VERSION 5.8 ;
BUSBITCHARS "[]" ;
DIVIDERCHAR "/" ;
UNITS
    DATABASE MICRONS 1000 ;
END UNITS

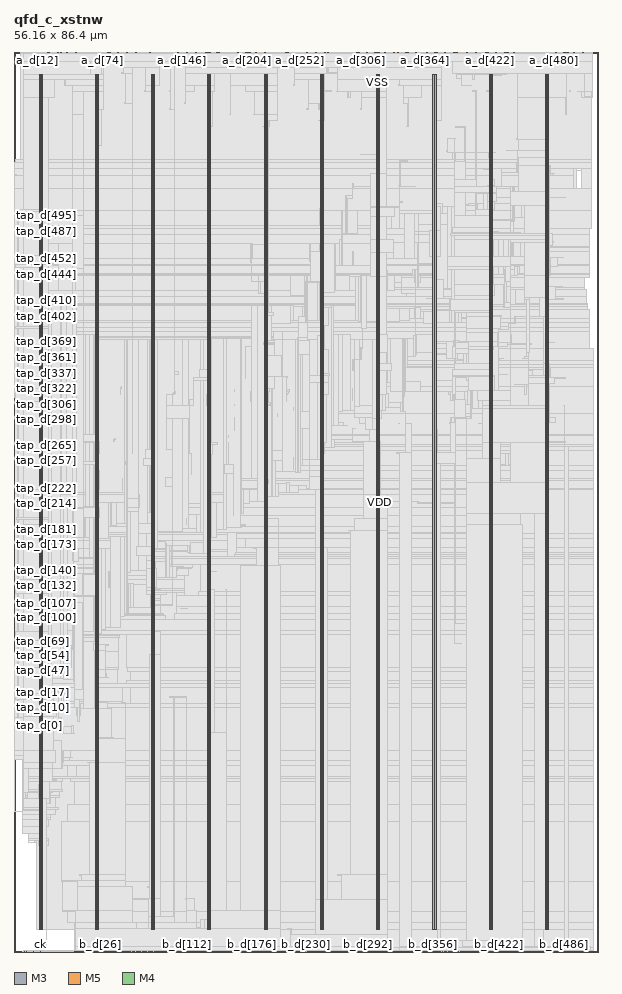
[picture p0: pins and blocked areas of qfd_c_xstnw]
MACRO qfd_c_xstnw
  FOREIGN qfd_c_xstnw 0 0 ;
  CLASS BLOCK ;
  SIZE 56.16 BY 86.4 ;
  PIN a_d[0]
    DIRECTION OUTPUT ;
    USE SIGNAL ;
    PORT
      LAYER M3 ;
        RECT  0.576 86.362 0.594 86.4 ;
    END
  END a_d[0]
  PIN a_d[100]
    DIRECTION OUTPUT ;
    USE SIGNAL ;
    PORT
      LAYER M3 ;
        RECT  11.268 86.362 11.286 86.4 ;
    END
  END a_d[100]
  PIN a_d[101]
    DIRECTION OUTPUT ;
    USE SIGNAL ;
    PORT
      LAYER M5 ;
        RECT  11.376 86.316 11.4 86.4 ;
    END
  END a_d[101]
  PIN a_d[102]
    DIRECTION OUTPUT ;
    USE SIGNAL ;
    PORT
      LAYER M3 ;
        RECT  11.484 86.362 11.502 86.4 ;
    END
  END a_d[102]
  PIN a_d[103]
    DIRECTION OUTPUT ;
    USE SIGNAL ;
    PORT
      LAYER M5 ;
        RECT  11.568 86.316 11.592 86.4 ;
    END
  END a_d[103]
  PIN a_d[104]
    DIRECTION OUTPUT ;
    USE SIGNAL ;
    PORT
      LAYER M3 ;
        RECT  11.7 86.362 11.718 86.4 ;
    END
  END a_d[104]
  PIN a_d[105]
    DIRECTION OUTPUT ;
    USE SIGNAL ;
    PORT
      LAYER M5 ;
        RECT  11.808 86.316 11.832 86.4 ;
    END
  END a_d[105]
  PIN a_d[106]
    DIRECTION OUTPUT ;
    USE SIGNAL ;
    PORT
      LAYER M3 ;
        RECT  11.916 86.362 11.934 86.4 ;
    END
  END a_d[106]
  PIN a_d[107]
    DIRECTION OUTPUT ;
    USE SIGNAL ;
    PORT
      LAYER M5 ;
        RECT  12 86.316 12.024 86.4 ;
    END
  END a_d[107]
  PIN a_d[108]
    DIRECTION OUTPUT ;
    USE SIGNAL ;
    PORT
      LAYER M3 ;
        RECT  12.096 86.362 12.114 86.4 ;
    END
  END a_d[108]
  PIN a_d[109]
    DIRECTION OUTPUT ;
    USE SIGNAL ;
    PORT
      LAYER M5 ;
        RECT  12.24 86.316 12.264 86.4 ;
    END
  END a_d[109]
  PIN a_d[10]
    DIRECTION OUTPUT ;
    USE SIGNAL ;
    PORT
      LAYER M3 ;
        RECT  1.656 86.362 1.674 86.4 ;
    END
  END a_d[10]
  PIN a_d[110]
    DIRECTION OUTPUT ;
    USE SIGNAL ;
    PORT
      LAYER M3 ;
        RECT  12.312 86.362 12.33 86.4 ;
    END
  END a_d[110]
  PIN a_d[111]
    DIRECTION OUTPUT ;
    USE SIGNAL ;
    PORT
      LAYER M5 ;
        RECT  12.432 86.316 12.456 86.4 ;
    END
  END a_d[111]
  PIN a_d[112]
    DIRECTION OUTPUT ;
    USE SIGNAL ;
    PORT
      LAYER M3 ;
        RECT  12.528 86.362 12.546 86.4 ;
    END
  END a_d[112]
  PIN a_d[113]
    DIRECTION OUTPUT ;
    USE SIGNAL ;
    PORT
      LAYER M5 ;
        RECT  12.624 86.316 12.648 86.4 ;
    END
  END a_d[113]
  PIN a_d[114]
    DIRECTION OUTPUT ;
    USE SIGNAL ;
    PORT
      LAYER M3 ;
        RECT  12.744 86.362 12.762 86.4 ;
    END
  END a_d[114]
  PIN a_d[115]
    DIRECTION OUTPUT ;
    USE SIGNAL ;
    PORT
      LAYER M5 ;
        RECT  12.864 86.316 12.888 86.4 ;
    END
  END a_d[115]
  PIN a_d[116]
    DIRECTION OUTPUT ;
    USE SIGNAL ;
    PORT
      LAYER M3 ;
        RECT  12.96 86.362 12.978 86.4 ;
    END
  END a_d[116]
  PIN a_d[117]
    DIRECTION OUTPUT ;
    USE SIGNAL ;
    PORT
      LAYER M5 ;
        RECT  13.056 86.316 13.08 86.4 ;
    END
  END a_d[117]
  PIN a_d[118]
    DIRECTION OUTPUT ;
    USE SIGNAL ;
    PORT
      LAYER M3 ;
        RECT  13.176 86.362 13.194 86.4 ;
    END
  END a_d[118]
  PIN a_d[119]
    DIRECTION OUTPUT ;
    USE SIGNAL ;
    PORT
      LAYER M5 ;
        RECT  13.296 86.316 13.32 86.4 ;
    END
  END a_d[119]
  PIN a_d[11]
    DIRECTION OUTPUT ;
    USE SIGNAL ;
    PORT
      LAYER M5 ;
        RECT  1.776 86.316 1.8 86.4 ;
    END
  END a_d[11]
  PIN a_d[120]
    DIRECTION OUTPUT ;
    USE SIGNAL ;
    PORT
      LAYER M3 ;
        RECT  13.392 86.362 13.41 86.4 ;
    END
  END a_d[120]
  PIN a_d[121]
    DIRECTION OUTPUT ;
    USE SIGNAL ;
    PORT
      LAYER M5 ;
        RECT  13.488 86.316 13.512 86.4 ;
    END
  END a_d[121]
  PIN a_d[122]
    DIRECTION OUTPUT ;
    USE SIGNAL ;
    PORT
      LAYER M3 ;
        RECT  13.608 86.362 13.626 86.4 ;
    END
  END a_d[122]
  PIN a_d[123]
    DIRECTION OUTPUT ;
    USE SIGNAL ;
    PORT
      LAYER M5 ;
        RECT  13.728 86.316 13.752 86.4 ;
    END
  END a_d[123]
  PIN a_d[124]
    DIRECTION OUTPUT ;
    USE SIGNAL ;
    PORT
      LAYER M3 ;
        RECT  13.824 86.362 13.842 86.4 ;
    END
  END a_d[124]
  PIN a_d[125]
    DIRECTION OUTPUT ;
    USE SIGNAL ;
    PORT
      LAYER M5 ;
        RECT  13.92 86.316 13.944 86.4 ;
    END
  END a_d[125]
  PIN a_d[126]
    DIRECTION OUTPUT ;
    USE SIGNAL ;
    PORT
      LAYER M3 ;
        RECT  14.04 86.362 14.058 86.4 ;
    END
  END a_d[126]
  PIN a_d[127]
    DIRECTION OUTPUT ;
    USE SIGNAL ;
    PORT
      LAYER M5 ;
        RECT  14.16 86.316 14.184 86.4 ;
    END
  END a_d[127]
  PIN a_d[128]
    DIRECTION OUTPUT ;
    USE SIGNAL ;
    PORT
      LAYER M3 ;
        RECT  14.256 86.362 14.274 86.4 ;
    END
  END a_d[128]
  PIN a_d[129]
    DIRECTION OUTPUT ;
    USE SIGNAL ;
    PORT
      LAYER M5 ;
        RECT  14.352 86.316 14.376 86.4 ;
    END
  END a_d[129]
  PIN a_d[12]
    DIRECTION OUTPUT ;
    USE SIGNAL ;
    PORT
      LAYER M3 ;
        RECT  1.872 86.362 1.89 86.4 ;
    END
  END a_d[12]
  PIN a_d[130]
    DIRECTION OUTPUT ;
    USE SIGNAL ;
    PORT
      LAYER M3 ;
        RECT  14.472 86.362 14.49 86.4 ;
    END
  END a_d[130]
  PIN a_d[131]
    DIRECTION OUTPUT ;
    USE SIGNAL ;
    PORT
      LAYER M5 ;
        RECT  14.544 86.316 14.568 86.4 ;
    END
  END a_d[131]
  PIN a_d[132]
    DIRECTION OUTPUT ;
    USE SIGNAL ;
    PORT
      LAYER M3 ;
        RECT  14.688 86.362 14.706 86.4 ;
    END
  END a_d[132]
  PIN a_d[133]
    DIRECTION OUTPUT ;
    USE SIGNAL ;
    PORT
      LAYER M5 ;
        RECT  14.784 86.316 14.808 86.4 ;
    END
  END a_d[133]
  PIN a_d[134]
    DIRECTION OUTPUT ;
    USE SIGNAL ;
    PORT
      LAYER M3 ;
        RECT  14.904 86.362 14.922 86.4 ;
    END
  END a_d[134]
  PIN a_d[135]
    DIRECTION OUTPUT ;
    USE SIGNAL ;
    PORT
      LAYER M5 ;
        RECT  14.976 86.316 15 86.4 ;
    END
  END a_d[135]
  PIN a_d[136]
    DIRECTION OUTPUT ;
    USE SIGNAL ;
    PORT
      LAYER M3 ;
        RECT  15.12 86.362 15.138 86.4 ;
    END
  END a_d[136]
  PIN a_d[137]
    DIRECTION OUTPUT ;
    USE SIGNAL ;
    PORT
      LAYER M5 ;
        RECT  15.216 86.316 15.24 86.4 ;
    END
  END a_d[137]
  PIN a_d[138]
    DIRECTION OUTPUT ;
    USE SIGNAL ;
    PORT
      LAYER M3 ;
        RECT  15.3 86.362 15.318 86.4 ;
    END
  END a_d[138]
  PIN a_d[139]
    DIRECTION OUTPUT ;
    USE SIGNAL ;
    PORT
      LAYER M5 ;
        RECT  15.408 86.316 15.432 86.4 ;
    END
  END a_d[139]
  PIN a_d[13]
    DIRECTION OUTPUT ;
    USE SIGNAL ;
    PORT
      LAYER M5 ;
        RECT  1.968 86.316 1.992 86.4 ;
    END
  END a_d[13]
  PIN a_d[140]
    DIRECTION OUTPUT ;
    USE SIGNAL ;
    PORT
      LAYER M3 ;
        RECT  15.516 86.362 15.534 86.4 ;
    END
  END a_d[140]
  PIN a_d[141]
    DIRECTION OUTPUT ;
    USE SIGNAL ;
    PORT
      LAYER M5 ;
        RECT  15.648 86.316 15.672 86.4 ;
    END
  END a_d[141]
  PIN a_d[142]
    DIRECTION OUTPUT ;
    USE SIGNAL ;
    PORT
      LAYER M3 ;
        RECT  15.732 86.362 15.75 86.4 ;
    END
  END a_d[142]
  PIN a_d[143]
    DIRECTION OUTPUT ;
    USE SIGNAL ;
    PORT
      LAYER M5 ;
        RECT  15.84 86.316 15.864 86.4 ;
    END
  END a_d[143]
  PIN a_d[144]
    DIRECTION OUTPUT ;
    USE SIGNAL ;
    PORT
      LAYER M3 ;
        RECT  15.948 86.362 15.966 86.4 ;
    END
  END a_d[144]
  PIN a_d[145]
    DIRECTION OUTPUT ;
    USE SIGNAL ;
    PORT
      LAYER M5 ;
        RECT  16.08 86.316 16.104 86.4 ;
    END
  END a_d[145]
  PIN a_d[146]
    DIRECTION OUTPUT ;
    USE SIGNAL ;
    PORT
      LAYER M3 ;
        RECT  16.164 86.362 16.182 86.4 ;
    END
  END a_d[146]
  PIN a_d[147]
    DIRECTION OUTPUT ;
    USE SIGNAL ;
    PORT
      LAYER M5 ;
        RECT  16.272 86.316 16.296 86.4 ;
    END
  END a_d[147]
  PIN a_d[148]
    DIRECTION OUTPUT ;
    USE SIGNAL ;
    PORT
      LAYER M3 ;
        RECT  16.38 86.362 16.398 86.4 ;
    END
  END a_d[148]
  PIN a_d[149]
    DIRECTION OUTPUT ;
    USE SIGNAL ;
    PORT
      LAYER M5 ;
        RECT  16.464 86.316 16.488 86.4 ;
    END
  END a_d[149]
  PIN a_d[14]
    DIRECTION OUTPUT ;
    USE SIGNAL ;
    PORT
      LAYER M3 ;
        RECT  2.088 86.362 2.106 86.4 ;
    END
  END a_d[14]
  PIN a_d[150]
    DIRECTION OUTPUT ;
    USE SIGNAL ;
    PORT
      LAYER M3 ;
        RECT  16.596 86.362 16.614 86.4 ;
    END
  END a_d[150]
  PIN a_d[151]
    DIRECTION OUTPUT ;
    USE SIGNAL ;
    PORT
      LAYER M5 ;
        RECT  16.704 86.316 16.728 86.4 ;
    END
  END a_d[151]
  PIN a_d[152]
    DIRECTION OUTPUT ;
    USE SIGNAL ;
    PORT
      LAYER M3 ;
        RECT  16.812 86.362 16.83 86.4 ;
    END
  END a_d[152]
  PIN a_d[153]
    DIRECTION OUTPUT ;
    USE SIGNAL ;
    PORT
      LAYER M5 ;
        RECT  16.896 86.316 16.92 86.4 ;
    END
  END a_d[153]
  PIN a_d[154]
    DIRECTION OUTPUT ;
    USE SIGNAL ;
    PORT
      LAYER M3 ;
        RECT  17.028 86.362 17.046 86.4 ;
    END
  END a_d[154]
  PIN a_d[155]
    DIRECTION OUTPUT ;
    USE SIGNAL ;
    PORT
      LAYER M5 ;
        RECT  17.136 86.316 17.16 86.4 ;
    END
  END a_d[155]
  PIN a_d[156]
    DIRECTION OUTPUT ;
    USE SIGNAL ;
    PORT
      LAYER M3 ;
        RECT  17.244 86.362 17.262 86.4 ;
    END
  END a_d[156]
  PIN a_d[157]
    DIRECTION OUTPUT ;
    USE SIGNAL ;
    PORT
      LAYER M5 ;
        RECT  17.328 86.316 17.352 86.4 ;
    END
  END a_d[157]
  PIN a_d[158]
    DIRECTION OUTPUT ;
    USE SIGNAL ;
    PORT
      LAYER M3 ;
        RECT  17.46 86.362 17.478 86.4 ;
    END
  END a_d[158]
  PIN a_d[159]
    DIRECTION OUTPUT ;
    USE SIGNAL ;
    PORT
      LAYER M5 ;
        RECT  17.568 86.316 17.592 86.4 ;
    END
  END a_d[159]
  PIN a_d[15]
    DIRECTION OUTPUT ;
    USE SIGNAL ;
    PORT
      LAYER M5 ;
        RECT  2.16 86.316 2.184 86.4 ;
    END
  END a_d[15]
  PIN a_d[160]
    DIRECTION OUTPUT ;
    USE SIGNAL ;
    PORT
      LAYER M3 ;
        RECT  17.676 86.362 17.694 86.4 ;
    END
  END a_d[160]
  PIN a_d[161]
    DIRECTION OUTPUT ;
    USE SIGNAL ;
    PORT
      LAYER M5 ;
        RECT  17.76 86.316 17.784 86.4 ;
    END
  END a_d[161]
  PIN a_d[162]
    DIRECTION OUTPUT ;
    USE SIGNAL ;
    PORT
      LAYER M3 ;
        RECT  17.892 86.362 17.91 86.4 ;
    END
  END a_d[162]
  PIN a_d[163]
    DIRECTION OUTPUT ;
    USE SIGNAL ;
    PORT
      LAYER M5 ;
        RECT  18 86.316 18.024 86.4 ;
    END
  END a_d[163]
  PIN a_d[164]
    DIRECTION OUTPUT ;
    USE SIGNAL ;
    PORT
      LAYER M3 ;
        RECT  18.108 86.362 18.126 86.4 ;
    END
  END a_d[164]
  PIN a_d[165]
    DIRECTION OUTPUT ;
    USE SIGNAL ;
    PORT
      LAYER M5 ;
        RECT  18.192 86.316 18.216 86.4 ;
    END
  END a_d[165]
  PIN a_d[166]
    DIRECTION OUTPUT ;
    USE SIGNAL ;
    PORT
      LAYER M3 ;
        RECT  18.288 86.362 18.306 86.4 ;
    END
  END a_d[166]
  PIN a_d[167]
    DIRECTION OUTPUT ;
    USE SIGNAL ;
    PORT
      LAYER M5 ;
        RECT  18.432 86.316 18.456 86.4 ;
    END
  END a_d[167]
  PIN a_d[168]
    DIRECTION OUTPUT ;
    USE SIGNAL ;
    PORT
      LAYER M3 ;
        RECT  18.504 86.362 18.522 86.4 ;
    END
  END a_d[168]
  PIN a_d[169]
    DIRECTION OUTPUT ;
    USE SIGNAL ;
    PORT
      LAYER M5 ;
        RECT  18.624 86.316 18.648 86.4 ;
    END
  END a_d[169]
  PIN a_d[16]
    DIRECTION OUTPUT ;
    USE SIGNAL ;
    PORT
      LAYER M3 ;
        RECT  2.304 86.362 2.322 86.4 ;
    END
  END a_d[16]
  PIN a_d[170]
    DIRECTION OUTPUT ;
    USE SIGNAL ;
    PORT
      LAYER M3 ;
        RECT  18.72 86.362 18.738 86.4 ;
    END
  END a_d[170]
  PIN a_d[171]
    DIRECTION OUTPUT ;
    USE SIGNAL ;
    PORT
      LAYER M5 ;
        RECT  18.816 86.316 18.84 86.4 ;
    END
  END a_d[171]
  PIN a_d[172]
    DIRECTION OUTPUT ;
    USE SIGNAL ;
    PORT
      LAYER M3 ;
        RECT  18.936 86.362 18.954 86.4 ;
    END
  END a_d[172]
  PIN a_d[173]
    DIRECTION OUTPUT ;
    USE SIGNAL ;
    PORT
      LAYER M5 ;
        RECT  19.056 86.316 19.08 86.4 ;
    END
  END a_d[173]
  PIN a_d[174]
    DIRECTION OUTPUT ;
    USE SIGNAL ;
    PORT
      LAYER M3 ;
        RECT  19.152 86.362 19.17 86.4 ;
    END
  END a_d[174]
  PIN a_d[175]
    DIRECTION OUTPUT ;
    USE SIGNAL ;
    PORT
      LAYER M5 ;
        RECT  19.248 86.316 19.272 86.4 ;
    END
  END a_d[175]
  PIN a_d[176]
    DIRECTION OUTPUT ;
    USE SIGNAL ;
    PORT
      LAYER M3 ;
        RECT  19.368 86.362 19.386 86.4 ;
    END
  END a_d[176]
  PIN a_d[177]
    DIRECTION OUTPUT ;
    USE SIGNAL ;
    PORT
      LAYER M5 ;
        RECT  19.488 86.316 19.512 86.4 ;
    END
  END a_d[177]
  PIN a_d[178]
    DIRECTION OUTPUT ;
    USE SIGNAL ;
    PORT
      LAYER M3 ;
        RECT  19.584 86.362 19.602 86.4 ;
    END
  END a_d[178]
  PIN a_d[179]
    DIRECTION OUTPUT ;
    USE SIGNAL ;
    PORT
      LAYER M5 ;
        RECT  19.68 86.316 19.704 86.4 ;
    END
  END a_d[179]
  PIN a_d[17]
    DIRECTION OUTPUT ;
    USE SIGNAL ;
    PORT
      LAYER M5 ;
        RECT  2.4 86.316 2.424 86.4 ;
    END
  END a_d[17]
  PIN a_d[180]
    DIRECTION OUTPUT ;
    USE SIGNAL ;
    PORT
      LAYER M3 ;
        RECT  19.8 86.362 19.818 86.4 ;
    END
  END a_d[180]
  PIN a_d[181]
    DIRECTION OUTPUT ;
    USE SIGNAL ;
    PORT
      LAYER M5 ;
        RECT  19.92 86.316 19.944 86.4 ;
    END
  END a_d[181]
  PIN a_d[182]
    DIRECTION OUTPUT ;
    USE SIGNAL ;
    PORT
      LAYER M3 ;
        RECT  20.016 86.362 20.034 86.4 ;
    END
  END a_d[182]
  PIN a_d[183]
    DIRECTION OUTPUT ;
    USE SIGNAL ;
    PORT
      LAYER M5 ;
        RECT  20.112 86.316 20.136 86.4 ;
    END
  END a_d[183]
  PIN a_d[184]
    DIRECTION OUTPUT ;
    USE SIGNAL ;
    PORT
      LAYER M3 ;
        RECT  20.232 86.362 20.25 86.4 ;
    END
  END a_d[184]
  PIN a_d[185]
    DIRECTION OUTPUT ;
    USE SIGNAL ;
    PORT
      LAYER M5 ;
        RECT  20.352 86.316 20.376 86.4 ;
    END
  END a_d[185]
  PIN a_d[186]
    DIRECTION OUTPUT ;
    USE SIGNAL ;
    PORT
      LAYER M3 ;
        RECT  20.448 86.362 20.466 86.4 ;
    END
  END a_d[186]
  PIN a_d[187]
    DIRECTION OUTPUT ;
    USE SIGNAL ;
    PORT
      LAYER M5 ;
        RECT  20.544 86.316 20.568 86.4 ;
    END
  END a_d[187]
  PIN a_d[188]
    DIRECTION OUTPUT ;
    USE SIGNAL ;
    PORT
      LAYER M3 ;
        RECT  20.664 86.362 20.682 86.4 ;
    END
  END a_d[188]
  PIN a_d[189]
    DIRECTION OUTPUT ;
    USE SIGNAL ;
    PORT
      LAYER M5 ;
        RECT  20.736 86.316 20.76 86.4 ;
    END
  END a_d[189]
  PIN a_d[18]
    DIRECTION OUTPUT ;
    USE SIGNAL ;
    PORT
      LAYER M3 ;
        RECT  2.52 86.362 2.538 86.4 ;
    END
  END a_d[18]
  PIN a_d[190]
    DIRECTION OUTPUT ;
    USE SIGNAL ;
    PORT
      LAYER M3 ;
        RECT  20.88 86.362 20.898 86.4 ;
    END
  END a_d[190]
  PIN a_d[191]
    DIRECTION OUTPUT ;
    USE SIGNAL ;
    PORT
      LAYER M5 ;
        RECT  20.976 86.316 21 86.4 ;
    END
  END a_d[191]
  PIN a_d[192]
    DIRECTION OUTPUT ;
    USE SIGNAL ;
    PORT
      LAYER M3 ;
        RECT  21.096 86.362 21.114 86.4 ;
    END
  END a_d[192]
  PIN a_d[193]
    DIRECTION OUTPUT ;
    USE SIGNAL ;
    PORT
      LAYER M5 ;
        RECT  21.168 86.316 21.192 86.4 ;
    END
  END a_d[193]
  PIN a_d[194]
    DIRECTION OUTPUT ;
    USE SIGNAL ;
    PORT
      LAYER M3 ;
        RECT  21.276 86.362 21.294 86.4 ;
    END
  END a_d[194]
  PIN a_d[195]
    DIRECTION OUTPUT ;
    USE SIGNAL ;
    PORT
      LAYER M5 ;
        RECT  21.408 86.316 21.432 86.4 ;
    END
  END a_d[195]
  PIN a_d[196]
    DIRECTION OUTPUT ;
    USE SIGNAL ;
    PORT
      LAYER M3 ;
        RECT  21.492 86.362 21.51 86.4 ;
    END
  END a_d[196]
  PIN a_d[197]
    DIRECTION OUTPUT ;
    USE SIGNAL ;
    PORT
      LAYER M5 ;
        RECT  21.6 86.316 21.624 86.4 ;
    END
  END a_d[197]
  PIN a_d[198]
    DIRECTION OUTPUT ;
    USE SIGNAL ;
    PORT
      LAYER M3 ;
        RECT  21.708 86.362 21.726 86.4 ;
    END
  END a_d[198]
  PIN a_d[199]
    DIRECTION OUTPUT ;
    USE SIGNAL ;
    PORT
      LAYER M5 ;
        RECT  21.84 86.316 21.864 86.4 ;
    END
  END a_d[199]
  PIN a_d[19]
    DIRECTION OUTPUT ;
    USE SIGNAL ;
    PORT
      LAYER M5 ;
        RECT  2.592 86.316 2.616 86.4 ;
    END
  END a_d[19]
  PIN a_d[1]
    DIRECTION OUTPUT ;
    USE SIGNAL ;
    PORT
      LAYER M5 ;
        RECT  0.672 86.316 0.696 86.4 ;
    END
  END a_d[1]
  PIN a_d[200]
    DIRECTION OUTPUT ;
    USE SIGNAL ;
    PORT
      LAYER M3 ;
        RECT  21.924 86.362 21.942 86.4 ;
    END
  END a_d[200]
  PIN a_d[201]
    DIRECTION OUTPUT ;
    USE SIGNAL ;
    PORT
      LAYER M5 ;
        RECT  22.032 86.316 22.056 86.4 ;
    END
  END a_d[201]
  PIN a_d[202]
    DIRECTION OUTPUT ;
    USE SIGNAL ;
    PORT
      LAYER M3 ;
        RECT  22.14 86.362 22.158 86.4 ;
    END
  END a_d[202]
  PIN a_d[203]
    DIRECTION OUTPUT ;
    USE SIGNAL ;
    PORT
      LAYER M5 ;
        RECT  22.272 86.316 22.296 86.4 ;
    END
  END a_d[203]
  PIN a_d[204]
    DIRECTION OUTPUT ;
    USE SIGNAL ;
    PORT
      LAYER M3 ;
        RECT  22.356 86.362 22.374 86.4 ;
    END
  END a_d[204]
  PIN a_d[205]
    DIRECTION OUTPUT ;
    USE SIGNAL ;
    PORT
      LAYER M5 ;
        RECT  22.464 86.316 22.488 86.4 ;
    END
  END a_d[205]
  PIN a_d[206]
    DIRECTION OUTPUT ;
    USE SIGNAL ;
    PORT
      LAYER M3 ;
        RECT  22.572 86.362 22.59 86.4 ;
    END
  END a_d[206]
  PIN a_d[207]
    DIRECTION OUTPUT ;
    USE SIGNAL ;
    PORT
      LAYER M5 ;
        RECT  22.656 86.316 22.68 86.4 ;
    END
  END a_d[207]
  PIN a_d[208]
    DIRECTION OUTPUT ;
    USE SIGNAL ;
    PORT
      LAYER M3 ;
        RECT  22.788 86.362 22.806 86.4 ;
    END
  END a_d[208]
  PIN a_d[209]
    DIRECTION OUTPUT ;
    USE SIGNAL ;
    PORT
      LAYER M5 ;
        RECT  22.896 86.316 22.92 86.4 ;
    END
  END a_d[209]
  PIN a_d[20]
    DIRECTION OUTPUT ;
    USE SIGNAL ;
    PORT
      LAYER M3 ;
        RECT  2.736 86.362 2.754 86.4 ;
    END
  END a_d[20]
  PIN a_d[210]
    DIRECTION OUTPUT ;
    USE SIGNAL ;
    PORT
      LAYER M3 ;
        RECT  23.004 86.362 23.022 86.4 ;
    END
  END a_d[210]
  PIN a_d[211]
    DIRECTION OUTPUT ;
    USE SIGNAL ;
    PORT
      LAYER M5 ;
        RECT  23.088 86.316 23.112 86.4 ;
    END
  END a_d[211]
  PIN a_d[212]
    DIRECTION OUTPUT ;
    USE SIGNAL ;
    PORT
      LAYER M3 ;
        RECT  23.22 86.362 23.238 86.4 ;
    END
  END a_d[212]
  PIN a_d[213]
    DIRECTION OUTPUT ;
    USE SIGNAL ;
    PORT
      LAYER M5 ;
        RECT  23.328 86.316 23.352 86.4 ;
    END
  END a_d[213]
  PIN a_d[214]
    DIRECTION OUTPUT ;
    USE SIGNAL ;
    PORT
      LAYER M3 ;
        RECT  23.436 86.362 23.454 86.4 ;
    END
  END a_d[214]
  PIN a_d[215]
    DIRECTION OUTPUT ;
    USE SIGNAL ;
    PORT
      LAYER M5 ;
        RECT  23.52 86.316 23.544 86.4 ;
    END
  END a_d[215]
  PIN a_d[216]
    DIRECTION OUTPUT ;
    USE SIGNAL ;
    PORT
      LAYER M3 ;
        RECT  23.652 86.362 23.67 86.4 ;
    END
  END a_d[216]
  PIN a_d[217]
    DIRECTION OUTPUT ;
    USE SIGNAL ;
    PORT
      LAYER M5 ;
        RECT  23.76 86.316 23.784 86.4 ;
    END
  END a_d[217]
  PIN a_d[218]
    DIRECTION OUTPUT ;
    USE SIGNAL ;
    PORT
      LAYER M3 ;
        RECT  23.868 86.362 23.886 86.4 ;
    END
  END a_d[218]
  PIN a_d[219]
    DIRECTION OUTPUT ;
    USE SIGNAL ;
    PORT
      LAYER M5 ;
        RECT  23.952 86.316 23.976 86.4 ;
    END
  END a_d[219]
  PIN a_d[21]
    DIRECTION OUTPUT ;
    USE SIGNAL ;
    PORT
      LAYER M5 ;
        RECT  2.832 86.316 2.856 86.4 ;
    END
  END a_d[21]
  PIN a_d[220]
    DIRECTION OUTPUT ;
    USE SIGNAL ;
    PORT
      LAYER M3 ;
        RECT  24.084 86.362 24.102 86.4 ;
    END
  END a_d[220]
  PIN a_d[221]
    DIRECTION OUTPUT ;
    USE SIGNAL ;
    PORT
      LAYER M5 ;
        RECT  24.192 86.316 24.216 86.4 ;
    END
  END a_d[221]
  PIN a_d[222]
    DIRECTION OUTPUT ;
    USE SIGNAL ;
    PORT
      LAYER M3 ;
        RECT  24.3 86.362 24.318 86.4 ;
    END
  END a_d[222]
  PIN a_d[223]
    DIRECTION OUTPUT ;
    USE SIGNAL ;
    PORT
      LAYER M5 ;
        RECT  24.384 86.316 24.408 86.4 ;
    END
  END a_d[223]
  PIN a_d[224]
    DIRECTION OUTPUT ;
    USE SIGNAL ;
    PORT
      LAYER M3 ;
        RECT  24.48 86.362 24.498 86.4 ;
    END
  END a_d[224]
  PIN a_d[225]
    DIRECTION OUTPUT ;
    USE SIGNAL ;
    PORT
      LAYER M5 ;
        RECT  24.576 86.316 24.6 86.4 ;
    END
  END a_d[225]
  PIN a_d[226]
    DIRECTION OUTPUT ;
    USE SIGNAL ;
    PORT
      LAYER M3 ;
        RECT  24.696 86.362 24.714 86.4 ;
    END
  END a_d[226]
  PIN a_d[227]
    DIRECTION OUTPUT ;
    USE SIGNAL ;
    PORT
      LAYER M5 ;
        RECT  24.816 86.316 24.84 86.4 ;
    END
  END a_d[227]
  PIN a_d[228]
    DIRECTION OUTPUT ;
    USE SIGNAL ;
    PORT
      LAYER M3 ;
        RECT  24.912 86.362 24.93 86.4 ;
    END
  END a_d[228]
  PIN a_d[229]
    DIRECTION OUTPUT ;
    USE SIGNAL ;
    PORT
      LAYER M5 ;
        RECT  25.008 86.316 25.032 86.4 ;
    END
  END a_d[229]
  PIN a_d[22]
    DIRECTION OUTPUT ;
    USE SIGNAL ;
    PORT
      LAYER M3 ;
        RECT  2.916 86.362 2.934 86.4 ;
    END
  END a_d[22]
  PIN a_d[230]
    DIRECTION OUTPUT ;
    USE SIGNAL ;
    PORT
      LAYER M3 ;
        RECT  25.128 86.362 25.146 86.4 ;
    END
  END a_d[230]
  PIN a_d[231]
    DIRECTION OUTPUT ;
    USE SIGNAL ;
    PORT
      LAYER M5 ;
        RECT  25.248 86.316 25.272 86.4 ;
    END
  END a_d[231]
  PIN a_d[232]
    DIRECTION OUTPUT ;
    USE SIGNAL ;
    PORT
      LAYER M3 ;
        RECT  25.344 86.362 25.362 86.4 ;
    END
  END a_d[232]
  PIN a_d[233]
    DIRECTION OUTPUT ;
    USE SIGNAL ;
    PORT
      LAYER M5 ;
        RECT  25.44 86.316 25.464 86.4 ;
    END
  END a_d[233]
  PIN a_d[234]
    DIRECTION OUTPUT ;
    USE SIGNAL ;
    PORT
      LAYER M3 ;
        RECT  25.56 86.362 25.578 86.4 ;
    END
  END a_d[234]
  PIN a_d[235]
    DIRECTION OUTPUT ;
    USE SIGNAL ;
    PORT
      LAYER M5 ;
        RECT  25.68 86.316 25.704 86.4 ;
    END
  END a_d[235]
  PIN a_d[236]
    DIRECTION OUTPUT ;
    USE SIGNAL ;
    PORT
      LAYER M3 ;
        RECT  25.776 86.362 25.794 86.4 ;
    END
  END a_d[236]
  PIN a_d[237]
    DIRECTION OUTPUT ;
    USE SIGNAL ;
    PORT
      LAYER M5 ;
        RECT  25.872 86.316 25.896 86.4 ;
    END
  END a_d[237]
  PIN a_d[238]
    DIRECTION OUTPUT ;
    USE SIGNAL ;
    PORT
      LAYER M3 ;
        RECT  25.992 86.362 26.01 86.4 ;
    END
  END a_d[238]
  PIN a_d[239]
    DIRECTION OUTPUT ;
    USE SIGNAL ;
    PORT
      LAYER M5 ;
        RECT  26.112 86.316 26.136 86.4 ;
    END
  END a_d[239]
  PIN a_d[23]
    DIRECTION OUTPUT ;
    USE SIGNAL ;
    PORT
      LAYER M5 ;
        RECT  3.024 86.316 3.048 86.4 ;
    END
  END a_d[23]
  PIN a_d[240]
    DIRECTION OUTPUT ;
    USE SIGNAL ;
    PORT
      LAYER M3 ;
        RECT  26.208 86.362 26.226 86.4 ;
    END
  END a_d[240]
  PIN a_d[241]
    DIRECTION OUTPUT ;
    USE SIGNAL ;
    PORT
      LAYER M5 ;
        RECT  26.304 86.316 26.328 86.4 ;
    END
  END a_d[241]
  PIN a_d[242]
    DIRECTION OUTPUT ;
    USE SIGNAL ;
    PORT
      LAYER M3 ;
        RECT  26.424 86.362 26.442 86.4 ;
    END
  END a_d[242]
  PIN a_d[243]
    DIRECTION OUTPUT ;
    USE SIGNAL ;
    PORT
      LAYER M5 ;
        RECT  26.544 86.316 26.568 86.4 ;
    END
  END a_d[243]
  PIN a_d[244]
    DIRECTION OUTPUT ;
    USE SIGNAL ;
    PORT
      LAYER M3 ;
        RECT  26.64 86.362 26.658 86.4 ;
    END
  END a_d[244]
  PIN a_d[245]
    DIRECTION OUTPUT ;
    USE SIGNAL ;
    PORT
      LAYER M5 ;
        RECT  26.736 86.316 26.76 86.4 ;
    END
  END a_d[245]
  PIN a_d[246]
    DIRECTION OUTPUT ;
    USE SIGNAL ;
    PORT
      LAYER M3 ;
        RECT  26.856 86.362 26.874 86.4 ;
    END
  END a_d[246]
  PIN a_d[247]
    DIRECTION OUTPUT ;
    USE SIGNAL ;
    PORT
      LAYER M5 ;
        RECT  26.928 86.316 26.952 86.4 ;
    END
  END a_d[247]
  PIN a_d[248]
    DIRECTION OUTPUT ;
    USE SIGNAL ;
    PORT
      LAYER M3 ;
        RECT  27.072 86.362 27.09 86.4 ;
    END
  END a_d[248]
  PIN a_d[249]
    DIRECTION OUTPUT ;
    USE SIGNAL ;
    PORT
      LAYER M5 ;
        RECT  27.168 86.316 27.192 86.4 ;
    END
  END a_d[249]
  PIN a_d[24]
    DIRECTION OUTPUT ;
    USE SIGNAL ;
    PORT
      LAYER M3 ;
        RECT  3.132 86.362 3.15 86.4 ;
    END
  END a_d[24]
  PIN a_d[250]
    DIRECTION OUTPUT ;
    USE SIGNAL ;
    PORT
      LAYER M3 ;
        RECT  27.288 86.362 27.306 86.4 ;
    END
  END a_d[250]
  PIN a_d[251]
    DIRECTION OUTPUT ;
    USE SIGNAL ;
    PORT
      LAYER M5 ;
        RECT  27.36 86.316 27.384 86.4 ;
    END
  END a_d[251]
  PIN a_d[252]
    DIRECTION OUTPUT ;
    USE SIGNAL ;
    PORT
      LAYER M3 ;
        RECT  27.468 86.362 27.486 86.4 ;
    END
  END a_d[252]
  PIN a_d[253]
    DIRECTION OUTPUT ;
    USE SIGNAL ;
    PORT
      LAYER M5 ;
        RECT  27.6 86.316 27.624 86.4 ;
    END
  END a_d[253]
  PIN a_d[254]
    DIRECTION OUTPUT ;
    USE SIGNAL ;
    PORT
      LAYER M3 ;
        RECT  27.684 86.362 27.702 86.4 ;
    END
  END a_d[254]
  PIN a_d[255]
    DIRECTION OUTPUT ;
    USE SIGNAL ;
    PORT
      LAYER M5 ;
        RECT  27.792 86.316 27.816 86.4 ;
    END
  END a_d[255]
  PIN a_d[256]
    DIRECTION OUTPUT ;
    USE SIGNAL ;
    PORT
      LAYER M3 ;
        RECT  27.9 86.362 27.918 86.4 ;
    END
  END a_d[256]
  PIN a_d[257]
    DIRECTION OUTPUT ;
    USE SIGNAL ;
    PORT
      LAYER M5 ;
        RECT  28.032 86.316 28.056 86.4 ;
    END
  END a_d[257]
  PIN a_d[258]
    DIRECTION OUTPUT ;
    USE SIGNAL ;
    PORT
      LAYER M3 ;
        RECT  28.116 86.362 28.134 86.4 ;
    END
  END a_d[258]
  PIN a_d[259]
    DIRECTION OUTPUT ;
    USE SIGNAL ;
    PORT
      LAYER M5 ;
        RECT  28.224 86.316 28.248 86.4 ;
    END
  END a_d[259]
  PIN a_d[25]
    DIRECTION OUTPUT ;
    USE SIGNAL ;
    PORT
      LAYER M5 ;
        RECT  3.264 86.316 3.288 86.4 ;
    END
  END a_d[25]
  PIN a_d[260]
    DIRECTION OUTPUT ;
    USE SIGNAL ;
    PORT
      LAYER M3 ;
        RECT  28.332 86.362 28.35 86.4 ;
    END
  END a_d[260]
  PIN a_d[261]
    DIRECTION OUTPUT ;
    USE SIGNAL ;
    PORT
      LAYER M5 ;
        RECT  28.464 86.316 28.488 86.4 ;
    END
  END a_d[261]
  PIN a_d[262]
    DIRECTION OUTPUT ;
    USE SIGNAL ;
    PORT
      LAYER M3 ;
        RECT  28.548 86.362 28.566 86.4 ;
    END
  END a_d[262]
  PIN a_d[263]
    DIRECTION OUTPUT ;
    USE SIGNAL ;
    PORT
      LAYER M5 ;
        RECT  28.656 86.316 28.68 86.4 ;
    END
  END a_d[263]
  PIN a_d[264]
    DIRECTION OUTPUT ;
    USE SIGNAL ;
    PORT
      LAYER M3 ;
        RECT  28.764 86.362 28.782 86.4 ;
    END
  END a_d[264]
  PIN a_d[265]
    DIRECTION OUTPUT ;
    USE SIGNAL ;
    PORT
      LAYER M5 ;
        RECT  28.848 86.316 28.872 86.4 ;
    END
  END a_d[265]
  PIN a_d[266]
    DIRECTION OUTPUT ;
    USE SIGNAL ;
    PORT
      LAYER M3 ;
        RECT  28.98 86.362 28.998 86.4 ;
    END
  END a_d[266]
  PIN a_d[267]
    DIRECTION OUTPUT ;
    USE SIGNAL ;
    PORT
      LAYER M5 ;
        RECT  29.088 86.316 29.112 86.4 ;
    END
  END a_d[267]
  PIN a_d[268]
    DIRECTION OUTPUT ;
    USE SIGNAL ;
    PORT
      LAYER M3 ;
        RECT  29.196 86.362 29.214 86.4 ;
    END
  END a_d[268]
  PIN a_d[269]
    DIRECTION OUTPUT ;
    USE SIGNAL ;
    PORT
      LAYER M5 ;
        RECT  29.28 86.316 29.304 86.4 ;
    END
  END a_d[269]
  PIN a_d[26]
    DIRECTION OUTPUT ;
    USE SIGNAL ;
    PORT
      LAYER M3 ;
        RECT  3.348 86.362 3.366 86.4 ;
    END
  END a_d[26]
  PIN a_d[270]
    DIRECTION OUTPUT ;
    USE SIGNAL ;
    PORT
      LAYER M3 ;
        RECT  29.412 86.362 29.43 86.4 ;
    END
  END a_d[270]
  PIN a_d[271]
    DIRECTION OUTPUT ;
    USE SIGNAL ;
    PORT
      LAYER M5 ;
        RECT  29.52 86.316 29.544 86.4 ;
    END
  END a_d[271]
  PIN a_d[272]
    DIRECTION OUTPUT ;
    USE SIGNAL ;
    PORT
      LAYER M3 ;
        RECT  29.628 86.362 29.646 86.4 ;
    END
  END a_d[272]
  PIN a_d[273]
    DIRECTION OUTPUT ;
    USE SIGNAL ;
    PORT
      LAYER M5 ;
        RECT  29.712 86.316 29.736 86.4 ;
    END
  END a_d[273]
  PIN a_d[274]
    DIRECTION OUTPUT ;
    USE SIGNAL ;
    PORT
      LAYER M3 ;
        RECT  29.844 86.362 29.862 86.4 ;
    END
  END a_d[274]
  PIN a_d[275]
    DIRECTION OUTPUT ;
    USE SIGNAL ;
    PORT
      LAYER M5 ;
        RECT  29.952 86.316 29.976 86.4 ;
    END
  END a_d[275]
  PIN a_d[276]
    DIRECTION OUTPUT ;
    USE SIGNAL ;
    PORT
      LAYER M3 ;
        RECT  30.06 86.362 30.078 86.4 ;
    END
  END a_d[276]
  PIN a_d[277]
    DIRECTION OUTPUT ;
    USE SIGNAL ;
    PORT
      LAYER M5 ;
        RECT  30.144 86.316 30.168 86.4 ;
    END
  END a_d[277]
  PIN a_d[278]
    DIRECTION OUTPUT ;
    USE SIGNAL ;
    PORT
      LAYER M3 ;
        RECT  30.276 86.362 30.294 86.4 ;
    END
  END a_d[278]
  PIN a_d[279]
    DIRECTION OUTPUT ;
    USE SIGNAL ;
    PORT
      LAYER M5 ;
        RECT  30.384 86.316 30.408 86.4 ;
    END
  END a_d[279]
  PIN a_d[27]
    DIRECTION OUTPUT ;
    USE SIGNAL ;
    PORT
      LAYER M5 ;
        RECT  3.456 86.316 3.48 86.4 ;
    END
  END a_d[27]
  PIN a_d[280]
    DIRECTION OUTPUT ;
    USE SIGNAL ;
    PORT
      LAYER M3 ;
        RECT  30.456 86.362 30.474 86.4 ;
    END
  END a_d[280]
  PIN a_d[281]
    DIRECTION OUTPUT ;
    USE SIGNAL ;
    PORT
      LAYER M5 ;
        RECT  30.576 86.316 30.6 86.4 ;
    END
  END a_d[281]
  PIN a_d[282]
    DIRECTION OUTPUT ;
    USE SIGNAL ;
    PORT
      LAYER M3 ;
        RECT  30.672 86.362 30.69 86.4 ;
    END
  END a_d[282]
  PIN a_d[283]
    DIRECTION OUTPUT ;
    USE SIGNAL ;
    PORT
      LAYER M5 ;
        RECT  30.768 86.316 30.792 86.4 ;
    END
  END a_d[283]
  PIN a_d[284]
    DIRECTION OUTPUT ;
    USE SIGNAL ;
    PORT
      LAYER M3 ;
        RECT  30.888 86.362 30.906 86.4 ;
    END
  END a_d[284]
  PIN a_d[285]
    DIRECTION OUTPUT ;
    USE SIGNAL ;
    PORT
      LAYER M5 ;
        RECT  31.008 86.316 31.032 86.4 ;
    END
  END a_d[285]
  PIN a_d[286]
    DIRECTION OUTPUT ;
    USE SIGNAL ;
    PORT
      LAYER M3 ;
        RECT  31.104 86.362 31.122 86.4 ;
    END
  END a_d[286]
  PIN a_d[287]
    DIRECTION OUTPUT ;
    USE SIGNAL ;
    PORT
      LAYER M5 ;
        RECT  31.2 86.316 31.224 86.4 ;
    END
  END a_d[287]
  PIN a_d[288]
    DIRECTION OUTPUT ;
    USE SIGNAL ;
    PORT
      LAYER M3 ;
        RECT  31.32 86.362 31.338 86.4 ;
    END
  END a_d[288]
  PIN a_d[289]
    DIRECTION OUTPUT ;
    USE SIGNAL ;
    PORT
      LAYER M5 ;
        RECT  31.44 86.316 31.464 86.4 ;
    END
  END a_d[289]
  PIN a_d[28]
    DIRECTION OUTPUT ;
    USE SIGNAL ;
    PORT
      LAYER M3 ;
        RECT  3.564 86.362 3.582 86.4 ;
    END
  END a_d[28]
  PIN a_d[290]
    DIRECTION OUTPUT ;
    USE SIGNAL ;
    PORT
      LAYER M3 ;
        RECT  31.536 86.362 31.554 86.4 ;
    END
  END a_d[290]
  PIN a_d[291]
    DIRECTION OUTPUT ;
    USE SIGNAL ;
    PORT
      LAYER M5 ;
        RECT  31.632 86.316 31.656 86.4 ;
    END
  END a_d[291]
  PIN a_d[292]
    DIRECTION OUTPUT ;
    USE SIGNAL ;
    PORT
      LAYER M3 ;
        RECT  31.752 86.362 31.77 86.4 ;
    END
  END a_d[292]
  PIN a_d[293]
    DIRECTION OUTPUT ;
    USE SIGNAL ;
    PORT
      LAYER M5 ;
        RECT  31.872 86.316 31.896 86.4 ;
    END
  END a_d[293]
  PIN a_d[294]
    DIRECTION OUTPUT ;
    USE SIGNAL ;
    PORT
      LAYER M3 ;
        RECT  31.968 86.362 31.986 86.4 ;
    END
  END a_d[294]
  PIN a_d[295]
    DIRECTION OUTPUT ;
    USE SIGNAL ;
    PORT
      LAYER M5 ;
        RECT  32.064 86.316 32.088 86.4 ;
    END
  END a_d[295]
  PIN a_d[296]
    DIRECTION OUTPUT ;
    USE SIGNAL ;
    PORT
      LAYER M3 ;
        RECT  32.184 86.362 32.202 86.4 ;
    END
  END a_d[296]
  PIN a_d[297]
    DIRECTION OUTPUT ;
    USE SIGNAL ;
    PORT
      LAYER M5 ;
        RECT  32.304 86.316 32.328 86.4 ;
    END
  END a_d[297]
  PIN a_d[298]
    DIRECTION OUTPUT ;
    USE SIGNAL ;
    PORT
      LAYER M3 ;
        RECT  32.4 86.362 32.418 86.4 ;
    END
  END a_d[298]
  PIN a_d[299]
    DIRECTION OUTPUT ;
    USE SIGNAL ;
    PORT
      LAYER M5 ;
        RECT  32.496 86.316 32.52 86.4 ;
    END
  END a_d[299]
  PIN a_d[29]
    DIRECTION OUTPUT ;
    USE SIGNAL ;
    PORT
      LAYER M5 ;
        RECT  3.696 86.316 3.72 86.4 ;
    END
  END a_d[29]
  PIN a_d[2]
    DIRECTION OUTPUT ;
    USE SIGNAL ;
    PORT
      LAYER M3 ;
        RECT  0.792 86.362 0.81 86.4 ;
    END
  END a_d[2]
  PIN a_d[300]
    DIRECTION OUTPUT ;
    USE SIGNAL ;
    PORT
      LAYER M3 ;
        RECT  32.616 86.362 32.634 86.4 ;
    END
  END a_d[300]
  PIN a_d[301]
    DIRECTION OUTPUT ;
    USE SIGNAL ;
    PORT
      LAYER M5 ;
        RECT  32.688 86.316 32.712 86.4 ;
    END
  END a_d[301]
  PIN a_d[302]
    DIRECTION OUTPUT ;
    USE SIGNAL ;
    PORT
      LAYER M3 ;
        RECT  32.832 86.362 32.85 86.4 ;
    END
  END a_d[302]
  PIN a_d[303]
    DIRECTION OUTPUT ;
    USE SIGNAL ;
    PORT
      LAYER M5 ;
        RECT  32.928 86.316 32.952 86.4 ;
    END
  END a_d[303]
  PIN a_d[304]
    DIRECTION OUTPUT ;
    USE SIGNAL ;
    PORT
      LAYER M3 ;
        RECT  33.048 86.362 33.066 86.4 ;
    END
  END a_d[304]
  PIN a_d[305]
    DIRECTION OUTPUT ;
    USE SIGNAL ;
    PORT
      LAYER M5 ;
        RECT  33.12 86.316 33.144 86.4 ;
    END
  END a_d[305]
  PIN a_d[306]
    DIRECTION OUTPUT ;
    USE SIGNAL ;
    PORT
      LAYER M3 ;
        RECT  33.264 86.362 33.282 86.4 ;
    END
  END a_d[306]
  PIN a_d[307]
    DIRECTION OUTPUT ;
    USE SIGNAL ;
    PORT
      LAYER M5 ;
        RECT  33.36 86.316 33.384 86.4 ;
    END
  END a_d[307]
  PIN a_d[308]
    DIRECTION OUTPUT ;
    USE SIGNAL ;
    PORT
      LAYER M3 ;
        RECT  33.48 86.362 33.498 86.4 ;
    END
  END a_d[308]
  PIN a_d[309]
    DIRECTION OUTPUT ;
    USE SIGNAL ;
    PORT
      LAYER M5 ;
        RECT  33.552 86.316 33.576 86.4 ;
    END
  END a_d[309]
  PIN a_d[30]
    DIRECTION OUTPUT ;
    USE SIGNAL ;
    PORT
      LAYER M3 ;
        RECT  3.78 86.362 3.798 86.4 ;
    END
  END a_d[30]
  PIN a_d[310]
    DIRECTION OUTPUT ;
    USE SIGNAL ;
    PORT
      LAYER M3 ;
        RECT  33.66 86.362 33.678 86.4 ;
    END
  END a_d[310]
  PIN a_d[311]
    DIRECTION OUTPUT ;
    USE SIGNAL ;
    PORT
      LAYER M5 ;
        RECT  33.792 86.316 33.816 86.4 ;
    END
  END a_d[311]
  PIN a_d[312]
    DIRECTION OUTPUT ;
    USE SIGNAL ;
    PORT
      LAYER M3 ;
        RECT  33.876 86.362 33.894 86.4 ;
    END
  END a_d[312]
  PIN a_d[313]
    DIRECTION OUTPUT ;
    USE SIGNAL ;
    PORT
      LAYER M5 ;
        RECT  33.984 86.316 34.008 86.4 ;
    END
  END a_d[313]
  PIN a_d[314]
    DIRECTION OUTPUT ;
    USE SIGNAL ;
    PORT
      LAYER M3 ;
        RECT  34.092 86.362 34.11 86.4 ;
    END
  END a_d[314]
  PIN a_d[315]
    DIRECTION OUTPUT ;
    USE SIGNAL ;
    PORT
      LAYER M5 ;
        RECT  34.224 86.316 34.248 86.4 ;
    END
  END a_d[315]
  PIN a_d[316]
    DIRECTION OUTPUT ;
    USE SIGNAL ;
    PORT
      LAYER M3 ;
        RECT  34.308 86.362 34.326 86.4 ;
    END
  END a_d[316]
  PIN a_d[317]
    DIRECTION OUTPUT ;
    USE SIGNAL ;
    PORT
      LAYER M5 ;
        RECT  34.416 86.316 34.44 86.4 ;
    END
  END a_d[317]
  PIN a_d[318]
    DIRECTION OUTPUT ;
    USE SIGNAL ;
    PORT
      LAYER M3 ;
        RECT  34.524 86.362 34.542 86.4 ;
    END
  END a_d[318]
  PIN a_d[319]
    DIRECTION OUTPUT ;
    USE SIGNAL ;
    PORT
      LAYER M5 ;
        RECT  34.656 86.316 34.68 86.4 ;
    END
  END a_d[319]
  PIN a_d[31]
    DIRECTION OUTPUT ;
    USE SIGNAL ;
    PORT
      LAYER M5 ;
        RECT  3.888 86.316 3.912 86.4 ;
    END
  END a_d[31]
  PIN a_d[320]
    DIRECTION OUTPUT ;
    USE SIGNAL ;
    PORT
      LAYER M3 ;
        RECT  34.74 86.362 34.758 86.4 ;
    END
  END a_d[320]
  PIN a_d[321]
    DIRECTION OUTPUT ;
    USE SIGNAL ;
    PORT
      LAYER M5 ;
        RECT  34.848 86.316 34.872 86.4 ;
    END
  END a_d[321]
  PIN a_d[322]
    DIRECTION OUTPUT ;
    USE SIGNAL ;
    PORT
      LAYER M3 ;
        RECT  34.956 86.362 34.974 86.4 ;
    END
  END a_d[322]
  PIN a_d[323]
    DIRECTION OUTPUT ;
    USE SIGNAL ;
    PORT
      LAYER M5 ;
        RECT  35.04 86.316 35.064 86.4 ;
    END
  END a_d[323]
  PIN a_d[324]
    DIRECTION OUTPUT ;
    USE SIGNAL ;
    PORT
      LAYER M3 ;
        RECT  35.172 86.362 35.19 86.4 ;
    END
  END a_d[324]
  PIN a_d[325]
    DIRECTION OUTPUT ;
    USE SIGNAL ;
    PORT
      LAYER M5 ;
        RECT  35.28 86.316 35.304 86.4 ;
    END
  END a_d[325]
  PIN a_d[326]
    DIRECTION OUTPUT ;
    USE SIGNAL ;
    PORT
      LAYER M3 ;
        RECT  35.388 86.362 35.406 86.4 ;
    END
  END a_d[326]
  PIN a_d[327]
    DIRECTION OUTPUT ;
    USE SIGNAL ;
    PORT
      LAYER M5 ;
        RECT  35.472 86.316 35.496 86.4 ;
    END
  END a_d[327]
  PIN a_d[328]
    DIRECTION OUTPUT ;
    USE SIGNAL ;
    PORT
      LAYER M3 ;
        RECT  35.604 86.362 35.622 86.4 ;
    END
  END a_d[328]
  PIN a_d[329]
    DIRECTION OUTPUT ;
    USE SIGNAL ;
    PORT
      LAYER M5 ;
        RECT  35.712 86.316 35.736 86.4 ;
    END
  END a_d[329]
  PIN a_d[32]
    DIRECTION OUTPUT ;
    USE SIGNAL ;
    PORT
      LAYER M3 ;
        RECT  3.996 86.362 4.014 86.4 ;
    END
  END a_d[32]
  PIN a_d[330]
    DIRECTION OUTPUT ;
    USE SIGNAL ;
    PORT
      LAYER M3 ;
        RECT  35.82 86.362 35.838 86.4 ;
    END
  END a_d[330]
  PIN a_d[331]
    DIRECTION OUTPUT ;
    USE SIGNAL ;
    PORT
      LAYER M5 ;
        RECT  35.904 86.316 35.928 86.4 ;
    END
  END a_d[331]
  PIN a_d[332]
    DIRECTION OUTPUT ;
    USE SIGNAL ;
    PORT
      LAYER M3 ;
        RECT  36.036 86.362 36.054 86.4 ;
    END
  END a_d[332]
  PIN a_d[333]
    DIRECTION OUTPUT ;
    USE SIGNAL ;
    PORT
      LAYER M5 ;
        RECT  36.144 86.316 36.168 86.4 ;
    END
  END a_d[333]
  PIN a_d[334]
    DIRECTION OUTPUT ;
    USE SIGNAL ;
    PORT
      LAYER M3 ;
        RECT  36.252 86.362 36.27 86.4 ;
    END
  END a_d[334]
  PIN a_d[335]
    DIRECTION OUTPUT ;
    USE SIGNAL ;
    PORT
      LAYER M5 ;
        RECT  36.336 86.316 36.36 86.4 ;
    END
  END a_d[335]
  PIN a_d[336]
    DIRECTION OUTPUT ;
    USE SIGNAL ;
    PORT
      LAYER M3 ;
        RECT  36.468 86.362 36.486 86.4 ;
    END
  END a_d[336]
  PIN a_d[337]
    DIRECTION OUTPUT ;
    USE SIGNAL ;
    PORT
      LAYER M5 ;
        RECT  36.576 86.316 36.6 86.4 ;
    END
  END a_d[337]
  PIN a_d[338]
    DIRECTION OUTPUT ;
    USE SIGNAL ;
    PORT
      LAYER M3 ;
        RECT  36.648 86.362 36.666 86.4 ;
    END
  END a_d[338]
  PIN a_d[339]
    DIRECTION OUTPUT ;
    USE SIGNAL ;
    PORT
      LAYER M5 ;
        RECT  36.768 86.316 36.792 86.4 ;
    END
  END a_d[339]
  PIN a_d[33]
    DIRECTION OUTPUT ;
    USE SIGNAL ;
    PORT
      LAYER M5 ;
        RECT  4.128 86.316 4.152 86.4 ;
    END
  END a_d[33]
  PIN a_d[340]
    DIRECTION OUTPUT ;
    USE SIGNAL ;
    PORT
      LAYER M3 ;
        RECT  36.864 86.362 36.882 86.4 ;
    END
  END a_d[340]
  PIN a_d[341]
    DIRECTION OUTPUT ;
    USE SIGNAL ;
    PORT
      LAYER M5 ;
        RECT  36.96 86.316 36.984 86.4 ;
    END
  END a_d[341]
  PIN a_d[342]
    DIRECTION OUTPUT ;
    USE SIGNAL ;
    PORT
      LAYER M3 ;
        RECT  37.08 86.362 37.098 86.4 ;
    END
  END a_d[342]
  PIN a_d[343]
    DIRECTION OUTPUT ;
    USE SIGNAL ;
    PORT
      LAYER M5 ;
        RECT  37.2 86.316 37.224 86.4 ;
    END
  END a_d[343]
  PIN a_d[344]
    DIRECTION OUTPUT ;
    USE SIGNAL ;
    PORT
      LAYER M3 ;
        RECT  37.296 86.362 37.314 86.4 ;
    END
  END a_d[344]
  PIN a_d[345]
    DIRECTION OUTPUT ;
    USE SIGNAL ;
    PORT
      LAYER M5 ;
        RECT  37.392 86.316 37.416 86.4 ;
    END
  END a_d[345]
  PIN a_d[346]
    DIRECTION OUTPUT ;
    USE SIGNAL ;
    PORT
      LAYER M3 ;
        RECT  37.512 86.362 37.53 86.4 ;
    END
  END a_d[346]
  PIN a_d[347]
    DIRECTION OUTPUT ;
    USE SIGNAL ;
    PORT
      LAYER M5 ;
        RECT  37.632 86.316 37.656 86.4 ;
    END
  END a_d[347]
  PIN a_d[348]
    DIRECTION OUTPUT ;
    USE SIGNAL ;
    PORT
      LAYER M3 ;
        RECT  37.728 86.362 37.746 86.4 ;
    END
  END a_d[348]
  PIN a_d[349]
    DIRECTION OUTPUT ;
    USE SIGNAL ;
    PORT
      LAYER M5 ;
        RECT  37.824 86.316 37.848 86.4 ;
    END
  END a_d[349]
  PIN a_d[34]
    DIRECTION OUTPUT ;
    USE SIGNAL ;
    PORT
      LAYER M3 ;
        RECT  4.212 86.362 4.23 86.4 ;
    END
  END a_d[34]
  PIN a_d[350]
    DIRECTION OUTPUT ;
    USE SIGNAL ;
    PORT
      LAYER M3 ;
        RECT  37.944 86.362 37.962 86.4 ;
    END
  END a_d[350]
  PIN a_d[351]
    DIRECTION OUTPUT ;
    USE SIGNAL ;
    PORT
      LAYER M5 ;
        RECT  38.064 86.316 38.088 86.4 ;
    END
  END a_d[351]
  PIN a_d[352]
    DIRECTION OUTPUT ;
    USE SIGNAL ;
    PORT
      LAYER M3 ;
        RECT  38.16 86.362 38.178 86.4 ;
    END
  END a_d[352]
  PIN a_d[353]
    DIRECTION OUTPUT ;
    USE SIGNAL ;
    PORT
      LAYER M5 ;
        RECT  38.256 86.316 38.28 86.4 ;
    END
  END a_d[353]
  PIN a_d[354]
    DIRECTION OUTPUT ;
    USE SIGNAL ;
    PORT
      LAYER M3 ;
        RECT  38.376 86.362 38.394 86.4 ;
    END
  END a_d[354]
  PIN a_d[355]
    DIRECTION OUTPUT ;
    USE SIGNAL ;
    PORT
      LAYER M5 ;
        RECT  38.496 86.316 38.52 86.4 ;
    END
  END a_d[355]
  PIN a_d[356]
    DIRECTION OUTPUT ;
    USE SIGNAL ;
    PORT
      LAYER M3 ;
        RECT  38.592 86.362 38.61 86.4 ;
    END
  END a_d[356]
  PIN a_d[357]
    DIRECTION OUTPUT ;
    USE SIGNAL ;
    PORT
      LAYER M5 ;
        RECT  38.688 86.316 38.712 86.4 ;
    END
  END a_d[357]
  PIN a_d[358]
    DIRECTION OUTPUT ;
    USE SIGNAL ;
    PORT
      LAYER M3 ;
        RECT  38.808 86.362 38.826 86.4 ;
    END
  END a_d[358]
  PIN a_d[359]
    DIRECTION OUTPUT ;
    USE SIGNAL ;
    PORT
      LAYER M5 ;
        RECT  38.88 86.316 38.904 86.4 ;
    END
  END a_d[359]
  PIN a_d[35]
    DIRECTION OUTPUT ;
    USE SIGNAL ;
    PORT
      LAYER M5 ;
        RECT  4.32 86.316 4.344 86.4 ;
    END
  END a_d[35]
  PIN a_d[360]
    DIRECTION OUTPUT ;
    USE SIGNAL ;
    PORT
      LAYER M3 ;
        RECT  39.024 86.362 39.042 86.4 ;
    END
  END a_d[360]
  PIN a_d[361]
    DIRECTION OUTPUT ;
    USE SIGNAL ;
    PORT
      LAYER M5 ;
        RECT  39.12 86.316 39.144 86.4 ;
    END
  END a_d[361]
  PIN a_d[362]
    DIRECTION OUTPUT ;
    USE SIGNAL ;
    PORT
      LAYER M3 ;
        RECT  39.24 86.362 39.258 86.4 ;
    END
  END a_d[362]
  PIN a_d[363]
    DIRECTION OUTPUT ;
    USE SIGNAL ;
    PORT
      LAYER M5 ;
        RECT  39.312 86.316 39.336 86.4 ;
    END
  END a_d[363]
  PIN a_d[364]
    DIRECTION OUTPUT ;
    USE SIGNAL ;
    PORT
      LAYER M3 ;
        RECT  39.456 86.362 39.474 86.4 ;
    END
  END a_d[364]
  PIN a_d[365]
    DIRECTION OUTPUT ;
    USE SIGNAL ;
    PORT
      LAYER M5 ;
        RECT  39.552 86.316 39.576 86.4 ;
    END
  END a_d[365]
  PIN a_d[366]
    DIRECTION OUTPUT ;
    USE SIGNAL ;
    PORT
      LAYER M3 ;
        RECT  39.636 86.362 39.654 86.4 ;
    END
  END a_d[366]
  PIN a_d[367]
    DIRECTION OUTPUT ;
    USE SIGNAL ;
    PORT
      LAYER M5 ;
        RECT  39.744 86.316 39.768 86.4 ;
    END
  END a_d[367]
  PIN a_d[368]
    DIRECTION OUTPUT ;
    USE SIGNAL ;
    PORT
      LAYER M3 ;
        RECT  39.852 86.362 39.87 86.4 ;
    END
  END a_d[368]
  PIN a_d[369]
    DIRECTION OUTPUT ;
    USE SIGNAL ;
    PORT
      LAYER M5 ;
        RECT  39.984 86.316 40.008 86.4 ;
    END
  END a_d[369]
  PIN a_d[36]
    DIRECTION OUTPUT ;
    USE SIGNAL ;
    PORT
      LAYER M3 ;
        RECT  4.428 86.362 4.446 86.4 ;
    END
  END a_d[36]
  PIN a_d[370]
    DIRECTION OUTPUT ;
    USE SIGNAL ;
    PORT
      LAYER M3 ;
        RECT  40.068 86.362 40.086 86.4 ;
    END
  END a_d[370]
  PIN a_d[371]
    DIRECTION OUTPUT ;
    USE SIGNAL ;
    PORT
      LAYER M5 ;
        RECT  40.176 86.316 40.2 86.4 ;
    END
  END a_d[371]
  PIN a_d[372]
    DIRECTION OUTPUT ;
    USE SIGNAL ;
    PORT
      LAYER M3 ;
        RECT  40.284 86.362 40.302 86.4 ;
    END
  END a_d[372]
  PIN a_d[373]
    DIRECTION OUTPUT ;
    USE SIGNAL ;
    PORT
      LAYER M5 ;
        RECT  40.416 86.316 40.44 86.4 ;
    END
  END a_d[373]
  PIN a_d[374]
    DIRECTION OUTPUT ;
    USE SIGNAL ;
    PORT
      LAYER M3 ;
        RECT  40.5 86.362 40.518 86.4 ;
    END
  END a_d[374]
  PIN a_d[375]
    DIRECTION OUTPUT ;
    USE SIGNAL ;
    PORT
      LAYER M5 ;
        RECT  40.608 86.316 40.632 86.4 ;
    END
  END a_d[375]
  PIN a_d[376]
    DIRECTION OUTPUT ;
    USE SIGNAL ;
    PORT
      LAYER M3 ;
        RECT  40.716 86.362 40.734 86.4 ;
    END
  END a_d[376]
  PIN a_d[377]
    DIRECTION OUTPUT ;
    USE SIGNAL ;
    PORT
      LAYER M5 ;
        RECT  40.848 86.316 40.872 86.4 ;
    END
  END a_d[377]
  PIN a_d[378]
    DIRECTION OUTPUT ;
    USE SIGNAL ;
    PORT
      LAYER M3 ;
        RECT  40.932 86.362 40.95 86.4 ;
    END
  END a_d[378]
  PIN a_d[379]
    DIRECTION OUTPUT ;
    USE SIGNAL ;
    PORT
      LAYER M5 ;
        RECT  41.04 86.316 41.064 86.4 ;
    END
  END a_d[379]
  PIN a_d[37]
    DIRECTION OUTPUT ;
    USE SIGNAL ;
    PORT
      LAYER M5 ;
        RECT  4.512 86.316 4.536 86.4 ;
    END
  END a_d[37]
  PIN a_d[380]
    DIRECTION OUTPUT ;
    USE SIGNAL ;
    PORT
      LAYER M3 ;
        RECT  41.148 86.362 41.166 86.4 ;
    END
  END a_d[380]
  PIN a_d[381]
    DIRECTION OUTPUT ;
    USE SIGNAL ;
    PORT
      LAYER M5 ;
        RECT  41.232 86.316 41.256 86.4 ;
    END
  END a_d[381]
  PIN a_d[382]
    DIRECTION OUTPUT ;
    USE SIGNAL ;
    PORT
      LAYER M3 ;
        RECT  41.364 86.362 41.382 86.4 ;
    END
  END a_d[382]
  PIN a_d[383]
    DIRECTION OUTPUT ;
    USE SIGNAL ;
    PORT
      LAYER M5 ;
        RECT  41.472 86.316 41.496 86.4 ;
    END
  END a_d[383]
  PIN a_d[384]
    DIRECTION OUTPUT ;
    USE SIGNAL ;
    PORT
      LAYER M3 ;
        RECT  41.58 86.362 41.598 86.4 ;
    END
  END a_d[384]
  PIN a_d[385]
    DIRECTION OUTPUT ;
    USE SIGNAL ;
    PORT
      LAYER M5 ;
        RECT  41.664 86.316 41.688 86.4 ;
    END
  END a_d[385]
  PIN a_d[386]
    DIRECTION OUTPUT ;
    USE SIGNAL ;
    PORT
      LAYER M3 ;
        RECT  41.796 86.362 41.814 86.4 ;
    END
  END a_d[386]
  PIN a_d[387]
    DIRECTION OUTPUT ;
    USE SIGNAL ;
    PORT
      LAYER M5 ;
        RECT  41.904 86.316 41.928 86.4 ;
    END
  END a_d[387]
  PIN a_d[388]
    DIRECTION OUTPUT ;
    USE SIGNAL ;
    PORT
      LAYER M3 ;
        RECT  42.012 86.362 42.03 86.4 ;
    END
  END a_d[388]
  PIN a_d[389]
    DIRECTION OUTPUT ;
    USE SIGNAL ;
    PORT
      LAYER M5 ;
        RECT  42.096 86.316 42.12 86.4 ;
    END
  END a_d[389]
  PIN a_d[38]
    DIRECTION OUTPUT ;
    USE SIGNAL ;
    PORT
      LAYER M3 ;
        RECT  4.644 86.362 4.662 86.4 ;
    END
  END a_d[38]
  PIN a_d[390]
    DIRECTION OUTPUT ;
    USE SIGNAL ;
    PORT
      LAYER M3 ;
        RECT  42.228 86.362 42.246 86.4 ;
    END
  END a_d[390]
  PIN a_d[391]
    DIRECTION OUTPUT ;
    USE SIGNAL ;
    PORT
      LAYER M5 ;
        RECT  42.336 86.316 42.36 86.4 ;
    END
  END a_d[391]
  PIN a_d[392]
    DIRECTION OUTPUT ;
    USE SIGNAL ;
    PORT
      LAYER M3 ;
        RECT  42.444 86.362 42.462 86.4 ;
    END
  END a_d[392]
  PIN a_d[393]
    DIRECTION OUTPUT ;
    USE SIGNAL ;
    PORT
      LAYER M5 ;
        RECT  42.528 86.316 42.552 86.4 ;
    END
  END a_d[393]
  PIN a_d[394]
    DIRECTION OUTPUT ;
    USE SIGNAL ;
    PORT
      LAYER M3 ;
        RECT  42.66 86.362 42.678 86.4 ;
    END
  END a_d[394]
  PIN a_d[395]
    DIRECTION OUTPUT ;
    USE SIGNAL ;
    PORT
      LAYER M5 ;
        RECT  42.768 86.316 42.792 86.4 ;
    END
  END a_d[395]
  PIN a_d[396]
    DIRECTION OUTPUT ;
    USE SIGNAL ;
    PORT
      LAYER M3 ;
        RECT  42.84 86.362 42.858 86.4 ;
    END
  END a_d[396]
  PIN a_d[397]
    DIRECTION OUTPUT ;
    USE SIGNAL ;
    PORT
      LAYER M5 ;
        RECT  42.96 86.316 42.984 86.4 ;
    END
  END a_d[397]
  PIN a_d[398]
    DIRECTION OUTPUT ;
    USE SIGNAL ;
    PORT
      LAYER M3 ;
        RECT  43.056 86.362 43.074 86.4 ;
    END
  END a_d[398]
  PIN a_d[399]
    DIRECTION OUTPUT ;
    USE SIGNAL ;
    PORT
      LAYER M5 ;
        RECT  43.152 86.316 43.176 86.4 ;
    END
  END a_d[399]
  PIN a_d[39]
    DIRECTION OUTPUT ;
    USE SIGNAL ;
    PORT
      LAYER M5 ;
        RECT  4.752 86.316 4.776 86.4 ;
    END
  END a_d[39]
  PIN a_d[3]
    DIRECTION OUTPUT ;
    USE SIGNAL ;
    PORT
      LAYER M5 ;
        RECT  0.912 86.316 0.936 86.4 ;
    END
  END a_d[3]
  PIN a_d[400]
    DIRECTION OUTPUT ;
    USE SIGNAL ;
    PORT
      LAYER M3 ;
        RECT  43.272 86.362 43.29 86.4 ;
    END
  END a_d[400]
  PIN a_d[401]
    DIRECTION OUTPUT ;
    USE SIGNAL ;
    PORT
      LAYER M5 ;
        RECT  43.392 86.316 43.416 86.4 ;
    END
  END a_d[401]
  PIN a_d[402]
    DIRECTION OUTPUT ;
    USE SIGNAL ;
    PORT
      LAYER M3 ;
        RECT  43.488 86.362 43.506 86.4 ;
    END
  END a_d[402]
  PIN a_d[403]
    DIRECTION OUTPUT ;
    USE SIGNAL ;
    PORT
      LAYER M5 ;
        RECT  43.584 86.316 43.608 86.4 ;
    END
  END a_d[403]
  PIN a_d[404]
    DIRECTION OUTPUT ;
    USE SIGNAL ;
    PORT
      LAYER M3 ;
        RECT  43.704 86.362 43.722 86.4 ;
    END
  END a_d[404]
  PIN a_d[405]
    DIRECTION OUTPUT ;
    USE SIGNAL ;
    PORT
      LAYER M5 ;
        RECT  43.824 86.316 43.848 86.4 ;
    END
  END a_d[405]
  PIN a_d[406]
    DIRECTION OUTPUT ;
    USE SIGNAL ;
    PORT
      LAYER M3 ;
        RECT  43.92 86.362 43.938 86.4 ;
    END
  END a_d[406]
  PIN a_d[407]
    DIRECTION OUTPUT ;
    USE SIGNAL ;
    PORT
      LAYER M5 ;
        RECT  44.016 86.316 44.04 86.4 ;
    END
  END a_d[407]
  PIN a_d[408]
    DIRECTION OUTPUT ;
    USE SIGNAL ;
    PORT
      LAYER M3 ;
        RECT  44.136 86.362 44.154 86.4 ;
    END
  END a_d[408]
  PIN a_d[409]
    DIRECTION OUTPUT ;
    USE SIGNAL ;
    PORT
      LAYER M5 ;
        RECT  44.256 86.316 44.28 86.4 ;
    END
  END a_d[409]
  PIN a_d[40]
    DIRECTION OUTPUT ;
    USE SIGNAL ;
    PORT
      LAYER M3 ;
        RECT  4.86 86.362 4.878 86.4 ;
    END
  END a_d[40]
  PIN a_d[410]
    DIRECTION OUTPUT ;
    USE SIGNAL ;
    PORT
      LAYER M3 ;
        RECT  44.352 86.362 44.37 86.4 ;
    END
  END a_d[410]
  PIN a_d[411]
    DIRECTION OUTPUT ;
    USE SIGNAL ;
    PORT
      LAYER M5 ;
        RECT  44.448 86.316 44.472 86.4 ;
    END
  END a_d[411]
  PIN a_d[412]
    DIRECTION OUTPUT ;
    USE SIGNAL ;
    PORT
      LAYER M3 ;
        RECT  44.568 86.362 44.586 86.4 ;
    END
  END a_d[412]
  PIN a_d[413]
    DIRECTION OUTPUT ;
    USE SIGNAL ;
    PORT
      LAYER M5 ;
        RECT  44.688 86.316 44.712 86.4 ;
    END
  END a_d[413]
  PIN a_d[414]
    DIRECTION OUTPUT ;
    USE SIGNAL ;
    PORT
      LAYER M3 ;
        RECT  44.784 86.362 44.802 86.4 ;
    END
  END a_d[414]
  PIN a_d[415]
    DIRECTION OUTPUT ;
    USE SIGNAL ;
    PORT
      LAYER M5 ;
        RECT  44.88 86.316 44.904 86.4 ;
    END
  END a_d[415]
  PIN a_d[416]
    DIRECTION OUTPUT ;
    USE SIGNAL ;
    PORT
      LAYER M3 ;
        RECT  45 86.362 45.018 86.4 ;
    END
  END a_d[416]
  PIN a_d[417]
    DIRECTION OUTPUT ;
    USE SIGNAL ;
    PORT
      LAYER M5 ;
        RECT  45.072 86.316 45.096 86.4 ;
    END
  END a_d[417]
  PIN a_d[418]
    DIRECTION OUTPUT ;
    USE SIGNAL ;
    PORT
      LAYER M3 ;
        RECT  45.216 86.362 45.234 86.4 ;
    END
  END a_d[418]
  PIN a_d[419]
    DIRECTION OUTPUT ;
    USE SIGNAL ;
    PORT
      LAYER M5 ;
        RECT  45.312 86.316 45.336 86.4 ;
    END
  END a_d[419]
  PIN a_d[41]
    DIRECTION OUTPUT ;
    USE SIGNAL ;
    PORT
      LAYER M5 ;
        RECT  4.944 86.316 4.968 86.4 ;
    END
  END a_d[41]
  PIN a_d[420]
    DIRECTION OUTPUT ;
    USE SIGNAL ;
    PORT
      LAYER M3 ;
        RECT  45.432 86.362 45.45 86.4 ;
    END
  END a_d[420]
  PIN a_d[421]
    DIRECTION OUTPUT ;
    USE SIGNAL ;
    PORT
      LAYER M5 ;
        RECT  45.504 86.316 45.528 86.4 ;
    END
  END a_d[421]
  PIN a_d[422]
    DIRECTION OUTPUT ;
    USE SIGNAL ;
    PORT
      LAYER M3 ;
        RECT  45.648 86.362 45.666 86.4 ;
    END
  END a_d[422]
  PIN a_d[423]
    DIRECTION OUTPUT ;
    USE SIGNAL ;
    PORT
      LAYER M5 ;
        RECT  45.744 86.316 45.768 86.4 ;
    END
  END a_d[423]
  PIN a_d[424]
    DIRECTION OUTPUT ;
    USE SIGNAL ;
    PORT
      LAYER M3 ;
        RECT  45.828 86.362 45.846 86.4 ;
    END
  END a_d[424]
  PIN a_d[425]
    DIRECTION OUTPUT ;
    USE SIGNAL ;
    PORT
      LAYER M5 ;
        RECT  45.936 86.316 45.96 86.4 ;
    END
  END a_d[425]
  PIN a_d[426]
    DIRECTION OUTPUT ;
    USE SIGNAL ;
    PORT
      LAYER M3 ;
        RECT  46.044 86.362 46.062 86.4 ;
    END
  END a_d[426]
  PIN a_d[427]
    DIRECTION OUTPUT ;
    USE SIGNAL ;
    PORT
      LAYER M5 ;
        RECT  46.176 86.316 46.2 86.4 ;
    END
  END a_d[427]
  PIN a_d[428]
    DIRECTION OUTPUT ;
    USE SIGNAL ;
    PORT
      LAYER M3 ;
        RECT  46.26 86.362 46.278 86.4 ;
    END
  END a_d[428]
  PIN a_d[429]
    DIRECTION OUTPUT ;
    USE SIGNAL ;
    PORT
      LAYER M5 ;
        RECT  46.368 86.316 46.392 86.4 ;
    END
  END a_d[429]
  PIN a_d[42]
    DIRECTION OUTPUT ;
    USE SIGNAL ;
    PORT
      LAYER M3 ;
        RECT  5.076 86.362 5.094 86.4 ;
    END
  END a_d[42]
  PIN a_d[430]
    DIRECTION OUTPUT ;
    USE SIGNAL ;
    PORT
      LAYER M3 ;
        RECT  46.476 86.362 46.494 86.4 ;
    END
  END a_d[430]
  PIN a_d[431]
    DIRECTION OUTPUT ;
    USE SIGNAL ;
    PORT
      LAYER M5 ;
        RECT  46.608 86.316 46.632 86.4 ;
    END
  END a_d[431]
  PIN a_d[432]
    DIRECTION OUTPUT ;
    USE SIGNAL ;
    PORT
      LAYER M3 ;
        RECT  46.692 86.362 46.71 86.4 ;
    END
  END a_d[432]
  PIN a_d[433]
    DIRECTION OUTPUT ;
    USE SIGNAL ;
    PORT
      LAYER M5 ;
        RECT  46.8 86.316 46.824 86.4 ;
    END
  END a_d[433]
  PIN a_d[434]
    DIRECTION OUTPUT ;
    USE SIGNAL ;
    PORT
      LAYER M3 ;
        RECT  46.908 86.362 46.926 86.4 ;
    END
  END a_d[434]
  PIN a_d[435]
    DIRECTION OUTPUT ;
    USE SIGNAL ;
    PORT
      LAYER M5 ;
        RECT  46.992 86.316 47.016 86.4 ;
    END
  END a_d[435]
  PIN a_d[436]
    DIRECTION OUTPUT ;
    USE SIGNAL ;
    PORT
      LAYER M3 ;
        RECT  47.124 86.362 47.142 86.4 ;
    END
  END a_d[436]
  PIN a_d[437]
    DIRECTION OUTPUT ;
    USE SIGNAL ;
    PORT
      LAYER M5 ;
        RECT  47.232 86.316 47.256 86.4 ;
    END
  END a_d[437]
  PIN a_d[438]
    DIRECTION OUTPUT ;
    USE SIGNAL ;
    PORT
      LAYER M3 ;
        RECT  47.34 86.362 47.358 86.4 ;
    END
  END a_d[438]
  PIN a_d[439]
    DIRECTION OUTPUT ;
    USE SIGNAL ;
    PORT
      LAYER M5 ;
        RECT  47.424 86.316 47.448 86.4 ;
    END
  END a_d[439]
  PIN a_d[43]
    DIRECTION OUTPUT ;
    USE SIGNAL ;
    PORT
      LAYER M5 ;
        RECT  5.184 86.316 5.208 86.4 ;
    END
  END a_d[43]
  PIN a_d[440]
    DIRECTION OUTPUT ;
    USE SIGNAL ;
    PORT
      LAYER M3 ;
        RECT  47.556 86.362 47.574 86.4 ;
    END
  END a_d[440]
  PIN a_d[441]
    DIRECTION OUTPUT ;
    USE SIGNAL ;
    PORT
      LAYER M5 ;
        RECT  47.664 86.316 47.688 86.4 ;
    END
  END a_d[441]
  PIN a_d[442]
    DIRECTION OUTPUT ;
    USE SIGNAL ;
    PORT
      LAYER M3 ;
        RECT  47.772 86.362 47.79 86.4 ;
    END
  END a_d[442]
  PIN a_d[443]
    DIRECTION OUTPUT ;
    USE SIGNAL ;
    PORT
      LAYER M5 ;
        RECT  47.856 86.316 47.88 86.4 ;
    END
  END a_d[443]
  PIN a_d[444]
    DIRECTION OUTPUT ;
    USE SIGNAL ;
    PORT
      LAYER M3 ;
        RECT  47.988 86.362 48.006 86.4 ;
    END
  END a_d[444]
  PIN a_d[445]
    DIRECTION OUTPUT ;
    USE SIGNAL ;
    PORT
      LAYER M5 ;
        RECT  48.096 86.316 48.12 86.4 ;
    END
  END a_d[445]
  PIN a_d[446]
    DIRECTION OUTPUT ;
    USE SIGNAL ;
    PORT
      LAYER M3 ;
        RECT  48.204 86.362 48.222 86.4 ;
    END
  END a_d[446]
  PIN a_d[447]
    DIRECTION OUTPUT ;
    USE SIGNAL ;
    PORT
      LAYER M5 ;
        RECT  48.288 86.316 48.312 86.4 ;
    END
  END a_d[447]
  PIN a_d[448]
    DIRECTION OUTPUT ;
    USE SIGNAL ;
    PORT
      LAYER M3 ;
        RECT  48.42 86.362 48.438 86.4 ;
    END
  END a_d[448]
  PIN a_d[449]
    DIRECTION OUTPUT ;
    USE SIGNAL ;
    PORT
      LAYER M5 ;
        RECT  48.528 86.316 48.552 86.4 ;
    END
  END a_d[449]
  PIN a_d[44]
    DIRECTION OUTPUT ;
    USE SIGNAL ;
    PORT
      LAYER M3 ;
        RECT  5.292 86.362 5.31 86.4 ;
    END
  END a_d[44]
  PIN a_d[450]
    DIRECTION OUTPUT ;
    USE SIGNAL ;
    PORT
      LAYER M3 ;
        RECT  48.636 86.362 48.654 86.4 ;
    END
  END a_d[450]
  PIN a_d[451]
    DIRECTION OUTPUT ;
    USE SIGNAL ;
    PORT
      LAYER M5 ;
        RECT  48.72 86.316 48.744 86.4 ;
    END
  END a_d[451]
  PIN a_d[452]
    DIRECTION OUTPUT ;
    USE SIGNAL ;
    PORT
      LAYER M3 ;
        RECT  48.816 86.362 48.834 86.4 ;
    END
  END a_d[452]
  PIN a_d[453]
    DIRECTION OUTPUT ;
    USE SIGNAL ;
    PORT
      LAYER M5 ;
        RECT  48.96 86.316 48.984 86.4 ;
    END
  END a_d[453]
  PIN a_d[454]
    DIRECTION OUTPUT ;
    USE SIGNAL ;
    PORT
      LAYER M3 ;
        RECT  49.032 86.362 49.05 86.4 ;
    END
  END a_d[454]
  PIN a_d[455]
    DIRECTION OUTPUT ;
    USE SIGNAL ;
    PORT
      LAYER M5 ;
        RECT  49.152 86.316 49.176 86.4 ;
    END
  END a_d[455]
  PIN a_d[456]
    DIRECTION OUTPUT ;
    USE SIGNAL ;
    PORT
      LAYER M3 ;
        RECT  49.248 86.362 49.266 86.4 ;
    END
  END a_d[456]
  PIN a_d[457]
    DIRECTION OUTPUT ;
    USE SIGNAL ;
    PORT
      LAYER M5 ;
        RECT  49.344 86.316 49.368 86.4 ;
    END
  END a_d[457]
  PIN a_d[458]
    DIRECTION OUTPUT ;
    USE SIGNAL ;
    PORT
      LAYER M3 ;
        RECT  49.464 86.362 49.482 86.4 ;
    END
  END a_d[458]
  PIN a_d[459]
    DIRECTION OUTPUT ;
    USE SIGNAL ;
    PORT
      LAYER M5 ;
        RECT  49.584 86.316 49.608 86.4 ;
    END
  END a_d[459]
  PIN a_d[45]
    DIRECTION OUTPUT ;
    USE SIGNAL ;
    PORT
      LAYER M5 ;
        RECT  5.376 86.316 5.4 86.4 ;
    END
  END a_d[45]
  PIN a_d[460]
    DIRECTION OUTPUT ;
    USE SIGNAL ;
    PORT
      LAYER M3 ;
        RECT  49.68 86.362 49.698 86.4 ;
    END
  END a_d[460]
  PIN a_d[461]
    DIRECTION OUTPUT ;
    USE SIGNAL ;
    PORT
      LAYER M5 ;
        RECT  49.776 86.316 49.8 86.4 ;
    END
  END a_d[461]
  PIN a_d[462]
    DIRECTION OUTPUT ;
    USE SIGNAL ;
    PORT
      LAYER M3 ;
        RECT  49.896 86.362 49.914 86.4 ;
    END
  END a_d[462]
  PIN a_d[463]
    DIRECTION OUTPUT ;
    USE SIGNAL ;
    PORT
      LAYER M5 ;
        RECT  50.016 86.316 50.04 86.4 ;
    END
  END a_d[463]
  PIN a_d[464]
    DIRECTION OUTPUT ;
    USE SIGNAL ;
    PORT
      LAYER M3 ;
        RECT  50.112 86.362 50.13 86.4 ;
    END
  END a_d[464]
  PIN a_d[465]
    DIRECTION OUTPUT ;
    USE SIGNAL ;
    PORT
      LAYER M5 ;
        RECT  50.208 86.316 50.232 86.4 ;
    END
  END a_d[465]
  PIN a_d[466]
    DIRECTION OUTPUT ;
    USE SIGNAL ;
    PORT
      LAYER M3 ;
        RECT  50.328 86.362 50.346 86.4 ;
    END
  END a_d[466]
  PIN a_d[467]
    DIRECTION OUTPUT ;
    USE SIGNAL ;
    PORT
      LAYER M5 ;
        RECT  50.448 86.316 50.472 86.4 ;
    END
  END a_d[467]
  PIN a_d[468]
    DIRECTION OUTPUT ;
    USE SIGNAL ;
    PORT
      LAYER M3 ;
        RECT  50.544 86.362 50.562 86.4 ;
    END
  END a_d[468]
  PIN a_d[469]
    DIRECTION OUTPUT ;
    USE SIGNAL ;
    PORT
      LAYER M5 ;
        RECT  50.64 86.316 50.664 86.4 ;
    END
  END a_d[469]
  PIN a_d[46]
    DIRECTION OUTPUT ;
    USE SIGNAL ;
    PORT
      LAYER M3 ;
        RECT  5.508 86.362 5.526 86.4 ;
    END
  END a_d[46]
  PIN a_d[470]
    DIRECTION OUTPUT ;
    USE SIGNAL ;
    PORT
      LAYER M3 ;
        RECT  50.76 86.362 50.778 86.4 ;
    END
  END a_d[470]
  PIN a_d[471]
    DIRECTION OUTPUT ;
    USE SIGNAL ;
    PORT
      LAYER M5 ;
        RECT  50.88 86.316 50.904 86.4 ;
    END
  END a_d[471]
  PIN a_d[472]
    DIRECTION OUTPUT ;
    USE SIGNAL ;
    PORT
      LAYER M3 ;
        RECT  50.976 86.362 50.994 86.4 ;
    END
  END a_d[472]
  PIN a_d[473]
    DIRECTION OUTPUT ;
    USE SIGNAL ;
    PORT
      LAYER M5 ;
        RECT  51.072 86.316 51.096 86.4 ;
    END
  END a_d[473]
  PIN a_d[474]
    DIRECTION OUTPUT ;
    USE SIGNAL ;
    PORT
      LAYER M3 ;
        RECT  51.192 86.362 51.21 86.4 ;
    END
  END a_d[474]
  PIN a_d[475]
    DIRECTION OUTPUT ;
    USE SIGNAL ;
    PORT
      LAYER M5 ;
        RECT  51.264 86.316 51.288 86.4 ;
    END
  END a_d[475]
  PIN a_d[476]
    DIRECTION OUTPUT ;
    USE SIGNAL ;
    PORT
      LAYER M3 ;
        RECT  51.408 86.362 51.426 86.4 ;
    END
  END a_d[476]
  PIN a_d[477]
    DIRECTION OUTPUT ;
    USE SIGNAL ;
    PORT
      LAYER M5 ;
        RECT  51.504 86.316 51.528 86.4 ;
    END
  END a_d[477]
  PIN a_d[478]
    DIRECTION OUTPUT ;
    USE SIGNAL ;
    PORT
      LAYER M3 ;
        RECT  51.624 86.362 51.642 86.4 ;
    END
  END a_d[478]
  PIN a_d[479]
    DIRECTION OUTPUT ;
    USE SIGNAL ;
    PORT
      LAYER M5 ;
        RECT  51.696 86.316 51.72 86.4 ;
    END
  END a_d[479]
  PIN a_d[47]
    DIRECTION OUTPUT ;
    USE SIGNAL ;
    PORT
      LAYER M5 ;
        RECT  5.616 86.316 5.64 86.4 ;
    END
  END a_d[47]
  PIN a_d[480]
    DIRECTION OUTPUT ;
    USE SIGNAL ;
    PORT
      LAYER M3 ;
        RECT  51.84 86.362 51.858 86.4 ;
    END
  END a_d[480]
  PIN a_d[481]
    DIRECTION OUTPUT ;
    USE SIGNAL ;
    PORT
      LAYER M5 ;
        RECT  51.936 86.316 51.96 86.4 ;
    END
  END a_d[481]
  PIN a_d[482]
    DIRECTION OUTPUT ;
    USE SIGNAL ;
    PORT
      LAYER M3 ;
        RECT  52.02 86.362 52.038 86.4 ;
    END
  END a_d[482]
  PIN a_d[483]
    DIRECTION OUTPUT ;
    USE SIGNAL ;
    PORT
      LAYER M5 ;
        RECT  52.128 86.316 52.152 86.4 ;
    END
  END a_d[483]
  PIN a_d[484]
    DIRECTION OUTPUT ;
    USE SIGNAL ;
    PORT
      LAYER M3 ;
        RECT  52.236 86.362 52.254 86.4 ;
    END
  END a_d[484]
  PIN a_d[485]
    DIRECTION OUTPUT ;
    USE SIGNAL ;
    PORT
      LAYER M5 ;
        RECT  52.368 86.316 52.392 86.4 ;
    END
  END a_d[485]
  PIN a_d[486]
    DIRECTION OUTPUT ;
    USE SIGNAL ;
    PORT
      LAYER M3 ;
        RECT  52.452 86.362 52.47 86.4 ;
    END
  END a_d[486]
  PIN a_d[487]
    DIRECTION OUTPUT ;
    USE SIGNAL ;
    PORT
      LAYER M5 ;
        RECT  52.56 86.316 52.584 86.4 ;
    END
  END a_d[487]
  PIN a_d[488]
    DIRECTION OUTPUT ;
    USE SIGNAL ;
    PORT
      LAYER M3 ;
        RECT  52.668 86.362 52.686 86.4 ;
    END
  END a_d[488]
  PIN a_d[489]
    DIRECTION OUTPUT ;
    USE SIGNAL ;
    PORT
      LAYER M5 ;
        RECT  52.8 86.316 52.824 86.4 ;
    END
  END a_d[489]
  PIN a_d[48]
    DIRECTION OUTPUT ;
    USE SIGNAL ;
    PORT
      LAYER M3 ;
        RECT  5.724 86.362 5.742 86.4 ;
    END
  END a_d[48]
  PIN a_d[490]
    DIRECTION OUTPUT ;
    USE SIGNAL ;
    PORT
      LAYER M3 ;
        RECT  52.884 86.362 52.902 86.4 ;
    END
  END a_d[490]
  PIN a_d[491]
    DIRECTION OUTPUT ;
    USE SIGNAL ;
    PORT
      LAYER M5 ;
        RECT  52.992 86.316 53.016 86.4 ;
    END
  END a_d[491]
  PIN a_d[492]
    DIRECTION OUTPUT ;
    USE SIGNAL ;
    PORT
      LAYER M3 ;
        RECT  53.1 86.362 53.118 86.4 ;
    END
  END a_d[492]
  PIN a_d[493]
    DIRECTION OUTPUT ;
    USE SIGNAL ;
    PORT
      LAYER M5 ;
        RECT  53.184 86.316 53.208 86.4 ;
    END
  END a_d[493]
  PIN a_d[494]
    DIRECTION OUTPUT ;
    USE SIGNAL ;
    PORT
      LAYER M3 ;
        RECT  53.316 86.362 53.334 86.4 ;
    END
  END a_d[494]
  PIN a_d[495]
    DIRECTION OUTPUT ;
    USE SIGNAL ;
    PORT
      LAYER M5 ;
        RECT  53.424 86.316 53.448 86.4 ;
    END
  END a_d[495]
  PIN a_d[496]
    DIRECTION OUTPUT ;
    USE SIGNAL ;
    PORT
      LAYER M3 ;
        RECT  53.532 86.362 53.55 86.4 ;
    END
  END a_d[496]
  PIN a_d[497]
    DIRECTION OUTPUT ;
    USE SIGNAL ;
    PORT
      LAYER M5 ;
        RECT  53.616 86.316 53.64 86.4 ;
    END
  END a_d[497]
  PIN a_d[498]
    DIRECTION OUTPUT ;
    USE SIGNAL ;
    PORT
      LAYER M3 ;
        RECT  53.748 86.362 53.766 86.4 ;
    END
  END a_d[498]
  PIN a_d[499]
    DIRECTION OUTPUT ;
    USE SIGNAL ;
    PORT
      LAYER M5 ;
        RECT  53.856 86.316 53.88 86.4 ;
    END
  END a_d[499]
  PIN a_d[49]
    DIRECTION OUTPUT ;
    USE SIGNAL ;
    PORT
      LAYER M5 ;
        RECT  5.808 86.316 5.832 86.4 ;
    END
  END a_d[49]
  PIN a_d[4]
    DIRECTION OUTPUT ;
    USE SIGNAL ;
    PORT
      LAYER M3 ;
        RECT  1.008 86.362 1.026 86.4 ;
    END
  END a_d[4]
  PIN a_d[500]
    DIRECTION OUTPUT ;
    USE SIGNAL ;
    PORT
      LAYER M3 ;
        RECT  53.964 86.362 53.982 86.4 ;
    END
  END a_d[500]
  PIN a_d[501]
    DIRECTION OUTPUT ;
    USE SIGNAL ;
    PORT
      LAYER M5 ;
        RECT  54.048 86.316 54.072 86.4 ;
    END
  END a_d[501]
  PIN a_d[502]
    DIRECTION OUTPUT ;
    USE SIGNAL ;
    PORT
      LAYER M3 ;
        RECT  54.18 86.362 54.198 86.4 ;
    END
  END a_d[502]
  PIN a_d[503]
    DIRECTION OUTPUT ;
    USE SIGNAL ;
    PORT
      LAYER M5 ;
        RECT  54.288 86.316 54.312 86.4 ;
    END
  END a_d[503]
  PIN a_d[504]
    DIRECTION OUTPUT ;
    USE SIGNAL ;
    PORT
      LAYER M3 ;
        RECT  54.396 86.362 54.414 86.4 ;
    END
  END a_d[504]
  PIN a_d[505]
    DIRECTION OUTPUT ;
    USE SIGNAL ;
    PORT
      LAYER M5 ;
        RECT  54.48 86.316 54.504 86.4 ;
    END
  END a_d[505]
  PIN a_d[506]
    DIRECTION OUTPUT ;
    USE SIGNAL ;
    PORT
      LAYER M3 ;
        RECT  54.612 86.362 54.63 86.4 ;
    END
  END a_d[506]
  PIN a_d[507]
    DIRECTION OUTPUT ;
    USE SIGNAL ;
    PORT
      LAYER M5 ;
        RECT  54.72 86.316 54.744 86.4 ;
    END
  END a_d[507]
  PIN a_d[508]
    DIRECTION OUTPUT ;
    USE SIGNAL ;
    PORT
      LAYER M3 ;
        RECT  54.828 86.362 54.846 86.4 ;
    END
  END a_d[508]
  PIN a_d[509]
    DIRECTION OUTPUT ;
    USE SIGNAL ;
    PORT
      LAYER M5 ;
        RECT  54.912 86.316 54.936 86.4 ;
    END
  END a_d[509]
  PIN a_d[50]
    DIRECTION OUTPUT ;
    USE SIGNAL ;
    PORT
      LAYER M3 ;
        RECT  5.94 86.362 5.958 86.4 ;
    END
  END a_d[50]
  PIN a_d[510]
    DIRECTION OUTPUT ;
    USE SIGNAL ;
    PORT
      LAYER M3 ;
        RECT  55.008 86.362 55.026 86.4 ;
    END
  END a_d[510]
  PIN a_d[511]
    DIRECTION OUTPUT ;
    USE SIGNAL ;
    PORT
      LAYER M5 ;
        RECT  55.152 86.316 55.176 86.4 ;
    END
  END a_d[511]
  PIN a_d[512]
    DIRECTION OUTPUT ;
    USE SIGNAL ;
    PORT
      LAYER M3 ;
        RECT  55.224 86.362 55.242 86.4 ;
    END
  END a_d[512]
  PIN a_d[513]
    DIRECTION OUTPUT ;
    USE SIGNAL ;
    PORT
      LAYER M5 ;
        RECT  55.344 86.316 55.368 86.4 ;
    END
  END a_d[513]
  PIN a_d[514]
    DIRECTION OUTPUT ;
    USE SIGNAL ;
    PORT
      LAYER M3 ;
        RECT  55.44 86.362 55.458 86.4 ;
    END
  END a_d[514]
  PIN a_d[515]
    DIRECTION OUTPUT ;
    USE SIGNAL ;
    PORT
      LAYER M5 ;
        RECT  55.536 86.316 55.56 86.4 ;
    END
  END a_d[515]
  PIN a_d[51]
    DIRECTION OUTPUT ;
    USE SIGNAL ;
    PORT
      LAYER M5 ;
        RECT  6.048 86.316 6.072 86.4 ;
    END
  END a_d[51]
  PIN a_d[52]
    DIRECTION OUTPUT ;
    USE SIGNAL ;
    PORT
      LAYER M3 ;
        RECT  6.12 86.362 6.138 86.4 ;
    END
  END a_d[52]
  PIN a_d[53]
    DIRECTION OUTPUT ;
    USE SIGNAL ;
    PORT
      LAYER M5 ;
        RECT  6.24 86.316 6.264 86.4 ;
    END
  END a_d[53]
  PIN a_d[54]
    DIRECTION OUTPUT ;
    USE SIGNAL ;
    PORT
      LAYER M3 ;
        RECT  6.336 86.362 6.354 86.4 ;
    END
  END a_d[54]
  PIN a_d[55]
    DIRECTION OUTPUT ;
    USE SIGNAL ;
    PORT
      LAYER M5 ;
        RECT  6.432 86.316 6.456 86.4 ;
    END
  END a_d[55]
  PIN a_d[56]
    DIRECTION OUTPUT ;
    USE SIGNAL ;
    PORT
      LAYER M3 ;
        RECT  6.552 86.362 6.57 86.4 ;
    END
  END a_d[56]
  PIN a_d[57]
    DIRECTION OUTPUT ;
    USE SIGNAL ;
    PORT
      LAYER M5 ;
        RECT  6.672 86.316 6.696 86.4 ;
    END
  END a_d[57]
  PIN a_d[58]
    DIRECTION OUTPUT ;
    USE SIGNAL ;
    PORT
      LAYER M3 ;
        RECT  6.768 86.362 6.786 86.4 ;
    END
  END a_d[58]
  PIN a_d[59]
    DIRECTION OUTPUT ;
    USE SIGNAL ;
    PORT
      LAYER M5 ;
        RECT  6.864 86.316 6.888 86.4 ;
    END
  END a_d[59]
  PIN a_d[5]
    DIRECTION OUTPUT ;
    USE SIGNAL ;
    PORT
      LAYER M5 ;
        RECT  1.104 86.316 1.128 86.4 ;
    END
  END a_d[5]
  PIN a_d[60]
    DIRECTION OUTPUT ;
    USE SIGNAL ;
    PORT
      LAYER M3 ;
        RECT  6.984 86.362 7.002 86.4 ;
    END
  END a_d[60]
  PIN a_d[61]
    DIRECTION OUTPUT ;
    USE SIGNAL ;
    PORT
      LAYER M5 ;
        RECT  7.104 86.316 7.128 86.4 ;
    END
  END a_d[61]
  PIN a_d[62]
    DIRECTION OUTPUT ;
    USE SIGNAL ;
    PORT
      LAYER M3 ;
        RECT  7.2 86.362 7.218 86.4 ;
    END
  END a_d[62]
  PIN a_d[63]
    DIRECTION OUTPUT ;
    USE SIGNAL ;
    PORT
      LAYER M5 ;
        RECT  7.296 86.316 7.32 86.4 ;
    END
  END a_d[63]
  PIN a_d[64]
    DIRECTION OUTPUT ;
    USE SIGNAL ;
    PORT
      LAYER M3 ;
        RECT  7.416 86.362 7.434 86.4 ;
    END
  END a_d[64]
  PIN a_d[65]
    DIRECTION OUTPUT ;
    USE SIGNAL ;
    PORT
      LAYER M5 ;
        RECT  7.536 86.316 7.56 86.4 ;
    END
  END a_d[65]
  PIN a_d[66]
    DIRECTION OUTPUT ;
    USE SIGNAL ;
    PORT
      LAYER M3 ;
        RECT  7.632 86.362 7.65 86.4 ;
    END
  END a_d[66]
  PIN a_d[67]
    DIRECTION OUTPUT ;
    USE SIGNAL ;
    PORT
      LAYER M5 ;
        RECT  7.728 86.316 7.752 86.4 ;
    END
  END a_d[67]
  PIN a_d[68]
    DIRECTION OUTPUT ;
    USE SIGNAL ;
    PORT
      LAYER M3 ;
        RECT  7.848 86.362 7.866 86.4 ;
    END
  END a_d[68]
  PIN a_d[69]
    DIRECTION OUTPUT ;
    USE SIGNAL ;
    PORT
      LAYER M5 ;
        RECT  7.968 86.316 7.992 86.4 ;
    END
  END a_d[69]
  PIN a_d[6]
    DIRECTION OUTPUT ;
    USE SIGNAL ;
    PORT
      LAYER M3 ;
        RECT  1.224 86.362 1.242 86.4 ;
    END
  END a_d[6]
  PIN a_d[70]
    DIRECTION OUTPUT ;
    USE SIGNAL ;
    PORT
      LAYER M3 ;
        RECT  8.064 86.362 8.082 86.4 ;
    END
  END a_d[70]
  PIN a_d[71]
    DIRECTION OUTPUT ;
    USE SIGNAL ;
    PORT
      LAYER M5 ;
        RECT  8.16 86.316 8.184 86.4 ;
    END
  END a_d[71]
  PIN a_d[72]
    DIRECTION OUTPUT ;
    USE SIGNAL ;
    PORT
      LAYER M3 ;
        RECT  8.28 86.362 8.298 86.4 ;
    END
  END a_d[72]
  PIN a_d[73]
    DIRECTION OUTPUT ;
    USE SIGNAL ;
    PORT
      LAYER M5 ;
        RECT  8.352 86.316 8.376 86.4 ;
    END
  END a_d[73]
  PIN a_d[74]
    DIRECTION OUTPUT ;
    USE SIGNAL ;
    PORT
      LAYER M3 ;
        RECT  8.496 86.362 8.514 86.4 ;
    END
  END a_d[74]
  PIN a_d[75]
    DIRECTION OUTPUT ;
    USE SIGNAL ;
    PORT
      LAYER M5 ;
        RECT  8.592 86.316 8.616 86.4 ;
    END
  END a_d[75]
  PIN a_d[76]
    DIRECTION OUTPUT ;
    USE SIGNAL ;
    PORT
      LAYER M3 ;
        RECT  8.712 86.362 8.73 86.4 ;
    END
  END a_d[76]
  PIN a_d[77]
    DIRECTION OUTPUT ;
    USE SIGNAL ;
    PORT
      LAYER M5 ;
        RECT  8.784 86.316 8.808 86.4 ;
    END
  END a_d[77]
  PIN a_d[78]
    DIRECTION OUTPUT ;
    USE SIGNAL ;
    PORT
      LAYER M3 ;
        RECT  8.928 86.362 8.946 86.4 ;
    END
  END a_d[78]
  PIN a_d[79]
    DIRECTION OUTPUT ;
    USE SIGNAL ;
    PORT
      LAYER M5 ;
        RECT  9.024 86.316 9.048 86.4 ;
    END
  END a_d[79]
  PIN a_d[7]
    DIRECTION OUTPUT ;
    USE SIGNAL ;
    PORT
      LAYER M5 ;
        RECT  1.344 86.316 1.368 86.4 ;
    END
  END a_d[7]
  PIN a_d[80]
    DIRECTION OUTPUT ;
    USE SIGNAL ;
    PORT
      LAYER M3 ;
        RECT  9.108 86.362 9.126 86.4 ;
    END
  END a_d[80]
  PIN a_d[81]
    DIRECTION OUTPUT ;
    USE SIGNAL ;
    PORT
      LAYER M5 ;
        RECT  9.216 86.316 9.24 86.4 ;
    END
  END a_d[81]
  PIN a_d[82]
    DIRECTION OUTPUT ;
    USE SIGNAL ;
    PORT
      LAYER M3 ;
        RECT  9.324 86.362 9.342 86.4 ;
    END
  END a_d[82]
  PIN a_d[83]
    DIRECTION OUTPUT ;
    USE SIGNAL ;
    PORT
      LAYER M5 ;
        RECT  9.456 86.316 9.48 86.4 ;
    END
  END a_d[83]
  PIN a_d[84]
    DIRECTION OUTPUT ;
    USE SIGNAL ;
    PORT
      LAYER M3 ;
        RECT  9.54 86.362 9.558 86.4 ;
    END
  END a_d[84]
  PIN a_d[85]
    DIRECTION OUTPUT ;
    USE SIGNAL ;
    PORT
      LAYER M5 ;
        RECT  9.648 86.316 9.672 86.4 ;
    END
  END a_d[85]
  PIN a_d[86]
    DIRECTION OUTPUT ;
    USE SIGNAL ;
    PORT
      LAYER M3 ;
        RECT  9.756 86.362 9.774 86.4 ;
    END
  END a_d[86]
  PIN a_d[87]
    DIRECTION OUTPUT ;
    USE SIGNAL ;
    PORT
      LAYER M5 ;
        RECT  9.888 86.316 9.912 86.4 ;
    END
  END a_d[87]
  PIN a_d[88]
    DIRECTION OUTPUT ;
    USE SIGNAL ;
    PORT
      LAYER M3 ;
        RECT  9.972 86.362 9.99 86.4 ;
    END
  END a_d[88]
  PIN a_d[89]
    DIRECTION OUTPUT ;
    USE SIGNAL ;
    PORT
      LAYER M5 ;
        RECT  10.08 86.316 10.104 86.4 ;
    END
  END a_d[89]
  PIN a_d[8]
    DIRECTION OUTPUT ;
    USE SIGNAL ;
    PORT
      LAYER M3 ;
        RECT  1.44 86.362 1.458 86.4 ;
    END
  END a_d[8]
  PIN a_d[90]
    DIRECTION OUTPUT ;
    USE SIGNAL ;
    PORT
      LAYER M3 ;
        RECT  10.188 86.362 10.206 86.4 ;
    END
  END a_d[90]
  PIN a_d[91]
    DIRECTION OUTPUT ;
    USE SIGNAL ;
    PORT
      LAYER M5 ;
        RECT  10.272 86.316 10.296 86.4 ;
    END
  END a_d[91]
  PIN a_d[92]
    DIRECTION OUTPUT ;
    USE SIGNAL ;
    PORT
      LAYER M3 ;
        RECT  10.404 86.362 10.422 86.4 ;
    END
  END a_d[92]
  PIN a_d[93]
    DIRECTION OUTPUT ;
    USE SIGNAL ;
    PORT
      LAYER M5 ;
        RECT  10.512 86.316 10.536 86.4 ;
    END
  END a_d[93]
  PIN a_d[94]
    DIRECTION OUTPUT ;
    USE SIGNAL ;
    PORT
      LAYER M3 ;
        RECT  10.62 86.362 10.638 86.4 ;
    END
  END a_d[94]
  PIN a_d[95]
    DIRECTION OUTPUT ;
    USE SIGNAL ;
    PORT
      LAYER M5 ;
        RECT  10.704 86.316 10.728 86.4 ;
    END
  END a_d[95]
  PIN a_d[96]
    DIRECTION OUTPUT ;
    USE SIGNAL ;
    PORT
      LAYER M3 ;
        RECT  10.836 86.362 10.854 86.4 ;
    END
  END a_d[96]
  PIN a_d[97]
    DIRECTION OUTPUT ;
    USE SIGNAL ;
    PORT
      LAYER M5 ;
        RECT  10.944 86.316 10.968 86.4 ;
    END
  END a_d[97]
  PIN a_d[98]
    DIRECTION OUTPUT ;
    USE SIGNAL ;
    PORT
      LAYER M3 ;
        RECT  11.052 86.362 11.07 86.4 ;
    END
  END a_d[98]
  PIN a_d[99]
    DIRECTION OUTPUT ;
    USE SIGNAL ;
    PORT
      LAYER M5 ;
        RECT  11.136 86.316 11.16 86.4 ;
    END
  END a_d[99]
  PIN a_d[9]
    DIRECTION OUTPUT ;
    USE SIGNAL ;
    PORT
      LAYER M5 ;
        RECT  1.536 86.316 1.56 86.4 ;
    END
  END a_d[9]
  PIN b_d[0]
    DIRECTION INPUT ;
    USE SIGNAL ;
    PORT
      LAYER M3 ;
        RECT  5.796 0 5.814 0.038 ;
    END
  END b_d[0]
  PIN b_d[100]
    DIRECTION INPUT ;
    USE SIGNAL ;
    PORT
      LAYER M3 ;
        RECT  15.48 0 15.498 0.038 ;
    END
  END b_d[100]
  PIN b_d[101]
    DIRECTION INPUT ;
    USE SIGNAL ;
    PORT
      LAYER M5 ;
        RECT  15.552 0 15.576 0.084 ;
    END
  END b_d[101]
  PIN b_d[102]
    DIRECTION INPUT ;
    USE SIGNAL ;
    PORT
      LAYER M3 ;
        RECT  15.66 0 15.678 0.038 ;
    END
  END b_d[102]
  PIN b_d[103]
    DIRECTION INPUT ;
    USE SIGNAL ;
    PORT
      LAYER M5 ;
        RECT  15.744 0 15.768 0.084 ;
    END
  END b_d[103]
  PIN b_d[104]
    DIRECTION INPUT ;
    USE SIGNAL ;
    PORT
      LAYER M3 ;
        RECT  15.84 0 15.858 0.038 ;
    END
  END b_d[104]
  PIN b_d[105]
    DIRECTION INPUT ;
    USE SIGNAL ;
    PORT
      LAYER M5 ;
        RECT  15.936 0 15.96 0.084 ;
    END
  END b_d[105]
  PIN b_d[106]
    DIRECTION INPUT ;
    USE SIGNAL ;
    PORT
      LAYER M3 ;
        RECT  16.056 0 16.074 0.038 ;
    END
  END b_d[106]
  PIN b_d[107]
    DIRECTION INPUT ;
    USE SIGNAL ;
    PORT
      LAYER M5 ;
        RECT  16.128 0 16.152 0.084 ;
    END
  END b_d[107]
  PIN b_d[108]
    DIRECTION INPUT ;
    USE SIGNAL ;
    PORT
      LAYER M3 ;
        RECT  16.236 0 16.254 0.038 ;
    END
  END b_d[108]
  PIN b_d[109]
    DIRECTION INPUT ;
    USE SIGNAL ;
    PORT
      LAYER M5 ;
        RECT  16.32 0 16.344 0.084 ;
    END
  END b_d[109]
  PIN b_d[10]
    DIRECTION INPUT ;
    USE SIGNAL ;
    PORT
      LAYER M3 ;
        RECT  6.768 0 6.786 0.038 ;
    END
  END b_d[10]
  PIN b_d[110]
    DIRECTION INPUT ;
    USE SIGNAL ;
    PORT
      LAYER M3 ;
        RECT  16.416 0 16.434 0.038 ;
    END
  END b_d[110]
  PIN b_d[111]
    DIRECTION INPUT ;
    USE SIGNAL ;
    PORT
      LAYER M5 ;
        RECT  16.512 0 16.536 0.084 ;
    END
  END b_d[111]
  PIN b_d[112]
    DIRECTION INPUT ;
    USE SIGNAL ;
    PORT
      LAYER M3 ;
        RECT  16.632 0 16.65 0.038 ;
    END
  END b_d[112]
  PIN b_d[113]
    DIRECTION INPUT ;
    USE SIGNAL ;
    PORT
      LAYER M5 ;
        RECT  16.704 0 16.728 0.084 ;
    END
  END b_d[113]
  PIN b_d[114]
    DIRECTION INPUT ;
    USE SIGNAL ;
    PORT
      LAYER M3 ;
        RECT  16.812 0 16.83 0.038 ;
    END
  END b_d[114]
  PIN b_d[115]
    DIRECTION INPUT ;
    USE SIGNAL ;
    PORT
      LAYER M5 ;
        RECT  16.896 0 16.92 0.084 ;
    END
  END b_d[115]
  PIN b_d[116]
    DIRECTION INPUT ;
    USE SIGNAL ;
    PORT
      LAYER M3 ;
        RECT  16.992 0 17.01 0.038 ;
    END
  END b_d[116]
  PIN b_d[117]
    DIRECTION INPUT ;
    USE SIGNAL ;
    PORT
      LAYER M5 ;
        RECT  17.088 0 17.112 0.084 ;
    END
  END b_d[117]
  PIN b_d[118]
    DIRECTION INPUT ;
    USE SIGNAL ;
    PORT
      LAYER M3 ;
        RECT  17.208 0 17.226 0.038 ;
    END
  END b_d[118]
  PIN b_d[119]
    DIRECTION INPUT ;
    USE SIGNAL ;
    PORT
      LAYER M5 ;
        RECT  17.28 0 17.304 0.084 ;
    END
  END b_d[119]
  PIN b_d[11]
    DIRECTION INPUT ;
    USE SIGNAL ;
    PORT
      LAYER M5 ;
        RECT  6.864 0 6.888 0.084 ;
    END
  END b_d[11]
  PIN b_d[120]
    DIRECTION INPUT ;
    USE SIGNAL ;
    PORT
      LAYER M3 ;
        RECT  17.388 0 17.406 0.038 ;
    END
  END b_d[120]
  PIN b_d[121]
    DIRECTION INPUT ;
    USE SIGNAL ;
    PORT
      LAYER M5 ;
        RECT  17.472 0 17.496 0.084 ;
    END
  END b_d[121]
  PIN b_d[122]
    DIRECTION INPUT ;
    USE SIGNAL ;
    PORT
      LAYER M3 ;
        RECT  17.604 0 17.622 0.038 ;
    END
  END b_d[122]
  PIN b_d[123]
    DIRECTION INPUT ;
    USE SIGNAL ;
    PORT
      LAYER M5 ;
        RECT  17.664 0 17.688 0.084 ;
    END
  END b_d[123]
  PIN b_d[124]
    DIRECTION INPUT ;
    USE SIGNAL ;
    PORT
      LAYER M3 ;
        RECT  17.784 0 17.802 0.038 ;
    END
  END b_d[124]
  PIN b_d[125]
    DIRECTION INPUT ;
    USE SIGNAL ;
    PORT
      LAYER M5 ;
        RECT  17.856 0 17.88 0.084 ;
    END
  END b_d[125]
  PIN b_d[126]
    DIRECTION INPUT ;
    USE SIGNAL ;
    PORT
      LAYER M3 ;
        RECT  17.964 0 17.982 0.038 ;
    END
  END b_d[126]
  PIN b_d[127]
    DIRECTION INPUT ;
    USE SIGNAL ;
    PORT
      LAYER M5 ;
        RECT  18.048 0 18.072 0.084 ;
    END
  END b_d[127]
  PIN b_d[128]
    DIRECTION INPUT ;
    USE SIGNAL ;
    PORT
      LAYER M3 ;
        RECT  18.18 0 18.198 0.038 ;
    END
  END b_d[128]
  PIN b_d[129]
    DIRECTION INPUT ;
    USE SIGNAL ;
    PORT
      LAYER M5 ;
        RECT  18.24 0 18.264 0.084 ;
    END
  END b_d[129]
  PIN b_d[12]
    DIRECTION INPUT ;
    USE SIGNAL ;
    PORT
      LAYER M3 ;
        RECT  6.948 0 6.966 0.038 ;
    END
  END b_d[12]
  PIN b_d[130]
    DIRECTION INPUT ;
    USE SIGNAL ;
    PORT
      LAYER M3 ;
        RECT  18.36 0 18.378 0.038 ;
    END
  END b_d[130]
  PIN b_d[131]
    DIRECTION INPUT ;
    USE SIGNAL ;
    PORT
      LAYER M5 ;
        RECT  18.432 0 18.456 0.084 ;
    END
  END b_d[131]
  PIN b_d[132]
    DIRECTION INPUT ;
    USE SIGNAL ;
    PORT
      LAYER M3 ;
        RECT  18.54 0 18.558 0.038 ;
    END
  END b_d[132]
  PIN b_d[133]
    DIRECTION INPUT ;
    USE SIGNAL ;
    PORT
      LAYER M5 ;
        RECT  18.672 0 18.696 0.084 ;
    END
  END b_d[133]
  PIN b_d[134]
    DIRECTION INPUT ;
    USE SIGNAL ;
    PORT
      LAYER M3 ;
        RECT  18.756 0 18.774 0.038 ;
    END
  END b_d[134]
  PIN b_d[135]
    DIRECTION INPUT ;
    USE SIGNAL ;
    PORT
      LAYER M5 ;
        RECT  18.864 0 18.888 0.084 ;
    END
  END b_d[135]
  PIN b_d[136]
    DIRECTION INPUT ;
    USE SIGNAL ;
    PORT
      LAYER M3 ;
        RECT  18.936 0 18.954 0.038 ;
    END
  END b_d[136]
  PIN b_d[137]
    DIRECTION INPUT ;
    USE SIGNAL ;
    PORT
      LAYER M5 ;
        RECT  19.056 0 19.08 0.084 ;
    END
  END b_d[137]
  PIN b_d[138]
    DIRECTION INPUT ;
    USE SIGNAL ;
    PORT
      LAYER M3 ;
        RECT  19.152 0 19.17 0.038 ;
    END
  END b_d[138]
  PIN b_d[139]
    DIRECTION INPUT ;
    USE SIGNAL ;
    PORT
      LAYER M5 ;
        RECT  19.248 0 19.272 0.084 ;
    END
  END b_d[139]
  PIN b_d[13]
    DIRECTION INPUT ;
    USE SIGNAL ;
    PORT
      LAYER M5 ;
        RECT  7.056 0 7.08 0.084 ;
    END
  END b_d[13]
  PIN b_d[140]
    DIRECTION INPUT ;
    USE SIGNAL ;
    PORT
      LAYER M3 ;
        RECT  19.332 0 19.35 0.038 ;
    END
  END b_d[140]
  PIN b_d[141]
    DIRECTION INPUT ;
    USE SIGNAL ;
    PORT
      LAYER M5 ;
        RECT  19.44 0 19.464 0.084 ;
    END
  END b_d[141]
  PIN b_d[142]
    DIRECTION INPUT ;
    USE SIGNAL ;
    PORT
      LAYER M3 ;
        RECT  19.512 0 19.53 0.038 ;
    END
  END b_d[142]
  PIN b_d[143]
    DIRECTION INPUT ;
    USE SIGNAL ;
    PORT
      LAYER M5 ;
        RECT  19.632 0 19.656 0.084 ;
    END
  END b_d[143]
  PIN b_d[144]
    DIRECTION INPUT ;
    USE SIGNAL ;
    PORT
      LAYER M3 ;
        RECT  19.728 0 19.746 0.038 ;
    END
  END b_d[144]
  PIN b_d[145]
    DIRECTION INPUT ;
    USE SIGNAL ;
    PORT
      LAYER M5 ;
        RECT  19.824 0 19.848 0.084 ;
    END
  END b_d[145]
  PIN b_d[146]
    DIRECTION INPUT ;
    USE SIGNAL ;
    PORT
      LAYER M3 ;
        RECT  19.908 0 19.926 0.038 ;
    END
  END b_d[146]
  PIN b_d[147]
    DIRECTION INPUT ;
    USE SIGNAL ;
    PORT
      LAYER M5 ;
        RECT  20.016 0 20.04 0.084 ;
    END
  END b_d[147]
  PIN b_d[148]
    DIRECTION INPUT ;
    USE SIGNAL ;
    PORT
      LAYER M3 ;
        RECT  20.088 0 20.106 0.038 ;
    END
  END b_d[148]
  PIN b_d[149]
    DIRECTION INPUT ;
    USE SIGNAL ;
    PORT
      LAYER M5 ;
        RECT  20.208 0 20.232 0.084 ;
    END
  END b_d[149]
  PIN b_d[14]
    DIRECTION INPUT ;
    USE SIGNAL ;
    PORT
      LAYER M3 ;
        RECT  7.164 0 7.182 0.038 ;
    END
  END b_d[14]
  PIN b_d[150]
    DIRECTION INPUT ;
    USE SIGNAL ;
    PORT
      LAYER M3 ;
        RECT  20.304 0 20.322 0.038 ;
    END
  END b_d[150]
  PIN b_d[151]
    DIRECTION INPUT ;
    USE SIGNAL ;
    PORT
      LAYER M5 ;
        RECT  20.4 0 20.424 0.084 ;
    END
  END b_d[151]
  PIN b_d[152]
    DIRECTION INPUT ;
    USE SIGNAL ;
    PORT
      LAYER M3 ;
        RECT  20.484 0 20.502 0.038 ;
    END
  END b_d[152]
  PIN b_d[153]
    DIRECTION INPUT ;
    USE SIGNAL ;
    PORT
      LAYER M5 ;
        RECT  20.592 0 20.616 0.084 ;
    END
  END b_d[153]
  PIN b_d[154]
    DIRECTION INPUT ;
    USE SIGNAL ;
    PORT
      LAYER M3 ;
        RECT  20.664 0 20.682 0.038 ;
    END
  END b_d[154]
  PIN b_d[155]
    DIRECTION INPUT ;
    USE SIGNAL ;
    PORT
      LAYER M5 ;
        RECT  20.784 0 20.808 0.084 ;
    END
  END b_d[155]
  PIN b_d[156]
    DIRECTION INPUT ;
    USE SIGNAL ;
    PORT
      LAYER M3 ;
        RECT  20.88 0 20.898 0.038 ;
    END
  END b_d[156]
  PIN b_d[157]
    DIRECTION INPUT ;
    USE SIGNAL ;
    PORT
      LAYER M5 ;
        RECT  20.976 0 21 0.084 ;
    END
  END b_d[157]
  PIN b_d[158]
    DIRECTION INPUT ;
    USE SIGNAL ;
    PORT
      LAYER M3 ;
        RECT  21.06 0 21.078 0.038 ;
    END
  END b_d[158]
  PIN b_d[159]
    DIRECTION INPUT ;
    USE SIGNAL ;
    PORT
      LAYER M5 ;
        RECT  21.168 0 21.192 0.084 ;
    END
  END b_d[159]
  PIN b_d[15]
    DIRECTION INPUT ;
    USE SIGNAL ;
    PORT
      LAYER M5 ;
        RECT  7.248 0 7.272 0.084 ;
    END
  END b_d[15]
  PIN b_d[160]
    DIRECTION INPUT ;
    USE SIGNAL ;
    PORT
      LAYER M3 ;
        RECT  21.276 0 21.294 0.038 ;
    END
  END b_d[160]
  PIN b_d[161]
    DIRECTION INPUT ;
    USE SIGNAL ;
    PORT
      LAYER M5 ;
        RECT  21.36 0 21.384 0.084 ;
    END
  END b_d[161]
  PIN b_d[162]
    DIRECTION INPUT ;
    USE SIGNAL ;
    PORT
      LAYER M3 ;
        RECT  21.456 0 21.474 0.038 ;
    END
  END b_d[162]
  PIN b_d[163]
    DIRECTION INPUT ;
    USE SIGNAL ;
    PORT
      LAYER M5 ;
        RECT  21.552 0 21.576 0.084 ;
    END
  END b_d[163]
  PIN b_d[164]
    DIRECTION INPUT ;
    USE SIGNAL ;
    PORT
      LAYER M3 ;
        RECT  21.636 0 21.654 0.038 ;
    END
  END b_d[164]
  PIN b_d[165]
    DIRECTION INPUT ;
    USE SIGNAL ;
    PORT
      LAYER M5 ;
        RECT  21.744 0 21.768 0.084 ;
    END
  END b_d[165]
  PIN b_d[166]
    DIRECTION INPUT ;
    USE SIGNAL ;
    PORT
      LAYER M3 ;
        RECT  21.852 0 21.87 0.038 ;
    END
  END b_d[166]
  PIN b_d[167]
    DIRECTION INPUT ;
    USE SIGNAL ;
    PORT
      LAYER M5 ;
        RECT  21.936 0 21.96 0.084 ;
    END
  END b_d[167]
  PIN b_d[168]
    DIRECTION INPUT ;
    USE SIGNAL ;
    PORT
      LAYER M3 ;
        RECT  22.032 0 22.05 0.038 ;
    END
  END b_d[168]
  PIN b_d[169]
    DIRECTION INPUT ;
    USE SIGNAL ;
    PORT
      LAYER M5 ;
        RECT  22.128 0 22.152 0.084 ;
    END
  END b_d[169]
  PIN b_d[16]
    DIRECTION INPUT ;
    USE SIGNAL ;
    PORT
      LAYER M3 ;
        RECT  7.344 0 7.362 0.038 ;
    END
  END b_d[16]
  PIN b_d[170]
    DIRECTION INPUT ;
    USE SIGNAL ;
    PORT
      LAYER M3 ;
        RECT  22.212 0 22.23 0.038 ;
    END
  END b_d[170]
  PIN b_d[171]
    DIRECTION INPUT ;
    USE SIGNAL ;
    PORT
      LAYER M5 ;
        RECT  22.32 0 22.344 0.084 ;
    END
  END b_d[171]
  PIN b_d[172]
    DIRECTION INPUT ;
    USE SIGNAL ;
    PORT
      LAYER M3 ;
        RECT  22.428 0 22.446 0.038 ;
    END
  END b_d[172]
  PIN b_d[173]
    DIRECTION INPUT ;
    USE SIGNAL ;
    PORT
      LAYER M5 ;
        RECT  22.512 0 22.536 0.084 ;
    END
  END b_d[173]
  PIN b_d[174]
    DIRECTION INPUT ;
    USE SIGNAL ;
    PORT
      LAYER M3 ;
        RECT  22.608 0 22.626 0.038 ;
    END
  END b_d[174]
  PIN b_d[175]
    DIRECTION INPUT ;
    USE SIGNAL ;
    PORT
      LAYER M5 ;
        RECT  22.704 0 22.728 0.084 ;
    END
  END b_d[175]
  PIN b_d[176]
    DIRECTION INPUT ;
    USE SIGNAL ;
    PORT
      LAYER M3 ;
        RECT  22.824 0 22.842 0.038 ;
    END
  END b_d[176]
  PIN b_d[177]
    DIRECTION INPUT ;
    USE SIGNAL ;
    PORT
      LAYER M5 ;
        RECT  22.896 0 22.92 0.084 ;
    END
  END b_d[177]
  PIN b_d[178]
    DIRECTION INPUT ;
    USE SIGNAL ;
    PORT
      LAYER M3 ;
        RECT  23.004 0 23.022 0.038 ;
    END
  END b_d[178]
  PIN b_d[179]
    DIRECTION INPUT ;
    USE SIGNAL ;
    PORT
      LAYER M5 ;
        RECT  23.088 0 23.112 0.084 ;
    END
  END b_d[179]
  PIN b_d[17]
    DIRECTION INPUT ;
    USE SIGNAL ;
    PORT
      LAYER M5 ;
        RECT  7.44 0 7.464 0.084 ;
    END
  END b_d[17]
  PIN b_d[180]
    DIRECTION INPUT ;
    USE SIGNAL ;
    PORT
      LAYER M3 ;
        RECT  23.184 0 23.202 0.038 ;
    END
  END b_d[180]
  PIN b_d[181]
    DIRECTION INPUT ;
    USE SIGNAL ;
    PORT
      LAYER M5 ;
        RECT  23.28 0 23.304 0.084 ;
    END
  END b_d[181]
  PIN b_d[182]
    DIRECTION INPUT ;
    USE SIGNAL ;
    PORT
      LAYER M3 ;
        RECT  23.4 0 23.418 0.038 ;
    END
  END b_d[182]
  PIN b_d[183]
    DIRECTION INPUT ;
    USE SIGNAL ;
    PORT
      LAYER M5 ;
        RECT  23.472 0 23.496 0.084 ;
    END
  END b_d[183]
  PIN b_d[184]
    DIRECTION INPUT ;
    USE SIGNAL ;
    PORT
      LAYER M3 ;
        RECT  23.58 0 23.598 0.038 ;
    END
  END b_d[184]
  PIN b_d[185]
    DIRECTION INPUT ;
    USE SIGNAL ;
    PORT
      LAYER M5 ;
        RECT  23.664 0 23.688 0.084 ;
    END
  END b_d[185]
  PIN b_d[186]
    DIRECTION INPUT ;
    USE SIGNAL ;
    PORT
      LAYER M3 ;
        RECT  23.76 0 23.778 0.038 ;
    END
  END b_d[186]
  PIN b_d[187]
    DIRECTION INPUT ;
    USE SIGNAL ;
    PORT
      LAYER M5 ;
        RECT  23.856 0 23.88 0.084 ;
    END
  END b_d[187]
  PIN b_d[188]
    DIRECTION INPUT ;
    USE SIGNAL ;
    PORT
      LAYER M3 ;
        RECT  23.976 0 23.994 0.038 ;
    END
  END b_d[188]
  PIN b_d[189]
    DIRECTION INPUT ;
    USE SIGNAL ;
    PORT
      LAYER M5 ;
        RECT  24.048 0 24.072 0.084 ;
    END
  END b_d[189]
  PIN b_d[18]
    DIRECTION INPUT ;
    USE SIGNAL ;
    PORT
      LAYER M3 ;
        RECT  7.524 0 7.542 0.038 ;
    END
  END b_d[18]
  PIN b_d[190]
    DIRECTION INPUT ;
    USE SIGNAL ;
    PORT
      LAYER M3 ;
        RECT  24.156 0 24.174 0.038 ;
    END
  END b_d[190]
  PIN b_d[191]
    DIRECTION INPUT ;
    USE SIGNAL ;
    PORT
      LAYER M5 ;
        RECT  24.24 0 24.264 0.084 ;
    END
  END b_d[191]
  PIN b_d[192]
    DIRECTION INPUT ;
    USE SIGNAL ;
    PORT
      LAYER M3 ;
        RECT  24.336 0 24.354 0.038 ;
    END
  END b_d[192]
  PIN b_d[193]
    DIRECTION INPUT ;
    USE SIGNAL ;
    PORT
      LAYER M5 ;
        RECT  24.432 0 24.456 0.084 ;
    END
  END b_d[193]
  PIN b_d[194]
    DIRECTION INPUT ;
    USE SIGNAL ;
    PORT
      LAYER M3 ;
        RECT  24.552 0 24.57 0.038 ;
    END
  END b_d[194]
  PIN b_d[195]
    DIRECTION INPUT ;
    USE SIGNAL ;
    PORT
      LAYER M5 ;
        RECT  24.624 0 24.648 0.084 ;
    END
  END b_d[195]
  PIN b_d[196]
    DIRECTION INPUT ;
    USE SIGNAL ;
    PORT
      LAYER M3 ;
        RECT  24.732 0 24.75 0.038 ;
    END
  END b_d[196]
  PIN b_d[197]
    DIRECTION INPUT ;
    USE SIGNAL ;
    PORT
      LAYER M5 ;
        RECT  24.816 0 24.84 0.084 ;
    END
  END b_d[197]
  PIN b_d[198]
    DIRECTION INPUT ;
    USE SIGNAL ;
    PORT
      LAYER M3 ;
        RECT  24.948 0 24.966 0.038 ;
    END
  END b_d[198]
  PIN b_d[199]
    DIRECTION INPUT ;
    USE SIGNAL ;
    PORT
      LAYER M5 ;
        RECT  25.008 0 25.032 0.084 ;
    END
  END b_d[199]
  PIN b_d[19]
    DIRECTION INPUT ;
    USE SIGNAL ;
    PORT
      LAYER M5 ;
        RECT  7.632 0 7.656 0.084 ;
    END
  END b_d[19]
  PIN b_d[1]
    DIRECTION INPUT ;
    USE SIGNAL ;
    PORT
      LAYER M5 ;
        RECT  5.904 0 5.928 0.084 ;
    END
  END b_d[1]
  PIN b_d[200]
    DIRECTION INPUT ;
    USE SIGNAL ;
    PORT
      LAYER M3 ;
        RECT  25.128 0 25.146 0.038 ;
    END
  END b_d[200]
  PIN b_d[201]
    DIRECTION INPUT ;
    USE SIGNAL ;
    PORT
      LAYER M5 ;
        RECT  25.2 0 25.224 0.084 ;
    END
  END b_d[201]
  PIN b_d[202]
    DIRECTION INPUT ;
    USE SIGNAL ;
    PORT
      LAYER M3 ;
        RECT  25.308 0 25.326 0.038 ;
    END
  END b_d[202]
  PIN b_d[203]
    DIRECTION INPUT ;
    USE SIGNAL ;
    PORT
      LAYER M5 ;
        RECT  25.392 0 25.416 0.084 ;
    END
  END b_d[203]
  PIN b_d[204]
    DIRECTION INPUT ;
    USE SIGNAL ;
    PORT
      LAYER M3 ;
        RECT  25.524 0 25.542 0.038 ;
    END
  END b_d[204]
  PIN b_d[205]
    DIRECTION INPUT ;
    USE SIGNAL ;
    PORT
      LAYER M5 ;
        RECT  25.584 0 25.608 0.084 ;
    END
  END b_d[205]
  PIN b_d[206]
    DIRECTION INPUT ;
    USE SIGNAL ;
    PORT
      LAYER M3 ;
        RECT  25.704 0 25.722 0.038 ;
    END
  END b_d[206]
  PIN b_d[207]
    DIRECTION INPUT ;
    USE SIGNAL ;
    PORT
      LAYER M5 ;
        RECT  25.776 0 25.8 0.084 ;
    END
  END b_d[207]
  PIN b_d[208]
    DIRECTION INPUT ;
    USE SIGNAL ;
    PORT
      LAYER M3 ;
        RECT  25.884 0 25.902 0.038 ;
    END
  END b_d[208]
  PIN b_d[209]
    DIRECTION INPUT ;
    USE SIGNAL ;
    PORT
      LAYER M5 ;
        RECT  26.016 0 26.04 0.084 ;
    END
  END b_d[209]
  PIN b_d[20]
    DIRECTION INPUT ;
    USE SIGNAL ;
    PORT
      LAYER M3 ;
        RECT  7.74 0 7.758 0.038 ;
    END
  END b_d[20]
  PIN b_d[210]
    DIRECTION INPUT ;
    USE SIGNAL ;
    PORT
      LAYER M3 ;
        RECT  26.1 0 26.118 0.038 ;
    END
  END b_d[210]
  PIN b_d[211]
    DIRECTION INPUT ;
    USE SIGNAL ;
    PORT
      LAYER M5 ;
        RECT  26.208 0 26.232 0.084 ;
    END
  END b_d[211]
  PIN b_d[212]
    DIRECTION INPUT ;
    USE SIGNAL ;
    PORT
      LAYER M3 ;
        RECT  26.28 0 26.298 0.038 ;
    END
  END b_d[212]
  PIN b_d[213]
    DIRECTION INPUT ;
    USE SIGNAL ;
    PORT
      LAYER M5 ;
        RECT  26.4 0 26.424 0.084 ;
    END
  END b_d[213]
  PIN b_d[214]
    DIRECTION INPUT ;
    USE SIGNAL ;
    PORT
      LAYER M3 ;
        RECT  26.496 0 26.514 0.038 ;
    END
  END b_d[214]
  PIN b_d[215]
    DIRECTION INPUT ;
    USE SIGNAL ;
    PORT
      LAYER M5 ;
        RECT  26.592 0 26.616 0.084 ;
    END
  END b_d[215]
  PIN b_d[216]
    DIRECTION INPUT ;
    USE SIGNAL ;
    PORT
      LAYER M3 ;
        RECT  26.676 0 26.694 0.038 ;
    END
  END b_d[216]
  PIN b_d[217]
    DIRECTION INPUT ;
    USE SIGNAL ;
    PORT
      LAYER M5 ;
        RECT  26.784 0 26.808 0.084 ;
    END
  END b_d[217]
  PIN b_d[218]
    DIRECTION INPUT ;
    USE SIGNAL ;
    PORT
      LAYER M3 ;
        RECT  26.856 0 26.874 0.038 ;
    END
  END b_d[218]
  PIN b_d[219]
    DIRECTION INPUT ;
    USE SIGNAL ;
    PORT
      LAYER M5 ;
        RECT  26.976 0 27 0.084 ;
    END
  END b_d[219]
  PIN b_d[21]
    DIRECTION INPUT ;
    USE SIGNAL ;
    PORT
      LAYER M5 ;
        RECT  7.824 0 7.848 0.084 ;
    END
  END b_d[21]
  PIN b_d[220]
    DIRECTION INPUT ;
    USE SIGNAL ;
    PORT
      LAYER M3 ;
        RECT  27.072 0 27.09 0.038 ;
    END
  END b_d[220]
  PIN b_d[221]
    DIRECTION INPUT ;
    USE SIGNAL ;
    PORT
      LAYER M5 ;
        RECT  27.168 0 27.192 0.084 ;
    END
  END b_d[221]
  PIN b_d[222]
    DIRECTION INPUT ;
    USE SIGNAL ;
    PORT
      LAYER M3 ;
        RECT  27.252 0 27.27 0.038 ;
    END
  END b_d[222]
  PIN b_d[223]
    DIRECTION INPUT ;
    USE SIGNAL ;
    PORT
      LAYER M5 ;
        RECT  27.36 0 27.384 0.084 ;
    END
  END b_d[223]
  PIN b_d[224]
    DIRECTION INPUT ;
    USE SIGNAL ;
    PORT
      LAYER M3 ;
        RECT  27.432 0 27.45 0.038 ;
    END
  END b_d[224]
  PIN b_d[225]
    DIRECTION INPUT ;
    USE SIGNAL ;
    PORT
      LAYER M5 ;
        RECT  27.552 0 27.576 0.084 ;
    END
  END b_d[225]
  PIN b_d[226]
    DIRECTION INPUT ;
    USE SIGNAL ;
    PORT
      LAYER M3 ;
        RECT  27.648 0 27.666 0.038 ;
    END
  END b_d[226]
  PIN b_d[227]
    DIRECTION INPUT ;
    USE SIGNAL ;
    PORT
      LAYER M5 ;
        RECT  27.744 0 27.768 0.084 ;
    END
  END b_d[227]
  PIN b_d[228]
    DIRECTION INPUT ;
    USE SIGNAL ;
    PORT
      LAYER M3 ;
        RECT  27.828 0 27.846 0.038 ;
    END
  END b_d[228]
  PIN b_d[229]
    DIRECTION INPUT ;
    USE SIGNAL ;
    PORT
      LAYER M5 ;
        RECT  27.936 0 27.96 0.084 ;
    END
  END b_d[229]
  PIN b_d[22]
    DIRECTION INPUT ;
    USE SIGNAL ;
    PORT
      LAYER M3 ;
        RECT  7.92 0 7.938 0.038 ;
    END
  END b_d[22]
  PIN b_d[230]
    DIRECTION INPUT ;
    USE SIGNAL ;
    PORT
      LAYER M3 ;
        RECT  28.008 0 28.026 0.038 ;
    END
  END b_d[230]
  PIN b_d[231]
    DIRECTION INPUT ;
    USE SIGNAL ;
    PORT
      LAYER M5 ;
        RECT  28.128 0 28.152 0.084 ;
    END
  END b_d[231]
  PIN b_d[232]
    DIRECTION INPUT ;
    USE SIGNAL ;
    PORT
      LAYER M3 ;
        RECT  28.224 0 28.242 0.038 ;
    END
  END b_d[232]
  PIN b_d[233]
    DIRECTION INPUT ;
    USE SIGNAL ;
    PORT
      LAYER M5 ;
        RECT  28.32 0 28.344 0.084 ;
    END
  END b_d[233]
  PIN b_d[234]
    DIRECTION INPUT ;
    USE SIGNAL ;
    PORT
      LAYER M3 ;
        RECT  28.404 0 28.422 0.038 ;
    END
  END b_d[234]
  PIN b_d[235]
    DIRECTION INPUT ;
    USE SIGNAL ;
    PORT
      LAYER M5 ;
        RECT  28.512 0 28.536 0.084 ;
    END
  END b_d[235]
  PIN b_d[236]
    DIRECTION INPUT ;
    USE SIGNAL ;
    PORT
      LAYER M3 ;
        RECT  28.62 0 28.638 0.038 ;
    END
  END b_d[236]
  PIN b_d[237]
    DIRECTION INPUT ;
    USE SIGNAL ;
    PORT
      LAYER M5 ;
        RECT  28.704 0 28.728 0.084 ;
    END
  END b_d[237]
  PIN b_d[238]
    DIRECTION INPUT ;
    USE SIGNAL ;
    PORT
      LAYER M3 ;
        RECT  28.8 0 28.818 0.038 ;
    END
  END b_d[238]
  PIN b_d[239]
    DIRECTION INPUT ;
    USE SIGNAL ;
    PORT
      LAYER M5 ;
        RECT  28.896 0 28.92 0.084 ;
    END
  END b_d[239]
  PIN b_d[23]
    DIRECTION INPUT ;
    USE SIGNAL ;
    PORT
      LAYER M5 ;
        RECT  8.016 0 8.04 0.084 ;
    END
  END b_d[23]
  PIN b_d[240]
    DIRECTION INPUT ;
    USE SIGNAL ;
    PORT
      LAYER M3 ;
        RECT  28.98 0 28.998 0.038 ;
    END
  END b_d[240]
  PIN b_d[241]
    DIRECTION INPUT ;
    USE SIGNAL ;
    PORT
      LAYER M5 ;
        RECT  29.088 0 29.112 0.084 ;
    END
  END b_d[241]
  PIN b_d[242]
    DIRECTION INPUT ;
    USE SIGNAL ;
    PORT
      LAYER M3 ;
        RECT  29.196 0 29.214 0.038 ;
    END
  END b_d[242]
  PIN b_d[243]
    DIRECTION INPUT ;
    USE SIGNAL ;
    PORT
      LAYER M5 ;
        RECT  29.28 0 29.304 0.084 ;
    END
  END b_d[243]
  PIN b_d[244]
    DIRECTION INPUT ;
    USE SIGNAL ;
    PORT
      LAYER M3 ;
        RECT  29.376 0 29.394 0.038 ;
    END
  END b_d[244]
  PIN b_d[245]
    DIRECTION INPUT ;
    USE SIGNAL ;
    PORT
      LAYER M5 ;
        RECT  29.472 0 29.496 0.084 ;
    END
  END b_d[245]
  PIN b_d[246]
    DIRECTION INPUT ;
    USE SIGNAL ;
    PORT
      LAYER M3 ;
        RECT  29.556 0 29.574 0.038 ;
    END
  END b_d[246]
  PIN b_d[247]
    DIRECTION INPUT ;
    USE SIGNAL ;
    PORT
      LAYER M5 ;
        RECT  29.664 0 29.688 0.084 ;
    END
  END b_d[247]
  PIN b_d[248]
    DIRECTION INPUT ;
    USE SIGNAL ;
    PORT
      LAYER M3 ;
        RECT  29.772 0 29.79 0.038 ;
    END
  END b_d[248]
  PIN b_d[249]
    DIRECTION INPUT ;
    USE SIGNAL ;
    PORT
      LAYER M5 ;
        RECT  29.856 0 29.88 0.084 ;
    END
  END b_d[249]
  PIN b_d[24]
    DIRECTION INPUT ;
    USE SIGNAL ;
    PORT
      LAYER M3 ;
        RECT  8.136 0 8.154 0.038 ;
    END
  END b_d[24]
  PIN b_d[250]
    DIRECTION INPUT ;
    USE SIGNAL ;
    PORT
      LAYER M3 ;
        RECT  29.952 0 29.97 0.038 ;
    END
  END b_d[250]
  PIN b_d[251]
    DIRECTION INPUT ;
    USE SIGNAL ;
    PORT
      LAYER M5 ;
        RECT  30.048 0 30.072 0.084 ;
    END
  END b_d[251]
  PIN b_d[252]
    DIRECTION INPUT ;
    USE SIGNAL ;
    PORT
      LAYER M3 ;
        RECT  30.168 0 30.186 0.038 ;
    END
  END b_d[252]
  PIN b_d[253]
    DIRECTION INPUT ;
    USE SIGNAL ;
    PORT
      LAYER M5 ;
        RECT  30.24 0 30.264 0.084 ;
    END
  END b_d[253]
  PIN b_d[254]
    DIRECTION INPUT ;
    USE SIGNAL ;
    PORT
      LAYER M3 ;
        RECT  30.348 0 30.366 0.038 ;
    END
  END b_d[254]
  PIN b_d[255]
    DIRECTION INPUT ;
    USE SIGNAL ;
    PORT
      LAYER M5 ;
        RECT  30.432 0 30.456 0.084 ;
    END
  END b_d[255]
  PIN b_d[256]
    DIRECTION INPUT ;
    USE SIGNAL ;
    PORT
      LAYER M3 ;
        RECT  30.528 0 30.546 0.038 ;
    END
  END b_d[256]
  PIN b_d[257]
    DIRECTION INPUT ;
    USE SIGNAL ;
    PORT
      LAYER M5 ;
        RECT  30.624 0 30.648 0.084 ;
    END
  END b_d[257]
  PIN b_d[258]
    DIRECTION INPUT ;
    USE SIGNAL ;
    PORT
      LAYER M3 ;
        RECT  30.744 0 30.762 0.038 ;
    END
  END b_d[258]
  PIN b_d[259]
    DIRECTION INPUT ;
    USE SIGNAL ;
    PORT
      LAYER M5 ;
        RECT  30.816 0 30.84 0.084 ;
    END
  END b_d[259]
  PIN b_d[25]
    DIRECTION INPUT ;
    USE SIGNAL ;
    PORT
      LAYER M5 ;
        RECT  8.208 0 8.232 0.084 ;
    END
  END b_d[25]
  PIN b_d[260]
    DIRECTION INPUT ;
    USE SIGNAL ;
    PORT
      LAYER M3 ;
        RECT  30.924 0 30.942 0.038 ;
    END
  END b_d[260]
  PIN b_d[261]
    DIRECTION INPUT ;
    USE SIGNAL ;
    PORT
      LAYER M5 ;
        RECT  31.008 0 31.032 0.084 ;
    END
  END b_d[261]
  PIN b_d[262]
    DIRECTION INPUT ;
    USE SIGNAL ;
    PORT
      LAYER M3 ;
        RECT  31.104 0 31.122 0.038 ;
    END
  END b_d[262]
  PIN b_d[263]
    DIRECTION INPUT ;
    USE SIGNAL ;
    PORT
      LAYER M5 ;
        RECT  31.2 0 31.224 0.084 ;
    END
  END b_d[263]
  PIN b_d[264]
    DIRECTION INPUT ;
    USE SIGNAL ;
    PORT
      LAYER M3 ;
        RECT  31.32 0 31.338 0.038 ;
    END
  END b_d[264]
  PIN b_d[265]
    DIRECTION INPUT ;
    USE SIGNAL ;
    PORT
      LAYER M5 ;
        RECT  31.392 0 31.416 0.084 ;
    END
  END b_d[265]
  PIN b_d[266]
    DIRECTION INPUT ;
    USE SIGNAL ;
    PORT
      LAYER M3 ;
        RECT  31.5 0 31.518 0.038 ;
    END
  END b_d[266]
  PIN b_d[267]
    DIRECTION INPUT ;
    USE SIGNAL ;
    PORT
      LAYER M5 ;
        RECT  31.584 0 31.608 0.084 ;
    END
  END b_d[267]
  PIN b_d[268]
    DIRECTION INPUT ;
    USE SIGNAL ;
    PORT
      LAYER M3 ;
        RECT  31.68 0 31.698 0.038 ;
    END
  END b_d[268]
  PIN b_d[269]
    DIRECTION INPUT ;
    USE SIGNAL ;
    PORT
      LAYER M5 ;
        RECT  31.776 0 31.8 0.084 ;
    END
  END b_d[269]
  PIN b_d[26]
    DIRECTION INPUT ;
    USE SIGNAL ;
    PORT
      LAYER M3 ;
        RECT  8.316 0 8.334 0.038 ;
    END
  END b_d[26]
  PIN b_d[270]
    DIRECTION INPUT ;
    USE SIGNAL ;
    PORT
      LAYER M3 ;
        RECT  31.896 0 31.914 0.038 ;
    END
  END b_d[270]
  PIN b_d[271]
    DIRECTION INPUT ;
    USE SIGNAL ;
    PORT
      LAYER M5 ;
        RECT  31.968 0 31.992 0.084 ;
    END
  END b_d[271]
  PIN b_d[272]
    DIRECTION INPUT ;
    USE SIGNAL ;
    PORT
      LAYER M3 ;
        RECT  32.076 0 32.094 0.038 ;
    END
  END b_d[272]
  PIN b_d[273]
    DIRECTION INPUT ;
    USE SIGNAL ;
    PORT
      LAYER M5 ;
        RECT  32.16 0 32.184 0.084 ;
    END
  END b_d[273]
  PIN b_d[274]
    DIRECTION INPUT ;
    USE SIGNAL ;
    PORT
      LAYER M3 ;
        RECT  32.292 0 32.31 0.038 ;
    END
  END b_d[274]
  PIN b_d[275]
    DIRECTION INPUT ;
    USE SIGNAL ;
    PORT
      LAYER M5 ;
        RECT  32.352 0 32.376 0.084 ;
    END
  END b_d[275]
  PIN b_d[276]
    DIRECTION INPUT ;
    USE SIGNAL ;
    PORT
      LAYER M3 ;
        RECT  32.472 0 32.49 0.038 ;
    END
  END b_d[276]
  PIN b_d[277]
    DIRECTION INPUT ;
    USE SIGNAL ;
    PORT
      LAYER M5 ;
        RECT  32.544 0 32.568 0.084 ;
    END
  END b_d[277]
  PIN b_d[278]
    DIRECTION INPUT ;
    USE SIGNAL ;
    PORT
      LAYER M3 ;
        RECT  32.652 0 32.67 0.038 ;
    END
  END b_d[278]
  PIN b_d[279]
    DIRECTION INPUT ;
    USE SIGNAL ;
    PORT
      LAYER M5 ;
        RECT  32.736 0 32.76 0.084 ;
    END
  END b_d[279]
  PIN b_d[27]
    DIRECTION INPUT ;
    USE SIGNAL ;
    PORT
      LAYER M5 ;
        RECT  8.4 0 8.424 0.084 ;
    END
  END b_d[27]
  PIN b_d[280]
    DIRECTION INPUT ;
    USE SIGNAL ;
    PORT
      LAYER M3 ;
        RECT  32.868 0 32.886 0.038 ;
    END
  END b_d[280]
  PIN b_d[281]
    DIRECTION INPUT ;
    USE SIGNAL ;
    PORT
      LAYER M5 ;
        RECT  32.928 0 32.952 0.084 ;
    END
  END b_d[281]
  PIN b_d[282]
    DIRECTION INPUT ;
    USE SIGNAL ;
    PORT
      LAYER M3 ;
        RECT  33.048 0 33.066 0.038 ;
    END
  END b_d[282]
  PIN b_d[283]
    DIRECTION INPUT ;
    USE SIGNAL ;
    PORT
      LAYER M5 ;
        RECT  33.12 0 33.144 0.084 ;
    END
  END b_d[283]
  PIN b_d[284]
    DIRECTION INPUT ;
    USE SIGNAL ;
    PORT
      LAYER M3 ;
        RECT  33.228 0 33.246 0.038 ;
    END
  END b_d[284]
  PIN b_d[285]
    DIRECTION INPUT ;
    USE SIGNAL ;
    PORT
      LAYER M5 ;
        RECT  33.312 0 33.336 0.084 ;
    END
  END b_d[285]
  PIN b_d[286]
    DIRECTION INPUT ;
    USE SIGNAL ;
    PORT
      LAYER M3 ;
        RECT  33.444 0 33.462 0.038 ;
    END
  END b_d[286]
  PIN b_d[287]
    DIRECTION INPUT ;
    USE SIGNAL ;
    PORT
      LAYER M5 ;
        RECT  33.552 0 33.576 0.084 ;
    END
  END b_d[287]
  PIN b_d[288]
    DIRECTION INPUT ;
    USE SIGNAL ;
    PORT
      LAYER M3 ;
        RECT  33.624 0 33.642 0.038 ;
    END
  END b_d[288]
  PIN b_d[289]
    DIRECTION INPUT ;
    USE SIGNAL ;
    PORT
      LAYER M5 ;
        RECT  33.744 0 33.768 0.084 ;
    END
  END b_d[289]
  PIN b_d[28]
    DIRECTION INPUT ;
    USE SIGNAL ;
    PORT
      LAYER M3 ;
        RECT  8.496 0 8.514 0.038 ;
    END
  END b_d[28]
  PIN b_d[290]
    DIRECTION INPUT ;
    USE SIGNAL ;
    PORT
      LAYER M3 ;
        RECT  33.804 0 33.822 0.038 ;
    END
  END b_d[290]
  PIN b_d[291]
    DIRECTION INPUT ;
    USE SIGNAL ;
    PORT
      LAYER M5 ;
        RECT  33.936 0 33.96 0.084 ;
    END
  END b_d[291]
  PIN b_d[292]
    DIRECTION INPUT ;
    USE SIGNAL ;
    PORT
      LAYER M3 ;
        RECT  34.02 0 34.038 0.038 ;
    END
  END b_d[292]
  PIN b_d[293]
    DIRECTION INPUT ;
    USE SIGNAL ;
    PORT
      LAYER M5 ;
        RECT  34.128 0 34.152 0.084 ;
    END
  END b_d[293]
  PIN b_d[294]
    DIRECTION INPUT ;
    USE SIGNAL ;
    PORT
      LAYER M3 ;
        RECT  34.2 0 34.218 0.038 ;
    END
  END b_d[294]
  PIN b_d[295]
    DIRECTION INPUT ;
    USE SIGNAL ;
    PORT
      LAYER M5 ;
        RECT  34.32 0 34.344 0.084 ;
    END
  END b_d[295]
  PIN b_d[296]
    DIRECTION INPUT ;
    USE SIGNAL ;
    PORT
      LAYER M3 ;
        RECT  34.416 0 34.434 0.038 ;
    END
  END b_d[296]
  PIN b_d[297]
    DIRECTION INPUT ;
    USE SIGNAL ;
    PORT
      LAYER M5 ;
        RECT  34.512 0 34.536 0.084 ;
    END
  END b_d[297]
  PIN b_d[298]
    DIRECTION INPUT ;
    USE SIGNAL ;
    PORT
      LAYER M3 ;
        RECT  34.596 0 34.614 0.038 ;
    END
  END b_d[298]
  PIN b_d[299]
    DIRECTION INPUT ;
    USE SIGNAL ;
    PORT
      LAYER M5 ;
        RECT  34.704 0 34.728 0.084 ;
    END
  END b_d[299]
  PIN b_d[29]
    DIRECTION INPUT ;
    USE SIGNAL ;
    PORT
      LAYER M5 ;
        RECT  8.592 0 8.616 0.084 ;
    END
  END b_d[29]
  PIN b_d[2]
    DIRECTION INPUT ;
    USE SIGNAL ;
    PORT
      LAYER M3 ;
        RECT  5.976 0 5.994 0.038 ;
    END
  END b_d[2]
  PIN b_d[300]
    DIRECTION INPUT ;
    USE SIGNAL ;
    PORT
      LAYER M3 ;
        RECT  34.776 0 34.794 0.038 ;
    END
  END b_d[300]
  PIN b_d[301]
    DIRECTION INPUT ;
    USE SIGNAL ;
    PORT
      LAYER M5 ;
        RECT  34.896 0 34.92 0.084 ;
    END
  END b_d[301]
  PIN b_d[302]
    DIRECTION INPUT ;
    USE SIGNAL ;
    PORT
      LAYER M3 ;
        RECT  34.992 0 35.01 0.038 ;
    END
  END b_d[302]
  PIN b_d[303]
    DIRECTION INPUT ;
    USE SIGNAL ;
    PORT
      LAYER M5 ;
        RECT  35.088 0 35.112 0.084 ;
    END
  END b_d[303]
  PIN b_d[304]
    DIRECTION INPUT ;
    USE SIGNAL ;
    PORT
      LAYER M3 ;
        RECT  35.172 0 35.19 0.038 ;
    END
  END b_d[304]
  PIN b_d[305]
    DIRECTION INPUT ;
    USE SIGNAL ;
    PORT
      LAYER M5 ;
        RECT  35.28 0 35.304 0.084 ;
    END
  END b_d[305]
  PIN b_d[306]
    DIRECTION INPUT ;
    USE SIGNAL ;
    PORT
      LAYER M3 ;
        RECT  35.352 0 35.37 0.038 ;
    END
  END b_d[306]
  PIN b_d[307]
    DIRECTION INPUT ;
    USE SIGNAL ;
    PORT
      LAYER M5 ;
        RECT  35.472 0 35.496 0.084 ;
    END
  END b_d[307]
  PIN b_d[308]
    DIRECTION INPUT ;
    USE SIGNAL ;
    PORT
      LAYER M3 ;
        RECT  35.568 0 35.586 0.038 ;
    END
  END b_d[308]
  PIN b_d[309]
    DIRECTION INPUT ;
    USE SIGNAL ;
    PORT
      LAYER M5 ;
        RECT  35.664 0 35.688 0.084 ;
    END
  END b_d[309]
  PIN b_d[30]
    DIRECTION INPUT ;
    USE SIGNAL ;
    PORT
      LAYER M3 ;
        RECT  8.712 0 8.73 0.038 ;
    END
  END b_d[30]
  PIN b_d[310]
    DIRECTION INPUT ;
    USE SIGNAL ;
    PORT
      LAYER M3 ;
        RECT  35.748 0 35.766 0.038 ;
    END
  END b_d[310]
  PIN b_d[311]
    DIRECTION INPUT ;
    USE SIGNAL ;
    PORT
      LAYER M5 ;
        RECT  35.856 0 35.88 0.084 ;
    END
  END b_d[311]
  PIN b_d[312]
    DIRECTION INPUT ;
    USE SIGNAL ;
    PORT
      LAYER M3 ;
        RECT  35.964 0 35.982 0.038 ;
    END
  END b_d[312]
  PIN b_d[313]
    DIRECTION INPUT ;
    USE SIGNAL ;
    PORT
      LAYER M5 ;
        RECT  36.048 0 36.072 0.084 ;
    END
  END b_d[313]
  PIN b_d[314]
    DIRECTION INPUT ;
    USE SIGNAL ;
    PORT
      LAYER M3 ;
        RECT  36.144 0 36.162 0.038 ;
    END
  END b_d[314]
  PIN b_d[315]
    DIRECTION INPUT ;
    USE SIGNAL ;
    PORT
      LAYER M5 ;
        RECT  36.24 0 36.264 0.084 ;
    END
  END b_d[315]
  PIN b_d[316]
    DIRECTION INPUT ;
    USE SIGNAL ;
    PORT
      LAYER M3 ;
        RECT  36.324 0 36.342 0.038 ;
    END
  END b_d[316]
  PIN b_d[317]
    DIRECTION INPUT ;
    USE SIGNAL ;
    PORT
      LAYER M5 ;
        RECT  36.432 0 36.456 0.084 ;
    END
  END b_d[317]
  PIN b_d[318]
    DIRECTION INPUT ;
    USE SIGNAL ;
    PORT
      LAYER M3 ;
        RECT  36.54 0 36.558 0.038 ;
    END
  END b_d[318]
  PIN b_d[319]
    DIRECTION INPUT ;
    USE SIGNAL ;
    PORT
      LAYER M5 ;
        RECT  36.624 0 36.648 0.084 ;
    END
  END b_d[319]
  PIN b_d[31]
    DIRECTION INPUT ;
    USE SIGNAL ;
    PORT
      LAYER M5 ;
        RECT  8.784 0 8.808 0.084 ;
    END
  END b_d[31]
  PIN b_d[320]
    DIRECTION INPUT ;
    USE SIGNAL ;
    PORT
      LAYER M3 ;
        RECT  36.72 0 36.738 0.038 ;
    END
  END b_d[320]
  PIN b_d[321]
    DIRECTION INPUT ;
    USE SIGNAL ;
    PORT
      LAYER M5 ;
        RECT  36.816 0 36.84 0.084 ;
    END
  END b_d[321]
  PIN b_d[322]
    DIRECTION INPUT ;
    USE SIGNAL ;
    PORT
      LAYER M3 ;
        RECT  36.9 0 36.918 0.038 ;
    END
  END b_d[322]
  PIN b_d[323]
    DIRECTION INPUT ;
    USE SIGNAL ;
    PORT
      LAYER M5 ;
        RECT  37.008 0 37.032 0.084 ;
    END
  END b_d[323]
  PIN b_d[324]
    DIRECTION INPUT ;
    USE SIGNAL ;
    PORT
      LAYER M3 ;
        RECT  37.116 0 37.134 0.038 ;
    END
  END b_d[324]
  PIN b_d[325]
    DIRECTION INPUT ;
    USE SIGNAL ;
    PORT
      LAYER M5 ;
        RECT  37.2 0 37.224 0.084 ;
    END
  END b_d[325]
  PIN b_d[326]
    DIRECTION INPUT ;
    USE SIGNAL ;
    PORT
      LAYER M3 ;
        RECT  37.296 0 37.314 0.038 ;
    END
  END b_d[326]
  PIN b_d[327]
    DIRECTION INPUT ;
    USE SIGNAL ;
    PORT
      LAYER M5 ;
        RECT  37.392 0 37.416 0.084 ;
    END
  END b_d[327]
  PIN b_d[328]
    DIRECTION INPUT ;
    USE SIGNAL ;
    PORT
      LAYER M3 ;
        RECT  37.476 0 37.494 0.038 ;
    END
  END b_d[328]
  PIN b_d[329]
    DIRECTION INPUT ;
    USE SIGNAL ;
    PORT
      LAYER M5 ;
        RECT  37.584 0 37.608 0.084 ;
    END
  END b_d[329]
  PIN b_d[32]
    DIRECTION INPUT ;
    USE SIGNAL ;
    PORT
      LAYER M3 ;
        RECT  8.892 0 8.91 0.038 ;
    END
  END b_d[32]
  PIN b_d[330]
    DIRECTION INPUT ;
    USE SIGNAL ;
    PORT
      LAYER M3 ;
        RECT  37.692 0 37.71 0.038 ;
    END
  END b_d[330]
  PIN b_d[331]
    DIRECTION INPUT ;
    USE SIGNAL ;
    PORT
      LAYER M5 ;
        RECT  37.776 0 37.8 0.084 ;
    END
  END b_d[331]
  PIN b_d[332]
    DIRECTION INPUT ;
    USE SIGNAL ;
    PORT
      LAYER M3 ;
        RECT  37.872 0 37.89 0.038 ;
    END
  END b_d[332]
  PIN b_d[333]
    DIRECTION INPUT ;
    USE SIGNAL ;
    PORT
      LAYER M5 ;
        RECT  37.968 0 37.992 0.084 ;
    END
  END b_d[333]
  PIN b_d[334]
    DIRECTION INPUT ;
    USE SIGNAL ;
    PORT
      LAYER M3 ;
        RECT  38.088 0 38.106 0.038 ;
    END
  END b_d[334]
  PIN b_d[335]
    DIRECTION INPUT ;
    USE SIGNAL ;
    PORT
      LAYER M5 ;
        RECT  38.16 0 38.184 0.084 ;
    END
  END b_d[335]
  PIN b_d[336]
    DIRECTION INPUT ;
    USE SIGNAL ;
    PORT
      LAYER M3 ;
        RECT  38.268 0 38.286 0.038 ;
    END
  END b_d[336]
  PIN b_d[337]
    DIRECTION INPUT ;
    USE SIGNAL ;
    PORT
      LAYER M5 ;
        RECT  38.352 0 38.376 0.084 ;
    END
  END b_d[337]
  PIN b_d[338]
    DIRECTION INPUT ;
    USE SIGNAL ;
    PORT
      LAYER M3 ;
        RECT  38.448 0 38.466 0.038 ;
    END
  END b_d[338]
  PIN b_d[339]
    DIRECTION INPUT ;
    USE SIGNAL ;
    PORT
      LAYER M5 ;
        RECT  38.544 0 38.568 0.084 ;
    END
  END b_d[339]
  PIN b_d[33]
    DIRECTION INPUT ;
    USE SIGNAL ;
    PORT
      LAYER M5 ;
        RECT  8.976 0 9 0.084 ;
    END
  END b_d[33]
  PIN b_d[340]
    DIRECTION INPUT ;
    USE SIGNAL ;
    PORT
      LAYER M3 ;
        RECT  38.664 0 38.682 0.038 ;
    END
  END b_d[340]
  PIN b_d[341]
    DIRECTION INPUT ;
    USE SIGNAL ;
    PORT
      LAYER M5 ;
        RECT  38.736 0 38.76 0.084 ;
    END
  END b_d[341]
  PIN b_d[342]
    DIRECTION INPUT ;
    USE SIGNAL ;
    PORT
      LAYER M3 ;
        RECT  38.844 0 38.862 0.038 ;
    END
  END b_d[342]
  PIN b_d[343]
    DIRECTION INPUT ;
    USE SIGNAL ;
    PORT
      LAYER M5 ;
        RECT  38.928 0 38.952 0.084 ;
    END
  END b_d[343]
  PIN b_d[344]
    DIRECTION INPUT ;
    USE SIGNAL ;
    PORT
      LAYER M3 ;
        RECT  39.024 0 39.042 0.038 ;
    END
  END b_d[344]
  PIN b_d[345]
    DIRECTION INPUT ;
    USE SIGNAL ;
    PORT
      LAYER M5 ;
        RECT  39.12 0 39.144 0.084 ;
    END
  END b_d[345]
  PIN b_d[346]
    DIRECTION INPUT ;
    USE SIGNAL ;
    PORT
      LAYER M3 ;
        RECT  39.24 0 39.258 0.038 ;
    END
  END b_d[346]
  PIN b_d[347]
    DIRECTION INPUT ;
    USE SIGNAL ;
    PORT
      LAYER M5 ;
        RECT  39.312 0 39.336 0.084 ;
    END
  END b_d[347]
  PIN b_d[348]
    DIRECTION INPUT ;
    USE SIGNAL ;
    PORT
      LAYER M3 ;
        RECT  39.42 0 39.438 0.038 ;
    END
  END b_d[348]
  PIN b_d[349]
    DIRECTION INPUT ;
    USE SIGNAL ;
    PORT
      LAYER M5 ;
        RECT  39.504 0 39.528 0.084 ;
    END
  END b_d[349]
  PIN b_d[34]
    DIRECTION INPUT ;
    USE SIGNAL ;
    PORT
      LAYER M3 ;
        RECT  9.072 0 9.09 0.038 ;
    END
  END b_d[34]
  PIN b_d[350]
    DIRECTION INPUT ;
    USE SIGNAL ;
    PORT
      LAYER M3 ;
        RECT  39.636 0 39.654 0.038 ;
    END
  END b_d[350]
  PIN b_d[351]
    DIRECTION INPUT ;
    USE SIGNAL ;
    PORT
      LAYER M5 ;
        RECT  39.696 0 39.72 0.084 ;
    END
  END b_d[351]
  PIN b_d[352]
    DIRECTION INPUT ;
    USE SIGNAL ;
    PORT
      LAYER M3 ;
        RECT  39.816 0 39.834 0.038 ;
    END
  END b_d[352]
  PIN b_d[353]
    DIRECTION INPUT ;
    USE SIGNAL ;
    PORT
      LAYER M5 ;
        RECT  39.888 0 39.912 0.084 ;
    END
  END b_d[353]
  PIN b_d[354]
    DIRECTION INPUT ;
    USE SIGNAL ;
    PORT
      LAYER M3 ;
        RECT  39.996 0 40.014 0.038 ;
    END
  END b_d[354]
  PIN b_d[355]
    DIRECTION INPUT ;
    USE SIGNAL ;
    PORT
      LAYER M5 ;
        RECT  40.08 0 40.104 0.084 ;
    END
  END b_d[355]
  PIN b_d[356]
    DIRECTION INPUT ;
    USE SIGNAL ;
    PORT
      LAYER M3 ;
        RECT  40.212 0 40.23 0.038 ;
    END
  END b_d[356]
  PIN b_d[357]
    DIRECTION INPUT ;
    USE SIGNAL ;
    PORT
      LAYER M5 ;
        RECT  40.272 0 40.296 0.084 ;
    END
  END b_d[357]
  PIN b_d[358]
    DIRECTION INPUT ;
    USE SIGNAL ;
    PORT
      LAYER M3 ;
        RECT  40.392 0 40.41 0.038 ;
    END
  END b_d[358]
  PIN b_d[359]
    DIRECTION INPUT ;
    USE SIGNAL ;
    PORT
      LAYER M5 ;
        RECT  40.464 0 40.488 0.084 ;
    END
  END b_d[359]
  PIN b_d[35]
    DIRECTION INPUT ;
    USE SIGNAL ;
    PORT
      LAYER M5 ;
        RECT  9.168 0 9.192 0.084 ;
    END
  END b_d[35]
  PIN b_d[360]
    DIRECTION INPUT ;
    USE SIGNAL ;
    PORT
      LAYER M3 ;
        RECT  40.572 0 40.59 0.038 ;
    END
  END b_d[360]
  PIN b_d[361]
    DIRECTION INPUT ;
    USE SIGNAL ;
    PORT
      LAYER M5 ;
        RECT  40.656 0 40.68 0.084 ;
    END
  END b_d[361]
  PIN b_d[362]
    DIRECTION INPUT ;
    USE SIGNAL ;
    PORT
      LAYER M3 ;
        RECT  40.788 0 40.806 0.038 ;
    END
  END b_d[362]
  PIN b_d[363]
    DIRECTION INPUT ;
    USE SIGNAL ;
    PORT
      LAYER M5 ;
        RECT  40.896 0 40.92 0.084 ;
    END
  END b_d[363]
  PIN b_d[364]
    DIRECTION INPUT ;
    USE SIGNAL ;
    PORT
      LAYER M3 ;
        RECT  40.968 0 40.986 0.038 ;
    END
  END b_d[364]
  PIN b_d[365]
    DIRECTION INPUT ;
    USE SIGNAL ;
    PORT
      LAYER M5 ;
        RECT  41.088 0 41.112 0.084 ;
    END
  END b_d[365]
  PIN b_d[366]
    DIRECTION INPUT ;
    USE SIGNAL ;
    PORT
      LAYER M3 ;
        RECT  41.148 0 41.166 0.038 ;
    END
  END b_d[366]
  PIN b_d[367]
    DIRECTION INPUT ;
    USE SIGNAL ;
    PORT
      LAYER M5 ;
        RECT  41.28 0 41.304 0.084 ;
    END
  END b_d[367]
  PIN b_d[368]
    DIRECTION INPUT ;
    USE SIGNAL ;
    PORT
      LAYER M3 ;
        RECT  41.364 0 41.382 0.038 ;
    END
  END b_d[368]
  PIN b_d[369]
    DIRECTION INPUT ;
    USE SIGNAL ;
    PORT
      LAYER M5 ;
        RECT  41.472 0 41.496 0.084 ;
    END
  END b_d[369]
  PIN b_d[36]
    DIRECTION INPUT ;
    USE SIGNAL ;
    PORT
      LAYER M3 ;
        RECT  9.288 0 9.306 0.038 ;
    END
  END b_d[36]
  PIN b_d[370]
    DIRECTION INPUT ;
    USE SIGNAL ;
    PORT
      LAYER M3 ;
        RECT  41.544 0 41.562 0.038 ;
    END
  END b_d[370]
  PIN b_d[371]
    DIRECTION INPUT ;
    USE SIGNAL ;
    PORT
      LAYER M5 ;
        RECT  41.664 0 41.688 0.084 ;
    END
  END b_d[371]
  PIN b_d[372]
    DIRECTION INPUT ;
    USE SIGNAL ;
    PORT
      LAYER M3 ;
        RECT  41.76 0 41.778 0.038 ;
    END
  END b_d[372]
  PIN b_d[373]
    DIRECTION INPUT ;
    USE SIGNAL ;
    PORT
      LAYER M5 ;
        RECT  41.856 0 41.88 0.084 ;
    END
  END b_d[373]
  PIN b_d[374]
    DIRECTION INPUT ;
    USE SIGNAL ;
    PORT
      LAYER M3 ;
        RECT  41.94 0 41.958 0.038 ;
    END
  END b_d[374]
  PIN b_d[375]
    DIRECTION INPUT ;
    USE SIGNAL ;
    PORT
      LAYER M5 ;
        RECT  42.048 0 42.072 0.084 ;
    END
  END b_d[375]
  PIN b_d[376]
    DIRECTION INPUT ;
    USE SIGNAL ;
    PORT
      LAYER M3 ;
        RECT  42.12 0 42.138 0.038 ;
    END
  END b_d[376]
  PIN b_d[377]
    DIRECTION INPUT ;
    USE SIGNAL ;
    PORT
      LAYER M5 ;
        RECT  42.24 0 42.264 0.084 ;
    END
  END b_d[377]
  PIN b_d[378]
    DIRECTION INPUT ;
    USE SIGNAL ;
    PORT
      LAYER M3 ;
        RECT  42.336 0 42.354 0.038 ;
    END
  END b_d[378]
  PIN b_d[379]
    DIRECTION INPUT ;
    USE SIGNAL ;
    PORT
      LAYER M5 ;
        RECT  42.432 0 42.456 0.084 ;
    END
  END b_d[379]
  PIN b_d[37]
    DIRECTION INPUT ;
    USE SIGNAL ;
    PORT
      LAYER M5 ;
        RECT  9.36 0 9.384 0.084 ;
    END
  END b_d[37]
  PIN b_d[380]
    DIRECTION INPUT ;
    USE SIGNAL ;
    PORT
      LAYER M3 ;
        RECT  42.516 0 42.534 0.038 ;
    END
  END b_d[380]
  PIN b_d[381]
    DIRECTION INPUT ;
    USE SIGNAL ;
    PORT
      LAYER M5 ;
        RECT  42.624 0 42.648 0.084 ;
    END
  END b_d[381]
  PIN b_d[382]
    DIRECTION INPUT ;
    USE SIGNAL ;
    PORT
      LAYER M3 ;
        RECT  42.696 0 42.714 0.038 ;
    END
  END b_d[382]
  PIN b_d[383]
    DIRECTION INPUT ;
    USE SIGNAL ;
    PORT
      LAYER M5 ;
        RECT  42.816 0 42.84 0.084 ;
    END
  END b_d[383]
  PIN b_d[384]
    DIRECTION INPUT ;
    USE SIGNAL ;
    PORT
      LAYER M3 ;
        RECT  42.912 0 42.93 0.038 ;
    END
  END b_d[384]
  PIN b_d[385]
    DIRECTION INPUT ;
    USE SIGNAL ;
    PORT
      LAYER M5 ;
        RECT  43.008 0 43.032 0.084 ;
    END
  END b_d[385]
  PIN b_d[386]
    DIRECTION INPUT ;
    USE SIGNAL ;
    PORT
      LAYER M3 ;
        RECT  43.092 0 43.11 0.038 ;
    END
  END b_d[386]
  PIN b_d[387]
    DIRECTION INPUT ;
    USE SIGNAL ;
    PORT
      LAYER M5 ;
        RECT  43.2 0 43.224 0.084 ;
    END
  END b_d[387]
  PIN b_d[388]
    DIRECTION INPUT ;
    USE SIGNAL ;
    PORT
      LAYER M3 ;
        RECT  43.308 0 43.326 0.038 ;
    END
  END b_d[388]
  PIN b_d[389]
    DIRECTION INPUT ;
    USE SIGNAL ;
    PORT
      LAYER M5 ;
        RECT  43.392 0 43.416 0.084 ;
    END
  END b_d[389]
  PIN b_d[38]
    DIRECTION INPUT ;
    USE SIGNAL ;
    PORT
      LAYER M3 ;
        RECT  9.468 0 9.486 0.038 ;
    END
  END b_d[38]
  PIN b_d[390]
    DIRECTION INPUT ;
    USE SIGNAL ;
    PORT
      LAYER M3 ;
        RECT  43.488 0 43.506 0.038 ;
    END
  END b_d[390]
  PIN b_d[391]
    DIRECTION INPUT ;
    USE SIGNAL ;
    PORT
      LAYER M5 ;
        RECT  43.584 0 43.608 0.084 ;
    END
  END b_d[391]
  PIN b_d[392]
    DIRECTION INPUT ;
    USE SIGNAL ;
    PORT
      LAYER M3 ;
        RECT  43.668 0 43.686 0.038 ;
    END
  END b_d[392]
  PIN b_d[393]
    DIRECTION INPUT ;
    USE SIGNAL ;
    PORT
      LAYER M5 ;
        RECT  43.776 0 43.8 0.084 ;
    END
  END b_d[393]
  PIN b_d[394]
    DIRECTION INPUT ;
    USE SIGNAL ;
    PORT
      LAYER M3 ;
        RECT  43.884 0 43.902 0.038 ;
    END
  END b_d[394]
  PIN b_d[395]
    DIRECTION INPUT ;
    USE SIGNAL ;
    PORT
      LAYER M5 ;
        RECT  43.968 0 43.992 0.084 ;
    END
  END b_d[395]
  PIN b_d[396]
    DIRECTION INPUT ;
    USE SIGNAL ;
    PORT
      LAYER M3 ;
        RECT  44.064 0 44.082 0.038 ;
    END
  END b_d[396]
  PIN b_d[397]
    DIRECTION INPUT ;
    USE SIGNAL ;
    PORT
      LAYER M5 ;
        RECT  44.16 0 44.184 0.084 ;
    END
  END b_d[397]
  PIN b_d[398]
    DIRECTION INPUT ;
    USE SIGNAL ;
    PORT
      LAYER M3 ;
        RECT  44.244 0 44.262 0.038 ;
    END
  END b_d[398]
  PIN b_d[399]
    DIRECTION INPUT ;
    USE SIGNAL ;
    PORT
      LAYER M5 ;
        RECT  44.352 0 44.376 0.084 ;
    END
  END b_d[399]
  PIN b_d[39]
    DIRECTION INPUT ;
    USE SIGNAL ;
    PORT
      LAYER M5 ;
        RECT  9.552 0 9.576 0.084 ;
    END
  END b_d[39]
  PIN b_d[3]
    DIRECTION INPUT ;
    USE SIGNAL ;
    PORT
      LAYER M5 ;
        RECT  6.096 0 6.12 0.084 ;
    END
  END b_d[3]
  PIN b_d[400]
    DIRECTION INPUT ;
    USE SIGNAL ;
    PORT
      LAYER M3 ;
        RECT  44.46 0 44.478 0.038 ;
    END
  END b_d[400]
  PIN b_d[401]
    DIRECTION INPUT ;
    USE SIGNAL ;
    PORT
      LAYER M5 ;
        RECT  44.544 0 44.568 0.084 ;
    END
  END b_d[401]
  PIN b_d[402]
    DIRECTION INPUT ;
    USE SIGNAL ;
    PORT
      LAYER M3 ;
        RECT  44.64 0 44.658 0.038 ;
    END
  END b_d[402]
  PIN b_d[403]
    DIRECTION INPUT ;
    USE SIGNAL ;
    PORT
      LAYER M5 ;
        RECT  44.736 0 44.76 0.084 ;
    END
  END b_d[403]
  PIN b_d[404]
    DIRECTION INPUT ;
    USE SIGNAL ;
    PORT
      LAYER M3 ;
        RECT  44.82 0 44.838 0.038 ;
    END
  END b_d[404]
  PIN b_d[405]
    DIRECTION INPUT ;
    USE SIGNAL ;
    PORT
      LAYER M5 ;
        RECT  44.928 0 44.952 0.084 ;
    END
  END b_d[405]
  PIN b_d[406]
    DIRECTION INPUT ;
    USE SIGNAL ;
    PORT
      LAYER M3 ;
        RECT  45.036 0 45.054 0.038 ;
    END
  END b_d[406]
  PIN b_d[407]
    DIRECTION INPUT ;
    USE SIGNAL ;
    PORT
      LAYER M5 ;
        RECT  45.12 0 45.144 0.084 ;
    END
  END b_d[407]
  PIN b_d[408]
    DIRECTION INPUT ;
    USE SIGNAL ;
    PORT
      LAYER M3 ;
        RECT  45.216 0 45.234 0.038 ;
    END
  END b_d[408]
  PIN b_d[409]
    DIRECTION INPUT ;
    USE SIGNAL ;
    PORT
      LAYER M5 ;
        RECT  45.312 0 45.336 0.084 ;
    END
  END b_d[409]
  PIN b_d[40]
    DIRECTION INPUT ;
    USE SIGNAL ;
    PORT
      LAYER M3 ;
        RECT  9.648 0 9.666 0.038 ;
    END
  END b_d[40]
  PIN b_d[410]
    DIRECTION INPUT ;
    USE SIGNAL ;
    PORT
      LAYER M3 ;
        RECT  45.432 0 45.45 0.038 ;
    END
  END b_d[410]
  PIN b_d[411]
    DIRECTION INPUT ;
    USE SIGNAL ;
    PORT
      LAYER M5 ;
        RECT  45.504 0 45.528 0.084 ;
    END
  END b_d[411]
  PIN b_d[412]
    DIRECTION INPUT ;
    USE SIGNAL ;
    PORT
      LAYER M3 ;
        RECT  45.612 0 45.63 0.038 ;
    END
  END b_d[412]
  PIN b_d[413]
    DIRECTION INPUT ;
    USE SIGNAL ;
    PORT
      LAYER M5 ;
        RECT  45.696 0 45.72 0.084 ;
    END
  END b_d[413]
  PIN b_d[414]
    DIRECTION INPUT ;
    USE SIGNAL ;
    PORT
      LAYER M3 ;
        RECT  45.792 0 45.81 0.038 ;
    END
  END b_d[414]
  PIN b_d[415]
    DIRECTION INPUT ;
    USE SIGNAL ;
    PORT
      LAYER M5 ;
        RECT  45.888 0 45.912 0.084 ;
    END
  END b_d[415]
  PIN b_d[416]
    DIRECTION INPUT ;
    USE SIGNAL ;
    PORT
      LAYER M3 ;
        RECT  46.008 0 46.026 0.038 ;
    END
  END b_d[416]
  PIN b_d[417]
    DIRECTION INPUT ;
    USE SIGNAL ;
    PORT
      LAYER M5 ;
        RECT  46.08 0 46.104 0.084 ;
    END
  END b_d[417]
  PIN b_d[418]
    DIRECTION INPUT ;
    USE SIGNAL ;
    PORT
      LAYER M3 ;
        RECT  46.188 0 46.206 0.038 ;
    END
  END b_d[418]
  PIN b_d[419]
    DIRECTION INPUT ;
    USE SIGNAL ;
    PORT
      LAYER M5 ;
        RECT  46.272 0 46.296 0.084 ;
    END
  END b_d[419]
  PIN b_d[41]
    DIRECTION INPUT ;
    USE SIGNAL ;
    PORT
      LAYER M5 ;
        RECT  9.744 0 9.768 0.084 ;
    END
  END b_d[41]
  PIN b_d[420]
    DIRECTION INPUT ;
    USE SIGNAL ;
    PORT
      LAYER M3 ;
        RECT  46.368 0 46.386 0.038 ;
    END
  END b_d[420]
  PIN b_d[421]
    DIRECTION INPUT ;
    USE SIGNAL ;
    PORT
      LAYER M5 ;
        RECT  46.464 0 46.488 0.084 ;
    END
  END b_d[421]
  PIN b_d[422]
    DIRECTION INPUT ;
    USE SIGNAL ;
    PORT
      LAYER M3 ;
        RECT  46.584 0 46.602 0.038 ;
    END
  END b_d[422]
  PIN b_d[423]
    DIRECTION INPUT ;
    USE SIGNAL ;
    PORT
      LAYER M5 ;
        RECT  46.656 0 46.68 0.084 ;
    END
  END b_d[423]
  PIN b_d[424]
    DIRECTION INPUT ;
    USE SIGNAL ;
    PORT
      LAYER M3 ;
        RECT  46.764 0 46.782 0.038 ;
    END
  END b_d[424]
  PIN b_d[425]
    DIRECTION INPUT ;
    USE SIGNAL ;
    PORT
      LAYER M5 ;
        RECT  46.848 0 46.872 0.084 ;
    END
  END b_d[425]
  PIN b_d[426]
    DIRECTION INPUT ;
    USE SIGNAL ;
    PORT
      LAYER M3 ;
        RECT  46.98 0 46.998 0.038 ;
    END
  END b_d[426]
  PIN b_d[427]
    DIRECTION INPUT ;
    USE SIGNAL ;
    PORT
      LAYER M5 ;
        RECT  47.04 0 47.064 0.084 ;
    END
  END b_d[427]
  PIN b_d[428]
    DIRECTION INPUT ;
    USE SIGNAL ;
    PORT
      LAYER M3 ;
        RECT  47.16 0 47.178 0.038 ;
    END
  END b_d[428]
  PIN b_d[429]
    DIRECTION INPUT ;
    USE SIGNAL ;
    PORT
      LAYER M5 ;
        RECT  47.232 0 47.256 0.084 ;
    END
  END b_d[429]
  PIN b_d[42]
    DIRECTION INPUT ;
    USE SIGNAL ;
    PORT
      LAYER M3 ;
        RECT  9.864 0 9.882 0.038 ;
    END
  END b_d[42]
  PIN b_d[430]
    DIRECTION INPUT ;
    USE SIGNAL ;
    PORT
      LAYER M3 ;
        RECT  47.34 0 47.358 0.038 ;
    END
  END b_d[430]
  PIN b_d[431]
    DIRECTION INPUT ;
    USE SIGNAL ;
    PORT
      LAYER M5 ;
        RECT  47.424 0 47.448 0.084 ;
    END
  END b_d[431]
  PIN b_d[432]
    DIRECTION INPUT ;
    USE SIGNAL ;
    PORT
      LAYER M3 ;
        RECT  47.556 0 47.574 0.038 ;
    END
  END b_d[432]
  PIN b_d[433]
    DIRECTION INPUT ;
    USE SIGNAL ;
    PORT
      LAYER M5 ;
        RECT  47.616 0 47.64 0.084 ;
    END
  END b_d[433]
  PIN b_d[434]
    DIRECTION INPUT ;
    USE SIGNAL ;
    PORT
      LAYER M3 ;
        RECT  47.736 0 47.754 0.038 ;
    END
  END b_d[434]
  PIN b_d[435]
    DIRECTION INPUT ;
    USE SIGNAL ;
    PORT
      LAYER M5 ;
        RECT  47.808 0 47.832 0.084 ;
    END
  END b_d[435]
  PIN b_d[436]
    DIRECTION INPUT ;
    USE SIGNAL ;
    PORT
      LAYER M3 ;
        RECT  47.916 0 47.934 0.038 ;
    END
  END b_d[436]
  PIN b_d[437]
    DIRECTION INPUT ;
    USE SIGNAL ;
    PORT
      LAYER M5 ;
        RECT  48 0 48.024 0.084 ;
    END
  END b_d[437]
  PIN b_d[438]
    DIRECTION INPUT ;
    USE SIGNAL ;
    PORT
      LAYER M3 ;
        RECT  48.132 0 48.15 0.038 ;
    END
  END b_d[438]
  PIN b_d[439]
    DIRECTION INPUT ;
    USE SIGNAL ;
    PORT
      LAYER M5 ;
        RECT  48.24 0 48.264 0.084 ;
    END
  END b_d[439]
  PIN b_d[43]
    DIRECTION INPUT ;
    USE SIGNAL ;
    PORT
      LAYER M5 ;
        RECT  9.936 0 9.96 0.084 ;
    END
  END b_d[43]
  PIN b_d[440]
    DIRECTION INPUT ;
    USE SIGNAL ;
    PORT
      LAYER M3 ;
        RECT  48.312 0 48.33 0.038 ;
    END
  END b_d[440]
  PIN b_d[441]
    DIRECTION INPUT ;
    USE SIGNAL ;
    PORT
      LAYER M5 ;
        RECT  48.432 0 48.456 0.084 ;
    END
  END b_d[441]
  PIN b_d[442]
    DIRECTION INPUT ;
    USE SIGNAL ;
    PORT
      LAYER M3 ;
        RECT  48.492 0 48.51 0.038 ;
    END
  END b_d[442]
  PIN b_d[443]
    DIRECTION INPUT ;
    USE SIGNAL ;
    PORT
      LAYER M5 ;
        RECT  48.624 0 48.648 0.084 ;
    END
  END b_d[443]
  PIN b_d[444]
    DIRECTION INPUT ;
    USE SIGNAL ;
    PORT
      LAYER M3 ;
        RECT  48.708 0 48.726 0.038 ;
    END
  END b_d[444]
  PIN b_d[445]
    DIRECTION INPUT ;
    USE SIGNAL ;
    PORT
      LAYER M5 ;
        RECT  48.816 0 48.84 0.084 ;
    END
  END b_d[445]
  PIN b_d[446]
    DIRECTION INPUT ;
    USE SIGNAL ;
    PORT
      LAYER M3 ;
        RECT  48.888 0 48.906 0.038 ;
    END
  END b_d[446]
  PIN b_d[447]
    DIRECTION INPUT ;
    USE SIGNAL ;
    PORT
      LAYER M5 ;
        RECT  49.008 0 49.032 0.084 ;
    END
  END b_d[447]
  PIN b_d[448]
    DIRECTION INPUT ;
    USE SIGNAL ;
    PORT
      LAYER M3 ;
        RECT  49.104 0 49.122 0.038 ;
    END
  END b_d[448]
  PIN b_d[449]
    DIRECTION INPUT ;
    USE SIGNAL ;
    PORT
      LAYER M5 ;
        RECT  49.2 0 49.224 0.084 ;
    END
  END b_d[449]
  PIN b_d[44]
    DIRECTION INPUT ;
    USE SIGNAL ;
    PORT
      LAYER M3 ;
        RECT  10.044 0 10.062 0.038 ;
    END
  END b_d[44]
  PIN b_d[450]
    DIRECTION INPUT ;
    USE SIGNAL ;
    PORT
      LAYER M3 ;
        RECT  49.284 0 49.302 0.038 ;
    END
  END b_d[450]
  PIN b_d[451]
    DIRECTION INPUT ;
    USE SIGNAL ;
    PORT
      LAYER M5 ;
        RECT  49.392 0 49.416 0.084 ;
    END
  END b_d[451]
  PIN b_d[452]
    DIRECTION INPUT ;
    USE SIGNAL ;
    PORT
      LAYER M3 ;
        RECT  49.464 0 49.482 0.038 ;
    END
  END b_d[452]
  PIN b_d[453]
    DIRECTION INPUT ;
    USE SIGNAL ;
    PORT
      LAYER M5 ;
        RECT  49.584 0 49.608 0.084 ;
    END
  END b_d[453]
  PIN b_d[454]
    DIRECTION INPUT ;
    USE SIGNAL ;
    PORT
      LAYER M3 ;
        RECT  49.68 0 49.698 0.038 ;
    END
  END b_d[454]
  PIN b_d[455]
    DIRECTION INPUT ;
    USE SIGNAL ;
    PORT
      LAYER M5 ;
        RECT  49.776 0 49.8 0.084 ;
    END
  END b_d[455]
  PIN b_d[456]
    DIRECTION INPUT ;
    USE SIGNAL ;
    PORT
      LAYER M3 ;
        RECT  49.86 0 49.878 0.038 ;
    END
  END b_d[456]
  PIN b_d[457]
    DIRECTION INPUT ;
    USE SIGNAL ;
    PORT
      LAYER M5 ;
        RECT  49.968 0 49.992 0.084 ;
    END
  END b_d[457]
  PIN b_d[458]
    DIRECTION INPUT ;
    USE SIGNAL ;
    PORT
      LAYER M3 ;
        RECT  50.04 0 50.058 0.038 ;
    END
  END b_d[458]
  PIN b_d[459]
    DIRECTION INPUT ;
    USE SIGNAL ;
    PORT
      LAYER M5 ;
        RECT  50.16 0 50.184 0.084 ;
    END
  END b_d[459]
  PIN b_d[45]
    DIRECTION INPUT ;
    USE SIGNAL ;
    PORT
      LAYER M5 ;
        RECT  10.128 0 10.152 0.084 ;
    END
  END b_d[45]
  PIN b_d[460]
    DIRECTION INPUT ;
    USE SIGNAL ;
    PORT
      LAYER M3 ;
        RECT  50.256 0 50.274 0.038 ;
    END
  END b_d[460]
  PIN b_d[461]
    DIRECTION INPUT ;
    USE SIGNAL ;
    PORT
      LAYER M5 ;
        RECT  50.352 0 50.376 0.084 ;
    END
  END b_d[461]
  PIN b_d[462]
    DIRECTION INPUT ;
    USE SIGNAL ;
    PORT
      LAYER M3 ;
        RECT  50.436 0 50.454 0.038 ;
    END
  END b_d[462]
  PIN b_d[463]
    DIRECTION INPUT ;
    USE SIGNAL ;
    PORT
      LAYER M5 ;
        RECT  50.544 0 50.568 0.084 ;
    END
  END b_d[463]
  PIN b_d[464]
    DIRECTION INPUT ;
    USE SIGNAL ;
    PORT
      LAYER M3 ;
        RECT  50.652 0 50.67 0.038 ;
    END
  END b_d[464]
  PIN b_d[465]
    DIRECTION INPUT ;
    USE SIGNAL ;
    PORT
      LAYER M5 ;
        RECT  50.736 0 50.76 0.084 ;
    END
  END b_d[465]
  PIN b_d[466]
    DIRECTION INPUT ;
    USE SIGNAL ;
    PORT
      LAYER M3 ;
        RECT  50.832 0 50.85 0.038 ;
    END
  END b_d[466]
  PIN b_d[467]
    DIRECTION INPUT ;
    USE SIGNAL ;
    PORT
      LAYER M5 ;
        RECT  50.928 0 50.952 0.084 ;
    END
  END b_d[467]
  PIN b_d[468]
    DIRECTION INPUT ;
    USE SIGNAL ;
    PORT
      LAYER M3 ;
        RECT  51.012 0 51.03 0.038 ;
    END
  END b_d[468]
  PIN b_d[469]
    DIRECTION INPUT ;
    USE SIGNAL ;
    PORT
      LAYER M5 ;
        RECT  51.12 0 51.144 0.084 ;
    END
  END b_d[469]
  PIN b_d[46]
    DIRECTION INPUT ;
    USE SIGNAL ;
    PORT
      LAYER M3 ;
        RECT  10.26 0 10.278 0.038 ;
    END
  END b_d[46]
  PIN b_d[470]
    DIRECTION INPUT ;
    USE SIGNAL ;
    PORT
      LAYER M3 ;
        RECT  51.228 0 51.246 0.038 ;
    END
  END b_d[470]
  PIN b_d[471]
    DIRECTION INPUT ;
    USE SIGNAL ;
    PORT
      LAYER M5 ;
        RECT  51.312 0 51.336 0.084 ;
    END
  END b_d[471]
  PIN b_d[472]
    DIRECTION INPUT ;
    USE SIGNAL ;
    PORT
      LAYER M3 ;
        RECT  51.408 0 51.426 0.038 ;
    END
  END b_d[472]
  PIN b_d[473]
    DIRECTION INPUT ;
    USE SIGNAL ;
    PORT
      LAYER M5 ;
        RECT  51.504 0 51.528 0.084 ;
    END
  END b_d[473]
  PIN b_d[474]
    DIRECTION INPUT ;
    USE SIGNAL ;
    PORT
      LAYER M3 ;
        RECT  51.588 0 51.606 0.038 ;
    END
  END b_d[474]
  PIN b_d[475]
    DIRECTION INPUT ;
    USE SIGNAL ;
    PORT
      LAYER M5 ;
        RECT  51.696 0 51.72 0.084 ;
    END
  END b_d[475]
  PIN b_d[476]
    DIRECTION INPUT ;
    USE SIGNAL ;
    PORT
      LAYER M3 ;
        RECT  51.804 0 51.822 0.038 ;
    END
  END b_d[476]
  PIN b_d[477]
    DIRECTION INPUT ;
    USE SIGNAL ;
    PORT
      LAYER M5 ;
        RECT  51.888 0 51.912 0.084 ;
    END
  END b_d[477]
  PIN b_d[478]
    DIRECTION INPUT ;
    USE SIGNAL ;
    PORT
      LAYER M3 ;
        RECT  51.984 0 52.002 0.038 ;
    END
  END b_d[478]
  PIN b_d[479]
    DIRECTION INPUT ;
    USE SIGNAL ;
    PORT
      LAYER M5 ;
        RECT  52.08 0 52.104 0.084 ;
    END
  END b_d[479]
  PIN b_d[47]
    DIRECTION INPUT ;
    USE SIGNAL ;
    PORT
      LAYER M5 ;
        RECT  10.32 0 10.344 0.084 ;
    END
  END b_d[47]
  PIN b_d[480]
    DIRECTION INPUT ;
    USE SIGNAL ;
    PORT
      LAYER M3 ;
        RECT  52.164 0 52.182 0.038 ;
    END
  END b_d[480]
  PIN b_d[481]
    DIRECTION INPUT ;
    USE SIGNAL ;
    PORT
      LAYER M5 ;
        RECT  52.272 0 52.296 0.084 ;
    END
  END b_d[481]
  PIN b_d[482]
    DIRECTION INPUT ;
    USE SIGNAL ;
    PORT
      LAYER M3 ;
        RECT  52.38 0 52.398 0.038 ;
    END
  END b_d[482]
  PIN b_d[483]
    DIRECTION INPUT ;
    USE SIGNAL ;
    PORT
      LAYER M5 ;
        RECT  52.464 0 52.488 0.084 ;
    END
  END b_d[483]
  PIN b_d[484]
    DIRECTION INPUT ;
    USE SIGNAL ;
    PORT
      LAYER M3 ;
        RECT  52.56 0 52.578 0.038 ;
    END
  END b_d[484]
  PIN b_d[485]
    DIRECTION INPUT ;
    USE SIGNAL ;
    PORT
      LAYER M5 ;
        RECT  52.656 0 52.68 0.084 ;
    END
  END b_d[485]
  PIN b_d[486]
    DIRECTION INPUT ;
    USE SIGNAL ;
    PORT
      LAYER M3 ;
        RECT  52.776 0 52.794 0.038 ;
    END
  END b_d[486]
  PIN b_d[487]
    DIRECTION INPUT ;
    USE SIGNAL ;
    PORT
      LAYER M5 ;
        RECT  52.848 0 52.872 0.084 ;
    END
  END b_d[487]
  PIN b_d[488]
    DIRECTION INPUT ;
    USE SIGNAL ;
    PORT
      LAYER M3 ;
        RECT  52.956 0 52.974 0.038 ;
    END
  END b_d[488]
  PIN b_d[489]
    DIRECTION INPUT ;
    USE SIGNAL ;
    PORT
      LAYER M5 ;
        RECT  53.04 0 53.064 0.084 ;
    END
  END b_d[489]
  PIN b_d[48]
    DIRECTION INPUT ;
    USE SIGNAL ;
    PORT
      LAYER M3 ;
        RECT  10.44 0 10.458 0.038 ;
    END
  END b_d[48]
  PIN b_d[490]
    DIRECTION INPUT ;
    USE SIGNAL ;
    PORT
      LAYER M3 ;
        RECT  53.136 0 53.154 0.038 ;
    END
  END b_d[490]
  PIN b_d[491]
    DIRECTION INPUT ;
    USE SIGNAL ;
    PORT
      LAYER M5 ;
        RECT  53.232 0 53.256 0.084 ;
    END
  END b_d[491]
  PIN b_d[492]
    DIRECTION INPUT ;
    USE SIGNAL ;
    PORT
      LAYER M3 ;
        RECT  53.352 0 53.37 0.038 ;
    END
  END b_d[492]
  PIN b_d[493]
    DIRECTION INPUT ;
    USE SIGNAL ;
    PORT
      LAYER M5 ;
        RECT  53.424 0 53.448 0.084 ;
    END
  END b_d[493]
  PIN b_d[494]
    DIRECTION INPUT ;
    USE SIGNAL ;
    PORT
      LAYER M3 ;
        RECT  53.532 0 53.55 0.038 ;
    END
  END b_d[494]
  PIN b_d[495]
    DIRECTION INPUT ;
    USE SIGNAL ;
    PORT
      LAYER M5 ;
        RECT  53.616 0 53.64 0.084 ;
    END
  END b_d[495]
  PIN b_d[496]
    DIRECTION INPUT ;
    USE SIGNAL ;
    PORT
      LAYER M3 ;
        RECT  53.712 0 53.73 0.038 ;
    END
  END b_d[496]
  PIN b_d[497]
    DIRECTION INPUT ;
    USE SIGNAL ;
    PORT
      LAYER M5 ;
        RECT  53.808 0 53.832 0.084 ;
    END
  END b_d[497]
  PIN b_d[498]
    DIRECTION INPUT ;
    USE SIGNAL ;
    PORT
      LAYER M3 ;
        RECT  53.928 0 53.946 0.038 ;
    END
  END b_d[498]
  PIN b_d[499]
    DIRECTION INPUT ;
    USE SIGNAL ;
    PORT
      LAYER M5 ;
        RECT  54 0 54.024 0.084 ;
    END
  END b_d[499]
  PIN b_d[49]
    DIRECTION INPUT ;
    USE SIGNAL ;
    PORT
      LAYER M5 ;
        RECT  10.512 0 10.536 0.084 ;
    END
  END b_d[49]
  PIN b_d[4]
    DIRECTION INPUT ;
    USE SIGNAL ;
    PORT
      LAYER M3 ;
        RECT  6.192 0 6.21 0.038 ;
    END
  END b_d[4]
  PIN b_d[500]
    DIRECTION INPUT ;
    USE SIGNAL ;
    PORT
      LAYER M3 ;
        RECT  54.108 0 54.126 0.038 ;
    END
  END b_d[500]
  PIN b_d[501]
    DIRECTION INPUT ;
    USE SIGNAL ;
    PORT
      LAYER M5 ;
        RECT  54.192 0 54.216 0.084 ;
    END
  END b_d[501]
  PIN b_d[502]
    DIRECTION INPUT ;
    USE SIGNAL ;
    PORT
      LAYER M3 ;
        RECT  54.324 0 54.342 0.038 ;
    END
  END b_d[502]
  PIN b_d[503]
    DIRECTION INPUT ;
    USE SIGNAL ;
    PORT
      LAYER M5 ;
        RECT  54.384 0 54.408 0.084 ;
    END
  END b_d[503]
  PIN b_d[504]
    DIRECTION INPUT ;
    USE SIGNAL ;
    PORT
      LAYER M3 ;
        RECT  54.504 0 54.522 0.038 ;
    END
  END b_d[504]
  PIN b_d[505]
    DIRECTION INPUT ;
    USE SIGNAL ;
    PORT
      LAYER M5 ;
        RECT  54.576 0 54.6 0.084 ;
    END
  END b_d[505]
  PIN b_d[506]
    DIRECTION INPUT ;
    USE SIGNAL ;
    PORT
      LAYER M3 ;
        RECT  54.684 0 54.702 0.038 ;
    END
  END b_d[506]
  PIN b_d[507]
    DIRECTION INPUT ;
    USE SIGNAL ;
    PORT
      LAYER M5 ;
        RECT  54.768 0 54.792 0.084 ;
    END
  END b_d[507]
  PIN b_d[508]
    DIRECTION INPUT ;
    USE SIGNAL ;
    PORT
      LAYER M3 ;
        RECT  54.9 0 54.918 0.038 ;
    END
  END b_d[508]
  PIN b_d[509]
    DIRECTION INPUT ;
    USE SIGNAL ;
    PORT
      LAYER M5 ;
        RECT  54.96 0 54.984 0.084 ;
    END
  END b_d[509]
  PIN b_d[50]
    DIRECTION INPUT ;
    USE SIGNAL ;
    PORT
      LAYER M3 ;
        RECT  10.62 0 10.638 0.038 ;
    END
  END b_d[50]
  PIN b_d[510]
    DIRECTION INPUT ;
    USE SIGNAL ;
    PORT
      LAYER M3 ;
        RECT  55.08 0 55.098 0.038 ;
    END
  END b_d[510]
  PIN b_d[511]
    DIRECTION INPUT ;
    USE SIGNAL ;
    PORT
      LAYER M5 ;
        RECT  55.152 0 55.176 0.084 ;
    END
  END b_d[511]
  PIN b_d[512]
    DIRECTION INPUT ;
    USE SIGNAL ;
    PORT
      LAYER M3 ;
        RECT  55.26 0 55.278 0.038 ;
    END
  END b_d[512]
  PIN b_d[513]
    DIRECTION INPUT ;
    USE SIGNAL ;
    PORT
      LAYER M5 ;
        RECT  55.344 0 55.368 0.084 ;
    END
  END b_d[513]
  PIN b_d[514]
    DIRECTION INPUT ;
    USE SIGNAL ;
    PORT
      LAYER M3 ;
        RECT  55.476 0 55.494 0.038 ;
    END
  END b_d[514]
  PIN b_d[515]
    DIRECTION INPUT ;
    USE SIGNAL ;
    PORT
      LAYER M5 ;
        RECT  55.584 0 55.608 0.084 ;
    END
  END b_d[515]
  PIN b_d[51]
    DIRECTION INPUT ;
    USE SIGNAL ;
    PORT
      LAYER M5 ;
        RECT  10.704 0 10.728 0.084 ;
    END
  END b_d[51]
  PIN b_d[52]
    DIRECTION INPUT ;
    USE SIGNAL ;
    PORT
      LAYER M3 ;
        RECT  10.836 0 10.854 0.038 ;
    END
  END b_d[52]
  PIN b_d[53]
    DIRECTION INPUT ;
    USE SIGNAL ;
    PORT
      LAYER M5 ;
        RECT  10.896 0 10.92 0.084 ;
    END
  END b_d[53]
  PIN b_d[54]
    DIRECTION INPUT ;
    USE SIGNAL ;
    PORT
      LAYER M3 ;
        RECT  11.016 0 11.034 0.038 ;
    END
  END b_d[54]
  PIN b_d[55]
    DIRECTION INPUT ;
    USE SIGNAL ;
    PORT
      LAYER M5 ;
        RECT  11.088 0 11.112 0.084 ;
    END
  END b_d[55]
  PIN b_d[56]
    DIRECTION INPUT ;
    USE SIGNAL ;
    PORT
      LAYER M3 ;
        RECT  11.196 0 11.214 0.038 ;
    END
  END b_d[56]
  PIN b_d[57]
    DIRECTION INPUT ;
    USE SIGNAL ;
    PORT
      LAYER M5 ;
        RECT  11.328 0 11.352 0.084 ;
    END
  END b_d[57]
  PIN b_d[58]
    DIRECTION INPUT ;
    USE SIGNAL ;
    PORT
      LAYER M3 ;
        RECT  11.412 0 11.43 0.038 ;
    END
  END b_d[58]
  PIN b_d[59]
    DIRECTION INPUT ;
    USE SIGNAL ;
    PORT
      LAYER M5 ;
        RECT  11.52 0 11.544 0.084 ;
    END
  END b_d[59]
  PIN b_d[5]
    DIRECTION INPUT ;
    USE SIGNAL ;
    PORT
      LAYER M5 ;
        RECT  6.288 0 6.312 0.084 ;
    END
  END b_d[5]
  PIN b_d[60]
    DIRECTION INPUT ;
    USE SIGNAL ;
    PORT
      LAYER M3 ;
        RECT  11.592 0 11.61 0.038 ;
    END
  END b_d[60]
  PIN b_d[61]
    DIRECTION INPUT ;
    USE SIGNAL ;
    PORT
      LAYER M5 ;
        RECT  11.712 0 11.736 0.084 ;
    END
  END b_d[61]
  PIN b_d[62]
    DIRECTION INPUT ;
    USE SIGNAL ;
    PORT
      LAYER M3 ;
        RECT  11.808 0 11.826 0.038 ;
    END
  END b_d[62]
  PIN b_d[63]
    DIRECTION INPUT ;
    USE SIGNAL ;
    PORT
      LAYER M5 ;
        RECT  11.904 0 11.928 0.084 ;
    END
  END b_d[63]
  PIN b_d[64]
    DIRECTION INPUT ;
    USE SIGNAL ;
    PORT
      LAYER M3 ;
        RECT  11.988 0 12.006 0.038 ;
    END
  END b_d[64]
  PIN b_d[65]
    DIRECTION INPUT ;
    USE SIGNAL ;
    PORT
      LAYER M5 ;
        RECT  12.096 0 12.12 0.084 ;
    END
  END b_d[65]
  PIN b_d[66]
    DIRECTION INPUT ;
    USE SIGNAL ;
    PORT
      LAYER M3 ;
        RECT  12.168 0 12.186 0.038 ;
    END
  END b_d[66]
  PIN b_d[67]
    DIRECTION INPUT ;
    USE SIGNAL ;
    PORT
      LAYER M5 ;
        RECT  12.288 0 12.312 0.084 ;
    END
  END b_d[67]
  PIN b_d[68]
    DIRECTION INPUT ;
    USE SIGNAL ;
    PORT
      LAYER M3 ;
        RECT  12.384 0 12.402 0.038 ;
    END
  END b_d[68]
  PIN b_d[69]
    DIRECTION INPUT ;
    USE SIGNAL ;
    PORT
      LAYER M5 ;
        RECT  12.48 0 12.504 0.084 ;
    END
  END b_d[69]
  PIN b_d[6]
    DIRECTION INPUT ;
    USE SIGNAL ;
    PORT
      LAYER M3 ;
        RECT  6.372 0 6.39 0.038 ;
    END
  END b_d[6]
  PIN b_d[70]
    DIRECTION INPUT ;
    USE SIGNAL ;
    PORT
      LAYER M3 ;
        RECT  12.564 0 12.582 0.038 ;
    END
  END b_d[70]
  PIN b_d[71]
    DIRECTION INPUT ;
    USE SIGNAL ;
    PORT
      LAYER M5 ;
        RECT  12.672 0 12.696 0.084 ;
    END
  END b_d[71]
  PIN b_d[72]
    DIRECTION INPUT ;
    USE SIGNAL ;
    PORT
      LAYER M3 ;
        RECT  12.744 0 12.762 0.038 ;
    END
  END b_d[72]
  PIN b_d[73]
    DIRECTION INPUT ;
    USE SIGNAL ;
    PORT
      LAYER M5 ;
        RECT  12.864 0 12.888 0.084 ;
    END
  END b_d[73]
  PIN b_d[74]
    DIRECTION INPUT ;
    USE SIGNAL ;
    PORT
      LAYER M3 ;
        RECT  12.96 0 12.978 0.038 ;
    END
  END b_d[74]
  PIN b_d[75]
    DIRECTION INPUT ;
    USE SIGNAL ;
    PORT
      LAYER M5 ;
        RECT  13.056 0 13.08 0.084 ;
    END
  END b_d[75]
  PIN b_d[76]
    DIRECTION INPUT ;
    USE SIGNAL ;
    PORT
      LAYER M3 ;
        RECT  13.14 0 13.158 0.038 ;
    END
  END b_d[76]
  PIN b_d[77]
    DIRECTION INPUT ;
    USE SIGNAL ;
    PORT
      LAYER M5 ;
        RECT  13.248 0 13.272 0.084 ;
    END
  END b_d[77]
  PIN b_d[78]
    DIRECTION INPUT ;
    USE SIGNAL ;
    PORT
      LAYER M3 ;
        RECT  13.32 0 13.338 0.038 ;
    END
  END b_d[78]
  PIN b_d[79]
    DIRECTION INPUT ;
    USE SIGNAL ;
    PORT
      LAYER M5 ;
        RECT  13.44 0 13.464 0.084 ;
    END
  END b_d[79]
  PIN b_d[7]
    DIRECTION INPUT ;
    USE SIGNAL ;
    PORT
      LAYER M5 ;
        RECT  6.48 0 6.504 0.084 ;
    END
  END b_d[7]
  PIN b_d[80]
    DIRECTION INPUT ;
    USE SIGNAL ;
    PORT
      LAYER M3 ;
        RECT  13.536 0 13.554 0.038 ;
    END
  END b_d[80]
  PIN b_d[81]
    DIRECTION INPUT ;
    USE SIGNAL ;
    PORT
      LAYER M5 ;
        RECT  13.632 0 13.656 0.084 ;
    END
  END b_d[81]
  PIN b_d[82]
    DIRECTION INPUT ;
    USE SIGNAL ;
    PORT
      LAYER M3 ;
        RECT  13.716 0 13.734 0.038 ;
    END
  END b_d[82]
  PIN b_d[83]
    DIRECTION INPUT ;
    USE SIGNAL ;
    PORT
      LAYER M5 ;
        RECT  13.824 0 13.848 0.084 ;
    END
  END b_d[83]
  PIN b_d[84]
    DIRECTION INPUT ;
    USE SIGNAL ;
    PORT
      LAYER M3 ;
        RECT  13.932 0 13.95 0.038 ;
    END
  END b_d[84]
  PIN b_d[85]
    DIRECTION INPUT ;
    USE SIGNAL ;
    PORT
      LAYER M5 ;
        RECT  14.016 0 14.04 0.084 ;
    END
  END b_d[85]
  PIN b_d[86]
    DIRECTION INPUT ;
    USE SIGNAL ;
    PORT
      LAYER M3 ;
        RECT  14.112 0 14.13 0.038 ;
    END
  END b_d[86]
  PIN b_d[87]
    DIRECTION INPUT ;
    USE SIGNAL ;
    PORT
      LAYER M5 ;
        RECT  14.208 0 14.232 0.084 ;
    END
  END b_d[87]
  PIN b_d[88]
    DIRECTION INPUT ;
    USE SIGNAL ;
    PORT
      LAYER M3 ;
        RECT  14.292 0 14.31 0.038 ;
    END
  END b_d[88]
  PIN b_d[89]
    DIRECTION INPUT ;
    USE SIGNAL ;
    PORT
      LAYER M5 ;
        RECT  14.4 0 14.424 0.084 ;
    END
  END b_d[89]
  PIN b_d[8]
    DIRECTION INPUT ;
    USE SIGNAL ;
    PORT
      LAYER M3 ;
        RECT  6.588 0 6.606 0.038 ;
    END
  END b_d[8]
  PIN b_d[90]
    DIRECTION INPUT ;
    USE SIGNAL ;
    PORT
      LAYER M3 ;
        RECT  14.508 0 14.526 0.038 ;
    END
  END b_d[90]
  PIN b_d[91]
    DIRECTION INPUT ;
    USE SIGNAL ;
    PORT
      LAYER M5 ;
        RECT  14.592 0 14.616 0.084 ;
    END
  END b_d[91]
  PIN b_d[92]
    DIRECTION INPUT ;
    USE SIGNAL ;
    PORT
      LAYER M3 ;
        RECT  14.688 0 14.706 0.038 ;
    END
  END b_d[92]
  PIN b_d[93]
    DIRECTION INPUT ;
    USE SIGNAL ;
    PORT
      LAYER M5 ;
        RECT  14.784 0 14.808 0.084 ;
    END
  END b_d[93]
  PIN b_d[94]
    DIRECTION INPUT ;
    USE SIGNAL ;
    PORT
      LAYER M3 ;
        RECT  14.868 0 14.886 0.038 ;
    END
  END b_d[94]
  PIN b_d[95]
    DIRECTION INPUT ;
    USE SIGNAL ;
    PORT
      LAYER M5 ;
        RECT  14.976 0 15 0.084 ;
    END
  END b_d[95]
  PIN b_d[96]
    DIRECTION INPUT ;
    USE SIGNAL ;
    PORT
      LAYER M3 ;
        RECT  15.084 0 15.102 0.038 ;
    END
  END b_d[96]
  PIN b_d[97]
    DIRECTION INPUT ;
    USE SIGNAL ;
    PORT
      LAYER M5 ;
        RECT  15.168 0 15.192 0.084 ;
    END
  END b_d[97]
  PIN b_d[98]
    DIRECTION INPUT ;
    USE SIGNAL ;
    PORT
      LAYER M3 ;
        RECT  15.264 0 15.282 0.038 ;
    END
  END b_d[98]
  PIN b_d[99]
    DIRECTION INPUT ;
    USE SIGNAL ;
    PORT
      LAYER M5 ;
        RECT  15.36 0 15.384 0.084 ;
    END
  END b_d[99]
  PIN b_d[9]
    DIRECTION INPUT ;
    USE SIGNAL ;
    PORT
      LAYER M5 ;
        RECT  6.672 0 6.696 0.084 ;
    END
  END b_d[9]
  PIN ck
    DIRECTION INPUT ;
    USE SIGNAL ;
    PORT
      LAYER M3 ;
        RECT  2.556 0 2.574 0.038 ;
    END
  END ck
  PIN rst_n
    DIRECTION INPUT ;
    USE SIGNAL ;
    PORT
      LAYER M3 ;
        RECT  1.872 0 1.89 0.038 ;
    END
  END rst_n
  PIN sidx[0]
    DIRECTION INPUT ;
    USE SIGNAL ;
    PORT
      LAYER M3 ;
        RECT  0.684 0 0.702 0.038 ;
    END
  END sidx[0]
  PIN sidx[1]
    DIRECTION INPUT ;
    USE SIGNAL ;
    PORT
      LAYER M5 ;
        RECT  0.96 0 0.984 0.084 ;
    END
  END sidx[1]
  PIN sidx[2]
    DIRECTION INPUT ;
    USE SIGNAL ;
    PORT
      LAYER M3 ;
        RECT  1.224 0 1.242 0.038 ;
    END
  END sidx[2]
  PIN tap_d[0]
    DIRECTION OUTPUT ;
    USE SIGNAL ;
    PORT
      LAYER M4 ;
        RECT  0 22.512 0.084 22.536 ;
    END
  END tap_d[0]
  PIN tap_d[100]
    DIRECTION OUTPUT ;
    USE SIGNAL ;
    PORT
      LAYER M4 ;
        RECT  0 32.064 0.084 32.088 ;
    END
  END tap_d[100]
  PIN tap_d[101]
    DIRECTION OUTPUT ;
    USE SIGNAL ;
    PORT
      LAYER M4 ;
        RECT  0 32.16 0.084 32.184 ;
    END
  END tap_d[101]
  PIN tap_d[102]
    DIRECTION OUTPUT ;
    USE SIGNAL ;
    PORT
      LAYER M4 ;
        RECT  0 32.256 0.084 32.28 ;
    END
  END tap_d[102]
  PIN tap_d[103]
    DIRECTION OUTPUT ;
    USE SIGNAL ;
    PORT
      LAYER M4 ;
        RECT  0 32.352 0.084 32.376 ;
    END
  END tap_d[103]
  PIN tap_d[104]
    DIRECTION OUTPUT ;
    USE SIGNAL ;
    PORT
      LAYER M4 ;
        RECT  0 32.448 0.084 32.472 ;
    END
  END tap_d[104]
  PIN tap_d[105]
    DIRECTION OUTPUT ;
    USE SIGNAL ;
    PORT
      LAYER M4 ;
        RECT  0 32.544 0.084 32.568 ;
    END
  END tap_d[105]
  PIN tap_d[106]
    DIRECTION OUTPUT ;
    USE SIGNAL ;
    PORT
      LAYER M4 ;
        RECT  0 32.64 0.084 32.664 ;
    END
  END tap_d[106]
  PIN tap_d[107]
    DIRECTION OUTPUT ;
    USE SIGNAL ;
    PORT
      LAYER M4 ;
        RECT  0 32.736 0.084 32.76 ;
    END
  END tap_d[107]
  PIN tap_d[108]
    DIRECTION OUTPUT ;
    USE SIGNAL ;
    PORT
      LAYER M4 ;
        RECT  0 32.832 0.084 32.856 ;
    END
  END tap_d[108]
  PIN tap_d[109]
    DIRECTION OUTPUT ;
    USE SIGNAL ;
    PORT
      LAYER M4 ;
        RECT  0 32.928 0.084 32.952 ;
    END
  END tap_d[109]
  PIN tap_d[10]
    DIRECTION OUTPUT ;
    USE SIGNAL ;
    PORT
      LAYER M4 ;
        RECT  0 23.472 0.084 23.496 ;
    END
  END tap_d[10]
  PIN tap_d[110]
    DIRECTION OUTPUT ;
    USE SIGNAL ;
    PORT
      LAYER M4 ;
        RECT  0 33.024 0.084 33.048 ;
    END
  END tap_d[110]
  PIN tap_d[111]
    DIRECTION OUTPUT ;
    USE SIGNAL ;
    PORT
      LAYER M4 ;
        RECT  0 33.12 0.084 33.144 ;
    END
  END tap_d[111]
  PIN tap_d[112]
    DIRECTION OUTPUT ;
    USE SIGNAL ;
    PORT
      LAYER M4 ;
        RECT  0 33.216 0.084 33.24 ;
    END
  END tap_d[112]
  PIN tap_d[113]
    DIRECTION OUTPUT ;
    USE SIGNAL ;
    PORT
      LAYER M4 ;
        RECT  0 33.312 0.084 33.336 ;
    END
  END tap_d[113]
  PIN tap_d[114]
    DIRECTION OUTPUT ;
    USE SIGNAL ;
    PORT
      LAYER M4 ;
        RECT  0 33.408 0.084 33.432 ;
    END
  END tap_d[114]
  PIN tap_d[115]
    DIRECTION OUTPUT ;
    USE SIGNAL ;
    PORT
      LAYER M4 ;
        RECT  0 33.504 0.084 33.528 ;
    END
  END tap_d[115]
  PIN tap_d[116]
    DIRECTION OUTPUT ;
    USE SIGNAL ;
    PORT
      LAYER M4 ;
        RECT  0 33.6 0.084 33.624 ;
    END
  END tap_d[116]
  PIN tap_d[117]
    DIRECTION OUTPUT ;
    USE SIGNAL ;
    PORT
      LAYER M4 ;
        RECT  0 33.696 0.084 33.72 ;
    END
  END tap_d[117]
  PIN tap_d[118]
    DIRECTION OUTPUT ;
    USE SIGNAL ;
    PORT
      LAYER M4 ;
        RECT  0 33.792 0.084 33.816 ;
    END
  END tap_d[118]
  PIN tap_d[119]
    DIRECTION OUTPUT ;
    USE SIGNAL ;
    PORT
      LAYER M4 ;
        RECT  0 33.888 0.084 33.912 ;
    END
  END tap_d[119]
  PIN tap_d[11]
    DIRECTION OUTPUT ;
    USE SIGNAL ;
    PORT
      LAYER M4 ;
        RECT  0 23.568 0.084 23.592 ;
    END
  END tap_d[11]
  PIN tap_d[120]
    DIRECTION OUTPUT ;
    USE SIGNAL ;
    PORT
      LAYER M4 ;
        RECT  0 33.984 0.084 34.008 ;
    END
  END tap_d[120]
  PIN tap_d[121]
    DIRECTION OUTPUT ;
    USE SIGNAL ;
    PORT
      LAYER M4 ;
        RECT  0 34.08 0.084 34.104 ;
    END
  END tap_d[121]
  PIN tap_d[122]
    DIRECTION OUTPUT ;
    USE SIGNAL ;
    PORT
      LAYER M4 ;
        RECT  0 34.176 0.084 34.2 ;
    END
  END tap_d[122]
  PIN tap_d[123]
    DIRECTION OUTPUT ;
    USE SIGNAL ;
    PORT
      LAYER M4 ;
        RECT  0 34.272 0.084 34.296 ;
    END
  END tap_d[123]
  PIN tap_d[124]
    DIRECTION OUTPUT ;
    USE SIGNAL ;
    PORT
      LAYER M4 ;
        RECT  0 34.368 0.084 34.392 ;
    END
  END tap_d[124]
  PIN tap_d[125]
    DIRECTION OUTPUT ;
    USE SIGNAL ;
    PORT
      LAYER M4 ;
        RECT  0 34.464 0.084 34.488 ;
    END
  END tap_d[125]
  PIN tap_d[126]
    DIRECTION OUTPUT ;
    USE SIGNAL ;
    PORT
      LAYER M4 ;
        RECT  0 34.56 0.084 34.584 ;
    END
  END tap_d[126]
  PIN tap_d[127]
    DIRECTION OUTPUT ;
    USE SIGNAL ;
    PORT
      LAYER M4 ;
        RECT  0 34.656 0.084 34.68 ;
    END
  END tap_d[127]
  PIN tap_d[128]
    DIRECTION OUTPUT ;
    USE SIGNAL ;
    PORT
      LAYER M4 ;
        RECT  0 34.752 0.084 34.776 ;
    END
  END tap_d[128]
  PIN tap_d[129]
    DIRECTION OUTPUT ;
    USE SIGNAL ;
    PORT
      LAYER M4 ;
        RECT  0 34.848 0.084 34.872 ;
    END
  END tap_d[129]
  PIN tap_d[12]
    DIRECTION OUTPUT ;
    USE SIGNAL ;
    PORT
      LAYER M4 ;
        RECT  0 23.664 0.084 23.688 ;
    END
  END tap_d[12]
  PIN tap_d[130]
    DIRECTION OUTPUT ;
    USE SIGNAL ;
    PORT
      LAYER M4 ;
        RECT  0 34.944 0.084 34.968 ;
    END
  END tap_d[130]
  PIN tap_d[131]
    DIRECTION OUTPUT ;
    USE SIGNAL ;
    PORT
      LAYER M4 ;
        RECT  0 35.04 0.084 35.064 ;
    END
  END tap_d[131]
  PIN tap_d[132]
    DIRECTION OUTPUT ;
    USE SIGNAL ;
    PORT
      LAYER M4 ;
        RECT  0 35.136 0.084 35.16 ;
    END
  END tap_d[132]
  PIN tap_d[133]
    DIRECTION OUTPUT ;
    USE SIGNAL ;
    PORT
      LAYER M4 ;
        RECT  0 35.232 0.084 35.256 ;
    END
  END tap_d[133]
  PIN tap_d[134]
    DIRECTION OUTPUT ;
    USE SIGNAL ;
    PORT
      LAYER M4 ;
        RECT  0 35.328 0.084 35.352 ;
    END
  END tap_d[134]
  PIN tap_d[135]
    DIRECTION OUTPUT ;
    USE SIGNAL ;
    PORT
      LAYER M4 ;
        RECT  0 35.424 0.084 35.448 ;
    END
  END tap_d[135]
  PIN tap_d[136]
    DIRECTION OUTPUT ;
    USE SIGNAL ;
    PORT
      LAYER M4 ;
        RECT  0 35.52 0.084 35.544 ;
    END
  END tap_d[136]
  PIN tap_d[137]
    DIRECTION OUTPUT ;
    USE SIGNAL ;
    PORT
      LAYER M4 ;
        RECT  0 35.616 0.084 35.64 ;
    END
  END tap_d[137]
  PIN tap_d[138]
    DIRECTION OUTPUT ;
    USE SIGNAL ;
    PORT
      LAYER M4 ;
        RECT  0 35.712 0.084 35.736 ;
    END
  END tap_d[138]
  PIN tap_d[139]
    DIRECTION OUTPUT ;
    USE SIGNAL ;
    PORT
      LAYER M4 ;
        RECT  0 35.808 0.084 35.832 ;
    END
  END tap_d[139]
  PIN tap_d[13]
    DIRECTION OUTPUT ;
    USE SIGNAL ;
    PORT
      LAYER M4 ;
        RECT  0 23.76 0.084 23.784 ;
    END
  END tap_d[13]
  PIN tap_d[140]
    DIRECTION OUTPUT ;
    USE SIGNAL ;
    PORT
      LAYER M4 ;
        RECT  0 35.904 0.084 35.928 ;
    END
  END tap_d[140]
  PIN tap_d[141]
    DIRECTION OUTPUT ;
    USE SIGNAL ;
    PORT
      LAYER M4 ;
        RECT  0 36 0.084 36.024 ;
    END
  END tap_d[141]
  PIN tap_d[142]
    DIRECTION OUTPUT ;
    USE SIGNAL ;
    PORT
      LAYER M4 ;
        RECT  0 36.096 0.084 36.12 ;
    END
  END tap_d[142]
  PIN tap_d[143]
    DIRECTION OUTPUT ;
    USE SIGNAL ;
    PORT
      LAYER M4 ;
        RECT  0 36.192 0.084 36.216 ;
    END
  END tap_d[143]
  PIN tap_d[144]
    DIRECTION OUTPUT ;
    USE SIGNAL ;
    PORT
      LAYER M4 ;
        RECT  0 36.288 0.084 36.312 ;
    END
  END tap_d[144]
  PIN tap_d[145]
    DIRECTION OUTPUT ;
    USE SIGNAL ;
    PORT
      LAYER M4 ;
        RECT  0 36.384 0.084 36.408 ;
    END
  END tap_d[145]
  PIN tap_d[146]
    DIRECTION OUTPUT ;
    USE SIGNAL ;
    PORT
      LAYER M4 ;
        RECT  0 36.48 0.084 36.504 ;
    END
  END tap_d[146]
  PIN tap_d[147]
    DIRECTION OUTPUT ;
    USE SIGNAL ;
    PORT
      LAYER M4 ;
        RECT  0 36.576 0.084 36.6 ;
    END
  END tap_d[147]
  PIN tap_d[148]
    DIRECTION OUTPUT ;
    USE SIGNAL ;
    PORT
      LAYER M4 ;
        RECT  0 36.672 0.084 36.696 ;
    END
  END tap_d[148]
  PIN tap_d[149]
    DIRECTION OUTPUT ;
    USE SIGNAL ;
    PORT
      LAYER M4 ;
        RECT  0 36.768 0.084 36.792 ;
    END
  END tap_d[149]
  PIN tap_d[14]
    DIRECTION OUTPUT ;
    USE SIGNAL ;
    PORT
      LAYER M4 ;
        RECT  0 23.856 0.084 23.88 ;
    END
  END tap_d[14]
  PIN tap_d[150]
    DIRECTION OUTPUT ;
    USE SIGNAL ;
    PORT
      LAYER M4 ;
        RECT  0 36.864 0.084 36.888 ;
    END
  END tap_d[150]
  PIN tap_d[151]
    DIRECTION OUTPUT ;
    USE SIGNAL ;
    PORT
      LAYER M4 ;
        RECT  0 36.96 0.084 36.984 ;
    END
  END tap_d[151]
  PIN tap_d[152]
    DIRECTION OUTPUT ;
    USE SIGNAL ;
    PORT
      LAYER M4 ;
        RECT  0 37.056 0.084 37.08 ;
    END
  END tap_d[152]
  PIN tap_d[153]
    DIRECTION OUTPUT ;
    USE SIGNAL ;
    PORT
      LAYER M4 ;
        RECT  0 37.152 0.084 37.176 ;
    END
  END tap_d[153]
  PIN tap_d[154]
    DIRECTION OUTPUT ;
    USE SIGNAL ;
    PORT
      LAYER M4 ;
        RECT  0 37.248 0.084 37.272 ;
    END
  END tap_d[154]
  PIN tap_d[155]
    DIRECTION OUTPUT ;
    USE SIGNAL ;
    PORT
      LAYER M4 ;
        RECT  0 37.344 0.084 37.368 ;
    END
  END tap_d[155]
  PIN tap_d[156]
    DIRECTION OUTPUT ;
    USE SIGNAL ;
    PORT
      LAYER M4 ;
        RECT  0 37.44 0.084 37.464 ;
    END
  END tap_d[156]
  PIN tap_d[157]
    DIRECTION OUTPUT ;
    USE SIGNAL ;
    PORT
      LAYER M4 ;
        RECT  0 37.536 0.084 37.56 ;
    END
  END tap_d[157]
  PIN tap_d[158]
    DIRECTION OUTPUT ;
    USE SIGNAL ;
    PORT
      LAYER M4 ;
        RECT  0 37.632 0.084 37.656 ;
    END
  END tap_d[158]
  PIN tap_d[159]
    DIRECTION OUTPUT ;
    USE SIGNAL ;
    PORT
      LAYER M4 ;
        RECT  0 37.728 0.084 37.752 ;
    END
  END tap_d[159]
  PIN tap_d[15]
    DIRECTION OUTPUT ;
    USE SIGNAL ;
    PORT
      LAYER M4 ;
        RECT  0 23.952 0.084 23.976 ;
    END
  END tap_d[15]
  PIN tap_d[160]
    DIRECTION OUTPUT ;
    USE SIGNAL ;
    PORT
      LAYER M4 ;
        RECT  0 37.824 0.084 37.848 ;
    END
  END tap_d[160]
  PIN tap_d[161]
    DIRECTION OUTPUT ;
    USE SIGNAL ;
    PORT
      LAYER M4 ;
        RECT  0 37.92 0.084 37.944 ;
    END
  END tap_d[161]
  PIN tap_d[162]
    DIRECTION OUTPUT ;
    USE SIGNAL ;
    PORT
      LAYER M4 ;
        RECT  0 38.016 0.084 38.04 ;
    END
  END tap_d[162]
  PIN tap_d[163]
    DIRECTION OUTPUT ;
    USE SIGNAL ;
    PORT
      LAYER M4 ;
        RECT  0 38.112 0.084 38.136 ;
    END
  END tap_d[163]
  PIN tap_d[164]
    DIRECTION OUTPUT ;
    USE SIGNAL ;
    PORT
      LAYER M4 ;
        RECT  0 38.208 0.084 38.232 ;
    END
  END tap_d[164]
  PIN tap_d[165]
    DIRECTION OUTPUT ;
    USE SIGNAL ;
    PORT
      LAYER M4 ;
        RECT  0 38.304 0.084 38.328 ;
    END
  END tap_d[165]
  PIN tap_d[166]
    DIRECTION OUTPUT ;
    USE SIGNAL ;
    PORT
      LAYER M4 ;
        RECT  0 38.4 0.084 38.424 ;
    END
  END tap_d[166]
  PIN tap_d[167]
    DIRECTION OUTPUT ;
    USE SIGNAL ;
    PORT
      LAYER M4 ;
        RECT  0 38.496 0.084 38.52 ;
    END
  END tap_d[167]
  PIN tap_d[168]
    DIRECTION OUTPUT ;
    USE SIGNAL ;
    PORT
      LAYER M4 ;
        RECT  0 38.592 0.084 38.616 ;
    END
  END tap_d[168]
  PIN tap_d[169]
    DIRECTION OUTPUT ;
    USE SIGNAL ;
    PORT
      LAYER M4 ;
        RECT  0 38.688 0.084 38.712 ;
    END
  END tap_d[169]
  PIN tap_d[16]
    DIRECTION OUTPUT ;
    USE SIGNAL ;
    PORT
      LAYER M4 ;
        RECT  0 24.048 0.084 24.072 ;
    END
  END tap_d[16]
  PIN tap_d[170]
    DIRECTION OUTPUT ;
    USE SIGNAL ;
    PORT
      LAYER M4 ;
        RECT  0 38.784 0.084 38.808 ;
    END
  END tap_d[170]
  PIN tap_d[171]
    DIRECTION OUTPUT ;
    USE SIGNAL ;
    PORT
      LAYER M4 ;
        RECT  0 38.88 0.084 38.904 ;
    END
  END tap_d[171]
  PIN tap_d[172]
    DIRECTION OUTPUT ;
    USE SIGNAL ;
    PORT
      LAYER M4 ;
        RECT  0 38.976 0.084 39 ;
    END
  END tap_d[172]
  PIN tap_d[173]
    DIRECTION OUTPUT ;
    USE SIGNAL ;
    PORT
      LAYER M4 ;
        RECT  0 39.072 0.084 39.096 ;
    END
  END tap_d[173]
  PIN tap_d[174]
    DIRECTION OUTPUT ;
    USE SIGNAL ;
    PORT
      LAYER M4 ;
        RECT  0 39.168 0.084 39.192 ;
    END
  END tap_d[174]
  PIN tap_d[175]
    DIRECTION OUTPUT ;
    USE SIGNAL ;
    PORT
      LAYER M4 ;
        RECT  0 39.264 0.084 39.288 ;
    END
  END tap_d[175]
  PIN tap_d[176]
    DIRECTION OUTPUT ;
    USE SIGNAL ;
    PORT
      LAYER M4 ;
        RECT  0 39.36 0.084 39.384 ;
    END
  END tap_d[176]
  PIN tap_d[177]
    DIRECTION OUTPUT ;
    USE SIGNAL ;
    PORT
      LAYER M4 ;
        RECT  0 39.456 0.084 39.48 ;
    END
  END tap_d[177]
  PIN tap_d[178]
    DIRECTION OUTPUT ;
    USE SIGNAL ;
    PORT
      LAYER M4 ;
        RECT  0 39.552 0.084 39.576 ;
    END
  END tap_d[178]
  PIN tap_d[179]
    DIRECTION OUTPUT ;
    USE SIGNAL ;
    PORT
      LAYER M4 ;
        RECT  0 39.648 0.084 39.672 ;
    END
  END tap_d[179]
  PIN tap_d[17]
    DIRECTION OUTPUT ;
    USE SIGNAL ;
    PORT
      LAYER M4 ;
        RECT  0 24.144 0.084 24.168 ;
    END
  END tap_d[17]
  PIN tap_d[180]
    DIRECTION OUTPUT ;
    USE SIGNAL ;
    PORT
      LAYER M4 ;
        RECT  0 39.744 0.084 39.768 ;
    END
  END tap_d[180]
  PIN tap_d[181]
    DIRECTION OUTPUT ;
    USE SIGNAL ;
    PORT
      LAYER M4 ;
        RECT  0 39.84 0.084 39.864 ;
    END
  END tap_d[181]
  PIN tap_d[182]
    DIRECTION OUTPUT ;
    USE SIGNAL ;
    PORT
      LAYER M4 ;
        RECT  0 39.936 0.084 39.96 ;
    END
  END tap_d[182]
  PIN tap_d[183]
    DIRECTION OUTPUT ;
    USE SIGNAL ;
    PORT
      LAYER M4 ;
        RECT  0 40.032 0.084 40.056 ;
    END
  END tap_d[183]
  PIN tap_d[184]
    DIRECTION OUTPUT ;
    USE SIGNAL ;
    PORT
      LAYER M4 ;
        RECT  0 40.128 0.084 40.152 ;
    END
  END tap_d[184]
  PIN tap_d[185]
    DIRECTION OUTPUT ;
    USE SIGNAL ;
    PORT
      LAYER M4 ;
        RECT  0 40.224 0.084 40.248 ;
    END
  END tap_d[185]
  PIN tap_d[186]
    DIRECTION OUTPUT ;
    USE SIGNAL ;
    PORT
      LAYER M4 ;
        RECT  0 40.32 0.084 40.344 ;
    END
  END tap_d[186]
  PIN tap_d[187]
    DIRECTION OUTPUT ;
    USE SIGNAL ;
    PORT
      LAYER M4 ;
        RECT  0 40.416 0.084 40.44 ;
    END
  END tap_d[187]
  PIN tap_d[188]
    DIRECTION OUTPUT ;
    USE SIGNAL ;
    PORT
      LAYER M4 ;
        RECT  0 40.512 0.084 40.536 ;
    END
  END tap_d[188]
  PIN tap_d[189]
    DIRECTION OUTPUT ;
    USE SIGNAL ;
    PORT
      LAYER M4 ;
        RECT  0 40.608 0.084 40.632 ;
    END
  END tap_d[189]
  PIN tap_d[18]
    DIRECTION OUTPUT ;
    USE SIGNAL ;
    PORT
      LAYER M4 ;
        RECT  0 24.24 0.084 24.264 ;
    END
  END tap_d[18]
  PIN tap_d[190]
    DIRECTION OUTPUT ;
    USE SIGNAL ;
    PORT
      LAYER M4 ;
        RECT  0 40.704 0.084 40.728 ;
    END
  END tap_d[190]
  PIN tap_d[191]
    DIRECTION OUTPUT ;
    USE SIGNAL ;
    PORT
      LAYER M4 ;
        RECT  0 40.8 0.084 40.824 ;
    END
  END tap_d[191]
  PIN tap_d[192]
    DIRECTION OUTPUT ;
    USE SIGNAL ;
    PORT
      LAYER M4 ;
        RECT  0 40.896 0.084 40.92 ;
    END
  END tap_d[192]
  PIN tap_d[193]
    DIRECTION OUTPUT ;
    USE SIGNAL ;
    PORT
      LAYER M4 ;
        RECT  0 40.992 0.084 41.016 ;
    END
  END tap_d[193]
  PIN tap_d[194]
    DIRECTION OUTPUT ;
    USE SIGNAL ;
    PORT
      LAYER M4 ;
        RECT  0 41.088 0.084 41.112 ;
    END
  END tap_d[194]
  PIN tap_d[195]
    DIRECTION OUTPUT ;
    USE SIGNAL ;
    PORT
      LAYER M4 ;
        RECT  0 41.184 0.084 41.208 ;
    END
  END tap_d[195]
  PIN tap_d[196]
    DIRECTION OUTPUT ;
    USE SIGNAL ;
    PORT
      LAYER M4 ;
        RECT  0 41.28 0.084 41.304 ;
    END
  END tap_d[196]
  PIN tap_d[197]
    DIRECTION OUTPUT ;
    USE SIGNAL ;
    PORT
      LAYER M4 ;
        RECT  0 41.376 0.084 41.4 ;
    END
  END tap_d[197]
  PIN tap_d[198]
    DIRECTION OUTPUT ;
    USE SIGNAL ;
    PORT
      LAYER M4 ;
        RECT  0 41.472 0.084 41.496 ;
    END
  END tap_d[198]
  PIN tap_d[199]
    DIRECTION OUTPUT ;
    USE SIGNAL ;
    PORT
      LAYER M4 ;
        RECT  0 41.568 0.084 41.592 ;
    END
  END tap_d[199]
  PIN tap_d[19]
    DIRECTION OUTPUT ;
    USE SIGNAL ;
    PORT
      LAYER M4 ;
        RECT  0 24.336 0.084 24.36 ;
    END
  END tap_d[19]
  PIN tap_d[1]
    DIRECTION OUTPUT ;
    USE SIGNAL ;
    PORT
      LAYER M4 ;
        RECT  0 22.608 0.084 22.632 ;
    END
  END tap_d[1]
  PIN tap_d[200]
    DIRECTION OUTPUT ;
    USE SIGNAL ;
    PORT
      LAYER M4 ;
        RECT  0 41.664 0.084 41.688 ;
    END
  END tap_d[200]
  PIN tap_d[201]
    DIRECTION OUTPUT ;
    USE SIGNAL ;
    PORT
      LAYER M4 ;
        RECT  0 41.76 0.084 41.784 ;
    END
  END tap_d[201]
  PIN tap_d[202]
    DIRECTION OUTPUT ;
    USE SIGNAL ;
    PORT
      LAYER M4 ;
        RECT  0 41.856 0.084 41.88 ;
    END
  END tap_d[202]
  PIN tap_d[203]
    DIRECTION OUTPUT ;
    USE SIGNAL ;
    PORT
      LAYER M4 ;
        RECT  0 41.952 0.084 41.976 ;
    END
  END tap_d[203]
  PIN tap_d[204]
    DIRECTION OUTPUT ;
    USE SIGNAL ;
    PORT
      LAYER M4 ;
        RECT  0 42.048 0.084 42.072 ;
    END
  END tap_d[204]
  PIN tap_d[205]
    DIRECTION OUTPUT ;
    USE SIGNAL ;
    PORT
      LAYER M4 ;
        RECT  0 42.144 0.084 42.168 ;
    END
  END tap_d[205]
  PIN tap_d[206]
    DIRECTION OUTPUT ;
    USE SIGNAL ;
    PORT
      LAYER M4 ;
        RECT  0 42.24 0.084 42.264 ;
    END
  END tap_d[206]
  PIN tap_d[207]
    DIRECTION OUTPUT ;
    USE SIGNAL ;
    PORT
      LAYER M4 ;
        RECT  0 42.336 0.084 42.36 ;
    END
  END tap_d[207]
  PIN tap_d[208]
    DIRECTION OUTPUT ;
    USE SIGNAL ;
    PORT
      LAYER M4 ;
        RECT  0 42.432 0.084 42.456 ;
    END
  END tap_d[208]
  PIN tap_d[209]
    DIRECTION OUTPUT ;
    USE SIGNAL ;
    PORT
      LAYER M4 ;
        RECT  0 42.528 0.084 42.552 ;
    END
  END tap_d[209]
  PIN tap_d[20]
    DIRECTION OUTPUT ;
    USE SIGNAL ;
    PORT
      LAYER M4 ;
        RECT  0 24.432 0.084 24.456 ;
    END
  END tap_d[20]
  PIN tap_d[210]
    DIRECTION OUTPUT ;
    USE SIGNAL ;
    PORT
      LAYER M4 ;
        RECT  0 42.624 0.084 42.648 ;
    END
  END tap_d[210]
  PIN tap_d[211]
    DIRECTION OUTPUT ;
    USE SIGNAL ;
    PORT
      LAYER M4 ;
        RECT  0 42.72 0.084 42.744 ;
    END
  END tap_d[211]
  PIN tap_d[212]
    DIRECTION OUTPUT ;
    USE SIGNAL ;
    PORT
      LAYER M4 ;
        RECT  0 42.816 0.084 42.84 ;
    END
  END tap_d[212]
  PIN tap_d[213]
    DIRECTION OUTPUT ;
    USE SIGNAL ;
    PORT
      LAYER M4 ;
        RECT  0 42.912 0.084 42.936 ;
    END
  END tap_d[213]
  PIN tap_d[214]
    DIRECTION OUTPUT ;
    USE SIGNAL ;
    PORT
      LAYER M4 ;
        RECT  0 43.008 0.084 43.032 ;
    END
  END tap_d[214]
  PIN tap_d[215]
    DIRECTION OUTPUT ;
    USE SIGNAL ;
    PORT
      LAYER M4 ;
        RECT  0 43.104 0.084 43.128 ;
    END
  END tap_d[215]
  PIN tap_d[216]
    DIRECTION OUTPUT ;
    USE SIGNAL ;
    PORT
      LAYER M4 ;
        RECT  0 43.2 0.084 43.224 ;
    END
  END tap_d[216]
  PIN tap_d[217]
    DIRECTION OUTPUT ;
    USE SIGNAL ;
    PORT
      LAYER M4 ;
        RECT  0 43.296 0.084 43.32 ;
    END
  END tap_d[217]
  PIN tap_d[218]
    DIRECTION OUTPUT ;
    USE SIGNAL ;
    PORT
      LAYER M4 ;
        RECT  0 43.392 0.084 43.416 ;
    END
  END tap_d[218]
  PIN tap_d[219]
    DIRECTION OUTPUT ;
    USE SIGNAL ;
    PORT
      LAYER M4 ;
        RECT  0 43.488 0.084 43.512 ;
    END
  END tap_d[219]
  PIN tap_d[21]
    DIRECTION OUTPUT ;
    USE SIGNAL ;
    PORT
      LAYER M4 ;
        RECT  0 24.528 0.084 24.552 ;
    END
  END tap_d[21]
  PIN tap_d[220]
    DIRECTION OUTPUT ;
    USE SIGNAL ;
    PORT
      LAYER M4 ;
        RECT  0 43.584 0.084 43.608 ;
    END
  END tap_d[220]
  PIN tap_d[221]
    DIRECTION OUTPUT ;
    USE SIGNAL ;
    PORT
      LAYER M4 ;
        RECT  0 43.68 0.084 43.704 ;
    END
  END tap_d[221]
  PIN tap_d[222]
    DIRECTION OUTPUT ;
    USE SIGNAL ;
    PORT
      LAYER M4 ;
        RECT  0 43.776 0.084 43.8 ;
    END
  END tap_d[222]
  PIN tap_d[223]
    DIRECTION OUTPUT ;
    USE SIGNAL ;
    PORT
      LAYER M4 ;
        RECT  0 43.872 0.084 43.896 ;
    END
  END tap_d[223]
  PIN tap_d[224]
    DIRECTION OUTPUT ;
    USE SIGNAL ;
    PORT
      LAYER M4 ;
        RECT  0 43.968 0.084 43.992 ;
    END
  END tap_d[224]
  PIN tap_d[225]
    DIRECTION OUTPUT ;
    USE SIGNAL ;
    PORT
      LAYER M4 ;
        RECT  0 44.064 0.084 44.088 ;
    END
  END tap_d[225]
  PIN tap_d[226]
    DIRECTION OUTPUT ;
    USE SIGNAL ;
    PORT
      LAYER M4 ;
        RECT  0 44.16 0.084 44.184 ;
    END
  END tap_d[226]
  PIN tap_d[227]
    DIRECTION OUTPUT ;
    USE SIGNAL ;
    PORT
      LAYER M4 ;
        RECT  0 44.256 0.084 44.28 ;
    END
  END tap_d[227]
  PIN tap_d[228]
    DIRECTION OUTPUT ;
    USE SIGNAL ;
    PORT
      LAYER M4 ;
        RECT  0 44.352 0.084 44.376 ;
    END
  END tap_d[228]
  PIN tap_d[229]
    DIRECTION OUTPUT ;
    USE SIGNAL ;
    PORT
      LAYER M4 ;
        RECT  0 44.448 0.084 44.472 ;
    END
  END tap_d[229]
  PIN tap_d[22]
    DIRECTION OUTPUT ;
    USE SIGNAL ;
    PORT
      LAYER M4 ;
        RECT  0 24.624 0.084 24.648 ;
    END
  END tap_d[22]
  PIN tap_d[230]
    DIRECTION OUTPUT ;
    USE SIGNAL ;
    PORT
      LAYER M4 ;
        RECT  0 44.544 0.084 44.568 ;
    END
  END tap_d[230]
  PIN tap_d[231]
    DIRECTION OUTPUT ;
    USE SIGNAL ;
    PORT
      LAYER M4 ;
        RECT  0 44.64 0.084 44.664 ;
    END
  END tap_d[231]
  PIN tap_d[232]
    DIRECTION OUTPUT ;
    USE SIGNAL ;
    PORT
      LAYER M4 ;
        RECT  0 44.736 0.084 44.76 ;
    END
  END tap_d[232]
  PIN tap_d[233]
    DIRECTION OUTPUT ;
    USE SIGNAL ;
    PORT
      LAYER M4 ;
        RECT  0 44.832 0.084 44.856 ;
    END
  END tap_d[233]
  PIN tap_d[234]
    DIRECTION OUTPUT ;
    USE SIGNAL ;
    PORT
      LAYER M4 ;
        RECT  0 44.928 0.084 44.952 ;
    END
  END tap_d[234]
  PIN tap_d[235]
    DIRECTION OUTPUT ;
    USE SIGNAL ;
    PORT
      LAYER M4 ;
        RECT  0 45.024 0.084 45.048 ;
    END
  END tap_d[235]
  PIN tap_d[236]
    DIRECTION OUTPUT ;
    USE SIGNAL ;
    PORT
      LAYER M4 ;
        RECT  0 45.12 0.084 45.144 ;
    END
  END tap_d[236]
  PIN tap_d[237]
    DIRECTION OUTPUT ;
    USE SIGNAL ;
    PORT
      LAYER M4 ;
        RECT  0 45.216 0.084 45.24 ;
    END
  END tap_d[237]
  PIN tap_d[238]
    DIRECTION OUTPUT ;
    USE SIGNAL ;
    PORT
      LAYER M4 ;
        RECT  0 45.312 0.084 45.336 ;
    END
  END tap_d[238]
  PIN tap_d[239]
    DIRECTION OUTPUT ;
    USE SIGNAL ;
    PORT
      LAYER M4 ;
        RECT  0 45.408 0.084 45.432 ;
    END
  END tap_d[239]
  PIN tap_d[23]
    DIRECTION OUTPUT ;
    USE SIGNAL ;
    PORT
      LAYER M4 ;
        RECT  0 24.72 0.084 24.744 ;
    END
  END tap_d[23]
  PIN tap_d[240]
    DIRECTION OUTPUT ;
    USE SIGNAL ;
    PORT
      LAYER M4 ;
        RECT  0 45.504 0.084 45.528 ;
    END
  END tap_d[240]
  PIN tap_d[241]
    DIRECTION OUTPUT ;
    USE SIGNAL ;
    PORT
      LAYER M4 ;
        RECT  0 45.6 0.084 45.624 ;
    END
  END tap_d[241]
  PIN tap_d[242]
    DIRECTION OUTPUT ;
    USE SIGNAL ;
    PORT
      LAYER M4 ;
        RECT  0 45.696 0.084 45.72 ;
    END
  END tap_d[242]
  PIN tap_d[243]
    DIRECTION OUTPUT ;
    USE SIGNAL ;
    PORT
      LAYER M4 ;
        RECT  0 45.792 0.084 45.816 ;
    END
  END tap_d[243]
  PIN tap_d[244]
    DIRECTION OUTPUT ;
    USE SIGNAL ;
    PORT
      LAYER M4 ;
        RECT  0 45.888 0.084 45.912 ;
    END
  END tap_d[244]
  PIN tap_d[245]
    DIRECTION OUTPUT ;
    USE SIGNAL ;
    PORT
      LAYER M4 ;
        RECT  0 45.984 0.084 46.008 ;
    END
  END tap_d[245]
  PIN tap_d[246]
    DIRECTION OUTPUT ;
    USE SIGNAL ;
    PORT
      LAYER M4 ;
        RECT  0 46.08 0.084 46.104 ;
    END
  END tap_d[246]
  PIN tap_d[247]
    DIRECTION OUTPUT ;
    USE SIGNAL ;
    PORT
      LAYER M4 ;
        RECT  0 46.176 0.084 46.2 ;
    END
  END tap_d[247]
  PIN tap_d[248]
    DIRECTION OUTPUT ;
    USE SIGNAL ;
    PORT
      LAYER M4 ;
        RECT  0 46.272 0.084 46.296 ;
    END
  END tap_d[248]
  PIN tap_d[249]
    DIRECTION OUTPUT ;
    USE SIGNAL ;
    PORT
      LAYER M4 ;
        RECT  0 46.368 0.084 46.392 ;
    END
  END tap_d[249]
  PIN tap_d[24]
    DIRECTION OUTPUT ;
    USE SIGNAL ;
    PORT
      LAYER M4 ;
        RECT  0 24.816 0.084 24.84 ;
    END
  END tap_d[24]
  PIN tap_d[250]
    DIRECTION OUTPUT ;
    USE SIGNAL ;
    PORT
      LAYER M4 ;
        RECT  0 46.464 0.084 46.488 ;
    END
  END tap_d[250]
  PIN tap_d[251]
    DIRECTION OUTPUT ;
    USE SIGNAL ;
    PORT
      LAYER M4 ;
        RECT  0 46.56 0.084 46.584 ;
    END
  END tap_d[251]
  PIN tap_d[252]
    DIRECTION OUTPUT ;
    USE SIGNAL ;
    PORT
      LAYER M4 ;
        RECT  0 46.656 0.084 46.68 ;
    END
  END tap_d[252]
  PIN tap_d[253]
    DIRECTION OUTPUT ;
    USE SIGNAL ;
    PORT
      LAYER M4 ;
        RECT  0 46.752 0.084 46.776 ;
    END
  END tap_d[253]
  PIN tap_d[254]
    DIRECTION OUTPUT ;
    USE SIGNAL ;
    PORT
      LAYER M4 ;
        RECT  0 46.848 0.084 46.872 ;
    END
  END tap_d[254]
  PIN tap_d[255]
    DIRECTION OUTPUT ;
    USE SIGNAL ;
    PORT
      LAYER M4 ;
        RECT  0 46.944 0.084 46.968 ;
    END
  END tap_d[255]
  PIN tap_d[256]
    DIRECTION OUTPUT ;
    USE SIGNAL ;
    PORT
      LAYER M4 ;
        RECT  0 47.04 0.084 47.064 ;
    END
  END tap_d[256]
  PIN tap_d[257]
    DIRECTION OUTPUT ;
    USE SIGNAL ;
    PORT
      LAYER M4 ;
        RECT  0 47.136 0.084 47.16 ;
    END
  END tap_d[257]
  PIN tap_d[258]
    DIRECTION OUTPUT ;
    USE SIGNAL ;
    PORT
      LAYER M4 ;
        RECT  0 47.232 0.084 47.256 ;
    END
  END tap_d[258]
  PIN tap_d[259]
    DIRECTION OUTPUT ;
    USE SIGNAL ;
    PORT
      LAYER M4 ;
        RECT  0 47.328 0.084 47.352 ;
    END
  END tap_d[259]
  PIN tap_d[25]
    DIRECTION OUTPUT ;
    USE SIGNAL ;
    PORT
      LAYER M4 ;
        RECT  0 24.912 0.084 24.936 ;
    END
  END tap_d[25]
  PIN tap_d[260]
    DIRECTION OUTPUT ;
    USE SIGNAL ;
    PORT
      LAYER M4 ;
        RECT  0 47.424 0.084 47.448 ;
    END
  END tap_d[260]
  PIN tap_d[261]
    DIRECTION OUTPUT ;
    USE SIGNAL ;
    PORT
      LAYER M4 ;
        RECT  0 47.52 0.084 47.544 ;
    END
  END tap_d[261]
  PIN tap_d[262]
    DIRECTION OUTPUT ;
    USE SIGNAL ;
    PORT
      LAYER M4 ;
        RECT  0 47.616 0.084 47.64 ;
    END
  END tap_d[262]
  PIN tap_d[263]
    DIRECTION OUTPUT ;
    USE SIGNAL ;
    PORT
      LAYER M4 ;
        RECT  0 47.712 0.084 47.736 ;
    END
  END tap_d[263]
  PIN tap_d[264]
    DIRECTION OUTPUT ;
    USE SIGNAL ;
    PORT
      LAYER M4 ;
        RECT  0 47.808 0.084 47.832 ;
    END
  END tap_d[264]
  PIN tap_d[265]
    DIRECTION OUTPUT ;
    USE SIGNAL ;
    PORT
      LAYER M4 ;
        RECT  0 47.904 0.084 47.928 ;
    END
  END tap_d[265]
  PIN tap_d[266]
    DIRECTION OUTPUT ;
    USE SIGNAL ;
    PORT
      LAYER M4 ;
        RECT  0 48 0.084 48.024 ;
    END
  END tap_d[266]
  PIN tap_d[267]
    DIRECTION OUTPUT ;
    USE SIGNAL ;
    PORT
      LAYER M4 ;
        RECT  0 48.096 0.084 48.12 ;
    END
  END tap_d[267]
  PIN tap_d[268]
    DIRECTION OUTPUT ;
    USE SIGNAL ;
    PORT
      LAYER M4 ;
        RECT  0 48.192 0.084 48.216 ;
    END
  END tap_d[268]
  PIN tap_d[269]
    DIRECTION OUTPUT ;
    USE SIGNAL ;
    PORT
      LAYER M4 ;
        RECT  0 48.288 0.084 48.312 ;
    END
  END tap_d[269]
  PIN tap_d[26]
    DIRECTION OUTPUT ;
    USE SIGNAL ;
    PORT
      LAYER M4 ;
        RECT  0 25.008 0.084 25.032 ;
    END
  END tap_d[26]
  PIN tap_d[270]
    DIRECTION OUTPUT ;
    USE SIGNAL ;
    PORT
      LAYER M4 ;
        RECT  0 48.384 0.084 48.408 ;
    END
  END tap_d[270]
  PIN tap_d[271]
    DIRECTION OUTPUT ;
    USE SIGNAL ;
    PORT
      LAYER M4 ;
        RECT  0 48.48 0.084 48.504 ;
    END
  END tap_d[271]
  PIN tap_d[272]
    DIRECTION OUTPUT ;
    USE SIGNAL ;
    PORT
      LAYER M4 ;
        RECT  0 48.576 0.084 48.6 ;
    END
  END tap_d[272]
  PIN tap_d[273]
    DIRECTION OUTPUT ;
    USE SIGNAL ;
    PORT
      LAYER M4 ;
        RECT  0 48.672 0.084 48.696 ;
    END
  END tap_d[273]
  PIN tap_d[274]
    DIRECTION OUTPUT ;
    USE SIGNAL ;
    PORT
      LAYER M4 ;
        RECT  0 48.768 0.084 48.792 ;
    END
  END tap_d[274]
  PIN tap_d[275]
    DIRECTION OUTPUT ;
    USE SIGNAL ;
    PORT
      LAYER M4 ;
        RECT  0 48.864 0.084 48.888 ;
    END
  END tap_d[275]
  PIN tap_d[276]
    DIRECTION OUTPUT ;
    USE SIGNAL ;
    PORT
      LAYER M4 ;
        RECT  0 48.96 0.084 48.984 ;
    END
  END tap_d[276]
  PIN tap_d[277]
    DIRECTION OUTPUT ;
    USE SIGNAL ;
    PORT
      LAYER M4 ;
        RECT  0 49.056 0.084 49.08 ;
    END
  END tap_d[277]
  PIN tap_d[278]
    DIRECTION OUTPUT ;
    USE SIGNAL ;
    PORT
      LAYER M4 ;
        RECT  0 49.152 0.084 49.176 ;
    END
  END tap_d[278]
  PIN tap_d[279]
    DIRECTION OUTPUT ;
    USE SIGNAL ;
    PORT
      LAYER M4 ;
        RECT  0 49.248 0.084 49.272 ;
    END
  END tap_d[279]
  PIN tap_d[27]
    DIRECTION OUTPUT ;
    USE SIGNAL ;
    PORT
      LAYER M4 ;
        RECT  0 25.104 0.084 25.128 ;
    END
  END tap_d[27]
  PIN tap_d[280]
    DIRECTION OUTPUT ;
    USE SIGNAL ;
    PORT
      LAYER M4 ;
        RECT  0 49.344 0.084 49.368 ;
    END
  END tap_d[280]
  PIN tap_d[281]
    DIRECTION OUTPUT ;
    USE SIGNAL ;
    PORT
      LAYER M4 ;
        RECT  0 49.44 0.084 49.464 ;
    END
  END tap_d[281]
  PIN tap_d[282]
    DIRECTION OUTPUT ;
    USE SIGNAL ;
    PORT
      LAYER M4 ;
        RECT  0 49.536 0.084 49.56 ;
    END
  END tap_d[282]
  PIN tap_d[283]
    DIRECTION OUTPUT ;
    USE SIGNAL ;
    PORT
      LAYER M4 ;
        RECT  0 49.632 0.084 49.656 ;
    END
  END tap_d[283]
  PIN tap_d[284]
    DIRECTION OUTPUT ;
    USE SIGNAL ;
    PORT
      LAYER M4 ;
        RECT  0 49.728 0.084 49.752 ;
    END
  END tap_d[284]
  PIN tap_d[285]
    DIRECTION OUTPUT ;
    USE SIGNAL ;
    PORT
      LAYER M4 ;
        RECT  0 49.824 0.084 49.848 ;
    END
  END tap_d[285]
  PIN tap_d[286]
    DIRECTION OUTPUT ;
    USE SIGNAL ;
    PORT
      LAYER M4 ;
        RECT  0 49.92 0.084 49.944 ;
    END
  END tap_d[286]
  PIN tap_d[287]
    DIRECTION OUTPUT ;
    USE SIGNAL ;
    PORT
      LAYER M4 ;
        RECT  0 50.016 0.084 50.04 ;
    END
  END tap_d[287]
  PIN tap_d[288]
    DIRECTION OUTPUT ;
    USE SIGNAL ;
    PORT
      LAYER M4 ;
        RECT  0 50.112 0.084 50.136 ;
    END
  END tap_d[288]
  PIN tap_d[289]
    DIRECTION OUTPUT ;
    USE SIGNAL ;
    PORT
      LAYER M4 ;
        RECT  0 50.208 0.084 50.232 ;
    END
  END tap_d[289]
  PIN tap_d[28]
    DIRECTION OUTPUT ;
    USE SIGNAL ;
    PORT
      LAYER M4 ;
        RECT  0 25.2 0.084 25.224 ;
    END
  END tap_d[28]
  PIN tap_d[290]
    DIRECTION OUTPUT ;
    USE SIGNAL ;
    PORT
      LAYER M4 ;
        RECT  0 50.304 0.084 50.328 ;
    END
  END tap_d[290]
  PIN tap_d[291]
    DIRECTION OUTPUT ;
    USE SIGNAL ;
    PORT
      LAYER M4 ;
        RECT  0 50.4 0.084 50.424 ;
    END
  END tap_d[291]
  PIN tap_d[292]
    DIRECTION OUTPUT ;
    USE SIGNAL ;
    PORT
      LAYER M4 ;
        RECT  0 50.496 0.084 50.52 ;
    END
  END tap_d[292]
  PIN tap_d[293]
    DIRECTION OUTPUT ;
    USE SIGNAL ;
    PORT
      LAYER M4 ;
        RECT  0 50.592 0.084 50.616 ;
    END
  END tap_d[293]
  PIN tap_d[294]
    DIRECTION OUTPUT ;
    USE SIGNAL ;
    PORT
      LAYER M4 ;
        RECT  0 50.688 0.084 50.712 ;
    END
  END tap_d[294]
  PIN tap_d[295]
    DIRECTION OUTPUT ;
    USE SIGNAL ;
    PORT
      LAYER M4 ;
        RECT  0 50.784 0.084 50.808 ;
    END
  END tap_d[295]
  PIN tap_d[296]
    DIRECTION OUTPUT ;
    USE SIGNAL ;
    PORT
      LAYER M4 ;
        RECT  0 50.88 0.084 50.904 ;
    END
  END tap_d[296]
  PIN tap_d[297]
    DIRECTION OUTPUT ;
    USE SIGNAL ;
    PORT
      LAYER M4 ;
        RECT  0 50.976 0.084 51 ;
    END
  END tap_d[297]
  PIN tap_d[298]
    DIRECTION OUTPUT ;
    USE SIGNAL ;
    PORT
      LAYER M4 ;
        RECT  0 51.072 0.084 51.096 ;
    END
  END tap_d[298]
  PIN tap_d[299]
    DIRECTION OUTPUT ;
    USE SIGNAL ;
    PORT
      LAYER M4 ;
        RECT  0 51.168 0.084 51.192 ;
    END
  END tap_d[299]
  PIN tap_d[29]
    DIRECTION OUTPUT ;
    USE SIGNAL ;
    PORT
      LAYER M4 ;
        RECT  0 25.296 0.084 25.32 ;
    END
  END tap_d[29]
  PIN tap_d[2]
    DIRECTION OUTPUT ;
    USE SIGNAL ;
    PORT
      LAYER M4 ;
        RECT  0 22.704 0.084 22.728 ;
    END
  END tap_d[2]
  PIN tap_d[300]
    DIRECTION OUTPUT ;
    USE SIGNAL ;
    PORT
      LAYER M4 ;
        RECT  0 51.264 0.084 51.288 ;
    END
  END tap_d[300]
  PIN tap_d[301]
    DIRECTION OUTPUT ;
    USE SIGNAL ;
    PORT
      LAYER M4 ;
        RECT  0 51.36 0.084 51.384 ;
    END
  END tap_d[301]
  PIN tap_d[302]
    DIRECTION OUTPUT ;
    USE SIGNAL ;
    PORT
      LAYER M4 ;
        RECT  0 51.456 0.084 51.48 ;
    END
  END tap_d[302]
  PIN tap_d[303]
    DIRECTION OUTPUT ;
    USE SIGNAL ;
    PORT
      LAYER M4 ;
        RECT  0 51.552 0.084 51.576 ;
    END
  END tap_d[303]
  PIN tap_d[304]
    DIRECTION OUTPUT ;
    USE SIGNAL ;
    PORT
      LAYER M4 ;
        RECT  0 51.648 0.084 51.672 ;
    END
  END tap_d[304]
  PIN tap_d[305]
    DIRECTION OUTPUT ;
    USE SIGNAL ;
    PORT
      LAYER M4 ;
        RECT  0 51.744 0.084 51.768 ;
    END
  END tap_d[305]
  PIN tap_d[306]
    DIRECTION OUTPUT ;
    USE SIGNAL ;
    PORT
      LAYER M4 ;
        RECT  0 51.84 0.084 51.864 ;
    END
  END tap_d[306]
  PIN tap_d[307]
    DIRECTION OUTPUT ;
    USE SIGNAL ;
    PORT
      LAYER M4 ;
        RECT  0 51.936 0.084 51.96 ;
    END
  END tap_d[307]
  PIN tap_d[308]
    DIRECTION OUTPUT ;
    USE SIGNAL ;
    PORT
      LAYER M4 ;
        RECT  0 52.032 0.084 52.056 ;
    END
  END tap_d[308]
  PIN tap_d[309]
    DIRECTION OUTPUT ;
    USE SIGNAL ;
    PORT
      LAYER M4 ;
        RECT  0 52.128 0.084 52.152 ;
    END
  END tap_d[309]
  PIN tap_d[30]
    DIRECTION OUTPUT ;
    USE SIGNAL ;
    PORT
      LAYER M4 ;
        RECT  0 25.392 0.084 25.416 ;
    END
  END tap_d[30]
  PIN tap_d[310]
    DIRECTION OUTPUT ;
    USE SIGNAL ;
    PORT
      LAYER M4 ;
        RECT  0 52.224 0.084 52.248 ;
    END
  END tap_d[310]
  PIN tap_d[311]
    DIRECTION OUTPUT ;
    USE SIGNAL ;
    PORT
      LAYER M4 ;
        RECT  0 52.32 0.084 52.344 ;
    END
  END tap_d[311]
  PIN tap_d[312]
    DIRECTION OUTPUT ;
    USE SIGNAL ;
    PORT
      LAYER M4 ;
        RECT  0 52.416 0.084 52.44 ;
    END
  END tap_d[312]
  PIN tap_d[313]
    DIRECTION OUTPUT ;
    USE SIGNAL ;
    PORT
      LAYER M4 ;
        RECT  0 52.512 0.084 52.536 ;
    END
  END tap_d[313]
  PIN tap_d[314]
    DIRECTION OUTPUT ;
    USE SIGNAL ;
    PORT
      LAYER M4 ;
        RECT  0 52.608 0.084 52.632 ;
    END
  END tap_d[314]
  PIN tap_d[315]
    DIRECTION OUTPUT ;
    USE SIGNAL ;
    PORT
      LAYER M4 ;
        RECT  0 52.704 0.084 52.728 ;
    END
  END tap_d[315]
  PIN tap_d[316]
    DIRECTION OUTPUT ;
    USE SIGNAL ;
    PORT
      LAYER M4 ;
        RECT  0 52.8 0.084 52.824 ;
    END
  END tap_d[316]
  PIN tap_d[317]
    DIRECTION OUTPUT ;
    USE SIGNAL ;
    PORT
      LAYER M4 ;
        RECT  0 52.896 0.084 52.92 ;
    END
  END tap_d[317]
  PIN tap_d[318]
    DIRECTION OUTPUT ;
    USE SIGNAL ;
    PORT
      LAYER M4 ;
        RECT  0 52.992 0.084 53.016 ;
    END
  END tap_d[318]
  PIN tap_d[319]
    DIRECTION OUTPUT ;
    USE SIGNAL ;
    PORT
      LAYER M4 ;
        RECT  0 53.088 0.084 53.112 ;
    END
  END tap_d[319]
  PIN tap_d[31]
    DIRECTION OUTPUT ;
    USE SIGNAL ;
    PORT
      LAYER M4 ;
        RECT  0 25.488 0.084 25.512 ;
    END
  END tap_d[31]
  PIN tap_d[320]
    DIRECTION OUTPUT ;
    USE SIGNAL ;
    PORT
      LAYER M4 ;
        RECT  0 53.136 0.084 53.16 ;
    END
  END tap_d[320]
  PIN tap_d[321]
    DIRECTION OUTPUT ;
    USE SIGNAL ;
    PORT
      LAYER M4 ;
        RECT  0 53.232 0.084 53.256 ;
    END
  END tap_d[321]
  PIN tap_d[322]
    DIRECTION OUTPUT ;
    USE SIGNAL ;
    PORT
      LAYER M4 ;
        RECT  0 53.328 0.084 53.352 ;
    END
  END tap_d[322]
  PIN tap_d[323]
    DIRECTION OUTPUT ;
    USE SIGNAL ;
    PORT
      LAYER M4 ;
        RECT  0 53.424 0.084 53.448 ;
    END
  END tap_d[323]
  PIN tap_d[324]
    DIRECTION OUTPUT ;
    USE SIGNAL ;
    PORT
      LAYER M4 ;
        RECT  0 53.52 0.084 53.544 ;
    END
  END tap_d[324]
  PIN tap_d[325]
    DIRECTION OUTPUT ;
    USE SIGNAL ;
    PORT
      LAYER M4 ;
        RECT  0 53.616 0.084 53.64 ;
    END
  END tap_d[325]
  PIN tap_d[326]
    DIRECTION OUTPUT ;
    USE SIGNAL ;
    PORT
      LAYER M4 ;
        RECT  0 53.712 0.084 53.736 ;
    END
  END tap_d[326]
  PIN tap_d[327]
    DIRECTION OUTPUT ;
    USE SIGNAL ;
    PORT
      LAYER M4 ;
        RECT  0 53.808 0.084 53.832 ;
    END
  END tap_d[327]
  PIN tap_d[328]
    DIRECTION OUTPUT ;
    USE SIGNAL ;
    PORT
      LAYER M4 ;
        RECT  0 53.904 0.084 53.928 ;
    END
  END tap_d[328]
  PIN tap_d[329]
    DIRECTION OUTPUT ;
    USE SIGNAL ;
    PORT
      LAYER M4 ;
        RECT  0 54 0.084 54.024 ;
    END
  END tap_d[329]
  PIN tap_d[32]
    DIRECTION OUTPUT ;
    USE SIGNAL ;
    PORT
      LAYER M4 ;
        RECT  0 25.584 0.084 25.608 ;
    END
  END tap_d[32]
  PIN tap_d[330]
    DIRECTION OUTPUT ;
    USE SIGNAL ;
    PORT
      LAYER M4 ;
        RECT  0 54.096 0.084 54.12 ;
    END
  END tap_d[330]
  PIN tap_d[331]
    DIRECTION OUTPUT ;
    USE SIGNAL ;
    PORT
      LAYER M4 ;
        RECT  0 54.192 0.084 54.216 ;
    END
  END tap_d[331]
  PIN tap_d[332]
    DIRECTION OUTPUT ;
    USE SIGNAL ;
    PORT
      LAYER M4 ;
        RECT  0 54.288 0.084 54.312 ;
    END
  END tap_d[332]
  PIN tap_d[333]
    DIRECTION OUTPUT ;
    USE SIGNAL ;
    PORT
      LAYER M4 ;
        RECT  0 54.384 0.084 54.408 ;
    END
  END tap_d[333]
  PIN tap_d[334]
    DIRECTION OUTPUT ;
    USE SIGNAL ;
    PORT
      LAYER M4 ;
        RECT  0 54.48 0.084 54.504 ;
    END
  END tap_d[334]
  PIN tap_d[335]
    DIRECTION OUTPUT ;
    USE SIGNAL ;
    PORT
      LAYER M4 ;
        RECT  0 54.576 0.084 54.6 ;
    END
  END tap_d[335]
  PIN tap_d[336]
    DIRECTION OUTPUT ;
    USE SIGNAL ;
    PORT
      LAYER M4 ;
        RECT  0 54.672 0.084 54.696 ;
    END
  END tap_d[336]
  PIN tap_d[337]
    DIRECTION OUTPUT ;
    USE SIGNAL ;
    PORT
      LAYER M4 ;
        RECT  0 54.768 0.084 54.792 ;
    END
  END tap_d[337]
  PIN tap_d[338]
    DIRECTION OUTPUT ;
    USE SIGNAL ;
    PORT
      LAYER M4 ;
        RECT  0 54.864 0.084 54.888 ;
    END
  END tap_d[338]
  PIN tap_d[339]
    DIRECTION OUTPUT ;
    USE SIGNAL ;
    PORT
      LAYER M4 ;
        RECT  0 54.96 0.084 54.984 ;
    END
  END tap_d[339]
  PIN tap_d[33]
    DIRECTION OUTPUT ;
    USE SIGNAL ;
    PORT
      LAYER M4 ;
        RECT  0 25.68 0.084 25.704 ;
    END
  END tap_d[33]
  PIN tap_d[340]
    DIRECTION OUTPUT ;
    USE SIGNAL ;
    PORT
      LAYER M4 ;
        RECT  0 55.056 0.084 55.08 ;
    END
  END tap_d[340]
  PIN tap_d[341]
    DIRECTION OUTPUT ;
    USE SIGNAL ;
    PORT
      LAYER M4 ;
        RECT  0 55.152 0.084 55.176 ;
    END
  END tap_d[341]
  PIN tap_d[342]
    DIRECTION OUTPUT ;
    USE SIGNAL ;
    PORT
      LAYER M4 ;
        RECT  0 55.248 0.084 55.272 ;
    END
  END tap_d[342]
  PIN tap_d[343]
    DIRECTION OUTPUT ;
    USE SIGNAL ;
    PORT
      LAYER M4 ;
        RECT  0 55.344 0.084 55.368 ;
    END
  END tap_d[343]
  PIN tap_d[344]
    DIRECTION OUTPUT ;
    USE SIGNAL ;
    PORT
      LAYER M4 ;
        RECT  0 55.44 0.084 55.464 ;
    END
  END tap_d[344]
  PIN tap_d[345]
    DIRECTION OUTPUT ;
    USE SIGNAL ;
    PORT
      LAYER M4 ;
        RECT  0 55.536 0.084 55.56 ;
    END
  END tap_d[345]
  PIN tap_d[346]
    DIRECTION OUTPUT ;
    USE SIGNAL ;
    PORT
      LAYER M4 ;
        RECT  0 55.632 0.084 55.656 ;
    END
  END tap_d[346]
  PIN tap_d[347]
    DIRECTION OUTPUT ;
    USE SIGNAL ;
    PORT
      LAYER M4 ;
        RECT  0 55.728 0.084 55.752 ;
    END
  END tap_d[347]
  PIN tap_d[348]
    DIRECTION OUTPUT ;
    USE SIGNAL ;
    PORT
      LAYER M4 ;
        RECT  0 55.824 0.084 55.848 ;
    END
  END tap_d[348]
  PIN tap_d[349]
    DIRECTION OUTPUT ;
    USE SIGNAL ;
    PORT
      LAYER M4 ;
        RECT  0 55.92 0.084 55.944 ;
    END
  END tap_d[349]
  PIN tap_d[34]
    DIRECTION OUTPUT ;
    USE SIGNAL ;
    PORT
      LAYER M4 ;
        RECT  0 25.776 0.084 25.8 ;
    END
  END tap_d[34]
  PIN tap_d[350]
    DIRECTION OUTPUT ;
    USE SIGNAL ;
    PORT
      LAYER M4 ;
        RECT  0 56.016 0.084 56.04 ;
    END
  END tap_d[350]
  PIN tap_d[351]
    DIRECTION OUTPUT ;
    USE SIGNAL ;
    PORT
      LAYER M4 ;
        RECT  0 56.112 0.084 56.136 ;
    END
  END tap_d[351]
  PIN tap_d[352]
    DIRECTION OUTPUT ;
    USE SIGNAL ;
    PORT
      LAYER M4 ;
        RECT  0 56.208 0.084 56.232 ;
    END
  END tap_d[352]
  PIN tap_d[353]
    DIRECTION OUTPUT ;
    USE SIGNAL ;
    PORT
      LAYER M4 ;
        RECT  0 56.304 0.084 56.328 ;
    END
  END tap_d[353]
  PIN tap_d[354]
    DIRECTION OUTPUT ;
    USE SIGNAL ;
    PORT
      LAYER M4 ;
        RECT  0 56.4 0.084 56.424 ;
    END
  END tap_d[354]
  PIN tap_d[355]
    DIRECTION OUTPUT ;
    USE SIGNAL ;
    PORT
      LAYER M4 ;
        RECT  0 56.496 0.084 56.52 ;
    END
  END tap_d[355]
  PIN tap_d[356]
    DIRECTION OUTPUT ;
    USE SIGNAL ;
    PORT
      LAYER M4 ;
        RECT  0 56.592 0.084 56.616 ;
    END
  END tap_d[356]
  PIN tap_d[357]
    DIRECTION OUTPUT ;
    USE SIGNAL ;
    PORT
      LAYER M4 ;
        RECT  0 56.688 0.084 56.712 ;
    END
  END tap_d[357]
  PIN tap_d[358]
    DIRECTION OUTPUT ;
    USE SIGNAL ;
    PORT
      LAYER M4 ;
        RECT  0 56.784 0.084 56.808 ;
    END
  END tap_d[358]
  PIN tap_d[359]
    DIRECTION OUTPUT ;
    USE SIGNAL ;
    PORT
      LAYER M4 ;
        RECT  0 56.88 0.084 56.904 ;
    END
  END tap_d[359]
  PIN tap_d[35]
    DIRECTION OUTPUT ;
    USE SIGNAL ;
    PORT
      LAYER M4 ;
        RECT  0 25.872 0.084 25.896 ;
    END
  END tap_d[35]
  PIN tap_d[360]
    DIRECTION OUTPUT ;
    USE SIGNAL ;
    PORT
      LAYER M4 ;
        RECT  0 56.976 0.084 57 ;
    END
  END tap_d[360]
  PIN tap_d[361]
    DIRECTION OUTPUT ;
    USE SIGNAL ;
    PORT
      LAYER M4 ;
        RECT  0 57.072 0.084 57.096 ;
    END
  END tap_d[361]
  PIN tap_d[362]
    DIRECTION OUTPUT ;
    USE SIGNAL ;
    PORT
      LAYER M4 ;
        RECT  0 57.168 0.084 57.192 ;
    END
  END tap_d[362]
  PIN tap_d[363]
    DIRECTION OUTPUT ;
    USE SIGNAL ;
    PORT
      LAYER M4 ;
        RECT  0 57.264 0.084 57.288 ;
    END
  END tap_d[363]
  PIN tap_d[364]
    DIRECTION OUTPUT ;
    USE SIGNAL ;
    PORT
      LAYER M4 ;
        RECT  0 57.36 0.084 57.384 ;
    END
  END tap_d[364]
  PIN tap_d[365]
    DIRECTION OUTPUT ;
    USE SIGNAL ;
    PORT
      LAYER M4 ;
        RECT  0 57.456 0.084 57.48 ;
    END
  END tap_d[365]
  PIN tap_d[366]
    DIRECTION OUTPUT ;
    USE SIGNAL ;
    PORT
      LAYER M4 ;
        RECT  0 57.552 0.084 57.576 ;
    END
  END tap_d[366]
  PIN tap_d[367]
    DIRECTION OUTPUT ;
    USE SIGNAL ;
    PORT
      LAYER M4 ;
        RECT  0 57.648 0.084 57.672 ;
    END
  END tap_d[367]
  PIN tap_d[368]
    DIRECTION OUTPUT ;
    USE SIGNAL ;
    PORT
      LAYER M4 ;
        RECT  0 57.744 0.084 57.768 ;
    END
  END tap_d[368]
  PIN tap_d[369]
    DIRECTION OUTPUT ;
    USE SIGNAL ;
    PORT
      LAYER M4 ;
        RECT  0 57.84 0.084 57.864 ;
    END
  END tap_d[369]
  PIN tap_d[36]
    DIRECTION OUTPUT ;
    USE SIGNAL ;
    PORT
      LAYER M4 ;
        RECT  0 25.968 0.084 25.992 ;
    END
  END tap_d[36]
  PIN tap_d[370]
    DIRECTION OUTPUT ;
    USE SIGNAL ;
    PORT
      LAYER M4 ;
        RECT  0 57.936 0.084 57.96 ;
    END
  END tap_d[370]
  PIN tap_d[371]
    DIRECTION OUTPUT ;
    USE SIGNAL ;
    PORT
      LAYER M4 ;
        RECT  0 58.032 0.084 58.056 ;
    END
  END tap_d[371]
  PIN tap_d[372]
    DIRECTION OUTPUT ;
    USE SIGNAL ;
    PORT
      LAYER M4 ;
        RECT  0 58.128 0.084 58.152 ;
    END
  END tap_d[372]
  PIN tap_d[373]
    DIRECTION OUTPUT ;
    USE SIGNAL ;
    PORT
      LAYER M4 ;
        RECT  0 58.224 0.084 58.248 ;
    END
  END tap_d[373]
  PIN tap_d[374]
    DIRECTION OUTPUT ;
    USE SIGNAL ;
    PORT
      LAYER M4 ;
        RECT  0 58.32 0.084 58.344 ;
    END
  END tap_d[374]
  PIN tap_d[375]
    DIRECTION OUTPUT ;
    USE SIGNAL ;
    PORT
      LAYER M4 ;
        RECT  0 58.416 0.084 58.44 ;
    END
  END tap_d[375]
  PIN tap_d[376]
    DIRECTION OUTPUT ;
    USE SIGNAL ;
    PORT
      LAYER M4 ;
        RECT  0 58.512 0.084 58.536 ;
    END
  END tap_d[376]
  PIN tap_d[377]
    DIRECTION OUTPUT ;
    USE SIGNAL ;
    PORT
      LAYER M4 ;
        RECT  0 58.608 0.084 58.632 ;
    END
  END tap_d[377]
  PIN tap_d[378]
    DIRECTION OUTPUT ;
    USE SIGNAL ;
    PORT
      LAYER M4 ;
        RECT  0 58.704 0.084 58.728 ;
    END
  END tap_d[378]
  PIN tap_d[379]
    DIRECTION OUTPUT ;
    USE SIGNAL ;
    PORT
      LAYER M4 ;
        RECT  0 58.8 0.084 58.824 ;
    END
  END tap_d[379]
  PIN tap_d[37]
    DIRECTION OUTPUT ;
    USE SIGNAL ;
    PORT
      LAYER M4 ;
        RECT  0 26.064 0.084 26.088 ;
    END
  END tap_d[37]
  PIN tap_d[380]
    DIRECTION OUTPUT ;
    USE SIGNAL ;
    PORT
      LAYER M4 ;
        RECT  0 58.896 0.084 58.92 ;
    END
  END tap_d[380]
  PIN tap_d[381]
    DIRECTION OUTPUT ;
    USE SIGNAL ;
    PORT
      LAYER M4 ;
        RECT  0 58.992 0.084 59.016 ;
    END
  END tap_d[381]
  PIN tap_d[382]
    DIRECTION OUTPUT ;
    USE SIGNAL ;
    PORT
      LAYER M4 ;
        RECT  0 59.088 0.084 59.112 ;
    END
  END tap_d[382]
  PIN tap_d[383]
    DIRECTION OUTPUT ;
    USE SIGNAL ;
    PORT
      LAYER M4 ;
        RECT  0 59.184 0.084 59.208 ;
    END
  END tap_d[383]
  PIN tap_d[384]
    DIRECTION OUTPUT ;
    USE SIGNAL ;
    PORT
      LAYER M4 ;
        RECT  0 59.28 0.084 59.304 ;
    END
  END tap_d[384]
  PIN tap_d[385]
    DIRECTION OUTPUT ;
    USE SIGNAL ;
    PORT
      LAYER M4 ;
        RECT  0 59.376 0.084 59.4 ;
    END
  END tap_d[385]
  PIN tap_d[386]
    DIRECTION OUTPUT ;
    USE SIGNAL ;
    PORT
      LAYER M4 ;
        RECT  0 59.472 0.084 59.496 ;
    END
  END tap_d[386]
  PIN tap_d[387]
    DIRECTION OUTPUT ;
    USE SIGNAL ;
    PORT
      LAYER M4 ;
        RECT  0 59.568 0.084 59.592 ;
    END
  END tap_d[387]
  PIN tap_d[388]
    DIRECTION OUTPUT ;
    USE SIGNAL ;
    PORT
      LAYER M4 ;
        RECT  0 59.664 0.084 59.688 ;
    END
  END tap_d[388]
  PIN tap_d[389]
    DIRECTION OUTPUT ;
    USE SIGNAL ;
    PORT
      LAYER M4 ;
        RECT  0 59.76 0.084 59.784 ;
    END
  END tap_d[389]
  PIN tap_d[38]
    DIRECTION OUTPUT ;
    USE SIGNAL ;
    PORT
      LAYER M4 ;
        RECT  0 26.16 0.084 26.184 ;
    END
  END tap_d[38]
  PIN tap_d[390]
    DIRECTION OUTPUT ;
    USE SIGNAL ;
    PORT
      LAYER M4 ;
        RECT  0 59.856 0.084 59.88 ;
    END
  END tap_d[390]
  PIN tap_d[391]
    DIRECTION OUTPUT ;
    USE SIGNAL ;
    PORT
      LAYER M4 ;
        RECT  0 59.952 0.084 59.976 ;
    END
  END tap_d[391]
  PIN tap_d[392]
    DIRECTION OUTPUT ;
    USE SIGNAL ;
    PORT
      LAYER M4 ;
        RECT  0 60.048 0.084 60.072 ;
    END
  END tap_d[392]
  PIN tap_d[393]
    DIRECTION OUTPUT ;
    USE SIGNAL ;
    PORT
      LAYER M4 ;
        RECT  0 60.144 0.084 60.168 ;
    END
  END tap_d[393]
  PIN tap_d[394]
    DIRECTION OUTPUT ;
    USE SIGNAL ;
    PORT
      LAYER M4 ;
        RECT  0 60.24 0.084 60.264 ;
    END
  END tap_d[394]
  PIN tap_d[395]
    DIRECTION OUTPUT ;
    USE SIGNAL ;
    PORT
      LAYER M4 ;
        RECT  0 60.336 0.084 60.36 ;
    END
  END tap_d[395]
  PIN tap_d[396]
    DIRECTION OUTPUT ;
    USE SIGNAL ;
    PORT
      LAYER M4 ;
        RECT  0 60.432 0.084 60.456 ;
    END
  END tap_d[396]
  PIN tap_d[397]
    DIRECTION OUTPUT ;
    USE SIGNAL ;
    PORT
      LAYER M4 ;
        RECT  0 60.528 0.084 60.552 ;
    END
  END tap_d[397]
  PIN tap_d[398]
    DIRECTION OUTPUT ;
    USE SIGNAL ;
    PORT
      LAYER M4 ;
        RECT  0 60.624 0.084 60.648 ;
    END
  END tap_d[398]
  PIN tap_d[399]
    DIRECTION OUTPUT ;
    USE SIGNAL ;
    PORT
      LAYER M4 ;
        RECT  0 60.72 0.084 60.744 ;
    END
  END tap_d[399]
  PIN tap_d[39]
    DIRECTION OUTPUT ;
    USE SIGNAL ;
    PORT
      LAYER M4 ;
        RECT  0 26.256 0.084 26.28 ;
    END
  END tap_d[39]
  PIN tap_d[3]
    DIRECTION OUTPUT ;
    USE SIGNAL ;
    PORT
      LAYER M4 ;
        RECT  0 22.8 0.084 22.824 ;
    END
  END tap_d[3]
  PIN tap_d[400]
    DIRECTION OUTPUT ;
    USE SIGNAL ;
    PORT
      LAYER M4 ;
        RECT  0 60.816 0.084 60.84 ;
    END
  END tap_d[400]
  PIN tap_d[401]
    DIRECTION OUTPUT ;
    USE SIGNAL ;
    PORT
      LAYER M4 ;
        RECT  0 60.912 0.084 60.936 ;
    END
  END tap_d[401]
  PIN tap_d[402]
    DIRECTION OUTPUT ;
    USE SIGNAL ;
    PORT
      LAYER M4 ;
        RECT  0 61.008 0.084 61.032 ;
    END
  END tap_d[402]
  PIN tap_d[403]
    DIRECTION OUTPUT ;
    USE SIGNAL ;
    PORT
      LAYER M4 ;
        RECT  0 61.104 0.084 61.128 ;
    END
  END tap_d[403]
  PIN tap_d[404]
    DIRECTION OUTPUT ;
    USE SIGNAL ;
    PORT
      LAYER M4 ;
        RECT  0 61.2 0.084 61.224 ;
    END
  END tap_d[404]
  PIN tap_d[405]
    DIRECTION OUTPUT ;
    USE SIGNAL ;
    PORT
      LAYER M4 ;
        RECT  0 61.296 0.084 61.32 ;
    END
  END tap_d[405]
  PIN tap_d[406]
    DIRECTION OUTPUT ;
    USE SIGNAL ;
    PORT
      LAYER M4 ;
        RECT  0 61.392 0.084 61.416 ;
    END
  END tap_d[406]
  PIN tap_d[407]
    DIRECTION OUTPUT ;
    USE SIGNAL ;
    PORT
      LAYER M4 ;
        RECT  0 61.488 0.084 61.512 ;
    END
  END tap_d[407]
  PIN tap_d[408]
    DIRECTION OUTPUT ;
    USE SIGNAL ;
    PORT
      LAYER M4 ;
        RECT  0 61.584 0.084 61.608 ;
    END
  END tap_d[408]
  PIN tap_d[409]
    DIRECTION OUTPUT ;
    USE SIGNAL ;
    PORT
      LAYER M4 ;
        RECT  0 61.68 0.084 61.704 ;
    END
  END tap_d[409]
  PIN tap_d[40]
    DIRECTION OUTPUT ;
    USE SIGNAL ;
    PORT
      LAYER M4 ;
        RECT  0 26.352 0.084 26.376 ;
    END
  END tap_d[40]
  PIN tap_d[410]
    DIRECTION OUTPUT ;
    USE SIGNAL ;
    PORT
      LAYER M4 ;
        RECT  0 61.776 0.084 61.8 ;
    END
  END tap_d[410]
  PIN tap_d[411]
    DIRECTION OUTPUT ;
    USE SIGNAL ;
    PORT
      LAYER M4 ;
        RECT  0 61.872 0.084 61.896 ;
    END
  END tap_d[411]
  PIN tap_d[412]
    DIRECTION OUTPUT ;
    USE SIGNAL ;
    PORT
      LAYER M4 ;
        RECT  0 61.968 0.084 61.992 ;
    END
  END tap_d[412]
  PIN tap_d[413]
    DIRECTION OUTPUT ;
    USE SIGNAL ;
    PORT
      LAYER M4 ;
        RECT  0 62.064 0.084 62.088 ;
    END
  END tap_d[413]
  PIN tap_d[414]
    DIRECTION OUTPUT ;
    USE SIGNAL ;
    PORT
      LAYER M4 ;
        RECT  0 62.16 0.084 62.184 ;
    END
  END tap_d[414]
  PIN tap_d[415]
    DIRECTION OUTPUT ;
    USE SIGNAL ;
    PORT
      LAYER M4 ;
        RECT  0 62.256 0.084 62.28 ;
    END
  END tap_d[415]
  PIN tap_d[416]
    DIRECTION OUTPUT ;
    USE SIGNAL ;
    PORT
      LAYER M4 ;
        RECT  0 62.352 0.084 62.376 ;
    END
  END tap_d[416]
  PIN tap_d[417]
    DIRECTION OUTPUT ;
    USE SIGNAL ;
    PORT
      LAYER M4 ;
        RECT  0 62.448 0.084 62.472 ;
    END
  END tap_d[417]
  PIN tap_d[418]
    DIRECTION OUTPUT ;
    USE SIGNAL ;
    PORT
      LAYER M4 ;
        RECT  0 62.544 0.084 62.568 ;
    END
  END tap_d[418]
  PIN tap_d[419]
    DIRECTION OUTPUT ;
    USE SIGNAL ;
    PORT
      LAYER M4 ;
        RECT  0 62.64 0.084 62.664 ;
    END
  END tap_d[419]
  PIN tap_d[41]
    DIRECTION OUTPUT ;
    USE SIGNAL ;
    PORT
      LAYER M4 ;
        RECT  0 26.448 0.084 26.472 ;
    END
  END tap_d[41]
  PIN tap_d[420]
    DIRECTION OUTPUT ;
    USE SIGNAL ;
    PORT
      LAYER M4 ;
        RECT  0 62.736 0.084 62.76 ;
    END
  END tap_d[420]
  PIN tap_d[421]
    DIRECTION OUTPUT ;
    USE SIGNAL ;
    PORT
      LAYER M4 ;
        RECT  0 62.832 0.084 62.856 ;
    END
  END tap_d[421]
  PIN tap_d[422]
    DIRECTION OUTPUT ;
    USE SIGNAL ;
    PORT
      LAYER M4 ;
        RECT  0 62.928 0.084 62.952 ;
    END
  END tap_d[422]
  PIN tap_d[423]
    DIRECTION OUTPUT ;
    USE SIGNAL ;
    PORT
      LAYER M4 ;
        RECT  0 63.024 0.084 63.048 ;
    END
  END tap_d[423]
  PIN tap_d[424]
    DIRECTION OUTPUT ;
    USE SIGNAL ;
    PORT
      LAYER M4 ;
        RECT  0 63.12 0.084 63.144 ;
    END
  END tap_d[424]
  PIN tap_d[425]
    DIRECTION OUTPUT ;
    USE SIGNAL ;
    PORT
      LAYER M4 ;
        RECT  0 63.216 0.084 63.24 ;
    END
  END tap_d[425]
  PIN tap_d[426]
    DIRECTION OUTPUT ;
    USE SIGNAL ;
    PORT
      LAYER M4 ;
        RECT  0 63.312 0.084 63.336 ;
    END
  END tap_d[426]
  PIN tap_d[427]
    DIRECTION OUTPUT ;
    USE SIGNAL ;
    PORT
      LAYER M4 ;
        RECT  0 63.408 0.084 63.432 ;
    END
  END tap_d[427]
  PIN tap_d[428]
    DIRECTION OUTPUT ;
    USE SIGNAL ;
    PORT
      LAYER M4 ;
        RECT  0 63.504 0.084 63.528 ;
    END
  END tap_d[428]
  PIN tap_d[429]
    DIRECTION OUTPUT ;
    USE SIGNAL ;
    PORT
      LAYER M4 ;
        RECT  0 63.6 0.084 63.624 ;
    END
  END tap_d[429]
  PIN tap_d[42]
    DIRECTION OUTPUT ;
    USE SIGNAL ;
    PORT
      LAYER M4 ;
        RECT  0 26.544 0.084 26.568 ;
    END
  END tap_d[42]
  PIN tap_d[430]
    DIRECTION OUTPUT ;
    USE SIGNAL ;
    PORT
      LAYER M4 ;
        RECT  0 63.696 0.084 63.72 ;
    END
  END tap_d[430]
  PIN tap_d[431]
    DIRECTION OUTPUT ;
    USE SIGNAL ;
    PORT
      LAYER M4 ;
        RECT  0 63.792 0.084 63.816 ;
    END
  END tap_d[431]
  PIN tap_d[432]
    DIRECTION OUTPUT ;
    USE SIGNAL ;
    PORT
      LAYER M4 ;
        RECT  0 63.888 0.084 63.912 ;
    END
  END tap_d[432]
  PIN tap_d[433]
    DIRECTION OUTPUT ;
    USE SIGNAL ;
    PORT
      LAYER M4 ;
        RECT  0 63.984 0.084 64.008 ;
    END
  END tap_d[433]
  PIN tap_d[434]
    DIRECTION OUTPUT ;
    USE SIGNAL ;
    PORT
      LAYER M4 ;
        RECT  0 64.08 0.084 64.104 ;
    END
  END tap_d[434]
  PIN tap_d[435]
    DIRECTION OUTPUT ;
    USE SIGNAL ;
    PORT
      LAYER M4 ;
        RECT  0 64.176 0.084 64.2 ;
    END
  END tap_d[435]
  PIN tap_d[436]
    DIRECTION OUTPUT ;
    USE SIGNAL ;
    PORT
      LAYER M4 ;
        RECT  0 64.272 0.084 64.296 ;
    END
  END tap_d[436]
  PIN tap_d[437]
    DIRECTION OUTPUT ;
    USE SIGNAL ;
    PORT
      LAYER M4 ;
        RECT  0 64.368 0.084 64.392 ;
    END
  END tap_d[437]
  PIN tap_d[438]
    DIRECTION OUTPUT ;
    USE SIGNAL ;
    PORT
      LAYER M4 ;
        RECT  0 64.464 0.084 64.488 ;
    END
  END tap_d[438]
  PIN tap_d[439]
    DIRECTION OUTPUT ;
    USE SIGNAL ;
    PORT
      LAYER M4 ;
        RECT  0 64.56 0.084 64.584 ;
    END
  END tap_d[439]
  PIN tap_d[43]
    DIRECTION OUTPUT ;
    USE SIGNAL ;
    PORT
      LAYER M4 ;
        RECT  0 26.64 0.084 26.664 ;
    END
  END tap_d[43]
  PIN tap_d[440]
    DIRECTION OUTPUT ;
    USE SIGNAL ;
    PORT
      LAYER M4 ;
        RECT  0 64.656 0.084 64.68 ;
    END
  END tap_d[440]
  PIN tap_d[441]
    DIRECTION OUTPUT ;
    USE SIGNAL ;
    PORT
      LAYER M4 ;
        RECT  0 64.752 0.084 64.776 ;
    END
  END tap_d[441]
  PIN tap_d[442]
    DIRECTION OUTPUT ;
    USE SIGNAL ;
    PORT
      LAYER M4 ;
        RECT  0 64.848 0.084 64.872 ;
    END
  END tap_d[442]
  PIN tap_d[443]
    DIRECTION OUTPUT ;
    USE SIGNAL ;
    PORT
      LAYER M4 ;
        RECT  0 64.944 0.084 64.968 ;
    END
  END tap_d[443]
  PIN tap_d[444]
    DIRECTION OUTPUT ;
    USE SIGNAL ;
    PORT
      LAYER M4 ;
        RECT  0 65.04 0.084 65.064 ;
    END
  END tap_d[444]
  PIN tap_d[445]
    DIRECTION OUTPUT ;
    USE SIGNAL ;
    PORT
      LAYER M4 ;
        RECT  0 65.136 0.084 65.16 ;
    END
  END tap_d[445]
  PIN tap_d[446]
    DIRECTION OUTPUT ;
    USE SIGNAL ;
    PORT
      LAYER M4 ;
        RECT  0 65.232 0.084 65.256 ;
    END
  END tap_d[446]
  PIN tap_d[447]
    DIRECTION OUTPUT ;
    USE SIGNAL ;
    PORT
      LAYER M4 ;
        RECT  0 65.328 0.084 65.352 ;
    END
  END tap_d[447]
  PIN tap_d[448]
    DIRECTION OUTPUT ;
    USE SIGNAL ;
    PORT
      LAYER M4 ;
        RECT  0 65.424 0.084 65.448 ;
    END
  END tap_d[448]
  PIN tap_d[449]
    DIRECTION OUTPUT ;
    USE SIGNAL ;
    PORT
      LAYER M4 ;
        RECT  0 65.52 0.084 65.544 ;
    END
  END tap_d[449]
  PIN tap_d[44]
    DIRECTION OUTPUT ;
    USE SIGNAL ;
    PORT
      LAYER M4 ;
        RECT  0 26.736 0.084 26.76 ;
    END
  END tap_d[44]
  PIN tap_d[450]
    DIRECTION OUTPUT ;
    USE SIGNAL ;
    PORT
      LAYER M4 ;
        RECT  0 65.616 0.084 65.64 ;
    END
  END tap_d[450]
  PIN tap_d[451]
    DIRECTION OUTPUT ;
    USE SIGNAL ;
    PORT
      LAYER M4 ;
        RECT  0 65.712 0.084 65.736 ;
    END
  END tap_d[451]
  PIN tap_d[452]
    DIRECTION OUTPUT ;
    USE SIGNAL ;
    PORT
      LAYER M4 ;
        RECT  0 65.808 0.084 65.832 ;
    END
  END tap_d[452]
  PIN tap_d[453]
    DIRECTION OUTPUT ;
    USE SIGNAL ;
    PORT
      LAYER M4 ;
        RECT  0 65.904 0.084 65.928 ;
    END
  END tap_d[453]
  PIN tap_d[454]
    DIRECTION OUTPUT ;
    USE SIGNAL ;
    PORT
      LAYER M4 ;
        RECT  0 66 0.084 66.024 ;
    END
  END tap_d[454]
  PIN tap_d[455]
    DIRECTION OUTPUT ;
    USE SIGNAL ;
    PORT
      LAYER M4 ;
        RECT  0 66.096 0.084 66.12 ;
    END
  END tap_d[455]
  PIN tap_d[456]
    DIRECTION OUTPUT ;
    USE SIGNAL ;
    PORT
      LAYER M4 ;
        RECT  0 66.192 0.084 66.216 ;
    END
  END tap_d[456]
  PIN tap_d[457]
    DIRECTION OUTPUT ;
    USE SIGNAL ;
    PORT
      LAYER M4 ;
        RECT  0 66.288 0.084 66.312 ;
    END
  END tap_d[457]
  PIN tap_d[458]
    DIRECTION OUTPUT ;
    USE SIGNAL ;
    PORT
      LAYER M4 ;
        RECT  0 66.384 0.084 66.408 ;
    END
  END tap_d[458]
  PIN tap_d[459]
    DIRECTION OUTPUT ;
    USE SIGNAL ;
    PORT
      LAYER M4 ;
        RECT  0 66.48 0.084 66.504 ;
    END
  END tap_d[459]
  PIN tap_d[45]
    DIRECTION OUTPUT ;
    USE SIGNAL ;
    PORT
      LAYER M4 ;
        RECT  0 26.832 0.084 26.856 ;
    END
  END tap_d[45]
  PIN tap_d[460]
    DIRECTION OUTPUT ;
    USE SIGNAL ;
    PORT
      LAYER M4 ;
        RECT  0 66.576 0.084 66.6 ;
    END
  END tap_d[460]
  PIN tap_d[461]
    DIRECTION OUTPUT ;
    USE SIGNAL ;
    PORT
      LAYER M4 ;
        RECT  0 66.672 0.084 66.696 ;
    END
  END tap_d[461]
  PIN tap_d[462]
    DIRECTION OUTPUT ;
    USE SIGNAL ;
    PORT
      LAYER M4 ;
        RECT  0 66.768 0.084 66.792 ;
    END
  END tap_d[462]
  PIN tap_d[463]
    DIRECTION OUTPUT ;
    USE SIGNAL ;
    PORT
      LAYER M4 ;
        RECT  0 66.864 0.084 66.888 ;
    END
  END tap_d[463]
  PIN tap_d[464]
    DIRECTION OUTPUT ;
    USE SIGNAL ;
    PORT
      LAYER M4 ;
        RECT  0 66.96 0.084 66.984 ;
    END
  END tap_d[464]
  PIN tap_d[465]
    DIRECTION OUTPUT ;
    USE SIGNAL ;
    PORT
      LAYER M4 ;
        RECT  0 67.056 0.084 67.08 ;
    END
  END tap_d[465]
  PIN tap_d[466]
    DIRECTION OUTPUT ;
    USE SIGNAL ;
    PORT
      LAYER M4 ;
        RECT  0 67.152 0.084 67.176 ;
    END
  END tap_d[466]
  PIN tap_d[467]
    DIRECTION OUTPUT ;
    USE SIGNAL ;
    PORT
      LAYER M4 ;
        RECT  0 67.248 0.084 67.272 ;
    END
  END tap_d[467]
  PIN tap_d[468]
    DIRECTION OUTPUT ;
    USE SIGNAL ;
    PORT
      LAYER M4 ;
        RECT  0 67.344 0.084 67.368 ;
    END
  END tap_d[468]
  PIN tap_d[469]
    DIRECTION OUTPUT ;
    USE SIGNAL ;
    PORT
      LAYER M4 ;
        RECT  0 67.44 0.084 67.464 ;
    END
  END tap_d[469]
  PIN tap_d[46]
    DIRECTION OUTPUT ;
    USE SIGNAL ;
    PORT
      LAYER M4 ;
        RECT  0 26.928 0.084 26.952 ;
    END
  END tap_d[46]
  PIN tap_d[470]
    DIRECTION OUTPUT ;
    USE SIGNAL ;
    PORT
      LAYER M4 ;
        RECT  0 67.536 0.084 67.56 ;
    END
  END tap_d[470]
  PIN tap_d[471]
    DIRECTION OUTPUT ;
    USE SIGNAL ;
    PORT
      LAYER M4 ;
        RECT  0 67.632 0.084 67.656 ;
    END
  END tap_d[471]
  PIN tap_d[472]
    DIRECTION OUTPUT ;
    USE SIGNAL ;
    PORT
      LAYER M4 ;
        RECT  0 67.728 0.084 67.752 ;
    END
  END tap_d[472]
  PIN tap_d[473]
    DIRECTION OUTPUT ;
    USE SIGNAL ;
    PORT
      LAYER M4 ;
        RECT  0 67.824 0.084 67.848 ;
    END
  END tap_d[473]
  PIN tap_d[474]
    DIRECTION OUTPUT ;
    USE SIGNAL ;
    PORT
      LAYER M4 ;
        RECT  0 67.92 0.084 67.944 ;
    END
  END tap_d[474]
  PIN tap_d[475]
    DIRECTION OUTPUT ;
    USE SIGNAL ;
    PORT
      LAYER M4 ;
        RECT  0 68.016 0.084 68.04 ;
    END
  END tap_d[475]
  PIN tap_d[476]
    DIRECTION OUTPUT ;
    USE SIGNAL ;
    PORT
      LAYER M4 ;
        RECT  0 68.112 0.084 68.136 ;
    END
  END tap_d[476]
  PIN tap_d[477]
    DIRECTION OUTPUT ;
    USE SIGNAL ;
    PORT
      LAYER M4 ;
        RECT  0 68.208 0.084 68.232 ;
    END
  END tap_d[477]
  PIN tap_d[478]
    DIRECTION OUTPUT ;
    USE SIGNAL ;
    PORT
      LAYER M4 ;
        RECT  0 68.304 0.084 68.328 ;
    END
  END tap_d[478]
  PIN tap_d[479]
    DIRECTION OUTPUT ;
    USE SIGNAL ;
    PORT
      LAYER M4 ;
        RECT  0 68.4 0.084 68.424 ;
    END
  END tap_d[479]
  PIN tap_d[47]
    DIRECTION OUTPUT ;
    USE SIGNAL ;
    PORT
      LAYER M4 ;
        RECT  0 27.024 0.084 27.048 ;
    END
  END tap_d[47]
  PIN tap_d[480]
    DIRECTION OUTPUT ;
    USE SIGNAL ;
    PORT
      LAYER M4 ;
        RECT  0 68.496 0.084 68.52 ;
    END
  END tap_d[480]
  PIN tap_d[481]
    DIRECTION OUTPUT ;
    USE SIGNAL ;
    PORT
      LAYER M4 ;
        RECT  0 68.592 0.084 68.616 ;
    END
  END tap_d[481]
  PIN tap_d[482]
    DIRECTION OUTPUT ;
    USE SIGNAL ;
    PORT
      LAYER M4 ;
        RECT  0 68.688 0.084 68.712 ;
    END
  END tap_d[482]
  PIN tap_d[483]
    DIRECTION OUTPUT ;
    USE SIGNAL ;
    PORT
      LAYER M4 ;
        RECT  0 68.784 0.084 68.808 ;
    END
  END tap_d[483]
  PIN tap_d[484]
    DIRECTION OUTPUT ;
    USE SIGNAL ;
    PORT
      LAYER M4 ;
        RECT  0 68.88 0.084 68.904 ;
    END
  END tap_d[484]
  PIN tap_d[485]
    DIRECTION OUTPUT ;
    USE SIGNAL ;
    PORT
      LAYER M4 ;
        RECT  0 68.976 0.084 69 ;
    END
  END tap_d[485]
  PIN tap_d[486]
    DIRECTION OUTPUT ;
    USE SIGNAL ;
    PORT
      LAYER M4 ;
        RECT  0 69.072 0.084 69.096 ;
    END
  END tap_d[486]
  PIN tap_d[487]
    DIRECTION OUTPUT ;
    USE SIGNAL ;
    PORT
      LAYER M4 ;
        RECT  0 69.168 0.084 69.192 ;
    END
  END tap_d[487]
  PIN tap_d[488]
    DIRECTION OUTPUT ;
    USE SIGNAL ;
    PORT
      LAYER M4 ;
        RECT  0 69.264 0.084 69.288 ;
    END
  END tap_d[488]
  PIN tap_d[489]
    DIRECTION OUTPUT ;
    USE SIGNAL ;
    PORT
      LAYER M4 ;
        RECT  0 69.36 0.084 69.384 ;
    END
  END tap_d[489]
  PIN tap_d[48]
    DIRECTION OUTPUT ;
    USE SIGNAL ;
    PORT
      LAYER M4 ;
        RECT  0 27.12 0.084 27.144 ;
    END
  END tap_d[48]
  PIN tap_d[490]
    DIRECTION OUTPUT ;
    USE SIGNAL ;
    PORT
      LAYER M4 ;
        RECT  0 69.456 0.084 69.48 ;
    END
  END tap_d[490]
  PIN tap_d[491]
    DIRECTION OUTPUT ;
    USE SIGNAL ;
    PORT
      LAYER M4 ;
        RECT  0 69.552 0.084 69.576 ;
    END
  END tap_d[491]
  PIN tap_d[492]
    DIRECTION OUTPUT ;
    USE SIGNAL ;
    PORT
      LAYER M4 ;
        RECT  0 69.648 0.084 69.672 ;
    END
  END tap_d[492]
  PIN tap_d[493]
    DIRECTION OUTPUT ;
    USE SIGNAL ;
    PORT
      LAYER M4 ;
        RECT  0 69.744 0.084 69.768 ;
    END
  END tap_d[493]
  PIN tap_d[494]
    DIRECTION OUTPUT ;
    USE SIGNAL ;
    PORT
      LAYER M4 ;
        RECT  0 69.84 0.084 69.864 ;
    END
  END tap_d[494]
  PIN tap_d[495]
    DIRECTION OUTPUT ;
    USE SIGNAL ;
    PORT
      LAYER M4 ;
        RECT  0 69.936 0.084 69.96 ;
    END
  END tap_d[495]
  PIN tap_d[496]
    DIRECTION OUTPUT ;
    USE SIGNAL ;
    PORT
      LAYER M4 ;
        RECT  0 70.032 0.084 70.056 ;
    END
  END tap_d[496]
  PIN tap_d[497]
    DIRECTION OUTPUT ;
    USE SIGNAL ;
    PORT
      LAYER M4 ;
        RECT  0 70.128 0.084 70.152 ;
    END
  END tap_d[497]
  PIN tap_d[498]
    DIRECTION OUTPUT ;
    USE SIGNAL ;
    PORT
      LAYER M4 ;
        RECT  0 70.224 0.084 70.248 ;
    END
  END tap_d[498]
  PIN tap_d[499]
    DIRECTION OUTPUT ;
    USE SIGNAL ;
    PORT
      LAYER M4 ;
        RECT  0 70.32 0.084 70.344 ;
    END
  END tap_d[499]
  PIN tap_d[49]
    DIRECTION OUTPUT ;
    USE SIGNAL ;
    PORT
      LAYER M4 ;
        RECT  0 27.216 0.084 27.24 ;
    END
  END tap_d[49]
  PIN tap_d[4]
    DIRECTION OUTPUT ;
    USE SIGNAL ;
    PORT
      LAYER M4 ;
        RECT  0 22.896 0.084 22.92 ;
    END
  END tap_d[4]
  PIN tap_d[500]
    DIRECTION OUTPUT ;
    USE SIGNAL ;
    PORT
      LAYER M4 ;
        RECT  0 70.416 0.084 70.44 ;
    END
  END tap_d[500]
  PIN tap_d[501]
    DIRECTION OUTPUT ;
    USE SIGNAL ;
    PORT
      LAYER M4 ;
        RECT  0 70.512 0.084 70.536 ;
    END
  END tap_d[501]
  PIN tap_d[502]
    DIRECTION OUTPUT ;
    USE SIGNAL ;
    PORT
      LAYER M4 ;
        RECT  0 70.608 0.084 70.632 ;
    END
  END tap_d[502]
  PIN tap_d[503]
    DIRECTION OUTPUT ;
    USE SIGNAL ;
    PORT
      LAYER M4 ;
        RECT  0 70.704 0.084 70.728 ;
    END
  END tap_d[503]
  PIN tap_d[504]
    DIRECTION OUTPUT ;
    USE SIGNAL ;
    PORT
      LAYER M4 ;
        RECT  0 70.8 0.084 70.824 ;
    END
  END tap_d[504]
  PIN tap_d[505]
    DIRECTION OUTPUT ;
    USE SIGNAL ;
    PORT
      LAYER M4 ;
        RECT  0 70.896 0.084 70.92 ;
    END
  END tap_d[505]
  PIN tap_d[506]
    DIRECTION OUTPUT ;
    USE SIGNAL ;
    PORT
      LAYER M4 ;
        RECT  0 70.992 0.084 71.016 ;
    END
  END tap_d[506]
  PIN tap_d[507]
    DIRECTION OUTPUT ;
    USE SIGNAL ;
    PORT
      LAYER M4 ;
        RECT  0 71.088 0.084 71.112 ;
    END
  END tap_d[507]
  PIN tap_d[50]
    DIRECTION OUTPUT ;
    USE SIGNAL ;
    PORT
      LAYER M4 ;
        RECT  0 27.312 0.084 27.336 ;
    END
  END tap_d[50]
  PIN tap_d[51]
    DIRECTION OUTPUT ;
    USE SIGNAL ;
    PORT
      LAYER M4 ;
        RECT  0 27.408 0.084 27.432 ;
    END
  END tap_d[51]
  PIN tap_d[52]
    DIRECTION OUTPUT ;
    USE SIGNAL ;
    PORT
      LAYER M4 ;
        RECT  0 27.504 0.084 27.528 ;
    END
  END tap_d[52]
  PIN tap_d[53]
    DIRECTION OUTPUT ;
    USE SIGNAL ;
    PORT
      LAYER M4 ;
        RECT  0 27.6 0.084 27.624 ;
    END
  END tap_d[53]
  PIN tap_d[54]
    DIRECTION OUTPUT ;
    USE SIGNAL ;
    PORT
      LAYER M4 ;
        RECT  0 27.696 0.084 27.72 ;
    END
  END tap_d[54]
  PIN tap_d[55]
    DIRECTION OUTPUT ;
    USE SIGNAL ;
    PORT
      LAYER M4 ;
        RECT  0 27.792 0.084 27.816 ;
    END
  END tap_d[55]
  PIN tap_d[56]
    DIRECTION OUTPUT ;
    USE SIGNAL ;
    PORT
      LAYER M4 ;
        RECT  0 27.888 0.084 27.912 ;
    END
  END tap_d[56]
  PIN tap_d[57]
    DIRECTION OUTPUT ;
    USE SIGNAL ;
    PORT
      LAYER M4 ;
        RECT  0 27.984 0.084 28.008 ;
    END
  END tap_d[57]
  PIN tap_d[58]
    DIRECTION OUTPUT ;
    USE SIGNAL ;
    PORT
      LAYER M4 ;
        RECT  0 28.08 0.084 28.104 ;
    END
  END tap_d[58]
  PIN tap_d[59]
    DIRECTION OUTPUT ;
    USE SIGNAL ;
    PORT
      LAYER M4 ;
        RECT  0 28.176 0.084 28.2 ;
    END
  END tap_d[59]
  PIN tap_d[5]
    DIRECTION OUTPUT ;
    USE SIGNAL ;
    PORT
      LAYER M4 ;
        RECT  0 22.992 0.084 23.016 ;
    END
  END tap_d[5]
  PIN tap_d[60]
    DIRECTION OUTPUT ;
    USE SIGNAL ;
    PORT
      LAYER M4 ;
        RECT  0 28.272 0.084 28.296 ;
    END
  END tap_d[60]
  PIN tap_d[61]
    DIRECTION OUTPUT ;
    USE SIGNAL ;
    PORT
      LAYER M4 ;
        RECT  0 28.368 0.084 28.392 ;
    END
  END tap_d[61]
  PIN tap_d[62]
    DIRECTION OUTPUT ;
    USE SIGNAL ;
    PORT
      LAYER M4 ;
        RECT  0 28.464 0.084 28.488 ;
    END
  END tap_d[62]
  PIN tap_d[63]
    DIRECTION OUTPUT ;
    USE SIGNAL ;
    PORT
      LAYER M4 ;
        RECT  0 28.56 0.084 28.584 ;
    END
  END tap_d[63]
  PIN tap_d[64]
    DIRECTION OUTPUT ;
    USE SIGNAL ;
    PORT
      LAYER M4 ;
        RECT  0 28.656 0.084 28.68 ;
    END
  END tap_d[64]
  PIN tap_d[65]
    DIRECTION OUTPUT ;
    USE SIGNAL ;
    PORT
      LAYER M4 ;
        RECT  0 28.752 0.084 28.776 ;
    END
  END tap_d[65]
  PIN tap_d[66]
    DIRECTION OUTPUT ;
    USE SIGNAL ;
    PORT
      LAYER M4 ;
        RECT  0 28.8 0.084 28.824 ;
    END
  END tap_d[66]
  PIN tap_d[67]
    DIRECTION OUTPUT ;
    USE SIGNAL ;
    PORT
      LAYER M4 ;
        RECT  0 28.896 0.084 28.92 ;
    END
  END tap_d[67]
  PIN tap_d[68]
    DIRECTION OUTPUT ;
    USE SIGNAL ;
    PORT
      LAYER M4 ;
        RECT  0 28.992 0.084 29.016 ;
    END
  END tap_d[68]
  PIN tap_d[69]
    DIRECTION OUTPUT ;
    USE SIGNAL ;
    PORT
      LAYER M4 ;
        RECT  0 29.088 0.084 29.112 ;
    END
  END tap_d[69]
  PIN tap_d[6]
    DIRECTION OUTPUT ;
    USE SIGNAL ;
    PORT
      LAYER M4 ;
        RECT  0 23.088 0.084 23.112 ;
    END
  END tap_d[6]
  PIN tap_d[70]
    DIRECTION OUTPUT ;
    USE SIGNAL ;
    PORT
      LAYER M4 ;
        RECT  0 29.184 0.084 29.208 ;
    END
  END tap_d[70]
  PIN tap_d[71]
    DIRECTION OUTPUT ;
    USE SIGNAL ;
    PORT
      LAYER M4 ;
        RECT  0 29.28 0.084 29.304 ;
    END
  END tap_d[71]
  PIN tap_d[72]
    DIRECTION OUTPUT ;
    USE SIGNAL ;
    PORT
      LAYER M4 ;
        RECT  0 29.376 0.084 29.4 ;
    END
  END tap_d[72]
  PIN tap_d[73]
    DIRECTION OUTPUT ;
    USE SIGNAL ;
    PORT
      LAYER M4 ;
        RECT  0 29.472 0.084 29.496 ;
    END
  END tap_d[73]
  PIN tap_d[74]
    DIRECTION OUTPUT ;
    USE SIGNAL ;
    PORT
      LAYER M4 ;
        RECT  0 29.568 0.084 29.592 ;
    END
  END tap_d[74]
  PIN tap_d[75]
    DIRECTION OUTPUT ;
    USE SIGNAL ;
    PORT
      LAYER M4 ;
        RECT  0 29.664 0.084 29.688 ;
    END
  END tap_d[75]
  PIN tap_d[76]
    DIRECTION OUTPUT ;
    USE SIGNAL ;
    PORT
      LAYER M4 ;
        RECT  0 29.76 0.084 29.784 ;
    END
  END tap_d[76]
  PIN tap_d[77]
    DIRECTION OUTPUT ;
    USE SIGNAL ;
    PORT
      LAYER M4 ;
        RECT  0 29.856 0.084 29.88 ;
    END
  END tap_d[77]
  PIN tap_d[78]
    DIRECTION OUTPUT ;
    USE SIGNAL ;
    PORT
      LAYER M4 ;
        RECT  0 29.952 0.084 29.976 ;
    END
  END tap_d[78]
  PIN tap_d[79]
    DIRECTION OUTPUT ;
    USE SIGNAL ;
    PORT
      LAYER M4 ;
        RECT  0 30.048 0.084 30.072 ;
    END
  END tap_d[79]
  PIN tap_d[7]
    DIRECTION OUTPUT ;
    USE SIGNAL ;
    PORT
      LAYER M4 ;
        RECT  0 23.184 0.084 23.208 ;
    END
  END tap_d[7]
  PIN tap_d[80]
    DIRECTION OUTPUT ;
    USE SIGNAL ;
    PORT
      LAYER M4 ;
        RECT  0 30.144 0.084 30.168 ;
    END
  END tap_d[80]
  PIN tap_d[81]
    DIRECTION OUTPUT ;
    USE SIGNAL ;
    PORT
      LAYER M4 ;
        RECT  0 30.24 0.084 30.264 ;
    END
  END tap_d[81]
  PIN tap_d[82]
    DIRECTION OUTPUT ;
    USE SIGNAL ;
    PORT
      LAYER M4 ;
        RECT  0 30.336 0.084 30.36 ;
    END
  END tap_d[82]
  PIN tap_d[83]
    DIRECTION OUTPUT ;
    USE SIGNAL ;
    PORT
      LAYER M4 ;
        RECT  0 30.432 0.084 30.456 ;
    END
  END tap_d[83]
  PIN tap_d[84]
    DIRECTION OUTPUT ;
    USE SIGNAL ;
    PORT
      LAYER M4 ;
        RECT  0 30.528 0.084 30.552 ;
    END
  END tap_d[84]
  PIN tap_d[85]
    DIRECTION OUTPUT ;
    USE SIGNAL ;
    PORT
      LAYER M4 ;
        RECT  0 30.624 0.084 30.648 ;
    END
  END tap_d[85]
  PIN tap_d[86]
    DIRECTION OUTPUT ;
    USE SIGNAL ;
    PORT
      LAYER M4 ;
        RECT  0 30.72 0.084 30.744 ;
    END
  END tap_d[86]
  PIN tap_d[87]
    DIRECTION OUTPUT ;
    USE SIGNAL ;
    PORT
      LAYER M4 ;
        RECT  0 30.816 0.084 30.84 ;
    END
  END tap_d[87]
  PIN tap_d[88]
    DIRECTION OUTPUT ;
    USE SIGNAL ;
    PORT
      LAYER M4 ;
        RECT  0 30.912 0.084 30.936 ;
    END
  END tap_d[88]
  PIN tap_d[89]
    DIRECTION OUTPUT ;
    USE SIGNAL ;
    PORT
      LAYER M4 ;
        RECT  0 31.008 0.084 31.032 ;
    END
  END tap_d[89]
  PIN tap_d[8]
    DIRECTION OUTPUT ;
    USE SIGNAL ;
    PORT
      LAYER M4 ;
        RECT  0 23.28 0.084 23.304 ;
    END
  END tap_d[8]
  PIN tap_d[90]
    DIRECTION OUTPUT ;
    USE SIGNAL ;
    PORT
      LAYER M4 ;
        RECT  0 31.104 0.084 31.128 ;
    END
  END tap_d[90]
  PIN tap_d[91]
    DIRECTION OUTPUT ;
    USE SIGNAL ;
    PORT
      LAYER M4 ;
        RECT  0 31.2 0.084 31.224 ;
    END
  END tap_d[91]
  PIN tap_d[92]
    DIRECTION OUTPUT ;
    USE SIGNAL ;
    PORT
      LAYER M4 ;
        RECT  0 31.296 0.084 31.32 ;
    END
  END tap_d[92]
  PIN tap_d[93]
    DIRECTION OUTPUT ;
    USE SIGNAL ;
    PORT
      LAYER M4 ;
        RECT  0 31.392 0.084 31.416 ;
    END
  END tap_d[93]
  PIN tap_d[94]
    DIRECTION OUTPUT ;
    USE SIGNAL ;
    PORT
      LAYER M4 ;
        RECT  0 31.488 0.084 31.512 ;
    END
  END tap_d[94]
  PIN tap_d[95]
    DIRECTION OUTPUT ;
    USE SIGNAL ;
    PORT
      LAYER M4 ;
        RECT  0 31.584 0.084 31.608 ;
    END
  END tap_d[95]
  PIN tap_d[96]
    DIRECTION OUTPUT ;
    USE SIGNAL ;
    PORT
      LAYER M4 ;
        RECT  0 31.68 0.084 31.704 ;
    END
  END tap_d[96]
  PIN tap_d[97]
    DIRECTION OUTPUT ;
    USE SIGNAL ;
    PORT
      LAYER M4 ;
        RECT  0 31.776 0.084 31.8 ;
    END
  END tap_d[97]
  PIN tap_d[98]
    DIRECTION OUTPUT ;
    USE SIGNAL ;
    PORT
      LAYER M4 ;
        RECT  0 31.872 0.084 31.896 ;
    END
  END tap_d[98]
  PIN tap_d[99]
    DIRECTION OUTPUT ;
    USE SIGNAL ;
    PORT
      LAYER M4 ;
        RECT  0 31.968 0.084 31.992 ;
    END
  END tap_d[99]
  PIN tap_d[9]
    DIRECTION OUTPUT ;
    USE SIGNAL ;
    PORT
      LAYER M4 ;
        RECT  0 23.376 0.084 23.4 ;
    END
  END tap_d[9]
  PIN VDD
    DIRECTION INOUT ;
    USE POWER ;
    PORT
      LAYER M5 ;
        RECT  51.192 2.151 51.312 84.249 ;
        RECT  45.792 2.151 45.912 84.249 ;
        RECT  40.392 2.151 40.512 84.249 ;
        RECT  34.992 2.151 35.112 84.249 ;
        RECT  29.592 2.151 29.712 84.249 ;
        RECT  24.192 2.151 24.312 84.249 ;
        RECT  18.792 2.151 18.912 84.249 ;
        RECT  13.392 2.151 13.512 84.249 ;
        RECT  7.992 2.151 8.112 84.249 ;
        RECT  2.592 2.151 2.712 84.249 ;
    END
  END VDD
  PIN VSS
    DIRECTION INOUT ;
    USE GROUND ;
    PORT
      LAYER M5 ;
        RECT  51 2.137 51.12 84.263 ;
        RECT  45.6 2.137 45.72 84.263 ;
        RECT  40.2 2.137 40.32 84.263 ;
        RECT  34.8 2.137 34.92 84.263 ;
        RECT  29.4 2.137 29.52 84.263 ;
        RECT  24 2.137 24.12 84.263 ;
        RECT  18.6 2.137 18.72 84.263 ;
        RECT  13.2 2.137 13.32 84.263 ;
        RECT  7.8 2.137 7.92 84.263 ;
        RECT  2.4 2.137 2.52 84.263 ;
    END
  END VSS
  OBS
    LAYER RVTN ;
     RECT  2.16 2.16 54 2.295 ;
     RECT  2.16 2.565 54 2.835 ;
     RECT  2.16 3.105 54 3.375 ;
     RECT  2.16 3.645 54 3.915 ;
     RECT  2.16 4.185 54 4.455 ;
     RECT  2.16 4.725 54 4.995 ;
     RECT  2.16 5.265 54 5.535 ;
     RECT  2.16 5.805 54 6.075 ;
     RECT  2.16 6.345 54 6.615 ;
     RECT  2.16 6.885 54 7.155 ;
     RECT  2.16 7.425 54 7.695 ;
     RECT  2.16 7.965 54 8.235 ;
     RECT  2.16 8.505 54 8.775 ;
     RECT  2.16 9.045 54 9.315 ;
     RECT  2.16 9.585 54 9.855 ;
     RECT  2.16 10.125 54 10.395 ;
     RECT  2.16 10.665 54 10.935 ;
     RECT  2.16 11.205 54 11.475 ;
     RECT  2.16 11.745 54 12.015 ;
     RECT  2.16 12.285 54 12.555 ;
     RECT  2.16 12.825 54 13.095 ;
     RECT  2.16 13.365 54 13.635 ;
     RECT  2.16 13.905 54 14.175 ;
     RECT  2.16 14.445 54 14.715 ;
     RECT  2.16 14.985 54 15.255 ;
     RECT  2.16 15.525 54 15.795 ;
     RECT  2.16 16.065 54 16.335 ;
     RECT  2.16 16.605 54 16.875 ;
     RECT  2.16 17.145 54 17.415 ;
     RECT  2.16 17.685 54 17.955 ;
     RECT  2.16 18.225 54 18.495 ;
     RECT  2.16 18.765 54 19.035 ;
     RECT  2.16 19.305 54 19.575 ;
     RECT  2.16 19.845 54 20.115 ;
     RECT  2.16 20.385 54 20.655 ;
     RECT  2.16 20.925 54 21.195 ;
     RECT  2.16 21.465 54 21.735 ;
     RECT  2.16 22.005 54 22.275 ;
     RECT  2.16 22.545 54 22.815 ;
     RECT  2.16 23.085 54 23.355 ;
     RECT  2.16 23.625 54 23.895 ;
     RECT  2.16 24.165 54 24.435 ;
     RECT  2.16 24.705 54 24.975 ;
     RECT  2.16 25.245 54 25.515 ;
     RECT  2.16 25.785 54 26.055 ;
     RECT  2.16 26.325 54 26.595 ;
     RECT  2.16 26.865 54 27.135 ;
     RECT  2.16 27.405 54 27.675 ;
     RECT  2.16 27.945 54 28.215 ;
     RECT  2.16 28.485 54 28.755 ;
     RECT  2.16 29.025 54 29.295 ;
     RECT  2.16 29.565 54 29.835 ;
     RECT  2.16 30.105 54 30.375 ;
     RECT  2.16 30.645 54 30.915 ;
     RECT  2.16 31.185 54 31.455 ;
     RECT  2.16 31.725 54 31.995 ;
     RECT  2.16 32.265 54 32.535 ;
     RECT  2.16 32.805 54 33.075 ;
     RECT  2.16 33.345 54 33.615 ;
     RECT  2.16 33.885 54 34.155 ;
     RECT  2.16 34.425 54 34.695 ;
     RECT  2.16 34.965 54 35.235 ;
     RECT  2.16 35.505 54 35.775 ;
     RECT  2.16 36.045 54 36.315 ;
     RECT  2.16 36.585 54 36.855 ;
     RECT  2.16 37.125 54 37.395 ;
     RECT  2.16 37.665 54 37.935 ;
     RECT  2.16 38.205 54 38.475 ;
     RECT  2.16 38.745 54 39.015 ;
     RECT  2.16 39.285 54 39.555 ;
     RECT  2.16 39.825 54 40.095 ;
     RECT  2.16 40.365 54 40.635 ;
     RECT  2.16 40.905 54 41.175 ;
     RECT  2.16 41.445 54 41.715 ;
     RECT  2.16 41.985 54 42.255 ;
     RECT  2.16 42.525 54 42.795 ;
     RECT  2.16 43.065 54 43.335 ;
     RECT  2.16 43.605 54 43.875 ;
     RECT  2.16 44.145 54 44.415 ;
     RECT  2.16 44.685 54 44.955 ;
     RECT  2.16 45.225 54 45.495 ;
     RECT  2.16 45.765 54 46.035 ;
     RECT  2.16 46.305 54 46.575 ;
     RECT  2.16 46.845 54 47.115 ;
     RECT  2.16 47.385 54 47.655 ;
     RECT  2.16 47.925 54 48.195 ;
     RECT  2.16 48.465 54 48.735 ;
     RECT  2.16 49.005 54 49.275 ;
     RECT  2.16 49.545 54 49.815 ;
     RECT  2.16 50.085 54 50.355 ;
     RECT  2.16 50.625 54 50.895 ;
     RECT  2.16 51.165 54 51.435 ;
     RECT  2.16 51.705 54 51.975 ;
     RECT  2.16 52.245 54 52.515 ;
     RECT  2.16 52.785 54 53.055 ;
     RECT  2.16 53.325 54 53.595 ;
     RECT  2.16 53.865 54 54.135 ;
     RECT  2.16 54.405 54 54.675 ;
     RECT  2.16 54.945 54 55.215 ;
     RECT  2.16 55.485 54 55.755 ;
     RECT  2.16 56.025 54 56.295 ;
     RECT  2.16 56.565 54 56.835 ;
     RECT  2.16 57.105 54 57.375 ;
     RECT  2.16 57.645 54 57.915 ;
     RECT  2.16 58.185 54 58.455 ;
     RECT  2.16 58.725 54 58.995 ;
     RECT  2.16 59.265 54 59.535 ;
     RECT  2.16 59.805 54 60.075 ;
     RECT  2.16 60.345 54 60.615 ;
     RECT  2.16 60.885 54 61.155 ;
     RECT  2.16 61.425 54 61.695 ;
     RECT  2.16 61.965 54 62.235 ;
     RECT  2.16 62.505 54 62.775 ;
     RECT  2.16 63.045 54 63.315 ;
     RECT  2.16 63.585 54 63.855 ;
     RECT  2.16 64.125 54 64.395 ;
     RECT  2.16 64.665 54 64.935 ;
     RECT  2.16 65.205 54 65.475 ;
     RECT  2.16 65.745 54 66.015 ;
     RECT  2.16 66.285 54 66.555 ;
     RECT  2.16 66.825 54 67.095 ;
     RECT  2.16 67.365 54 67.635 ;
     RECT  2.16 67.905 54 68.175 ;
     RECT  2.16 68.445 54 68.715 ;
     RECT  2.16 68.985 54 69.255 ;
     RECT  2.16 69.525 54 69.795 ;
     RECT  2.16 70.065 54 70.335 ;
     RECT  2.16 70.605 54 70.875 ;
     RECT  2.16 71.145 54 71.415 ;
     RECT  2.16 71.685 54 71.955 ;
     RECT  2.16 72.225 54 72.495 ;
     RECT  2.16 72.765 54 73.035 ;
     RECT  2.16 73.305 54 73.575 ;
     RECT  2.16 73.845 54 74.115 ;
     RECT  2.16 74.385 54 74.655 ;
     RECT  2.16 74.925 54 75.195 ;
     RECT  2.16 75.465 54 75.735 ;
     RECT  2.16 76.005 54 76.275 ;
     RECT  2.16 76.545 54 76.815 ;
     RECT  2.16 77.085 54 77.355 ;
     RECT  2.16 77.625 54 77.895 ;
     RECT  2.16 78.165 54 78.435 ;
     RECT  2.16 78.705 54 78.975 ;
     RECT  2.16 79.245 54 79.515 ;
     RECT  2.16 79.785 54 80.055 ;
     RECT  2.16 80.325 54 80.595 ;
     RECT  2.16 80.865 54 81.135 ;
     RECT  2.16 81.405 54 81.675 ;
     RECT  2.16 81.945 54 82.215 ;
     RECT  2.16 82.485 54 82.755 ;
     RECT  2.16 83.025 54 83.295 ;
     RECT  2.16 83.565 54 83.835 ;
     RECT  2.16 84.105 54 84.24 ;
    LAYER RVTP ;
     RECT  2.16 2.295 54 2.565 ;
     RECT  2.16 2.835 54 3.105 ;
     RECT  2.16 3.375 54 3.645 ;
     RECT  2.16 3.915 54 4.185 ;
     RECT  2.16 4.455 54 4.725 ;
     RECT  2.16 4.995 54 5.265 ;
     RECT  2.16 5.535 54 5.805 ;
     RECT  2.16 6.075 54 6.345 ;
     RECT  2.16 6.615 54 6.885 ;
     RECT  2.16 7.155 54 7.425 ;
     RECT  2.16 7.695 54 7.965 ;
     RECT  2.16 8.235 54 8.505 ;
     RECT  2.16 8.775 54 9.045 ;
     RECT  2.16 9.315 54 9.585 ;
     RECT  2.16 9.855 54 10.125 ;
     RECT  2.16 10.395 54 10.665 ;
     RECT  2.16 10.935 54 11.205 ;
     RECT  2.16 11.475 54 11.745 ;
     RECT  2.16 12.015 54 12.285 ;
     RECT  2.16 12.555 54 12.825 ;
     RECT  2.16 13.095 54 13.365 ;
     RECT  2.16 13.635 54 13.905 ;
     RECT  2.16 14.175 54 14.445 ;
     RECT  2.16 14.715 54 14.985 ;
     RECT  2.16 15.255 54 15.525 ;
     RECT  2.16 15.795 54 16.065 ;
     RECT  2.16 16.335 54 16.605 ;
     RECT  2.16 16.875 54 17.145 ;
     RECT  2.16 17.415 54 17.685 ;
     RECT  2.16 17.955 54 18.225 ;
     RECT  2.16 18.495 54 18.765 ;
     RECT  2.16 19.035 54 19.305 ;
     RECT  2.16 19.575 54 19.845 ;
     RECT  2.16 20.115 54 20.385 ;
     RECT  2.16 20.655 54 20.925 ;
     RECT  2.16 21.195 54 21.465 ;
     RECT  2.16 21.735 54 22.005 ;
     RECT  2.16 22.275 54 22.545 ;
     RECT  2.16 22.815 54 23.085 ;
     RECT  2.16 23.355 54 23.625 ;
     RECT  2.16 23.895 54 24.165 ;
     RECT  2.16 24.435 54 24.705 ;
     RECT  2.16 24.975 54 25.245 ;
     RECT  2.16 25.515 54 25.785 ;
     RECT  2.16 26.055 54 26.325 ;
     RECT  2.16 26.595 54 26.865 ;
     RECT  2.16 27.135 54 27.405 ;
     RECT  2.16 27.675 54 27.945 ;
     RECT  2.16 28.215 54 28.485 ;
     RECT  2.16 28.755 54 29.025 ;
     RECT  2.16 29.295 54 29.565 ;
     RECT  2.16 29.835 54 30.105 ;
     RECT  2.16 30.375 54 30.645 ;
     RECT  2.16 30.915 54 31.185 ;
     RECT  2.16 31.455 54 31.725 ;
     RECT  2.16 31.995 54 32.265 ;
     RECT  2.16 32.535 54 32.805 ;
     RECT  2.16 33.075 54 33.345 ;
     RECT  2.16 33.615 54 33.885 ;
     RECT  2.16 34.155 54 34.425 ;
     RECT  2.16 34.695 54 34.965 ;
     RECT  2.16 35.235 54 35.505 ;
     RECT  2.16 35.775 54 36.045 ;
     RECT  2.16 36.315 54 36.585 ;
     RECT  2.16 36.855 54 37.125 ;
     RECT  2.16 37.395 54 37.665 ;
     RECT  2.16 37.935 54 38.205 ;
     RECT  2.16 38.475 54 38.745 ;
     RECT  2.16 39.015 54 39.285 ;
     RECT  2.16 39.555 54 39.825 ;
     RECT  2.16 40.095 54 40.365 ;
     RECT  2.16 40.635 54 40.905 ;
     RECT  2.16 41.175 54 41.445 ;
     RECT  2.16 41.715 54 41.985 ;
     RECT  2.16 42.255 54 42.525 ;
     RECT  2.16 42.795 54 43.065 ;
     RECT  2.16 43.335 54 43.605 ;
     RECT  2.16 43.875 54 44.145 ;
     RECT  2.16 44.415 54 44.685 ;
     RECT  2.16 44.955 54 45.225 ;
     RECT  2.16 45.495 54 45.765 ;
     RECT  2.16 46.035 54 46.305 ;
     RECT  2.16 46.575 54 46.845 ;
     RECT  2.16 47.115 54 47.385 ;
     RECT  2.16 47.655 54 47.925 ;
     RECT  2.16 48.195 54 48.465 ;
     RECT  2.16 48.735 54 49.005 ;
     RECT  2.16 49.275 54 49.545 ;
     RECT  2.16 49.815 54 50.085 ;
     RECT  2.16 50.355 54 50.625 ;
     RECT  2.16 50.895 54 51.165 ;
     RECT  2.16 51.435 54 51.705 ;
     RECT  2.16 51.975 54 52.245 ;
     RECT  2.16 52.515 54 52.785 ;
     RECT  2.16 53.055 54 53.325 ;
     RECT  2.16 53.595 54 53.865 ;
     RECT  2.16 54.135 54 54.405 ;
     RECT  2.16 54.675 54 54.945 ;
     RECT  2.16 55.215 54 55.485 ;
     RECT  2.16 55.755 54 56.025 ;
     RECT  2.16 56.295 54 56.565 ;
     RECT  2.16 56.835 54 57.105 ;
     RECT  2.16 57.375 54 57.645 ;
     RECT  2.16 57.915 54 58.185 ;
     RECT  2.16 58.455 54 58.725 ;
     RECT  2.16 58.995 54 59.265 ;
     RECT  2.16 59.535 54 59.805 ;
     RECT  2.16 60.075 54 60.345 ;
     RECT  2.16 60.615 54 60.885 ;
     RECT  2.16 61.155 54 61.425 ;
     RECT  2.16 61.695 54 61.965 ;
     RECT  2.16 62.235 54 62.505 ;
     RECT  2.16 62.775 54 63.045 ;
     RECT  2.16 63.315 54 63.585 ;
     RECT  2.16 63.855 54 64.125 ;
     RECT  2.16 64.395 54 64.665 ;
     RECT  2.16 64.935 54 65.205 ;
     RECT  2.16 65.475 54 65.745 ;
     RECT  2.16 66.015 54 66.285 ;
     RECT  2.16 66.555 54 66.825 ;
     RECT  2.16 67.095 54 67.365 ;
     RECT  2.16 67.635 54 67.905 ;
     RECT  2.16 68.175 54 68.445 ;
     RECT  2.16 68.715 54 68.985 ;
     RECT  2.16 69.255 54 69.525 ;
     RECT  2.16 69.795 54 70.065 ;
     RECT  2.16 70.335 54 70.605 ;
     RECT  2.16 70.875 54 71.145 ;
     RECT  2.16 71.415 54 71.685 ;
     RECT  2.16 71.955 54 72.225 ;
     RECT  2.16 72.495 54 72.765 ;
     RECT  2.16 73.035 54 73.305 ;
     RECT  2.16 73.575 54 73.845 ;
     RECT  2.16 74.115 54 74.385 ;
     RECT  2.16 74.655 54 74.925 ;
     RECT  2.16 75.195 54 75.465 ;
     RECT  2.16 75.735 54 76.005 ;
     RECT  2.16 76.275 54 76.545 ;
     RECT  2.16 76.815 54 77.085 ;
     RECT  2.16 77.355 54 77.625 ;
     RECT  2.16 77.895 54 78.165 ;
     RECT  2.16 78.435 54 78.705 ;
     RECT  2.16 78.975 54 79.245 ;
     RECT  2.16 79.515 54 79.785 ;
     RECT  2.16 80.055 54 80.325 ;
     RECT  2.16 80.595 54 80.865 ;
     RECT  2.16 81.135 54 81.405 ;
     RECT  2.16 81.675 54 81.945 ;
     RECT  2.16 82.215 54 82.485 ;
     RECT  2.16 82.755 54 83.025 ;
     RECT  2.16 83.295 54 83.565 ;
     RECT  2.16 83.835 54 84.105 ;
    LAYER M1 ;
     RECT  2.16 2.151 54 84.249 ;
    LAYER M2 ;
     RECT  0.031 18.81 0.067 18.828 ;
     RECT  0.031 75.816 0.067 75.834 ;
     RECT  0.067 23.436 0.103 23.454 ;
     RECT  0.067 75.474 0.103 75.834 ;
     RECT  0.103 28.836 0.139 28.854 ;
     RECT  0.103 49.671 0.139 49.689 ;
     RECT  0.103 50.598 0.139 51.696 ;
     RECT  0.103 64.602 0.139 64.854 ;
     RECT  0.103 68.922 0.139 69.246 ;
     RECT  0.103 70.038 0.139 70.056 ;
     RECT  0.031 74.556 0.139 74.574 ;
     RECT  0.103 75.474 0.139 76.068 ;
     RECT  0.067 18.468 0.167 18.828 ;
     RECT  0.103 23.256 0.167 23.454 ;
     RECT  0.103 48.132 0.175 48.564 ;
     RECT  0.139 49.626 0.175 49.689 ;
     RECT  0.103 60.894 0.175 61.452 ;
     RECT  0.139 74.556 0.175 76.068 ;
     RECT  0.167 23.256 0.203 23.346 ;
     RECT  0.103 32.391 0.203 32.409 ;
     RECT  0.103 34.74 0.203 34.758 ;
     RECT  0.103 35.748 0.203 37.044 ;
     RECT  0.103 40.806 0.203 41.778 ;
     RECT  0.103 45.306 0.203 45.45 ;
     RECT  0.103 46.278 0.203 46.719 ;
     RECT  0.175 48.132 0.203 49.689 ;
     RECT  0.139 50.526 0.203 51.696 ;
     RECT  0.103 54.684 0.203 56.124 ;
     RECT  0.103 57.312 0.203 57.33 ;
     RECT  0.139 64.602 0.203 64.962 ;
     RECT  0.103 67.644 0.203 67.662 ;
     RECT  0.139 68.922 0.203 70.056 ;
     RECT  0.139 28.26 0.239 28.854 ;
     RECT  0.203 50.526 0.239 50.544 ;
     RECT  0.203 51.678 0.239 51.696 ;
     RECT  0.203 68.922 0.239 69.984 ;
     RECT  0.203 54.756 0.275 55.512 ;
     RECT  0.175 74.511 0.311 76.068 ;
     RECT  0.175 60.894 0.347 61.992 ;
     RECT  0.391 66.906 0.427 66.924 ;
     RECT  0.103 58.662 0.463 58.68 ;
     RECT  0.203 64.836 0.463 64.962 ;
     RECT  0.355 65.754 0.463 65.772 ;
     RECT  0.203 36.36 0.535 37.044 ;
     RECT  0.499 38.646 0.535 38.664 ;
     RECT  0.463 39.834 0.535 39.852 ;
     RECT  0.499 41.886 0.535 42.174 ;
     RECT  0.463 58.662 0.535 58.716 ;
     RECT  0.347 61.362 0.535 61.992 ;
     RECT  0.391 63.054 0.535 63.072 ;
     RECT  0.103 63.828 0.535 63.846 ;
     RECT  0.463 64.836 0.535 65.772 ;
     RECT  0.427 66.6 0.535 66.924 ;
     RECT  0.239 68.922 0.535 69.246 ;
     RECT  0.175 71.388 0.571 71.406 ;
     RECT  0.499 56.502 0.599 56.592 ;
     RECT  0.535 58.662 0.607 59.904 ;
     RECT  0.535 61.362 0.635 63.846 ;
     RECT  0.607 58.158 0.707 59.904 ;
     RECT  0.167 18.468 0.859 18.486 ;
     RECT  0.679 0.072 0.967 0.09 ;
     RECT  0.031 13.446 1.003 13.464 ;
     RECT  0.823 14.346 1.003 14.364 ;
     RECT  0.535 64.836 1.175 66.924 ;
     RECT  0.967 0.036 1.219 0.09 ;
     RECT  1.219 16.506 1.435 16.524 ;
     RECT  0.859 17.766 1.651 18.486 ;
     RECT  0.103 30.348 1.723 30.366 ;
     RECT  1.219 0.036 1.867 0.126 ;
     RECT  0.103 20.934 1.867 20.952 ;
     RECT  1.399 10.476 1.975 10.494 ;
     RECT  0.787 11.376 1.975 11.394 ;
     RECT  0.535 26.766 2.047 26.784 ;
     RECT  1.147 27.684 2.047 27.702 ;
     RECT  1.651 17.766 2.083 18.792 ;
     RECT  1.975 10.476 2.16 11.394 ;
     RECT  1.003 13.446 2.16 14.364 ;
     RECT  1.435 16.146 2.16 16.524 ;
     RECT  2.083 17.496 2.16 18.792 ;
     RECT  1.867 20.934 2.16 21.024 ;
     RECT  1.543 22.014 2.16 22.032 ;
     RECT  0.203 23.328 2.16 23.346 ;
     RECT  0.535 25.596 2.16 25.614 ;
     RECT  2.047 26.766 2.16 27.702 ;
     RECT  0.239 28.836 2.16 28.854 ;
     RECT  1.723 30.348 2.16 30.906 ;
     RECT  0.103 33.246 2.16 33.264 ;
     RECT  0.535 35.208 2.16 35.226 ;
     RECT  0.535 36.36 2.16 37.422 ;
     RECT  0.535 38.484 2.16 39.888 ;
     RECT  0.203 40.806 2.16 40.824 ;
     RECT  0.535 41.886 2.16 43.164 ;
     RECT  0.535 44.424 2.16 44.442 ;
     RECT  0.203 49.014 2.16 49.644 ;
     RECT  0.275 55.494 2.16 55.512 ;
     RECT  0.599 56.574 2.16 56.592 ;
     RECT  0.707 58.662 2.16 59.904 ;
     RECT  0.635 61.434 2.16 63.846 ;
     RECT  1.175 64.836 2.16 66.852 ;
     RECT  0.535 67.716 2.16 69.246 ;
     RECT  0.571 71.154 2.16 71.406 ;
     RECT  0.311 75.006 2.16 76.068 ;
     RECT  3.127 85.5 5.071 85.518 ;
     RECT  5.071 85.5 5.423 85.599 ;
     RECT  5.423 85.581 5.639 85.599 ;
     RECT  6.331 86.346 6.467 86.364 ;
     RECT  7.195 86.346 7.295 86.364 ;
     RECT  2.16 2.151 7.771 84.249 ;
     RECT  1.867 0.036 7.843 0.162 ;
     RECT  7.771 2.151 7.871 84.33 ;
     RECT  7.843 0.036 7.979 0.198 ;
     RECT  8.995 86.346 9.671 86.364 ;
     RECT  7.979 0.036 11.155 0.162 ;
     RECT  11.047 86.238 11.183 86.256 ;
     RECT  11.155 0.036 11.291 0.504 ;
     RECT  11.911 86.274 12.047 86.292 ;
     RECT  12.415 86.346 12.551 86.364 ;
     RECT  7.871 2.151 13.171 84.249 ;
     RECT  13.171 2.07 13.343 84.249 ;
     RECT  13.603 86.346 13.703 86.364 ;
     RECT  11.291 0.036 14.827 0.162 ;
     RECT  14.827 0.036 14.927 0.198 ;
     RECT  16.375 86.274 16.475 86.292 ;
     RECT  14.927 0.072 16.951 0.198 ;
     RECT  16.951 0.072 17.087 0.549 ;
     RECT  13.343 2.151 18.571 84.249 ;
     RECT  18.571 2.151 18.743 84.33 ;
     RECT  17.087 0.072 18.895 0.198 ;
     RECT  18.895 0.072 18.931 0.279 ;
     RECT  18.931 0.036 19.211 0.279 ;
     RECT  19.211 0.108 20.263 0.279 ;
     RECT  20.263 0.036 21.371 0.279 ;
     RECT  21.371 0.036 22.855 0.162 ;
     RECT  22.855 0.036 22.891 0.279 ;
     RECT  22.891 0.036 22.963 0.324 ;
     RECT  22.963 0.036 23.035 0.396 ;
     RECT  18.743 2.151 23.971 84.249 ;
     RECT  23.971 2.151 24.107 84.33 ;
     RECT  23.035 0.036 25.547 0.468 ;
     RECT  25.547 0.108 25.843 0.468 ;
     RECT  25.843 0.108 25.979 0.549 ;
     RECT  25.771 86.346 26.015 86.364 ;
     RECT  25.979 0.108 26.519 0.468 ;
     RECT  26.519 0.18 26.779 0.468 ;
     RECT  26.779 0.18 27.499 0.549 ;
     RECT  27.499 0.108 27.535 0.549 ;
     RECT  27.535 0.036 27.671 0.549 ;
     RECT  27.679 84.996 27.815 85.014 ;
     RECT  27.671 0.108 28.723 0.549 ;
     RECT  24.107 2.151 29.299 84.249 ;
     RECT  29.299 2.151 29.435 84.33 ;
     RECT  28.723 0.036 30.695 0.549 ;
     RECT  30.695 0.036 30.803 0.324 ;
     RECT  30.803 0.072 30.875 0.324 ;
     RECT  30.875 0.144 33.367 0.324 ;
     RECT  33.367 0.036 34.771 0.324 ;
     RECT  34.771 0.036 36.563 0.396 ;
     RECT  37.111 85.581 37.319 85.599 ;
     RECT  36.563 0.108 38.551 0.396 ;
     RECT  38.551 0.072 38.579 0.396 ;
     RECT  38.579 0.072 38.623 0.324 ;
     RECT  29.435 2.151 40.135 84.249 ;
     RECT  40.135 2.151 40.307 84.33 ;
     RECT  38.623 0.036 40.531 0.324 ;
     RECT  40.531 0.036 40.667 0.504 ;
     RECT  40.307 2.151 43.699 84.249 ;
     RECT  43.699 2.151 44.887 84.294 ;
     RECT  44.887 2.151 45.023 84.33 ;
     RECT  40.667 0.036 45.779 0.396 ;
     RECT  45.643 86.346 45.779 86.364 ;
     RECT  45.779 0.108 45.815 0.396 ;
     RECT  45.815 0.261 47.335 0.396 ;
     RECT  45.023 2.151 47.335 84.249 ;
     RECT  47.335 0.036 47.435 0.396 ;
     RECT  47.335 2.151 47.687 84.438 ;
     RECT  47.687 2.151 47.875 84.249 ;
     RECT  47.875 1.692 48.011 84.249 ;
     RECT  48.199 85.581 48.299 85.599 ;
     RECT  47.435 0.072 48.667 0.396 ;
     RECT  48.667 0.036 49.415 0.396 ;
     RECT  48.011 2.151 49.963 84.249 ;
     RECT  49.415 0.036 50.639 0.324 ;
     RECT  50.639 0.036 50.747 0.279 ;
     RECT  49.963 2.151 50.755 84.438 ;
     RECT  50.747 0.036 51.251 0.126 ;
     RECT  50.755 2.151 51.431 84.942 ;
     RECT  51.331 86.346 51.431 86.364 ;
     RECT  51.251 0.036 51.647 0.054 ;
     RECT  53.275 0.036 53.375 0.054 ;
     RECT  53.455 86.346 53.555 86.364 ;
     RECT  51.431 2.151 54 84.249 ;
     RECT  54 67.878 54.059 72.216 ;
     RECT  54 81.486 54.131 81.504 ;
     RECT  54 82.836 54.131 82.854 ;
     RECT  54 78.066 54.203 78.66 ;
     RECT  54 73.278 54.239 73.296 ;
     RECT  54 66.096 54.347 66.546 ;
     RECT  54 57.888 54.419 58.68 ;
     RECT  54 76.626 54.419 76.644 ;
     RECT  54.059 67.878 54.455 71.676 ;
     RECT  54 75.006 54.491 75.024 ;
     RECT  54.455 69.498 54.527 71.676 ;
     RECT  54.455 67.878 54.635 68.544 ;
     RECT  54.203 78.642 54.635 78.66 ;
     RECT  54.635 67.878 54.707 67.968 ;
     RECT  54.707 67.95 54.815 67.968 ;
     RECT  54.527 69.498 54.851 71.244 ;
     RECT  54 60.12 54.923 60.138 ;
     RECT  54 63.558 54.995 63.576 ;
     RECT  54.347 66.096 55.031 66.114 ;
     RECT  54 61.668 55.103 62.298 ;
     RECT  54.419 57.888 55.211 58.14 ;
     RECT  54 64.746 55.211 64.764 ;
     RECT  54.851 69.498 55.247 70.668 ;
     RECT  55.103 61.668 55.283 61.686 ;
     RECT  55.247 69.498 55.391 69.984 ;
     RECT  55.391 69.498 55.463 69.516 ;
     RECT  54 54.99 55.499 55.008 ;
     RECT  55.211 57.888 55.643 57.906 ;
    LAYER M3 ;
     RECT  5.796 0.012 55.494 0.091 ;
     RECT  0.684 0.012 2.574 0.095 ;
     RECT  0.972 0.095 2.574 0.125 ;
     RECT  1.224 0.125 1.89 0.131 ;
     RECT  1.872 0.131 1.89 0.167 ;
     RECT  5.796 0.091 55.638 0.401 ;
     RECT  5.796 0.401 34.65 2.143 ;
     RECT  35.388 0.401 55.638 2.143 ;
     RECT  2.415 2.143 2.505 2.413 ;
     RECT  5.796 2.143 55.638 2.827 ;
     RECT  5.148 2.827 55.638 3.931 ;
     RECT  4.68 3.931 55.638 6.811 ;
     RECT  2.415 2.413 2.697 10.201 ;
     RECT  1.404 10.471 1.422 10.741 ;
     RECT  2.376 10.201 3.33 10.741 ;
     RECT  1.404 10.741 3.33 10.859 ;
     RECT  1.404 10.859 3.078 11.371 ;
     RECT  0.792 11.371 3.078 12.091 ;
     RECT  4.608 6.811 55.638 12.515 ;
     RECT  0.792 12.091 3.33 12.721 ;
     RECT  0.792 12.721 3.51 13.171 ;
     RECT  0.792 13.171 4.014 13.711 ;
     RECT  0.792 13.711 4.302 13.829 ;
     RECT  5.148 12.515 55.638 14.135 ;
     RECT  5.364 14.135 55.638 14.207 ;
     RECT  0.792 13.829 4.014 14.791 ;
     RECT  0.792 14.791 4.374 15.061 ;
     RECT  0.792 15.061 4.41 15.421 ;
     RECT  0.792 15.421 4.698 15.557 ;
     RECT  0.792 15.557 4.59 16.411 ;
     RECT  5.796 14.207 55.638 16.411 ;
     RECT  0.792 16.411 4.662 16.681 ;
     RECT  5.436 16.411 55.638 16.681 ;
     RECT  0.792 16.681 55.638 16.871 ;
     RECT  0.792 16.871 5.166 17.923 ;
     RECT  5.976 16.871 55.638 17.923 ;
     RECT  0.792 17.923 55.638 18.419 ;
     RECT  0.036 13.441 0.054 18.463 ;
     RECT  0.792 18.419 4.626 18.463 ;
     RECT  0.036 18.463 4.626 18.833 ;
     RECT  0.072 18.833 4.626 19.345 ;
     RECT  5.364 18.419 55.638 19.345 ;
     RECT  0.072 19.345 55.638 23.459 ;
     RECT  0.108 23.459 55.638 23.891 ;
     RECT  0.108 23.891 10.458 24.077 ;
     RECT  0.144 24.077 10.458 25.411 ;
     RECT  11.196 23.891 55.638 25.411 ;
     RECT  0.144 25.411 55.638 25.771 ;
     RECT  0.108 25.771 55.638 25.817 ;
     RECT  10.836 25.817 55.638 26.051 ;
     RECT  11.196 26.051 55.638 26.941 ;
     RECT  0.108 25.817 9.954 27.139 ;
     RECT  0.108 27.139 9.99 27.301 ;
     RECT  10.872 26.941 55.638 27.337 ;
     RECT  0.108 27.301 10.026 28.859 ;
     RECT  0.144 28.859 10.026 30.181 ;
     RECT  0.144 30.181 10.098 30.343 ;
     RECT  0.108 30.343 10.098 30.451 ;
     RECT  10.836 27.337 55.638 30.451 ;
     RECT  0.108 30.451 55.638 30.845 ;
     RECT  0.144 30.845 55.638 31.955 ;
     RECT  0.144 31.955 14.562 32.261 ;
     RECT  0.144 32.261 14.382 32.342 ;
     RECT  0.144 32.342 14.346 32.38 ;
     RECT  0.108 32.38 14.346 32.495 ;
     RECT  15.408 31.955 55.638 32.495 ;
     RECT  15.588 32.495 55.638 33.179 ;
     RECT  0.108 32.495 14.022 33.725 ;
     RECT  0.792 33.725 14.022 33.961 ;
     RECT  15.624 33.179 55.638 34.259 ;
     RECT  0.792 33.961 14.058 34.321 ;
     RECT  0.792 34.321 14.67 34.501 ;
     RECT  15.624 34.259 16.398 34.501 ;
     RECT  0.792 34.501 16.398 34.555 ;
     RECT  17.748 34.259 55.638 34.619 ;
     RECT  0.324 34.555 16.398 34.735 ;
     RECT  0.108 34.735 16.398 34.877 ;
     RECT  0.18 34.877 16.398 34.925 ;
     RECT  0.324 34.925 16.398 35.74 ;
     RECT  0.108 35.74 16.398 36.121 ;
     RECT  0.108 36.121 16.794 36.823 ;
     RECT  0.108 36.823 17.046 36.895 ;
     RECT  0.108 36.895 17.154 37.181 ;
     RECT  0.54 37.181 17.154 37.201 ;
     RECT  17.928 34.619 55.638 37.201 ;
     RECT  0.54 37.201 55.638 37.757 ;
     RECT  0.792 37.757 55.638 38.003 ;
     RECT  21.204 38.003 55.638 38.129 ;
     RECT  21.276 38.129 55.638 38.399 ;
     RECT  0.792 38.003 20.466 38.479 ;
     RECT  0.54 38.479 20.466 38.641 ;
     RECT  21.348 38.399 55.638 38.849 ;
     RECT  0.504 38.641 20.466 39.499 ;
     RECT  21.348 38.849 21.366 39.721 ;
     RECT  22.248 38.849 55.638 39.721 ;
     RECT  0.18 39.499 20.466 40.075 ;
     RECT  21.348 39.721 55.638 40.163 ;
     RECT  0.144 40.075 20.466 40.261 ;
     RECT  21.348 40.163 43.686 40.261 ;
     RECT  0.144 40.261 43.686 40.801 ;
     RECT  0.108 40.801 43.686 41.885 ;
     RECT  0.144 41.885 43.686 42.653 ;
     RECT  0.54 42.653 43.686 43.963 ;
     RECT  0.324 43.963 43.686 44.443 ;
     RECT  44.496 40.163 55.638 44.443 ;
     RECT  0.324 44.443 55.638 44.539 ;
     RECT  0.144 44.539 55.638 45.301 ;
     RECT  0.108 45.301 55.638 45.455 ;
     RECT  0.144 45.455 55.638 46.264 ;
     RECT  0.108 46.264 55.638 46.724 ;
     RECT  0.144 46.724 55.638 48.124 ;
     RECT  0.108 48.124 55.638 48.572 ;
     RECT  0.144 48.572 55.638 48.701 ;
     RECT  0.18 48.701 55.638 49.621 ;
     RECT  0.144 49.621 55.638 49.66 ;
     RECT  0.108 49.66 55.638 51.701 ;
     RECT  0.144 51.701 55.638 54.329 ;
     RECT  0.144 54.329 24.894 54.679 ;
     RECT  0.108 54.679 24.894 56.101 ;
     RECT  25.632 54.329 55.638 56.101 ;
     RECT  0.108 56.101 55.638 56.381 ;
     RECT  0.108 56.381 24.894 56.429 ;
     RECT  25.632 56.381 55.638 56.759 ;
     RECT  0.144 56.429 24.894 57.292 ;
     RECT  0.108 57.292 24.894 57.485 ;
     RECT  25.74 56.759 55.638 57.911 ;
     RECT  0.504 57.485 24.894 58.459 ;
     RECT  0.144 58.459 24.894 58.657 ;
     RECT  0.108 58.657 24.894 58.733 ;
     RECT  0.18 58.733 24.894 58.781 ;
     RECT  0.468 58.781 24.894 59.021 ;
     RECT  0.54 59.021 24.894 59.071 ;
     RECT  0.54 59.071 24.93 59.611 ;
     RECT  25.74 57.911 55.278 59.611 ;
     RECT  0.54 59.611 55.278 59.947 ;
     RECT  0.324 59.947 55.278 60.427 ;
     RECT  0.144 60.427 55.278 60.811 ;
     RECT  0.108 60.811 55.278 61.691 ;
     RECT  0.108 61.691 55.098 61.997 ;
     RECT  0.18 61.997 55.098 62.189 ;
     RECT  0.54 62.189 55.098 62.303 ;
     RECT  0.54 62.303 54.99 62.971 ;
     RECT  0.144 62.971 54.99 63.581 ;
     RECT  0.144 63.581 54.81 63.823 ;
     RECT  0.108 63.823 54.81 64.741 ;
     RECT  0.108 64.741 55.206 65.069 ;
     RECT  0.144 65.069 55.206 65.165 ;
     RECT  0.36 65.165 55.206 65.899 ;
     RECT  0.324 65.899 55.206 66.029 ;
     RECT  0.36 66.029 55.206 67.291 ;
     RECT  0.144 67.291 55.206 67.639 ;
     RECT  0.108 67.639 55.206 67.757 ;
     RECT  0.54 67.757 55.206 68.917 ;
     RECT  0.108 68.917 55.206 69.493 ;
     RECT  0.108 69.493 55.458 71.179 ;
     RECT  0.072 71.179 55.458 73.301 ;
     RECT  0.072 73.301 53.694 74.551 ;
     RECT  0.036 74.551 53.694 75.199 ;
     RECT  54.432 73.301 55.458 75.199 ;
     RECT  0.036 75.199 55.458 75.839 ;
     RECT  0.108 75.839 55.458 76.073 ;
     RECT  0.576 76.073 55.458 86.381 ;
    LAYER M4 ;
     RECT  0.06 22.512 0.061 71.112 ;
     RECT  0.133 74.64 0.245 74.664 ;
     RECT  0.061 22.512 0.332 71.208 ;
     RECT  0.332 22.512 0.419 71.304 ;
     RECT  0.917 0.096 1.001 0.12 ;
     RECT  1.093 14.736 1.333 14.76 ;
     RECT  1.765 19.872 1.957 19.896 ;
     RECT  0.419 22.512 2.149 71.16 ;
     RECT  1.333 14.736 2.365 15.336 ;
     RECT  1.957 19.824 2.365 19.896 ;
     RECT  2.293 20.88 2.365 20.904 ;
     RECT  0.901 13.632 2.408 13.656 ;
     RECT  2.365 14.736 2.408 16.056 ;
     RECT  1.525 17.616 2.408 17.64 ;
     RECT  2.365 19.824 2.408 20.904 ;
     RECT  2.149 22.032 2.408 71.16 ;
     RECT  0.661 86.256 2.509 86.28 ;
     RECT  2.408 2.148 2.512 84.252 ;
     RECT  2.512 2.418 2.677 84.252 ;
     RECT  2.677 2.418 2.704 84.36 ;
     RECT  2.509 86.016 2.725 86.28 ;
     RECT  2.704 12.912 2.765 64.968 ;
     RECT  2.704 83.76 2.765 84.36 ;
     RECT  2.725 85.92 2.819 86.28 ;
     RECT  2.819 86.016 2.867 86.28 ;
     RECT  2.765 83.76 2.873 83.784 ;
     RECT  2.765 14.256 3.017 64.968 ;
     RECT  3.017 17.664 3.025 64.968 ;
     RECT  2.545 0.096 3.155 0.12 ;
     RECT  2.765 12.912 3.341 12.936 ;
     RECT  3.017 14.256 3.395 16.536 ;
     RECT  3.395 14.256 3.485 15.336 ;
     RECT  3.025 17.664 3.593 62.136 ;
     RECT  3.593 21.6 3.629 62.136 ;
     RECT  3.395 16.368 3.731 16.536 ;
     RECT  3.485 15.312 3.737 15.336 ;
     RECT  3.836 82.08 3.923 82.104 ;
     RECT  3.731 16.512 4.061 16.536 ;
     RECT  3.025 63.504 4.237 64.968 ;
     RECT  2.704 66.096 4.237 67.992 ;
     RECT  3.629 21.6 4.277 25.08 ;
     RECT  4.277 21.6 4.313 22.632 ;
     RECT  4.117 84.912 4.313 84.936 ;
     RECT  2.867 86.256 4.421 86.28 ;
     RECT  3.629 26.256 4.493 62.136 ;
     RECT  4.493 44.064 4.529 62.136 ;
     RECT  4.313 21.6 4.565 22.536 ;
     RECT  3.593 17.664 4.601 20.328 ;
     RECT  4.277 23.76 4.601 25.08 ;
     RECT  4.601 17.664 4.637 19.368 ;
     RECT  4.637 18.192 4.709 19.368 ;
     RECT  4.601 23.76 4.709 25.032 ;
     RECT  4.565 21.6 4.741 21.672 ;
     RECT  4.493 26.256 4.777 42.888 ;
     RECT  4.453 83.808 4.885 83.832 ;
     RECT  4.885 83.232 4.979 83.832 ;
     RECT  4.709 23.76 4.997 24.792 ;
     RECT  4.529 44.16 5.069 62.136 ;
     RECT  4.777 26.208 5.177 42.888 ;
     RECT  4.979 83.808 5.219 83.832 ;
     RECT  4.997 23.76 5.317 23.88 ;
     RECT  4.709 18.672 5.393 19.368 ;
     RECT  4.7 85.488 5.501 85.512 ;
     RECT  4.741 20.976 5.533 21.672 ;
     RECT  5.393 18.672 5.645 18.696 ;
     RECT  5.177 26.208 5.677 42.744 ;
     RECT  5.533 20.976 5.699 21.72 ;
     RECT  5.677 25.968 5.717 42.744 ;
     RECT  5.717 25.968 5.753 42.552 ;
     RECT  5.699 20.976 5.789 21 ;
     RECT  5.753 25.968 5.797 36.36 ;
     RECT  5.797 82.032 5.933 82.056 ;
     RECT  4.669 3.936 5.939 3.96 ;
     RECT  4.237 63.504 5.939 67.992 ;
     RECT  5.317 23.52 5.965 23.88 ;
     RECT  5.965 23.424 6.037 23.88 ;
     RECT  5.069 44.16 6.041 62.04 ;
     RECT  6.037 22.752 6.073 23.88 ;
     RECT  4.597 6.816 6.131 6.84 ;
     RECT  5.753 37.488 6.149 38.76 ;
     RECT  6.073 22.176 6.275 23.88 ;
     RECT  6.145 80.4 6.275 80.424 ;
     RECT  5.137 2.832 6.323 2.856 ;
     RECT  6.275 22.752 6.401 23.88 ;
     RECT  6.253 7.392 6.515 7.416 ;
     RECT  6.001 1.056 6.541 1.08 ;
     RECT  5.797 25.152 6.545 36.36 ;
     RECT  6.421 83.76 6.545 83.784 ;
     RECT  6.541 1.056 6.613 1.128 ;
     RECT  6.401 23.424 6.661 23.88 ;
     RECT  6.545 25.152 6.661 29.832 ;
     RECT  5.753 39.792 6.764 42.552 ;
     RECT  6.764 39.792 6.829 42.792 ;
     RECT  6.041 44.16 6.829 59.304 ;
     RECT  6.853 84.912 6.94 84.936 ;
     RECT  6.613 0.528 7.09 1.128 ;
     RECT  6.149 37.92 7.225 38.76 ;
     RECT  6.829 39.792 7.225 59.304 ;
     RECT  6.037 86.256 7.441 86.28 ;
     RECT  6.545 30.816 7.585 36.36 ;
     RECT  7.225 37.92 7.585 59.304 ;
     RECT  7.585 3.408 7.693 3.432 ;
     RECT  6.661 23.424 7.693 29.832 ;
     RECT  7.585 30.816 7.693 59.304 ;
     RECT  7.693 3.408 7.808 3.96 ;
     RECT  7.397 11.424 7.808 11.448 ;
     RECT  7.081 18.192 7.808 18.216 ;
     RECT  7.693 23.424 7.808 59.304 ;
     RECT  6.041 60.624 7.808 62.04 ;
     RECT  5.939 63.504 7.808 64.968 ;
     RECT  5.939 66.576 7.808 67.992 ;
     RECT  2.704 69.744 7.808 71.16 ;
     RECT  7.253 82.608 7.808 82.632 ;
     RECT  7.09 0.48 7.837 1.128 ;
     RECT  7.837 0.144 7.859 1.128 ;
     RECT  7.808 2.148 7.912 84.252 ;
     RECT  7.912 2.148 8.104 83.982 ;
     RECT  8.104 2.148 8.161 2.28 ;
     RECT  7.859 0.144 8.197 0.552 ;
     RECT  7.441 85.488 8.201 86.28 ;
     RECT  8.197 0.096 8.339 0.552 ;
     RECT  8.104 3.408 8.339 3.96 ;
     RECT  8.104 28.368 8.381 29.496 ;
     RECT  8.104 30.576 8.417 38.76 ;
     RECT  8.104 77.472 8.417 77.496 ;
     RECT  8.104 80.928 8.627 80.952 ;
     RECT  8.104 26.352 8.771 27.192 ;
     RECT  8.417 30.96 8.777 38.76 ;
     RECT  8.381 28.368 8.812 28.392 ;
     RECT  8.161 1.68 8.819 2.28 ;
     RECT  8.771 26.352 8.921 26.76 ;
     RECT  8.104 23.856 9.011 23.976 ;
     RECT  8.921 26.352 9.029 26.376 ;
     RECT  8.381 29.472 9.029 29.496 ;
     RECT  8.104 39.744 9.065 43.128 ;
     RECT  8.339 3.408 9.203 3.432 ;
     RECT  8.777 31.152 9.241 38.76 ;
     RECT  9.065 39.744 9.241 39.864 ;
     RECT  9.065 40.848 9.281 43.128 ;
     RECT  8.819 1.68 9.385 1.704 ;
     RECT  9.281 40.896 9.389 43.128 ;
     RECT  9.241 23.376 9.395 23.4 ;
     RECT  8.201 86.256 9.493 86.28 ;
     RECT  8.339 0.528 9.565 0.552 ;
     RECT  9.457 20.544 9.587 20.568 ;
     RECT  9.389 40.944 9.821 43.128 ;
     RECT  9.853 20.496 9.971 20.52 ;
     RECT  9.241 31.152 10.217 39.864 ;
     RECT  10.217 31.392 10.253 39.864 ;
     RECT  9.565 0.48 10.277 0.552 ;
     RECT  10.277 0.096 10.285 0.552 ;
     RECT  9.385 1.632 10.285 1.704 ;
     RECT  9.493 85.488 10.325 86.28 ;
     RECT  10.285 0.096 10.361 1.704 ;
     RECT  10.357 84.384 10.547 84.408 ;
     RECT  9.821 41.184 10.645 43.128 ;
     RECT  8.104 44.16 10.645 58.824 ;
     RECT  10.253 32.256 10.649 39.864 ;
     RECT  10.321 23.952 10.739 23.976 ;
     RECT  10.609 81.504 10.739 81.528 ;
     RECT  10.649 32.496 10.825 39.864 ;
     RECT  10.645 41.184 10.825 58.824 ;
     RECT  10.825 32.496 10.901 58.824 ;
     RECT  10.901 32.496 10.937 42.264 ;
     RECT  10.937 32.496 10.973 35.4 ;
     RECT  10.973 33.12 11.153 35.4 ;
     RECT  10.937 36.432 11.153 42.264 ;
     RECT  10.325 86.208 11.189 86.28 ;
     RECT  10.361 0.48 11.221 1.704 ;
     RECT  11.125 83.184 11.225 83.208 ;
     RECT  11.221 0.48 11.297 2.28 ;
     RECT  10.861 6.24 11.363 6.264 ;
     RECT  11.297 1.104 11.437 2.28 ;
     RECT  11.153 33.12 11.513 35.352 ;
     RECT  11.516 84.96 11.603 84.984 ;
     RECT  11.437 1.104 11.747 2.856 ;
     RECT  11.153 36.624 11.977 42.264 ;
     RECT  10.901 43.536 11.977 58.824 ;
     RECT  11.989 84.912 12.089 84.936 ;
     RECT  11.747 1.104 12.265 2.28 ;
     RECT  11.189 86.256 12.401 86.28 ;
     RECT  12.265 0.48 12.445 2.28 ;
     RECT  12.445 0.096 12.707 2.28 ;
     RECT  12.401 86.208 12.769 86.28 ;
     RECT  11.977 36.624 12.841 58.824 ;
     RECT  12.769 85.488 12.899 86.28 ;
     RECT  12.841 36.528 12.985 58.824 ;
     RECT  11.513 33.12 13.057 35.304 ;
     RECT  12.985 36.336 13.057 58.824 ;
     RECT  12.985 84.384 13.091 84.408 ;
     RECT  12.707 1.632 13.208 2.28 ;
     RECT  11.509 5.088 13.208 5.112 ;
     RECT  12.805 6.24 13.208 6.264 ;
     RECT  12.985 28.512 13.208 28.536 ;
     RECT  13.057 33.12 13.208 58.824 ;
     RECT  8.104 60.624 13.208 62.04 ;
     RECT  8.104 63.504 13.208 64.968 ;
     RECT  8.104 66.576 13.208 67.992 ;
     RECT  8.104 69.744 13.208 71.16 ;
     RECT  12.572 82.656 13.208 82.68 ;
     RECT  13.208 1.632 13.312 84.252 ;
     RECT  13.312 1.632 13.504 83.982 ;
     RECT  13.504 34.752 13.619 37.464 ;
     RECT  13.504 83.232 13.619 83.784 ;
     RECT  13.504 28.512 13.667 28.536 ;
     RECT  13.619 34.752 13.667 35.016 ;
     RECT  13.504 38.784 13.817 58.824 ;
     RECT  13.619 83.232 13.955 83.256 ;
     RECT  13.504 30.72 14.051 30.744 ;
     RECT  13.667 34.752 14.105 34.776 ;
     RECT  12.899 86.208 14.213 86.28 ;
     RECT  13.619 36 14.497 37.464 ;
     RECT  13.817 38.784 14.497 39.384 ;
     RECT  12.707 0.096 14.533 0.504 ;
     RECT  14.497 36 14.537 39.384 ;
     RECT  14.537 36 14.609 39.24 ;
     RECT  13.504 3.408 14.819 3.432 ;
     RECT  14.609 36 14.933 39 ;
     RECT  14.933 36 14.969 37.368 ;
     RECT  13.504 1.632 15.011 2.28 ;
     RECT  14.924 80.928 15.011 80.952 ;
     RECT  14.893 82.656 15.041 82.68 ;
     RECT  15.011 1.632 15.203 1.656 ;
     RECT  13.504 33.312 15.251 33.336 ;
     RECT  14.969 36 15.581 37.032 ;
     RECT  14.533 0.096 15.613 0.552 ;
     RECT  15.581 36.576 15.617 37.032 ;
     RECT  15.617 36.624 15.689 37.032 ;
     RECT  15.397 2.832 15.779 2.856 ;
     RECT  14.3 85.488 15.875 85.512 ;
     RECT  15.613 0.048 15.973 0.552 ;
     RECT  13.817 40.368 16.193 58.824 ;
     RECT  15.689 37.008 16.301 37.032 ;
     RECT  16.412 81.504 16.499 81.528 ;
     RECT  16.069 86.208 16.517 86.28 ;
     RECT  14.965 24.48 16.547 24.504 ;
     RECT  14.933 38.544 16.621 39 ;
     RECT  15.937 32.976 16.661 33 ;
     RECT  16.193 40.656 16.733 58.824 ;
     RECT  16.549 84.384 16.739 84.408 ;
     RECT  16.621 38.4 16.837 39 ;
     RECT  16.837 38.256 16.909 39 ;
     RECT  15.973 0.048 17.036 1.128 ;
     RECT  16.885 83.184 17.093 83.208 ;
     RECT  16.441 5.088 17.315 5.112 ;
     RECT  17.161 82.656 17.363 82.68 ;
     RECT  16.733 40.656 17.485 42.024 ;
     RECT  17.089 3.936 17.507 3.96 ;
     RECT  17.036 0.048 17.737 1.176 ;
     RECT  17.053 2.304 17.737 2.328 ;
     RECT  17.084 85.488 17.749 85.512 ;
     RECT  17.737 0.048 17.891 2.328 ;
     RECT  17.891 1.68 17.917 2.328 ;
     RECT  17.485 40.272 17.917 42.024 ;
     RECT  16.733 43.056 17.917 58.824 ;
     RECT  17.749 85.488 17.948 86.28 ;
     RECT  17.948 84.96 18.035 86.28 ;
     RECT  17.891 0.048 18.083 0.552 ;
     RECT  16.909 38.256 18.205 39.288 ;
     RECT  17.917 40.272 18.205 58.824 ;
     RECT  18.035 85.488 18.209 86.28 ;
     RECT  17.917 1.68 18.275 3.144 ;
     RECT  18.275 2.016 18.608 3.144 ;
     RECT  18.205 38.256 18.608 58.824 ;
     RECT  13.504 60.624 18.608 62.04 ;
     RECT  13.504 63.504 18.608 64.968 ;
     RECT  13.504 66.576 18.608 67.992 ;
     RECT  13.504 69.744 18.608 71.16 ;
     RECT  18.061 83.232 18.608 83.256 ;
     RECT  18.529 84.384 18.608 84.408 ;
     RECT  18.608 2.016 18.707 84.408 ;
     RECT  18.707 2.148 18.712 84.408 ;
     RECT  18.712 2.256 18.904 84.408 ;
     RECT  18.904 39.792 18.929 58.92 ;
     RECT  18.083 0.048 19.043 0.168 ;
     RECT  18.904 4.512 19.043 5.112 ;
     RECT  18.904 79.248 19.043 79.272 ;
     RECT  18.209 85.488 19.043 86.232 ;
     RECT  18.904 9.648 19.091 9.672 ;
     RECT  18.904 34.8 19.283 34.824 ;
     RECT  18.904 82.656 19.283 82.68 ;
     RECT  18.929 39.792 19.433 43.128 ;
     RECT  18.904 36.528 19.469 36.552 ;
     RECT  18.904 84.384 19.477 84.408 ;
     RECT  19.043 85.488 19.477 85.512 ;
     RECT  18.904 2.256 19.667 3.144 ;
     RECT  18.904 21.072 19.859 21.096 ;
     RECT  19.477 84.384 19.955 85.512 ;
     RECT  19.043 0.048 20.005 0.072 ;
     RECT  19.433 40.608 20.077 43.128 ;
     RECT  18.929 44.16 20.077 58.92 ;
     RECT  20.005 0.048 20.147 0.168 ;
     RECT  19.667 2.832 20.185 3.144 ;
     RECT  19.955 84.912 20.189 85.512 ;
     RECT  19.043 5.088 20.243 5.112 ;
     RECT  20.077 40.608 20.369 58.92 ;
     RECT  20.329 34.8 20.435 34.824 ;
     RECT  20.653 80.4 20.771 80.424 ;
     RECT  20.509 1.104 20.819 1.128 ;
     RECT  20.189 85.488 20.965 85.512 ;
     RECT  20.185 2.832 21.011 3.96 ;
     RECT  21.011 2.832 21.085 3.144 ;
     RECT  21.085 2.16 21.203 3.144 ;
     RECT  21.203 2.16 21.395 2.28 ;
     RECT  20.965 85.488 21.485 86.28 ;
     RECT  21.395 2.16 21.587 2.184 ;
     RECT  21.116 83.232 21.635 83.256 ;
     RECT  20.369 40.752 21.773 58.92 ;
     RECT  21.773 40.752 21.845 41.016 ;
     RECT  21.773 42.144 21.845 58.92 ;
     RECT  21.845 42.144 21.989 44.424 ;
     RECT  21.949 84.96 22.067 84.984 ;
     RECT  21.905 0.096 22.169 0.12 ;
     RECT  21.845 40.992 22.205 41.016 ;
     RECT  22.261 82.608 22.349 82.68 ;
     RECT  21.985 1.632 22.355 1.704 ;
     RECT  22.349 82.656 22.499 82.68 ;
     RECT  21.733 37.056 22.547 37.08 ;
     RECT  21.989 43.056 22.565 44.424 ;
     RECT  18.904 66.576 22.669 67.992 ;
     RECT  22.604 84.384 22.691 84.408 ;
     RECT  22.355 1.632 22.739 1.656 ;
     RECT  21.845 45.456 22.789 58.92 ;
     RECT  18.904 60.624 22.789 62.04 ;
     RECT  22.669 66.192 22.835 67.992 ;
     RECT  22.835 66.576 22.853 67.992 ;
     RECT  22.844 2.832 22.931 2.856 ;
     RECT  21.485 86.256 22.997 86.28 ;
     RECT  22.381 6.24 23.137 6.264 ;
     RECT  23.065 1.104 23.245 1.128 ;
     RECT  22.565 43.248 23.353 44.424 ;
     RECT  22.789 45.456 23.353 62.04 ;
     RECT  23.065 85.488 23.363 85.512 ;
     RECT  23.353 3.408 23.425 3.432 ;
     RECT  18.904 63.504 23.461 64.968 ;
     RECT  23.749 84.912 23.9 84.936 ;
     RECT  23.425 3.408 24.008 3.96 ;
     RECT  23.137 6.096 24.008 6.264 ;
     RECT  23.029 38.784 24.008 38.808 ;
     RECT  23.353 43.248 24.008 62.04 ;
     RECT  23.461 63.216 24.008 64.968 ;
     RECT  22.853 66.576 24.008 67.896 ;
     RECT  18.904 69.744 24.008 71.16 ;
     RECT  23.893 79.248 24.008 79.272 ;
     RECT  23.029 80.4 24.008 80.424 ;
     RECT  23.509 82.608 24.008 82.632 ;
     RECT  23.9 84.384 24.008 84.936 ;
     RECT  23.245 0.528 24.037 1.128 ;
     RECT  24.008 2.148 24.112 84.936 ;
     RECT  24.112 2.418 24.304 83.982 ;
     RECT  24.181 86.256 24.365 86.28 ;
     RECT  24.037 0.144 24.419 1.128 ;
     RECT  24.304 6.096 24.419 6.12 ;
     RECT  24.304 69.744 24.46 71.496 ;
     RECT  24.304 79.248 24.509 79.848 ;
     RECT  24.304 82.608 24.617 82.632 ;
     RECT  24.304 38.784 24.661 38.808 ;
     RECT  24.304 43.776 24.707 62.04 ;
     RECT  24.707 43.776 24.797 58.824 ;
     RECT  24.419 0.528 24.851 1.128 ;
     RECT  24.304 81.504 25.043 81.528 ;
     RECT  24.797 43.776 25.085 47.16 ;
     RECT  24.509 79.824 25.283 79.848 ;
     RECT  25.085 43.776 25.373 45 ;
     RECT  24.304 41.616 25.427 41.64 ;
     RECT  24.851 0.528 25.513 0.552 ;
     RECT  24.304 37.056 25.619 37.08 ;
     RECT  25.513 0.48 25.765 0.552 ;
     RECT  25.085 46.176 25.765 47.16 ;
     RECT  24.797 48.144 25.765 58.824 ;
     RECT  25.765 0.432 25.973 0.552 ;
     RECT  25.973 0.096 26.125 0.552 ;
     RECT  25.373 44.16 26.161 45 ;
     RECT  24.764 84.96 26.261 84.984 ;
     RECT  26.261 84.912 26.345 84.984 ;
     RECT  26.161 44.16 26.453 45.096 ;
     RECT  25.669 86.256 26.485 86.28 ;
     RECT  24.304 63.504 26.533 64.968 ;
     RECT  24.707 60.384 26.561 62.04 ;
     RECT  26.233 2.256 26.627 2.28 ;
     RECT  26.485 85.488 26.777 86.28 ;
     RECT  26.561 60.624 26.813 62.04 ;
     RECT  26.809 83.232 26.963 83.256 ;
     RECT  25.765 46.176 27.025 58.824 ;
     RECT  27.025 46.08 27.253 58.824 ;
     RECT  26.453 44.16 27.281 44.76 ;
     RECT  27.253 46.08 27.301 58.968 ;
     RECT  26.777 85.488 27.395 85.512 ;
     RECT  27.301 46.08 27.461 59.064 ;
     RECT  27.461 46.752 27.533 59.064 ;
     RECT  27.157 84.336 27.548 84.36 ;
     RECT  26.813 60.624 27.709 61.992 ;
     RECT  27.533 46.752 27.713 58.824 ;
     RECT  27.548 84.336 27.773 84.984 ;
     RECT  26.125 0.048 27.779 0.552 ;
     RECT  27.709 60.432 27.877 61.992 ;
     RECT  27.877 60.336 27.889 61.992 ;
     RECT  26.533 63.024 27.889 64.968 ;
     RECT  27.773 83.76 28.067 84.984 ;
     RECT  27.889 60.336 28.073 64.968 ;
     RECT  27.281 44.4 28.109 44.76 ;
     RECT  28.073 60.432 28.211 64.968 ;
     RECT  28.069 80.928 28.259 80.952 ;
     RECT  24.304 66.576 28.321 67.992 ;
     RECT  28.109 44.4 28.403 44.472 ;
     RECT  28.321 66.336 28.453 67.992 ;
     RECT  28.067 84.96 28.499 84.984 ;
     RECT  27.349 1.68 28.547 1.704 ;
     RECT  27.779 0.048 28.825 0.504 ;
     RECT  28.067 83.76 29.036 83.784 ;
     RECT  28.825 0.048 29.123 0.552 ;
     RECT  27.713 47.328 29.149 58.824 ;
     RECT  28.211 60.624 29.149 64.968 ;
     RECT  29.123 0.048 29.219 0.504 ;
     RECT  28.753 81.504 29.269 81.528 ;
     RECT  24.46 69.744 29.293 71.16 ;
     RECT  29.149 60.624 29.329 65.16 ;
     RECT  28.453 66.144 29.329 67.992 ;
     RECT  29.257 5.04 29.408 5.064 ;
     RECT  28.403 44.448 29.408 44.472 ;
     RECT  29.221 45.6 29.408 45.624 ;
     RECT  29.149 47.328 29.408 59.208 ;
     RECT  29.329 60.624 29.408 67.992 ;
     RECT  29.293 69.744 29.408 71.4 ;
     RECT  29.257 79.824 29.408 79.848 ;
     RECT  29.269 80.88 29.408 81.528 ;
     RECT  29.221 82.656 29.408 82.68 ;
     RECT  29.036 83.76 29.408 84.408 ;
     RECT  29.408 2.148 29.512 84.408 ;
     RECT  29.512 2.418 29.704 84.408 ;
     RECT  29.704 3.936 29.843 3.96 ;
     RECT  29.704 47.856 29.843 62.04 ;
     RECT  29.704 79.824 29.843 79.848 ;
     RECT  29.704 84.336 30.053 84.408 ;
     RECT  29.704 38.784 30.083 38.808 ;
     RECT  30.053 84.384 30.085 84.408 ;
     RECT  30.085 84.384 30.179 84.984 ;
     RECT  29.219 0.144 30.221 0.504 ;
     RECT  29.701 86.256 30.373 86.28 ;
     RECT  29.704 82.656 30.449 82.68 ;
     RECT  30.373 85.488 30.46 86.28 ;
     RECT  30.221 0.096 30.481 0.504 ;
     RECT  29.843 48.432 30.521 62.04 ;
     RECT  30.521 50.544 30.629 62.04 ;
     RECT  30.481 0.096 30.661 1.08 ;
     RECT  29.704 63.36 30.737 67.992 ;
     RECT  30.521 48.432 30.809 49.224 ;
     RECT  29.704 5.04 30.851 5.064 ;
     RECT  30.737 63.504 30.881 67.992 ;
     RECT  30.46 86.256 30.881 86.28 ;
     RECT  30.629 50.544 31.169 59.304 ;
     RECT  30.179 84.384 31.235 84.408 ;
     RECT  30.881 65.952 31.237 67.992 ;
     RECT  30.661 0.096 31.241 1.128 ;
     RECT  31.057 7.392 31.427 7.416 ;
     RECT  30.997 82.608 31.429 82.632 ;
     RECT  31.237 65.952 31.453 68.424 ;
     RECT  29.704 69.744 31.453 71.16 ;
     RECT  31.169 51.888 31.493 59.304 ;
     RECT  31.453 65.952 31.493 71.16 ;
     RECT  31.169 50.544 31.601 50.856 ;
     RECT  31.429 82.608 31.777 83.208 ;
     RECT  31.241 1.056 31.811 1.128 ;
     RECT  31.493 68.976 31.861 71.16 ;
     RECT  31.82 72.624 31.861 72.648 ;
     RECT  31.861 68.976 31.907 72.648 ;
     RECT  31.777 82.608 31.907 83.832 ;
     RECT  31.907 68.976 31.997 72.36 ;
     RECT  31.916 4.512 32.003 4.536 ;
     RECT  31.601 50.544 32.033 50.568 ;
     RECT  31.907 82.608 32.053 83.208 ;
     RECT  31.345 2.256 32.173 2.28 ;
     RECT  30.881 63.504 32.177 64.968 ;
     RECT  31.493 52.032 32.285 59.304 ;
     RECT  32.053 82.032 32.321 83.208 ;
     RECT  32.137 40.464 32.387 40.488 ;
     RECT  32.293 86.256 32.393 86.28 ;
     RECT  30.809 48.912 32.531 49.224 ;
     RECT  31.997 72.336 32.531 72.36 ;
     RECT  32.321 82.656 32.537 83.208 ;
     RECT  32.485 73.344 32.573 73.8 ;
     RECT  32.173 1.68 32.579 2.28 ;
     RECT  32.285 52.032 32.641 58.824 ;
     RECT  32.641 51.312 32.717 58.824 ;
     RECT  30.629 60.624 32.749 62.04 ;
     RECT  32.177 63.504 32.749 64.872 ;
     RECT  32.677 41.616 32.771 41.64 ;
     RECT  32.485 50.256 32.789 50.28 ;
     RECT  32.857 84.96 32.963 84.984 ;
     RECT  31.997 68.976 33.005 71.16 ;
     RECT  32.749 60.624 33.109 64.872 ;
     RECT  32.579 2.256 33.155 2.28 ;
     RECT  32.717 51.312 33.181 51.336 ;
     RECT  32.717 52.368 33.185 58.824 ;
     RECT  33.109 60.576 33.289 64.872 ;
     RECT  32.531 48.912 33.329 49.032 ;
     RECT  33.253 80.928 33.395 80.952 ;
     RECT  33.289 60.576 33.397 64.968 ;
     RECT  33.329 48.96 33.587 49.032 ;
     RECT  33.181 50.736 33.757 51.336 ;
     RECT  33.649 47.328 33.779 47.352 ;
     RECT  33.397 59.856 33.797 64.968 ;
     RECT  33.068 85.488 33.827 85.512 ;
     RECT  32.537 82.656 33.932 82.68 ;
     RECT  32.885 0.096 33.977 0.12 ;
     RECT  34.172 84.384 34.364 84.408 ;
     RECT  33.757 50.16 34.441 51.336 ;
     RECT  33.185 52.464 34.441 58.824 ;
     RECT  33.005 69.744 34.693 71.16 ;
     RECT  33.797 60.576 34.765 64.968 ;
     RECT  31.493 65.952 34.765 67.992 ;
     RECT  34.693 69.504 34.765 71.16 ;
     RECT  34.253 74.688 34.765 74.712 ;
     RECT  34.513 42.72 34.808 42.744 ;
     RECT  33.587 48.96 34.808 48.984 ;
     RECT  34.441 50.16 34.808 58.824 ;
     RECT  34.765 60.576 34.808 71.16 ;
     RECT  32.573 73.344 34.808 73.512 ;
     RECT  34.765 74.688 34.808 75.24 ;
     RECT  33.289 76.56 34.808 76.584 ;
     RECT  33.932 82.08 34.808 82.68 ;
     RECT  34.364 84.384 34.808 84.984 ;
     RECT  34.808 2.148 34.912 84.984 ;
     RECT  34.225 0.48 34.931 0.552 ;
     RECT  34.837 86.208 35.029 86.232 ;
     RECT  34.912 2.418 35.104 83.982 ;
     RECT  35.104 41.376 35.219 42.216 ;
     RECT  35.104 48.96 35.219 48.984 ;
     RECT  35.104 60.576 35.219 71.16 ;
     RECT  35.219 60.576 35.237 62.04 ;
     RECT  35.104 79.2 35.237 79.224 ;
     RECT  35.029 86.112 35.267 86.232 ;
     RECT  35.104 51.216 35.273 53.592 ;
     RECT  35.219 41.376 35.315 41.4 ;
     RECT  34.912 84.96 35.315 84.984 ;
     RECT  35.219 63.504 35.345 71.16 ;
     RECT  35.104 82.08 35.507 82.104 ;
     RECT  35.345 63.504 35.596 68.424 ;
     RECT  35.273 52.032 35.705 53.592 ;
     RECT  35.596 63.504 35.849 65.448 ;
     RECT  35.104 43.248 35.891 43.944 ;
     RECT  35.104 54.672 35.891 59.304 ;
     RECT  35.705 52.32 35.921 53.592 ;
     RECT  35.891 54.672 36.133 58.92 ;
     RECT  36.092 84.384 36.179 84.408 ;
     RECT  35.345 69.456 36.277 71.16 ;
     RECT  36.284 83.808 36.371 84.36 ;
     RECT  35.596 66.576 36.467 68.424 ;
     RECT  35.849 63.504 36.497 64.968 ;
     RECT  36.371 84.336 36.821 84.36 ;
     RECT  35.237 60.576 36.965 61.752 ;
     RECT  36.889 83.232 36.995 83.256 ;
     RECT  36.277 69.456 36.997 71.544 ;
     RECT  35.104 75.216 37.033 75.24 ;
     RECT  36.925 50.736 37.037 50.76 ;
     RECT  36.745 47.904 37.043 47.928 ;
     RECT  36.997 69.456 37.043 72.024 ;
     RECT  36.925 73.584 37.043 73.608 ;
     RECT  35.921 52.32 37.105 52.728 ;
     RECT  37.033 75.216 37.137 75.96 ;
     RECT  36.497 64.32 37.235 64.968 ;
     RECT  37.105 51.888 37.285 52.728 ;
     RECT  36.133 53.808 37.285 58.92 ;
     RECT  37.043 72 37.289 72.024 ;
     RECT  35.773 85.488 37.325 85.512 ;
     RECT  37.285 51.888 37.433 58.92 ;
     RECT  37.381 81.456 37.469 81.48 ;
     RECT  36.467 66.576 37.501 68.088 ;
     RECT  37.043 69.456 37.501 70.92 ;
     RECT  37.433 53.328 37.505 58.92 ;
     RECT  37.505 53.808 37.541 58.92 ;
     RECT  37.501 82.656 37.613 82.68 ;
     RECT  37.433 51.888 37.619 51.912 ;
     RECT  37.573 84.96 37.667 84.984 ;
     RECT  37.189 63.216 37.717 63.24 ;
     RECT  37.541 56.16 37.757 58.92 ;
     RECT  37.137 75.936 37.757 75.96 ;
     RECT  37.645 79.248 37.859 79.272 ;
     RECT  36.965 60.624 37.937 61.752 ;
     RECT  38.033 83.76 38.117 83.784 ;
     RECT  38.041 50.736 38.195 50.76 ;
     RECT  37.235 64.944 38.221 64.968 ;
     RECT  35.077 0.096 38.293 0.12 ;
     RECT  37.757 57.168 38.329 58.92 ;
     RECT  38.293 0.096 38.405 0.552 ;
     RECT  38.221 64.944 38.473 65.544 ;
     RECT  37.501 66.576 38.477 70.92 ;
     RECT  37.937 60.816 38.485 61.752 ;
     RECT  38.245 86.256 38.485 86.28 ;
     RECT  37.717 62.976 38.509 63.24 ;
     RECT  38.473 64.32 38.509 65.544 ;
     RECT  37.045 73.488 38.513 73.512 ;
     RECT  38.509 62.976 38.531 65.544 ;
     RECT  38.329 57.168 38.581 59.208 ;
     RECT  38.581 57.168 38.585 59.256 ;
     RECT  38.585 57.36 38.657 59.256 ;
     RECT  35.891 43.248 38.761 43.272 ;
     RECT  38.531 63.792 38.761 65.544 ;
     RECT  38.477 66.576 38.761 68.088 ;
     RECT  38.581 82.08 38.797 82.104 ;
     RECT  38.761 43.104 38.801 43.272 ;
     RECT  38.761 63.792 38.801 68.088 ;
     RECT  38.801 64.32 38.819 68.088 ;
     RECT  38.477 69.216 38.867 70.92 ;
     RECT  37.541 53.808 38.981 54.744 ;
     RECT  38.485 60.816 39.053 61.896 ;
     RECT  38.819 64.32 39.053 64.968 ;
     RECT  38.797 82.08 39.053 82.68 ;
     RECT  39.077 82.032 39.161 82.056 ;
     RECT  39.053 60.816 39.337 61.512 ;
     RECT  38.405 0.336 39.473 0.552 ;
     RECT  38.485 85.488 39.629 86.28 ;
     RECT  39.473 0.096 39.737 0.552 ;
     RECT  39.692 83.232 39.913 83.256 ;
     RECT  39.913 83.232 40.093 83.832 ;
     RECT  39.737 0.24 40.115 0.552 ;
     RECT  38.801 43.104 40.208 43.128 ;
     RECT  38.981 53.808 40.208 53.832 ;
     RECT  37.757 56.16 40.208 56.184 ;
     RECT  38.657 57.552 40.208 59.256 ;
     RECT  39.337 60.384 40.208 61.512 ;
     RECT  39.553 62.736 40.208 62.76 ;
     RECT  39.053 64.944 40.208 64.968 ;
     RECT  38.819 66.096 40.208 68.088 ;
     RECT  38.867 69.216 40.208 69.816 ;
     RECT  38.867 70.896 40.208 70.92 ;
     RECT  40.093 83.232 40.208 84.408 ;
     RECT  40.208 2.148 40.211 84.408 ;
     RECT  40.211 2.148 40.312 84.252 ;
     RECT  39.629 85.488 40.451 85.512 ;
     RECT  40.312 2.418 40.504 83.982 ;
     RECT  40.504 58.416 40.601 58.68 ;
     RECT  40.504 50.16 40.691 50.184 ;
     RECT  40.504 79.824 40.883 80.424 ;
     RECT  40.504 47.904 40.931 47.928 ;
     RECT  40.883 79.824 41.075 79.848 ;
     RECT  40.504 70.896 41.141 71.832 ;
     RECT  40.115 0.24 41.237 0.504 ;
     RECT  41.237 0.096 41.321 0.504 ;
     RECT  41.321 0.24 41.42 0.504 ;
     RECT  40.597 86.256 41.425 86.28 ;
     RECT  40.504 57.408 41.497 57.432 ;
     RECT  40.601 58.416 41.497 58.584 ;
     RECT  41.42 0.24 41.507 0.552 ;
     RECT  41.497 57.408 41.533 58.584 ;
     RECT  40.504 63.744 41.569 69.816 ;
     RECT  41.141 70.896 41.569 71.592 ;
     RECT  41.497 76.896 41.605 76.92 ;
     RECT  41.605 76.752 41.651 76.92 ;
     RECT  40.504 53.808 41.713 53.832 ;
     RECT  40.504 60.432 41.852 61.608 ;
     RECT  40.504 62.736 41.852 62.76 ;
     RECT  41.804 46.896 41.891 46.92 ;
     RECT  41.845 50.784 41.929 50.808 ;
     RECT  41.713 53.568 41.929 53.832 ;
     RECT  41.425 85.488 41.933 86.28 ;
     RECT  41.929 50.784 41.969 51.336 ;
     RECT  41.852 60.432 42.001 62.76 ;
     RECT  41.569 63.744 42.001 71.592 ;
     RECT  41.929 52.992 42.092 53.832 ;
     RECT  40.504 54.864 42.092 54.888 ;
     RECT  41.651 76.752 42.133 76.776 ;
     RECT  41.533 57.024 42.172 58.584 ;
     RECT  42.092 52.992 42.179 54.888 ;
     RECT  42.172 58.56 42.181 58.584 ;
     RECT  42.101 55.92 42.185 55.944 ;
     RECT  41.969 51.312 42.289 51.336 ;
     RECT  42.133 76.08 42.325 76.776 ;
     RECT  42.289 51.312 42.329 51.432 ;
     RECT  41.605 78.096 42.337 78.12 ;
     RECT  40.504 43.104 42.365 43.128 ;
     RECT  42.325 75.84 42.419 76.776 ;
     RECT  42.085 84.336 42.517 84.36 ;
     RECT  42.172 57.024 42.613 57.432 ;
     RECT  42.181 58.56 42.653 58.728 ;
     RECT  41.507 0.24 42.659 0.504 ;
     RECT  42.001 60.432 42.689 71.592 ;
     RECT  42.517 83.856 42.794 84.36 ;
     RECT  42.277 29.616 42.941 29.64 ;
     RECT  42.689 60.432 42.941 70.344 ;
     RECT  42.757 1.104 43.043 1.128 ;
     RECT  42.361 55.152 43.153 55.608 ;
     RECT  42.613 56.928 43.153 57.432 ;
     RECT  42.179 52.992 43.225 53.832 ;
     RECT  42.373 31.536 43.229 31.56 ;
     RECT  42.689 71.568 43.261 71.592 ;
     RECT  43.261 71.568 43.301 71.736 ;
     RECT  42.397 79.2 43.331 79.224 ;
     RECT  42.329 51.408 43.333 51.432 ;
     RECT  43.153 55.152 43.405 57.432 ;
     RECT  41.933 86.256 43.481 86.28 ;
     RECT  43.225 52.56 43.583 53.832 ;
     RECT  43.405 54.912 43.585 57.432 ;
     RECT  42.653 58.56 43.585 58.632 ;
     RECT  43.301 71.712 43.585 71.736 ;
     RECT  43.585 54.912 43.801 58.632 ;
     RECT  42.941 60.912 43.801 70.344 ;
     RECT  42.794 84.336 43.813 84.36 ;
     RECT  43.333 51.216 43.837 51.432 ;
     RECT  43.583 52.56 43.837 53.928 ;
     RECT  43.801 54.912 43.837 58.68 ;
     RECT  43.837 51.216 43.913 59.256 ;
     RECT  42.949 83.184 43.913 83.208 ;
     RECT  43.913 52.176 43.957 59.256 ;
     RECT  43.801 60.912 43.957 70.728 ;
     RECT  43.873 44.448 44.003 44.472 ;
     RECT  43.957 52.176 44.003 70.728 ;
     RECT  43.813 84.288 44.005 84.36 ;
     RECT  44.003 52.176 44.044 60.024 ;
     RECT  43.297 74.112 44.051 74.136 ;
     RECT  44.003 61.056 44.129 70.728 ;
     RECT  43.693 46.752 44.195 46.776 ;
     RECT  44.005 83.76 44.225 84.36 ;
     RECT  44.225 83.76 44.237 84.936 ;
     RECT  44.129 61.056 44.256 69.816 ;
     RECT  44.237 84.24 44.309 84.936 ;
     RECT  44.256 61.056 44.381 63.672 ;
     RECT  44.233 47.328 44.387 47.352 ;
     RECT  43.981 82.656 44.387 82.68 ;
     RECT  43.585 71.712 44.449 71.832 ;
     RECT  44.381 61.056 44.489 63.576 ;
     RECT  44.044 52.176 44.569 58.968 ;
     RECT  42.785 0.096 44.596 0.12 ;
     RECT  44.596 0.048 44.629 0.12 ;
     RECT  44.005 72.912 44.701 72.936 ;
     RECT  44.629 0.048 44.741 0.504 ;
     RECT  44.741 0.144 44.777 0.504 ;
     RECT  44.701 72.912 44.869 73.512 ;
     RECT  44.777 0.192 44.881 0.504 ;
     RECT  44.449 71.184 45.061 71.832 ;
     RECT  44.869 72.816 45.061 73.512 ;
     RECT  44.773 39.888 45.397 39.912 ;
     RECT  45.349 41.04 45.397 41.064 ;
     RECT  45.061 71.184 45.421 73.512 ;
     RECT  44.677 86.256 45.533 86.28 ;
     RECT  44.044 60 45.565 60.024 ;
     RECT  44.489 61.056 45.565 61.08 ;
     RECT  42.419 76.752 45.565 76.776 ;
     RECT  45.397 39.888 45.608 41.064 ;
     RECT  44.881 46.032 45.608 46.056 ;
     RECT  45.493 49.584 45.608 49.608 ;
     RECT  44.629 50.736 45.608 50.76 ;
     RECT  44.569 52.176 45.608 52.2 ;
     RECT  44.569 53.904 45.608 58.968 ;
     RECT  45.565 60 45.608 61.08 ;
     RECT  44.489 62.16 45.608 63.576 ;
     RECT  44.256 64.848 45.608 69.816 ;
     RECT  45.421 71.184 45.608 73.608 ;
     RECT  45.097 75.12 45.608 75.144 ;
     RECT  45.565 76.272 45.608 76.776 ;
     RECT  45.349 82.656 45.608 82.68 ;
     RECT  44.309 84.24 45.608 84.36 ;
     RECT  45.608 2.148 45.712 84.36 ;
     RECT  44.881 0.192 45.731 0.552 ;
     RECT  45.731 0.192 45.877 0.504 ;
     RECT  45.712 2.418 45.904 84.36 ;
     RECT  45.904 53.904 45.929 61.128 ;
     RECT  45.877 0.096 46.019 0.504 ;
     RECT  45.904 65.04 46.06 69.144 ;
     RECT  45.904 71.328 46.163 72.456 ;
     RECT  45.904 40.032 46.181 44.04 ;
     RECT  45.733 85.488 46.211 86.04 ;
     RECT  45.904 76.752 46.217 76.776 ;
     RECT  45.904 4.512 46.307 4.536 ;
     RECT  45.929 53.904 46.469 60.024 ;
     RECT  46.181 40.032 46.499 42.744 ;
     RECT  46.469 54.912 46.505 60.024 ;
     RECT  46.06 65.088 46.505 69.144 ;
     RECT  46.505 56.88 46.54 60.024 ;
     RECT  46.54 56.88 46.541 58.536 ;
     RECT  46.541 56.88 46.649 57 ;
     RECT  46.019 0.192 46.691 0.504 ;
     RECT  46.499 40.032 46.691 41.016 ;
     RECT  45.904 47.856 46.691 49.512 ;
     RECT  46.469 53.904 46.739 53.928 ;
     RECT  45.929 61.008 46.757 61.128 ;
     RECT  45.904 84.192 46.757 84.36 ;
     RECT  46.691 0.48 46.793 0.504 ;
     RECT  45.904 73.488 46.829 75.24 ;
     RECT  45.904 38.784 46.885 38.808 ;
     RECT  46.691 40.032 46.931 40.056 ;
     RECT  46.505 65.088 46.973 69.096 ;
     RECT  46.649 56.976 47.009 57 ;
     RECT  46.211 85.488 47.027 85.512 ;
     RECT  45.904 62.16 47.036 64.056 ;
     RECT  46.885 38.16 47.075 38.808 ;
     RECT  45.904 51.888 47.077 52.488 ;
     RECT  47.077 51.504 47.113 52.488 ;
     RECT  47.113 51.312 47.123 52.488 ;
     RECT  47.036 61.92 47.123 64.056 ;
     RECT  47.123 62.16 47.125 64.056 ;
     RECT  46.973 65.088 47.125 65.544 ;
     RECT  45.904 46.752 47.185 46.776 ;
     RECT  46.691 47.856 47.185 47.88 ;
     RECT  47.123 51.312 47.197 51.912 ;
     RECT  46.181 44.016 47.221 44.04 ;
     RECT  47.125 62.16 47.261 65.544 ;
     RECT  46.757 84.288 47.297 84.36 ;
     RECT  46.505 55.44 47.333 55.464 ;
     RECT  46.541 58.128 47.369 58.536 ;
     RECT  46.54 59.76 47.437 60.024 ;
     RECT  47.365 45.024 47.459 45.048 ;
     RECT  47.185 46.752 47.477 47.88 ;
     RECT  46.691 48.912 47.477 49.512 ;
     RECT  47.437 59.76 47.477 60.408 ;
     RECT  47.393 86.256 47.477 86.28 ;
     RECT  46.973 66.72 47.513 69.096 ;
     RECT  46.499 42.192 47.545 42.744 ;
     RECT  47.545 42.144 47.585 42.744 ;
     RECT  46.163 71.904 47.645 72.456 ;
     RECT  46.829 73.488 47.645 73.512 ;
     RECT  47.369 58.368 47.653 58.536 ;
     RECT  47.261 62.16 47.657 63.912 ;
     RECT  47.513 66.768 47.717 69.096 ;
     RECT  45.904 70.272 47.717 70.296 ;
     RECT  47.653 17.088 47.737 17.112 ;
     RECT  47.653 58.368 47.801 59.304 ;
     RECT  47.221 43.92 47.833 44.04 ;
     RECT  47.717 66.768 47.833 70.296 ;
     RECT  47.645 71.904 47.833 73.512 ;
     RECT  47.297 84.336 47.917 84.36 ;
     RECT  47.852 45.552 47.939 45.576 ;
     RECT  47.477 46.752 47.939 46.776 ;
     RECT  47.833 66.768 47.939 73.512 ;
     RECT  47.261 64.992 48.013 65.544 ;
     RECT  47.185 1.68 48.017 1.704 ;
     RECT  47.075 38.16 48.017 38.184 ;
     RECT  47.833 43.92 48.017 44.472 ;
     RECT  47.477 60.384 48.085 60.408 ;
     RECT  47.989 0.096 48.088 0.12 ;
     RECT  47.939 70.128 48.089 73.512 ;
     RECT  48.085 60.384 48.125 61.032 ;
     RECT  47.657 62.16 48.125 63.624 ;
     RECT  46.829 74.832 48.193 75.24 ;
     RECT  48.088 0.048 48.233 0.12 ;
     RECT  48.017 44.448 48.233 44.472 ;
     RECT  48.085 85.488 48.265 85.512 ;
     RECT  48.221 43.344 48.305 43.368 ;
     RECT  48.013 64.992 48.305 65.784 ;
     RECT  47.581 41.04 48.325 41.064 ;
     RECT  47.585 42.144 48.325 42.168 ;
     RECT  48.193 74.832 48.325 75.72 ;
     RECT  47.293 76.944 48.325 76.968 ;
     RECT  48.257 78.048 48.341 78.072 ;
     RECT  48.325 74.832 48.371 76.968 ;
     RECT  48.337 79.824 48.421 79.848 ;
     RECT  48.325 41.04 48.449 42.168 ;
     RECT  48.371 74.832 48.449 76.344 ;
     RECT  47.477 49.008 48.521 49.512 ;
     RECT  48.305 65.136 48.521 65.784 ;
     RECT  47.197 51.888 48.581 51.912 ;
     RECT  48.265 84.96 48.589 85.512 ;
     RECT  47.477 47.856 48.593 47.88 ;
     RECT  48.581 51.888 48.665 52.488 ;
     RECT  47.939 66.768 48.665 69.048 ;
     RECT  48.089 70.512 48.733 73.512 ;
     RECT  48.589 84.96 48.755 85.56 ;
     RECT  48.521 49.488 48.773 49.512 ;
     RECT  48.449 41.04 48.851 41.064 ;
     RECT  48.755 84.96 48.953 85.512 ;
     RECT  48.049 54.48 48.985 54.504 ;
     RECT  48.125 62.304 48.989 63.624 ;
     RECT  48.989 62.688 48.995 63.624 ;
     RECT  48.805 56.976 48.997 57 ;
     RECT  48.997 56.976 49.043 57.144 ;
     RECT  48.665 66.768 49.043 69 ;
     RECT  47.801 58.368 49.157 58.392 ;
     RECT  48.985 53.568 49.169 54.504 ;
     RECT  49.057 84.384 49.187 84.408 ;
     RECT  49.157 58.368 49.241 59.256 ;
     RECT  48.733 70.512 49.241 73.56 ;
     RECT  48.953 85.488 49.277 85.512 ;
     RECT  49.043 57.024 49.381 57.144 ;
     RECT  49.241 58.368 49.381 58.392 ;
     RECT  48.449 42.096 49.427 42.12 ;
     RECT  49.381 57.024 49.427 58.392 ;
     RECT  49.043 66.768 49.453 68.952 ;
     RECT  48.233 0.096 49.457 0.12 ;
     RECT  49.427 57.552 49.475 58.392 ;
     RECT  49.241 70.512 49.493 73.512 ;
     RECT  49.493 71.184 49.571 73.512 ;
     RECT  49.475 58.368 49.673 58.392 ;
     RECT  48.449 74.832 49.673 75.816 ;
     RECT  49.429 64.992 49.676 65.016 ;
     RECT  49.453 66.336 49.676 68.952 ;
     RECT  48.995 62.88 49.733 63.624 ;
     RECT  49.676 64.8 49.733 68.952 ;
     RECT  49.169 54.48 49.741 54.504 ;
     RECT  49.525 55.872 49.741 55.896 ;
     RECT  49.571 72.432 49.745 73.512 ;
     RECT  49.733 62.88 49.763 68.952 ;
     RECT  49.763 62.88 49.811 65.016 ;
     RECT  49.292 82.08 49.811 82.104 ;
     RECT  49.673 74.832 49.849 75.096 ;
     RECT  49.849 74.64 49.961 75.096 ;
     RECT  49.129 50.448 49.993 50.472 ;
     RECT  48.665 51.888 49.993 51.912 ;
     RECT  49.811 62.976 49.996 65.016 ;
     RECT  49.763 66.096 50.005 68.952 ;
     RECT  49.885 69.936 50.005 69.96 ;
     RECT  49.571 71.184 50.033 71.4 ;
     RECT  49.993 50.448 50.173 51.912 ;
     RECT  50.165 86.256 50.249 86.28 ;
     RECT  49.573 84.336 50.569 84.36 ;
     RECT  50.569 84.336 50.68 84.984 ;
     RECT  49.489 0.384 50.713 0.552 ;
     RECT  49.741 54.48 50.869 55.896 ;
     RECT  48.125 61.008 50.869 61.032 ;
     RECT  50.68 84.336 50.915 85.56 ;
     RECT  49.996 64.992 50.929 65.016 ;
     RECT  50.005 66.096 50.929 69.96 ;
     RECT  48.697 46.416 51.008 46.44 ;
     RECT  50.869 48.384 51.008 49.464 ;
     RECT  50.173 50.448 51.008 52.2 ;
     RECT  50.869 54.48 51.008 56.088 ;
     RECT  50.869 59.808 51.008 59.832 ;
     RECT  50.869 61.008 51.008 61.128 ;
     RECT  49.996 62.976 51.008 63.912 ;
     RECT  50.929 64.992 51.008 69.96 ;
     RECT  50.033 71.28 51.008 71.4 ;
     RECT  49.745 72.432 51.008 72.456 ;
     RECT  49.745 73.488 51.008 73.512 ;
     RECT  49.961 74.64 51.008 74.904 ;
     RECT  50.915 84.336 51.008 84.936 ;
     RECT  51.008 2.148 51.112 84.936 ;
     RECT  50.713 0.288 51.301 0.552 ;
     RECT  51.112 2.418 51.304 84.936 ;
     RECT  51.304 50.832 51.443 52.2 ;
     RECT  51.304 67.872 51.443 69.096 ;
     RECT  51.304 54.624 51.445 56.472 ;
     RECT  51.304 74.544 51.473 75.528 ;
     RECT  51.304 64.992 51.484 66.696 ;
     RECT  51.445 54.624 51.509 56.088 ;
     RECT  51.443 67.872 51.725 69 ;
     RECT  51.473 74.544 51.725 74.76 ;
     RECT  51.301 0.096 51.731 0.552 ;
     RECT  51.304 83.232 51.731 83.256 ;
     RECT  51.725 68.16 51.761 68.184 ;
     RECT  51.725 74.736 51.869 74.76 ;
     RECT  51.509 54.624 51.875 55.128 ;
     RECT  51.304 58.512 51.905 58.536 ;
     RECT  51.731 0.096 51.923 0.504 ;
     RECT  51.443 50.832 51.977 51.288 ;
     RECT  51.304 62.688 51.977 63.864 ;
     RECT  51.484 65.808 52.193 66.696 ;
     RECT  51.304 82.08 52.403 82.104 ;
     RECT  51.977 63.84 52.661 63.864 ;
     RECT  51.977 62.688 52.769 62.712 ;
     RECT  52.193 66.672 52.769 66.696 ;
     RECT  51.304 84.912 52.841 84.936 ;
     RECT  52.729 52.464 52.883 52.488 ;
     RECT  51.304 48.96 52.913 48.984 ;
     RECT  51.304 72.432 52.913 72.456 ;
     RECT  51.875 55.104 52.949 55.128 ;
     RECT  52.94 80.4 53.027 80.424 ;
     RECT  51.923 0.096 53.197 0.12 ;
     RECT  53.089 48.48 53.267 48.504 ;
     RECT  53.341 82.656 53.453 82.68 ;
     RECT  53.773 84.384 53.845 84.408 ;
     RECT  53.161 85.44 53.845 85.512 ;
     RECT  53.845 84.384 53.891 85.512 ;
     RECT  53.891 84.96 54.097 85.512 ;
     RECT  54.097 84.96 54.323 86.28 ;
     RECT  54.097 82.608 54.457 82.632 ;
     RECT  54.457 82.08 54.755 82.632 ;
     RECT  54.323 84.96 54.947 84.984 ;
     RECT  53.197 0.096 55.379 0.552 ;
     RECT  54.323 86.256 55.397 86.28 ;
     RECT  54.755 82.08 55.571 82.104 ;
     RECT  55.379 0.096 55.649 0.12 ;
    LAYER M5 ;
     RECT  0.96 0.016 0.984 0.131 ;
     RECT  5.904 0.016 55.608 0.131 ;
     RECT  37.008 0.131 53.832 0.467 ;
     RECT  37.008 0.467 41.88 0.515 ;
     RECT  43.008 0.467 53.448 0.515 ;
     RECT  5.904 0.131 35.88 0.563 ;
     RECT  37.008 0.515 41.496 0.563 ;
     RECT  43.008 0.515 51.72 0.563 ;
     RECT  52.848 0.515 53.448 0.563 ;
     RECT  55.344 0.131 55.368 0.563 ;
     RECT  43.008 0.563 48.84 1.139 ;
     RECT  26.592 0.563 35.88 1.715 ;
     RECT  3.12 0.085 3.144 2.137 ;
     RECT  40.656 0.563 40.92 2.137 ;
     RECT  49.968 0.563 50.856 2.137 ;
     RECT  49.968 2.137 51.12 2.151 ;
     RECT  5.904 0.563 25.608 2.291 ;
     RECT  26.592 1.715 26.616 2.291 ;
     RECT  5.904 2.291 11.736 2.867 ;
     RECT  12.864 2.291 17.496 2.867 ;
     RECT  12.864 2.867 15.384 3.443 ;
     RECT  5.904 2.867 11.352 3.971 ;
     RECT  16.512 2.867 17.496 3.971 ;
     RECT  18.6 2.291 25.608 3.971 ;
     RECT  28.896 1.715 35.88 5.075 ;
     RECT  12.864 3.443 14.04 5.123 ;
     RECT  16.512 3.971 17.304 5.123 ;
     RECT  6.096 3.971 11.352 6.275 ;
     RECT  6.096 6.275 10.728 6.851 ;
     RECT  6.48 6.851 10.728 7.427 ;
     RECT  31.392 5.075 35.88 7.427 ;
     RECT  0.912 13.621 0.936 14.725 ;
     RECT  2.4 2.137 3.144 14.773 ;
     RECT  0.912 14.725 1.128 15.301 ;
     RECT  2.4 14.773 3.384 16.357 ;
     RECT  0.912 15.301 1.368 17.605 ;
     RECT  2.4 16.357 3.72 17.605 ;
     RECT  0.912 17.605 3.72 18.181 ;
     RECT  7.248 7.427 10.728 18.227 ;
     RECT  0.912 18.181 3.96 19.379 ;
     RECT  7.8 18.227 10.728 20.531 ;
     RECT  7.8 20.531 9.576 20.579 ;
     RECT  18.6 3.971 20.424 21.107 ;
     RECT  5.664 20.965 5.688 21.731 ;
     RECT  0.912 19.379 3.768 22.597 ;
     RECT  0.912 22.597 4.104 23.125 ;
     RECT  0.144 23.125 4.104 23.315 ;
     RECT  0.912 23.315 4.104 23.411 ;
     RECT  7.8 20.579 9.384 23.411 ;
     RECT  6.24 22.165 6.264 23.509 ;
     RECT  7.8 23.411 9 23.987 ;
     RECT  10.704 20.531 10.728 23.987 ;
     RECT  0.912 23.411 3.768 24.277 ;
     RECT  5.808 23.509 6.264 24.277 ;
     RECT  0.144 24.277 3.768 24.467 ;
     RECT  15.36 3.443 15.384 24.515 ;
     RECT  16.512 5.123 16.536 24.515 ;
     RECT  0.912 24.467 3.768 24.851 ;
     RECT  5.808 24.277 6.696 25.187 ;
     RECT  7.8 23.987 8.112 27.157 ;
     RECT  0.912 24.851 3.672 27.347 ;
     RECT  13.056 5.123 14.04 28.547 ;
     RECT  7.8 27.157 8.76 28.933 ;
     RECT  5.52 27.301 5.544 29.029 ;
     RECT  5.52 29.029 5.592 29.413 ;
     RECT  7.68 28.933 8.76 29.507 ;
     RECT  7.68 29.507 8.112 29.795 ;
     RECT  0.912 27.347 3.288 29.893 ;
     RECT  0.144 29.893 3.288 30.755 ;
     RECT  13.2 28.547 14.04 30.755 ;
     RECT  5.136 29.413 5.592 30.851 ;
     RECT  42.288 29.605 42.312 31.525 ;
     RECT  5.568 30.851 5.592 33.107 ;
     RECT  6.672 25.187 6.696 33.589 ;
     RECT  5.712 33.589 6.696 34.117 ;
     RECT  7.8 29.795 8.112 34.117 ;
     RECT  5.712 34.117 8.112 34.259 ;
     RECT  13.2 30.755 13.512 34.357 ;
     RECT  10.56 33.397 10.584 34.403 ;
     RECT  0.912 30.755 3.288 34.405 ;
     RECT  12.72 34.357 13.512 34.741 ;
     RECT  18.6 21.107 19.272 34.835 ;
     RECT  20.4 21.107 20.424 34.835 ;
     RECT  12.72 34.741 13.608 34.981 ;
     RECT  0.144 34.405 3.288 35.747 ;
     RECT  6.672 34.259 8.112 36.275 ;
     RECT  9.12 34.981 9.144 36.515 ;
     RECT  12.72 34.981 13.656 36.851 ;
     RECT  15.216 33.301 15.24 36.997 ;
     RECT  21.744 3.971 25.608 37.091 ;
     RECT  12.72 36.851 13.512 37.573 ;
     RECT  12.672 37.573 13.512 38.053 ;
     RECT  5.616 37.573 5.64 38.389 ;
     RECT  23.28 37.091 25.416 38.819 ;
     RECT  28.896 5.075 30.072 38.819 ;
     RECT  11.76 38.053 13.512 38.915 ;
     RECT  15.12 36.997 15.24 38.963 ;
     RECT  0.912 35.747 3.288 40.165 ;
     RECT  12.672 38.915 13.512 40.165 ;
     RECT  32.352 7.427 35.88 40.499 ;
     RECT  5.616 38.389 5.688 40.835 ;
     RECT  0.912 40.165 3.528 41.075 ;
     RECT  43.392 1.139 48.84 41.075 ;
     RECT  11.904 40.165 13.512 41.123 ;
     RECT  0.912 41.075 3.288 41.509 ;
     RECT  16.56 41.029 16.584 41.651 ;
     RECT  25.392 38.819 25.416 41.651 ;
     RECT  32.736 40.499 35.88 41.651 ;
     RECT  0.192 41.509 3.288 41.747 ;
     RECT  6.672 36.275 6.696 41.749 ;
     RECT  7.8 36.275 8.112 41.749 ;
     RECT  43.392 41.075 48.648 42.085 ;
     RECT  49.968 2.151 51.312 42.085 ;
     RECT  12.768 41.123 13.512 42.227 ;
     RECT  6.672 41.749 8.232 42.707 ;
     RECT  6.672 42.707 8.112 42.803 ;
     RECT  12 42.709 12.024 43.907 ;
     RECT  33.552 41.651 35.88 43.955 ;
     RECT  0.912 41.747 3.288 44.053 ;
     RECT  28.896 38.819 29.712 44.389 ;
     RECT  0.144 44.053 3.288 44.435 ;
     RECT  7.8 42.803 8.112 44.437 ;
     RECT  15.216 38.963 15.24 44.725 ;
     RECT  24 38.819 24.312 45.013 ;
     RECT  43.392 42.085 51.312 45.059 ;
     RECT  24 45.013 24.408 45.347 ;
     RECT  10.416 44.341 10.44 45.443 ;
     RECT  14.496 44.725 15.24 45.587 ;
     RECT  28.368 44.389 29.712 45.635 ;
     RECT  21.072 41.893 21.096 45.925 ;
     RECT  7.8 44.437 8.232 46.259 ;
     RECT  13.2 42.227 13.512 46.741 ;
     RECT  20.208 45.925 21.096 46.787 ;
     RECT  6.672 42.803 6.696 46.789 ;
     RECT  7.8 46.259 8.112 46.789 ;
     RECT  40.2 2.137 40.92 46.885 ;
     RECT  42.288 31.525 42.408 46.885 ;
     RECT  6.672 46.789 8.112 47.123 ;
     RECT  10.656 46.789 10.68 47.123 ;
     RECT  12.384 46.741 13.512 47.363 ;
     RECT  43.392 45.059 46.68 47.363 ;
     RECT  26.832 46.357 26.856 47.459 ;
     RECT  5.616 40.835 5.64 47.557 ;
     RECT  18.6 34.835 18.912 47.797 ;
     RECT  7.8 47.123 8.112 47.845 ;
     RECT  17.04 45.877 17.064 47.845 ;
     RECT  29.4 45.635 29.712 47.845 ;
     RECT  16.8 47.845 17.064 47.891 ;
     RECT  37.008 0.563 38.184 47.939 ;
     RECT  40.2 46.885 42.408 47.939 ;
     RECT  15.216 45.587 15.24 48.229 ;
     RECT  12.576 47.363 13.512 48.275 ;
     RECT  52.848 0.563 53.256 48.515 ;
     RECT  18.6 47.797 19.032 48.709 ;
     RECT  20.544 46.787 20.568 48.899 ;
     RECT  6.672 47.123 6.696 48.901 ;
     RECT  7.8 47.845 8.232 48.901 ;
     RECT  29.4 47.845 29.832 48.901 ;
     RECT  44.976 47.363 46.68 48.901 ;
     RECT  47.664 45.059 51.312 48.901 ;
     RECT  18.6 48.709 19.56 48.947 ;
     RECT  33.552 43.955 35.208 48.995 ;
     RECT  6.672 48.901 8.232 49.043 ;
     RECT  33.552 48.995 35.112 49.043 ;
     RECT  4.512 46.117 4.536 49.091 ;
     RECT  9.6 48.997 9.624 49.189 ;
     RECT  9.6 49.189 9.72 49.235 ;
     RECT  9.696 49.235 9.72 49.331 ;
     RECT  20.592 49.429 20.616 49.571 ;
     RECT  6.672 49.043 8.112 49.667 ;
     RECT  34.128 49.043 35.112 50.195 ;
     RECT  40.2 47.939 40.68 50.195 ;
     RECT  32.496 48.949 32.52 50.291 ;
     RECT  28.368 45.635 28.392 50.293 ;
     RECT  37.584 47.939 38.184 50.771 ;
     RECT  41.856 47.939 42.408 50.819 ;
     RECT  42.288 50.819 42.408 51.205 ;
     RECT  43.392 47.363 43.416 51.205 ;
     RECT  34.368 50.195 35.112 51.251 ;
     RECT  14.64 48.229 15.24 51.253 ;
     RECT  16.8 47.891 16.824 51.253 ;
     RECT  21.12 50.053 21.144 51.347 ;
     RECT  42.288 51.205 43.416 51.347 ;
     RECT  5.568 47.557 5.64 51.637 ;
     RECT  25.296 51.445 25.32 51.683 ;
     RECT  27.504 50.293 28.392 51.923 ;
     RECT  37.584 50.771 37.608 51.923 ;
     RECT  34.8 51.251 35.112 52.021 ;
     RECT  44.976 48.901 51.312 52.165 ;
     RECT  26.784 51.973 26.808 52.259 ;
     RECT  14.64 51.253 16.824 52.453 ;
     RECT  18.6 48.947 18.912 52.453 ;
     RECT  24 45.347 24.312 52.453 ;
     RECT  14.64 52.453 17.208 52.499 ;
     RECT  44.976 52.165 51.432 52.499 ;
     RECT  52.848 48.515 52.872 52.499 ;
     RECT  21.12 52.453 21.144 52.595 ;
     RECT  24 52.453 24.696 52.595 ;
     RECT  24 52.595 24.6 52.787 ;
     RECT  0.912 44.435 3.288 52.837 ;
     RECT  44.976 52.499 47.688 52.981 ;
     RECT  16.8 52.499 17.208 53.027 ;
     RECT  42.288 51.347 43.368 53.027 ;
     RECT  29.4 48.901 30.024 53.509 ;
     RECT  14.64 52.499 15.24 53.555 ;
     RECT  18.48 52.453 18.912 53.555 ;
     RECT  15.216 53.555 15.24 53.557 ;
     RECT  26.16 52.837 26.184 53.557 ;
     RECT  34.8 52.021 35.352 53.557 ;
     RECT  42.288 53.027 42.408 53.557 ;
     RECT  15.216 53.557 15.384 53.603 ;
     RECT  15.36 53.603 15.384 53.653 ;
     RECT  26.16 53.557 26.28 53.653 ;
     RECT  15.36 53.653 15.48 53.699 ;
     RECT  22.704 52.885 22.728 53.795 ;
     RECT  24 52.787 24.456 53.797 ;
     RECT  15.408 53.699 15.48 53.843 ;
     RECT  26.16 53.653 26.376 53.845 ;
     RECT  44.496 52.981 47.688 53.893 ;
     RECT  43.632 53.893 47.688 53.939 ;
     RECT  21.168 53.845 21.192 53.987 ;
     RECT  26.16 53.845 26.472 54.035 ;
     RECT  32.496 52.933 32.52 54.083 ;
     RECT  24 53.797 24.504 54.085 ;
     RECT  0.144 52.837 3.288 54.131 ;
     RECT  10.224 53.509 10.248 54.133 ;
     RECT  10.224 54.133 10.344 54.179 ;
     RECT  10.32 54.179 10.344 54.275 ;
     RECT  49.392 52.499 51.432 54.613 ;
     RECT  28.368 51.923 28.392 54.661 ;
     RECT  29.4 53.509 30.216 54.661 ;
     RECT  17.184 53.027 17.208 54.853 ;
     RECT  18.6 53.555 18.912 54.853 ;
     RECT  17.184 54.853 18.912 55.139 ;
     RECT  49.392 54.613 51.864 55.139 ;
     RECT  26.16 54.035 26.184 55.141 ;
     RECT  24 54.085 25.032 55.237 ;
     RECT  26.16 55.141 26.28 55.237 ;
     RECT  42.144 53.557 42.408 55.237 ;
     RECT  43.632 53.939 46.152 55.237 ;
     RECT  24 55.237 26.28 55.283 ;
     RECT  28.368 54.661 30.216 55.331 ;
     RECT  42.144 55.237 46.152 55.331 ;
     RECT  49.392 55.139 51.432 55.331 ;
     RECT  29.4 55.331 30.216 55.381 ;
     RECT  15.408 53.843 15.432 55.429 ;
     RECT  29.4 55.381 30.312 55.523 ;
     RECT  15.408 55.429 15.816 55.763 ;
     RECT  34.8 53.557 35.736 55.813 ;
     RECT  17.808 55.139 18.912 55.955 ;
     RECT  42.144 55.331 45.912 55.955 ;
     RECT  34.8 55.813 36.264 56.483 ;
     RECT  42.288 55.955 45.912 56.483 ;
     RECT  50.832 55.331 51.432 56.483 ;
     RECT  32.544 55.813 32.568 56.869 ;
     RECT  32.544 56.869 33.336 56.915 ;
     RECT  49.392 55.331 49.416 56.965 ;
     RECT  42.288 56.483 42.408 57.013 ;
     RECT  49.008 56.965 49.416 57.155 ;
     RECT  24 55.283 25.704 57.251 ;
     RECT  27.264 57.205 27.288 57.397 ;
     RECT  28.368 55.331 28.392 57.397 ;
     RECT  34.8 56.483 35.736 57.541 ;
     RECT  49.152 57.155 49.416 57.541 ;
     RECT  5.04 51.637 5.64 57.587 ;
     RECT  29.4 55.523 30.216 57.827 ;
     RECT  43.632 56.483 45.912 57.877 ;
     RECT  33.312 56.915 33.336 57.973 ;
     RECT  33.312 57.973 33.432 58.019 ;
     RECT  42.096 57.013 42.408 58.115 ;
     RECT  22.224 55.045 22.248 58.117 ;
     RECT  43.632 57.877 46.008 58.117 ;
     RECT  22.224 58.117 22.824 58.163 ;
     RECT  24 57.251 25.032 58.357 ;
     RECT  23.904 58.357 25.032 58.403 ;
     RECT  23.904 58.403 24.984 58.499 ;
     RECT  43.632 58.117 46.392 58.597 ;
     RECT  24 58.499 24.984 58.691 ;
     RECT  27.264 57.397 28.392 58.691 ;
     RECT  27.264 58.691 28.2 58.979 ;
     RECT  29.4 57.827 29.712 59.173 ;
     RECT  34.8 57.541 35.88 59.315 ;
     RECT  43.488 58.597 46.392 59.461 ;
     RECT  22.8 58.163 22.824 59.795 ;
     RECT  33.408 58.019 33.432 59.891 ;
     RECT  0.912 54.131 3.288 59.893 ;
     RECT  43.488 59.461 46.488 59.893 ;
     RECT  0.144 59.893 3.288 60.083 ;
     RECT  29.4 59.173 29.832 60.133 ;
     RECT  27.312 58.979 28.2 60.467 ;
     RECT  50.832 56.483 51.312 60.997 ;
     RECT  27.312 60.467 27.96 61.043 ;
     RECT  43.488 59.893 46.68 61.043 ;
     RECT  24 58.691 24.696 61.093 ;
     RECT  22.8 61.093 22.824 61.379 ;
     RECT  24 61.093 24.888 61.379 ;
     RECT  42.288 58.115 42.408 61.429 ;
     RECT  43.488 61.043 45.912 61.429 ;
     RECT  42.288 61.429 45.912 61.621 ;
     RECT  29.4 60.133 30.168 61.909 ;
     RECT  47.664 53.939 47.688 61.909 ;
     RECT  29.4 61.909 30.504 62.051 ;
     RECT  47.088 61.909 47.688 62.387 ;
     RECT  41.904 61.621 45.912 62.675 ;
     RECT  49.152 57.541 49.464 62.677 ;
     RECT  29.4 62.051 29.712 62.725 ;
     RECT  40.2 50.195 40.512 62.725 ;
     RECT  48.96 62.677 49.464 62.869 ;
     RECT  50.448 60.997 51.312 62.869 ;
     RECT  38.496 59.173 38.52 63.011 ;
     RECT  42.288 62.675 45.912 63.061 ;
     RECT  24 61.379 24.456 63.205 ;
     RECT  42.288 63.061 46.104 64.067 ;
     RECT  26.544 63.013 26.568 64.307 ;
     RECT  27.936 61.043 27.96 64.309 ;
     RECT  29.28 62.725 29.712 64.309 ;
     RECT  27.936 64.309 29.712 64.355 ;
     RECT  37.2 63.205 37.224 64.355 ;
     RECT  23.664 63.205 24.456 64.357 ;
     RECT  47.664 62.387 47.688 64.357 ;
     RECT  22.8 64.357 24.456 64.403 ;
     RECT  40.2 62.725 41.208 64.595 ;
     RECT  34.8 59.315 35.736 64.885 ;
     RECT  48.96 62.869 51.312 64.981 ;
     RECT  42.288 64.067 46.008 65.509 ;
     RECT  5.568 57.587 5.64 65.603 ;
     RECT  5.616 65.603 5.64 65.605 ;
     RECT  6.672 49.667 6.696 65.605 ;
     RECT  0.912 60.083 3.288 65.749 ;
     RECT  41.616 65.509 46.008 65.797 ;
     RECT  47.136 64.357 47.688 65.797 ;
     RECT  0.144 65.749 3.288 66.035 ;
     RECT  22.8 64.403 22.824 66.227 ;
     RECT  41.616 65.797 47.688 66.755 ;
     RECT  40.2 64.595 40.512 66.757 ;
     RECT  40.2 66.757 40.92 66.805 ;
     RECT  0.576 66.035 3.288 66.851 ;
     RECT  24 64.403 24.456 67.043 ;
     RECT  34.272 64.885 35.736 67.141 ;
     RECT  28.464 64.355 29.712 67.283 ;
     RECT  32.544 65.941 32.568 67.283 ;
     RECT  38.784 65.509 38.808 67.283 ;
     RECT  47.664 66.755 47.688 68.101 ;
     RECT  48.96 64.981 51.432 68.101 ;
     RECT  42.288 66.755 45.912 68.389 ;
     RECT  47.664 68.101 51.432 68.389 ;
     RECT  31.248 66.901 31.272 68.435 ;
     RECT  34.272 67.141 36.456 68.435 ;
     RECT  42.288 68.389 51.432 68.773 ;
     RECT  41.952 68.773 51.432 68.963 ;
     RECT  42.144 68.963 47.928 69.107 ;
     RECT  39.888 66.805 40.92 69.251 ;
     RECT  42.144 69.107 45.912 69.587 ;
     RECT  38.832 67.765 38.856 70.163 ;
     RECT  47.664 69.107 47.928 70.163 ;
     RECT  34.272 68.435 35.736 70.645 ;
     RECT  5.616 65.605 6.696 70.739 ;
     RECT  42.288 69.587 45.912 70.739 ;
     RECT  0.912 66.851 3.288 71.125 ;
     RECT  0.384 71.125 3.288 71.315 ;
     RECT  44.352 70.739 45.912 71.315 ;
     RECT  45.456 71.315 45.912 71.317 ;
     RECT  34.272 70.645 36.504 71.509 ;
     RECT  34.272 71.509 37.032 71.555 ;
     RECT  40.2 69.251 40.92 71.603 ;
     RECT  47.664 70.163 47.688 71.701 ;
     RECT  48.96 68.963 51.432 71.701 ;
     RECT  45.456 71.317 46.152 72.085 ;
     RECT  31.872 71.077 31.896 72.325 ;
     RECT  31.872 72.325 32.52 72.659 ;
     RECT  44.352 71.315 44.376 72.805 ;
     RECT  45.456 72.085 46.344 72.805 ;
     RECT  42.288 70.739 43.32 72.901 ;
     RECT  44.352 72.805 46.344 72.901 ;
     RECT  47.664 71.701 51.432 72.995 ;
     RECT  37.008 71.555 37.032 73.477 ;
     RECT  42.288 72.901 46.344 73.523 ;
     RECT  37.008 73.477 37.08 73.619 ;
     RECT  45.456 73.523 46.104 73.619 ;
     RECT  32.496 72.659 32.52 73.811 ;
     RECT  42.288 73.523 44.376 74.147 ;
     RECT  45.6 73.619 46.104 74.147 ;
     RECT  34.272 71.555 35.736 74.723 ;
     RECT  37.056 73.619 37.08 75.251 ;
     RECT  48.384 72.995 51.432 75.539 ;
     RECT  42.288 74.147 43.32 75.875 ;
     RECT  42.288 75.875 42.312 76.069 ;
     RECT  48.384 75.539 51.312 76.309 ;
     RECT  42.144 76.069 42.312 76.741 ;
     RECT  48.336 76.309 51.312 76.979 ;
     RECT  7.8 49.667 8.112 77.461 ;
     RECT  48.384 76.979 51.312 78.037 ;
     RECT  41.616 76.741 42.312 78.131 ;
     RECT  43.296 75.875 43.32 79.235 ;
     RECT  18.6 55.955 18.912 79.237 ;
     RECT  24 67.043 24.408 79.813 ;
     RECT  29.4 67.283 29.712 79.813 ;
     RECT  40.2 71.603 40.512 79.813 ;
     RECT  5.616 70.739 5.64 80.389 ;
     RECT  6.672 70.739 6.696 80.389 ;
     RECT  24 79.813 25.272 80.389 ;
     RECT  29.4 79.813 29.832 80.869 ;
     RECT  7.8 77.461 8.376 80.917 ;
     RECT  15.408 55.763 15.432 80.917 ;
     RECT  37.824 79.237 37.848 81.445 ;
     RECT  11.376 47.845 11.4 81.493 ;
     RECT  28.224 80.917 28.248 81.493 ;
     RECT  29.28 80.869 29.832 81.493 ;
     RECT  0.912 71.315 3.288 82.069 ;
     RECT  33.36 80.917 33.384 82.069 ;
     RECT  34.8 74.723 35.736 82.069 ;
     RECT  37.392 81.445 37.848 82.069 ;
     RECT  39.12 82.021 39.144 82.069 ;
     RECT  48.288 78.037 51.312 82.069 ;
     RECT  52.992 80.389 53.016 82.069 ;
     RECT  5.616 80.389 6.696 82.597 ;
     RECT  7.8 80.917 8.616 82.597 ;
     RECT  23.088 80.389 25.272 82.597 ;
     RECT  32.064 82.021 32.088 82.597 ;
     RECT  55.536 82.069 55.56 82.597 ;
     RECT  13.2 48.275 13.512 82.645 ;
     RECT  16.464 81.493 16.488 82.645 ;
     RECT  18.6 79.237 19.032 82.645 ;
     RECT  31.008 82.597 32.088 82.645 ;
     RECT  33.36 82.069 35.736 82.645 ;
     RECT  44.352 74.147 44.376 82.691 ;
     RECT  5.616 82.597 8.616 83.221 ;
     RECT  12.624 82.645 13.512 83.221 ;
     RECT  16.464 82.645 17.352 83.221 ;
     RECT  18.6 82.645 19.272 83.221 ;
     RECT  20.736 80.389 20.76 83.221 ;
     RECT  22.272 82.597 25.272 83.221 ;
     RECT  37.392 82.069 39.144 83.221 ;
     RECT  40.2 79.813 41.064 83.221 ;
     RECT  26.928 83.221 26.952 83.749 ;
     RECT  28.224 81.493 29.832 83.749 ;
     RECT  0.912 82.069 3.912 83.797 ;
     RECT  4.944 83.221 8.616 83.797 ;
     RECT  31.008 82.645 35.736 83.797 ;
     RECT  36.96 83.221 41.064 83.797 ;
     RECT  42.96 83.173 42.984 83.845 ;
     RECT  45.6 74.147 45.912 84.181 ;
     RECT  44.016 83.749 44.04 84.229 ;
     RECT  45.6 84.181 46.632 84.229 ;
     RECT  0.912 83.797 8.616 84.263 ;
     RECT  42.528 83.845 42.984 84.277 ;
     RECT  44.016 84.229 46.632 84.277 ;
     RECT  26.928 83.749 29.832 84.325 ;
     RECT  42.528 84.277 47.256 84.325 ;
     RECT  48.288 82.069 53.016 84.325 ;
     RECT  10.704 81.493 11.4 84.373 ;
     RECT  16.464 83.221 19.272 84.373 ;
     RECT  20.736 83.221 25.272 84.373 ;
     RECT  42.096 84.325 53.016 84.373 ;
     RECT  54.72 82.597 55.56 84.373 ;
     RECT  10.512 84.373 11.4 84.901 ;
     RECT  12.624 83.221 13.944 84.901 ;
     RECT  26.928 84.325 29.976 84.901 ;
     RECT  16.464 84.373 25.272 84.949 ;
     RECT  26.304 84.901 29.976 84.949 ;
     RECT  31.008 83.797 41.064 84.949 ;
     RECT  0.912 84.263 7.32 85.477 ;
     RECT  8.352 84.263 8.616 85.477 ;
     RECT  10.512 84.901 13.944 85.477 ;
     RECT  14.976 80.917 15.432 85.477 ;
     RECT  16.464 84.949 41.064 85.477 ;
     RECT  42.096 84.373 55.56 85.477 ;
     RECT  0.912 85.477 8.616 86.245 ;
     RECT  9.648 85.477 55.56 86.245 ;
     RECT  0.672 86.245 55.56 86.352 ;
  END
END qfd_c_xstnw
END LIBRARY
